VERSION 5.8 ;
BUSBITCHARS "[]" ;
DIVIDERCHAR "/" ;
UNITS
    DATABASE MICRONS 1000 ;
END UNITS

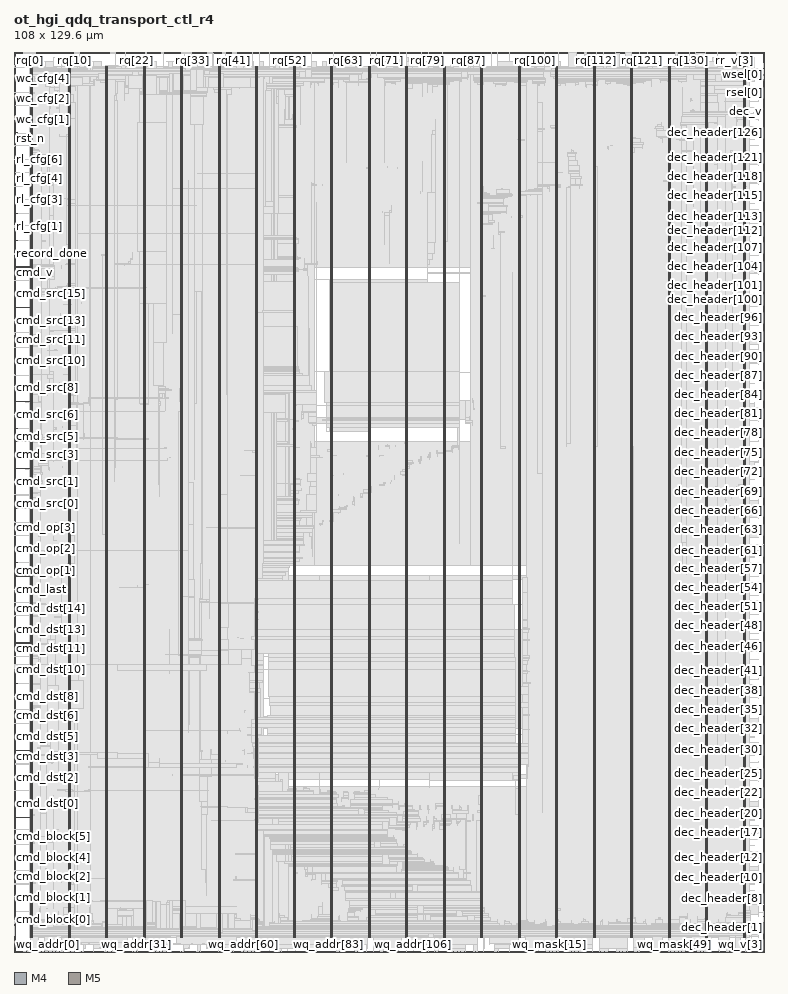
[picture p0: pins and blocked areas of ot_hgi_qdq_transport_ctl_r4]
MACRO ot_hgi_qdq_transport_ctl_r4
  FOREIGN ot_hgi_qdq_transport_ctl_r4 0 0 ;
  CLASS BLOCK ;
  SIZE 108 BY 129.6 ;
  PIN beat_done
    DIRECTION OUTPUT ;
    USE SIGNAL ;
    PORT
      LAYER M4 ;
        RECT  0 1.968 0.084 1.992 ;
    END
    PORT
      LAYER M4 ;
        RECT  0.06 1.968 0.137 2.28 ;
    END
  END beat_done
  PIN clk
    DIRECTION INPUT ;
    USE SIGNAL ;
    PORT
      LAYER M4 ;
        RECT  0 3.888 0.084 3.912 ;
    END
    PORT
      LAYER M4 ;
        RECT  0.06 3.888 0.179 3.912 ;
    END
  END clk
  PIN cmd_block[0]
    DIRECTION INPUT ;
    USE SIGNAL ;
    PORT
      LAYER M4 ;
        RECT  0 5.808 0.084 5.832 ;
    END
    PORT
      LAYER M4 ;
        RECT  0.06 5.808 0.173 5.832 ;
    END
  END cmd_block[0]
  PIN cmd_block[1]
    DIRECTION INPUT ;
    USE SIGNAL ;
    PORT
      LAYER M4 ;
        RECT  0 7.776 0.084 7.8 ;
    END
    PORT
      LAYER M4 ;
        RECT  0.06 7.776 0.137 7.8 ;
    END
  END cmd_block[1]
  PIN cmd_block[2]
    DIRECTION INPUT ;
    USE SIGNAL ;
    PORT
      LAYER M4 ;
        RECT  0 9.696 0.084 9.72 ;
    END
    PORT
      LAYER M4 ;
        RECT  0.06 9.696 0.137 9.72 ;
    END
  END cmd_block[2]
  PIN cmd_block[3]
    DIRECTION INPUT ;
    USE SIGNAL ;
    PORT
      LAYER M4 ;
        RECT  0 11.616 0.084 11.64 ;
    END
    PORT
      LAYER M4 ;
        RECT  0.06 11.616 0.137 11.64 ;
    END
  END cmd_block[3]
  PIN cmd_block[4]
    DIRECTION INPUT ;
    USE SIGNAL ;
    PORT
      LAYER M4 ;
        RECT  0 13.536 0.084 13.56 ;
    END
    PORT
      LAYER M4 ;
        RECT  0.06 13.536 0.137 13.56 ;
    END
  END cmd_block[4]
  PIN cmd_block[5]
    DIRECTION INPUT ;
    USE SIGNAL ;
    PORT
      LAYER M4 ;
        RECT  0 15.504 0.084 15.528 ;
    END
    PORT
      LAYER M4 ;
        RECT  0.06 15.504 0.137 15.528 ;
    END
  END cmd_block[5]
  PIN cmd_block[6]
    DIRECTION INPUT ;
    USE SIGNAL ;
    PORT
      LAYER M4 ;
        RECT  0 17.424 0.084 17.448 ;
    END
    PORT
      LAYER M4 ;
        RECT  0.06 17.424 0.137 17.448 ;
    END
  END cmd_block[6]
  PIN cmd_block[7]
    DIRECTION INPUT ;
    USE SIGNAL ;
    PORT
      LAYER M4 ;
        RECT  0 19.344 0.084 19.368 ;
    END
    PORT
      LAYER M4 ;
        RECT  0.06 19.344 2.408 19.368 ;
    END
  END cmd_block[7]
  PIN cmd_dst[0]
    DIRECTION INPUT ;
    USE SIGNAL ;
    PORT
      LAYER M4 ;
        RECT  0 21.312 0.084 21.336 ;
    END
    PORT
      LAYER M4 ;
        RECT  0.06 21.312 0.137 21.336 ;
    END
  END cmd_dst[0]
  PIN cmd_dst[10]
    DIRECTION INPUT ;
    USE SIGNAL ;
    PORT
      LAYER M4 ;
        RECT  0 40.608 0.084 40.632 ;
    END
    PORT
      LAYER M4 ;
        RECT  0.06 40.608 0.133 40.632 ;
    END
  END cmd_dst[10]
  PIN cmd_dst[11]
    DIRECTION INPUT ;
    USE SIGNAL ;
    PORT
      LAYER M4 ;
        RECT  0 42.576 0.084 42.6 ;
    END
    PORT
      LAYER M4 ;
        RECT  0.06 42.576 0.137 42.6 ;
    END
  END cmd_dst[11]
  PIN cmd_dst[12]
    DIRECTION INPUT ;
    USE SIGNAL ;
    PORT
      LAYER M4 ;
        RECT  0 44.496 0.084 44.52 ;
    END
    PORT
      LAYER M4 ;
        RECT  0.06 44.496 2.408 44.52 ;
    END
  END cmd_dst[12]
  PIN cmd_dst[13]
    DIRECTION INPUT ;
    USE SIGNAL ;
    PORT
      LAYER M4 ;
        RECT  0 46.416 0.084 46.44 ;
    END
    PORT
      LAYER M4 ;
        RECT  0.06 46.416 0.137 46.44 ;
    END
  END cmd_dst[13]
  PIN cmd_dst[14]
    DIRECTION INPUT ;
    USE SIGNAL ;
    PORT
      LAYER M4 ;
        RECT  0 48.336 0.084 48.36 ;
    END
    PORT
      LAYER M4 ;
        RECT  0.06 48.336 0.137 48.36 ;
    END
  END cmd_dst[14]
  PIN cmd_dst[15]
    DIRECTION INPUT ;
    USE SIGNAL ;
    PORT
      LAYER M4 ;
        RECT  0 50.304 0.084 50.328 ;
    END
    PORT
      LAYER M4 ;
        RECT  0.06 50.304 0.137 50.328 ;
    END
  END cmd_dst[15]
  PIN cmd_dst[1]
    DIRECTION INPUT ;
    USE SIGNAL ;
    PORT
      LAYER M4 ;
        RECT  0 23.232 0.084 23.256 ;
    END
    PORT
      LAYER M4 ;
        RECT  0.06 23.232 0.137 23.256 ;
    END
  END cmd_dst[1]
  PIN cmd_dst[2]
    DIRECTION INPUT ;
    USE SIGNAL ;
    PORT
      LAYER M4 ;
        RECT  0 25.152 0.084 25.176 ;
    END
    PORT
      LAYER M4 ;
        RECT  0.06 25.152 0.137 25.176 ;
    END
  END cmd_dst[2]
  PIN cmd_dst[3]
    DIRECTION INPUT ;
    USE SIGNAL ;
    PORT
      LAYER M4 ;
        RECT  0 27.072 0.084 27.096 ;
    END
    PORT
      LAYER M4 ;
        RECT  0.06 27.072 0.137 27.096 ;
    END
  END cmd_dst[3]
  PIN cmd_dst[4]
    DIRECTION INPUT ;
    USE SIGNAL ;
    PORT
      LAYER M4 ;
        RECT  0 29.04 0.084 29.064 ;
    END
    PORT
      LAYER M4 ;
        RECT  0.06 29.04 2.408 29.064 ;
    END
  END cmd_dst[4]
  PIN cmd_dst[5]
    DIRECTION INPUT ;
    USE SIGNAL ;
    PORT
      LAYER M4 ;
        RECT  0 30.96 0.084 30.984 ;
    END
    PORT
      LAYER M4 ;
        RECT  0.06 30.96 0.137 30.984 ;
    END
  END cmd_dst[5]
  PIN cmd_dst[6]
    DIRECTION INPUT ;
    USE SIGNAL ;
    PORT
      LAYER M4 ;
        RECT  0 32.88 0.084 32.904 ;
    END
    PORT
      LAYER M4 ;
        RECT  0.06 32.88 0.137 32.904 ;
    END
  END cmd_dst[6]
  PIN cmd_dst[7]
    DIRECTION INPUT ;
    USE SIGNAL ;
    PORT
      LAYER M4 ;
        RECT  0 34.8 0.084 34.824 ;
    END
    PORT
      LAYER M4 ;
        RECT  0.06 34.8 0.137 34.824 ;
    END
  END cmd_dst[7]
  PIN cmd_dst[8]
    DIRECTION INPUT ;
    USE SIGNAL ;
    PORT
      LAYER M4 ;
        RECT  0 36.768 0.084 36.792 ;
    END
    PORT
      LAYER M4 ;
        RECT  0.06 36.768 0.137 36.792 ;
    END
  END cmd_dst[8]
  PIN cmd_dst[9]
    DIRECTION INPUT ;
    USE SIGNAL ;
    PORT
      LAYER M4 ;
        RECT  0 38.688 0.084 38.712 ;
    END
    PORT
      LAYER M4 ;
        RECT  0.06 38.688 0.569 38.712 ;
    END
  END cmd_dst[9]
  PIN cmd_last
    DIRECTION INPUT ;
    USE SIGNAL ;
    PORT
      LAYER M4 ;
        RECT  0 52.224 0.084 52.248 ;
    END
    PORT
      LAYER M4 ;
        RECT  0.06 52.224 0.137 52.248 ;
    END
  END cmd_last
  PIN cmd_op[0]
    DIRECTION INPUT ;
    USE SIGNAL ;
    PORT
      LAYER M4 ;
        RECT  0 54.144 0.084 54.168 ;
    END
    PORT
      LAYER M4 ;
        RECT  0.06 54.144 2.408 54.168 ;
    END
  END cmd_op[0]
  PIN cmd_op[1]
    DIRECTION INPUT ;
    USE SIGNAL ;
    PORT
      LAYER M4 ;
        RECT  0 56.112 0.084 56.136 ;
    END
    PORT
      LAYER M4 ;
        RECT  0.06 56.112 0.569 56.136 ;
    END
  END cmd_op[1]
  PIN cmd_op[2]
    DIRECTION INPUT ;
    USE SIGNAL ;
    PORT
      LAYER M4 ;
        RECT  0 58.032 0.084 58.056 ;
    END
    PORT
      LAYER M4 ;
        RECT  0.06 58.032 0.137 58.056 ;
    END
  END cmd_op[2]
  PIN cmd_op[3]
    DIRECTION INPUT ;
    USE SIGNAL ;
    PORT
      LAYER M4 ;
        RECT  0 59.952 0.084 59.976 ;
    END
    PORT
      LAYER M4 ;
        RECT  0.06 59.952 0.137 59.976 ;
    END
  END cmd_op[3]
  PIN cmd_op[4]
    DIRECTION INPUT ;
    USE SIGNAL ;
    PORT
      LAYER M4 ;
        RECT  0 61.872 0.084 61.896 ;
    END
    PORT
      LAYER M4 ;
        RECT  0.06 61.872 0.137 61.896 ;
    END
  END cmd_op[4]
  PIN cmd_op[5]
    DIRECTION INPUT ;
    USE SIGNAL ;
    PORT
      LAYER M4 ;
        RECT  0 63.84 0.084 63.864 ;
    END
    PORT
      LAYER M4 ;
        RECT  0.06 63.84 2.408 63.864 ;
    END
  END cmd_op[5]
  PIN cmd_src[0]
    DIRECTION INPUT ;
    USE SIGNAL ;
    PORT
      LAYER M4 ;
        RECT  0 65.76 0.084 65.784 ;
    END
    PORT
      LAYER M4 ;
        RECT  0.06 65.76 0.173 65.784 ;
    END
  END cmd_src[0]
  PIN cmd_src[10]
    DIRECTION INPUT ;
    USE SIGNAL ;
    PORT
      LAYER M4 ;
        RECT  0 85.104 0.084 85.128 ;
    END
    PORT
      LAYER M4 ;
        RECT  0.06 85.104 0.137 85.128 ;
    END
  END cmd_src[10]
  PIN cmd_src[11]
    DIRECTION INPUT ;
    USE SIGNAL ;
    PORT
      LAYER M4 ;
        RECT  0 87.024 0.084 87.048 ;
    END
    PORT
      LAYER M4 ;
        RECT  0.06 87.024 0.137 87.048 ;
    END
  END cmd_src[11]
  PIN cmd_src[12]
    DIRECTION INPUT ;
    USE SIGNAL ;
    PORT
      LAYER M4 ;
        RECT  0 88.944 0.084 88.968 ;
    END
    PORT
      LAYER M4 ;
        RECT  0.06 88.944 0.137 88.968 ;
    END
  END cmd_src[12]
  PIN cmd_src[13]
    DIRECTION INPUT ;
    USE SIGNAL ;
    PORT
      LAYER M4 ;
        RECT  0 90.912 0.084 90.936 ;
    END
    PORT
      LAYER M4 ;
        RECT  0.06 90.912 0.137 90.936 ;
    END
  END cmd_src[13]
  PIN cmd_src[14]
    DIRECTION INPUT ;
    USE SIGNAL ;
    PORT
      LAYER M4 ;
        RECT  0 92.832 0.084 92.856 ;
    END
    PORT
      LAYER M4 ;
        RECT  0.06 92.832 2.408 92.856 ;
    END
  END cmd_src[14]
  PIN cmd_src[15]
    DIRECTION INPUT ;
    USE SIGNAL ;
    PORT
      LAYER M4 ;
        RECT  0 94.752 0.084 94.776 ;
    END
    PORT
      LAYER M4 ;
        RECT  0.06 94.752 0.137 94.776 ;
    END
  END cmd_src[15]
  PIN cmd_src[1]
    DIRECTION INPUT ;
    USE SIGNAL ;
    PORT
      LAYER M4 ;
        RECT  0 67.68 0.084 67.704 ;
    END
    PORT
      LAYER M4 ;
        RECT  0.06 67.68 0.137 67.704 ;
    END
  END cmd_src[1]
  PIN cmd_src[2]
    DIRECTION INPUT ;
    USE SIGNAL ;
    PORT
      LAYER M4 ;
        RECT  0 69.6 0.084 69.624 ;
    END
    PORT
      LAYER M4 ;
        RECT  0.06 69.6 2.365 69.624 ;
    END
  END cmd_src[2]
  PIN cmd_src[3]
    DIRECTION INPUT ;
    USE SIGNAL ;
    PORT
      LAYER M4 ;
        RECT  0 71.568 0.084 71.592 ;
    END
    PORT
      LAYER M4 ;
        RECT  0.06 71.568 0.137 71.592 ;
    END
  END cmd_src[3]
  PIN cmd_src[4]
    DIRECTION INPUT ;
    USE SIGNAL ;
    PORT
      LAYER M4 ;
        RECT  0 73.488 0.084 73.512 ;
    END
    PORT
      LAYER M4 ;
        RECT  0.06 73.488 2.408 73.512 ;
    END
  END cmd_src[4]
  PIN cmd_src[5]
    DIRECTION INPUT ;
    USE SIGNAL ;
    PORT
      LAYER M4 ;
        RECT  0 75.408 0.084 75.432 ;
    END
    PORT
      LAYER M4 ;
        RECT  0.06 75.408 0.569 75.432 ;
    END
  END cmd_src[5]
  PIN cmd_src[6]
    DIRECTION INPUT ;
    USE SIGNAL ;
    PORT
      LAYER M4 ;
        RECT  0 77.376 0.084 77.4 ;
    END
    PORT
      LAYER M4 ;
        RECT  0.06 77.376 0.137 77.4 ;
    END
  END cmd_src[6]
  PIN cmd_src[7]
    DIRECTION INPUT ;
    USE SIGNAL ;
    PORT
      LAYER M4 ;
        RECT  0 79.296 0.084 79.32 ;
    END
    PORT
      LAYER M4 ;
        RECT  0.06 79.296 2.408 79.32 ;
    END
  END cmd_src[7]
  PIN cmd_src[8]
    DIRECTION INPUT ;
    USE SIGNAL ;
    PORT
      LAYER M4 ;
        RECT  0 81.216 0.084 81.24 ;
    END
    PORT
      LAYER M4 ;
        RECT  0.06 81.216 0.137 81.24 ;
    END
  END cmd_src[8]
  PIN cmd_src[9]
    DIRECTION INPUT ;
    USE SIGNAL ;
    PORT
      LAYER M4 ;
        RECT  0 83.136 0.084 83.16 ;
    END
    PORT
      LAYER M4 ;
        RECT  0.06 83.136 0.137 83.16 ;
    END
  END cmd_src[9]
  PIN cmd_v
    DIRECTION INPUT ;
    USE SIGNAL ;
    PORT
      LAYER M4 ;
        RECT  0 96.672 0.084 96.696 ;
    END
    PORT
      LAYER M4 ;
        RECT  0.06 96.672 0.137 96.696 ;
    END
  END cmd_v
  PIN dec_header[0]
    DIRECTION OUTPUT ;
    USE SIGNAL ;
    PORT
      LAYER M4 ;
        RECT  107.916 1.44 108 1.464 ;
    END
  END dec_header[0]
  PIN dec_header[100]
    DIRECTION OUTPUT ;
    USE SIGNAL ;
    PORT
      LAYER M4 ;
        RECT  107.916 93.936 108 93.96 ;
    END
  END dec_header[100]
  PIN dec_header[101]
    DIRECTION OUTPUT ;
    USE SIGNAL ;
    PORT
      LAYER M4 ;
        RECT  107.916 94.848 108 94.872 ;
    END
  END dec_header[101]
  PIN dec_header[102]
    DIRECTION OUTPUT ;
    USE SIGNAL ;
    PORT
      LAYER M4 ;
        RECT  107.916 95.76 108 95.784 ;
    END
  END dec_header[102]
  PIN dec_header[103]
    DIRECTION OUTPUT ;
    USE SIGNAL ;
    PORT
      LAYER M4 ;
        RECT  107.916 96.672 108 96.696 ;
    END
  END dec_header[103]
  PIN dec_header[104]
    DIRECTION OUTPUT ;
    USE SIGNAL ;
    PORT
      LAYER M4 ;
        RECT  107.916 97.632 108 97.656 ;
    END
  END dec_header[104]
  PIN dec_header[105]
    DIRECTION OUTPUT ;
    USE SIGNAL ;
    PORT
      LAYER M4 ;
        RECT  107.916 98.544 108 98.568 ;
    END
  END dec_header[105]
  PIN dec_header[106]
    DIRECTION OUTPUT ;
    USE SIGNAL ;
    PORT
      LAYER M4 ;
        RECT  107.916 99.456 108 99.48 ;
    END
  END dec_header[106]
  PIN dec_header[107]
    DIRECTION OUTPUT ;
    USE SIGNAL ;
    PORT
      LAYER M4 ;
        RECT  107.916 100.368 108 100.392 ;
    END
  END dec_header[107]
  PIN dec_header[108]
    DIRECTION OUTPUT ;
    USE SIGNAL ;
    PORT
      LAYER M4 ;
        RECT  107.916 101.328 108 101.352 ;
    END
  END dec_header[108]
  PIN dec_header[109]
    DIRECTION OUTPUT ;
    USE SIGNAL ;
    PORT
      LAYER M4 ;
        RECT  107.916 102.24 108 102.264 ;
    END
  END dec_header[109]
  PIN dec_header[10]
    DIRECTION OUTPUT ;
    USE SIGNAL ;
    PORT
      LAYER M4 ;
        RECT  107.916 10.704 108 10.728 ;
    END
  END dec_header[10]
  PIN dec_header[110]
    DIRECTION OUTPUT ;
    USE SIGNAL ;
    PORT
      LAYER M4 ;
        RECT  107.916 103.152 108 103.176 ;
    END
  END dec_header[110]
  PIN dec_header[111]
    DIRECTION OUTPUT ;
    USE SIGNAL ;
    PORT
      LAYER M4 ;
        RECT  107.916 104.064 108 104.088 ;
    END
  END dec_header[111]
  PIN dec_header[112]
    DIRECTION OUTPUT ;
    USE SIGNAL ;
    PORT
      LAYER M4 ;
        RECT  107.916 105.024 108 105.048 ;
    END
  END dec_header[112]
  PIN dec_header[113]
    DIRECTION OUTPUT ;
    USE SIGNAL ;
    PORT
      LAYER M4 ;
        RECT  107.916 105.936 108 105.96 ;
    END
  END dec_header[113]
  PIN dec_header[114]
    DIRECTION OUTPUT ;
    USE SIGNAL ;
    PORT
      LAYER M4 ;
        RECT  107.916 106.848 108 106.872 ;
    END
  END dec_header[114]
  PIN dec_header[115]
    DIRECTION OUTPUT ;
    USE SIGNAL ;
    PORT
      LAYER M4 ;
        RECT  107.916 107.808 108 107.832 ;
    END
  END dec_header[115]
  PIN dec_header[116]
    DIRECTION OUTPUT ;
    USE SIGNAL ;
    PORT
      LAYER M4 ;
        RECT  107.916 108.72 108 108.744 ;
    END
  END dec_header[116]
  PIN dec_header[117]
    DIRECTION OUTPUT ;
    USE SIGNAL ;
    PORT
      LAYER M4 ;
        RECT  107.916 109.632 108 109.656 ;
    END
  END dec_header[117]
  PIN dec_header[118]
    DIRECTION OUTPUT ;
    USE SIGNAL ;
    PORT
      LAYER M4 ;
        RECT  107.916 110.544 108 110.568 ;
    END
  END dec_header[118]
  PIN dec_header[119]
    DIRECTION OUTPUT ;
    USE SIGNAL ;
    PORT
      LAYER M4 ;
        RECT  107.916 111.504 108 111.528 ;
    END
  END dec_header[119]
  PIN dec_header[11]
    DIRECTION OUTPUT ;
    USE SIGNAL ;
    PORT
      LAYER M4 ;
        RECT  107.916 11.616 108 11.64 ;
    END
  END dec_header[11]
  PIN dec_header[120]
    DIRECTION OUTPUT ;
    USE SIGNAL ;
    PORT
      LAYER M4 ;
        RECT  107.916 112.416 108 112.44 ;
    END
  END dec_header[120]
  PIN dec_header[121]
    DIRECTION OUTPUT ;
    USE SIGNAL ;
    PORT
      LAYER M4 ;
        RECT  107.916 113.328 108 113.352 ;
    END
  END dec_header[121]
  PIN dec_header[122]
    DIRECTION OUTPUT ;
    USE SIGNAL ;
    PORT
      LAYER M4 ;
        RECT  107.916 114.24 108 114.264 ;
    END
  END dec_header[122]
  PIN dec_header[123]
    DIRECTION OUTPUT ;
    USE SIGNAL ;
    PORT
      LAYER M4 ;
        RECT  107.916 115.2 108 115.224 ;
    END
  END dec_header[123]
  PIN dec_header[124]
    DIRECTION OUTPUT ;
    USE SIGNAL ;
    PORT
      LAYER M4 ;
        RECT  107.916 116.112 108 116.136 ;
    END
  END dec_header[124]
  PIN dec_header[125]
    DIRECTION OUTPUT ;
    USE SIGNAL ;
    PORT
      LAYER M4 ;
        RECT  107.916 117.024 108 117.048 ;
    END
  END dec_header[125]
  PIN dec_header[126]
    DIRECTION OUTPUT ;
    USE SIGNAL ;
    PORT
      LAYER M4 ;
        RECT  107.916 117.936 108 117.96 ;
    END
  END dec_header[126]
  PIN dec_header[127]
    DIRECTION OUTPUT ;
    USE SIGNAL ;
    PORT
      LAYER M4 ;
        RECT  107.916 118.896 108 118.92 ;
    END
  END dec_header[127]
  PIN dec_header[12]
    DIRECTION OUTPUT ;
    USE SIGNAL ;
    PORT
      LAYER M4 ;
        RECT  107.916 12.528 108 12.552 ;
    END
  END dec_header[12]
  PIN dec_header[13]
    DIRECTION OUTPUT ;
    USE SIGNAL ;
    PORT
      LAYER M4 ;
        RECT  107.916 13.488 108 13.512 ;
    END
  END dec_header[13]
  PIN dec_header[14]
    DIRECTION OUTPUT ;
    USE SIGNAL ;
    PORT
      LAYER M4 ;
        RECT  107.916 14.4 108 14.424 ;
    END
  END dec_header[14]
  PIN dec_header[15]
    DIRECTION OUTPUT ;
    USE SIGNAL ;
    PORT
      LAYER M4 ;
        RECT  107.916 15.312 108 15.336 ;
    END
  END dec_header[15]
  PIN dec_header[16]
    DIRECTION OUTPUT ;
    USE SIGNAL ;
    PORT
      LAYER M4 ;
        RECT  107.916 16.224 108 16.248 ;
    END
  END dec_header[16]
  PIN dec_header[17]
    DIRECTION OUTPUT ;
    USE SIGNAL ;
    PORT
      LAYER M4 ;
        RECT  107.916 17.184 108 17.208 ;
    END
  END dec_header[17]
  PIN dec_header[18]
    DIRECTION OUTPUT ;
    USE SIGNAL ;
    PORT
      LAYER M4 ;
        RECT  107.916 18.096 108 18.12 ;
    END
  END dec_header[18]
  PIN dec_header[19]
    DIRECTION OUTPUT ;
    USE SIGNAL ;
    PORT
      LAYER M4 ;
        RECT  107.916 19.008 108 19.032 ;
    END
  END dec_header[19]
  PIN dec_header[1]
    DIRECTION OUTPUT ;
    USE SIGNAL ;
    PORT
      LAYER M4 ;
        RECT  107.916 2.352 108 2.376 ;
    END
  END dec_header[1]
  PIN dec_header[20]
    DIRECTION OUTPUT ;
    USE SIGNAL ;
    PORT
      LAYER M4 ;
        RECT  107.916 19.92 108 19.944 ;
    END
  END dec_header[20]
  PIN dec_header[21]
    DIRECTION OUTPUT ;
    USE SIGNAL ;
    PORT
      LAYER M4 ;
        RECT  107.916 20.88 108 20.904 ;
    END
  END dec_header[21]
  PIN dec_header[22]
    DIRECTION OUTPUT ;
    USE SIGNAL ;
    PORT
      LAYER M4 ;
        RECT  107.916 21.792 108 21.816 ;
    END
  END dec_header[22]
  PIN dec_header[23]
    DIRECTION OUTPUT ;
    USE SIGNAL ;
    PORT
      LAYER M4 ;
        RECT  107.916 22.704 108 22.728 ;
    END
  END dec_header[23]
  PIN dec_header[24]
    DIRECTION OUTPUT ;
    USE SIGNAL ;
    PORT
      LAYER M4 ;
        RECT  107.916 23.664 108 23.688 ;
    END
  END dec_header[24]
  PIN dec_header[25]
    DIRECTION OUTPUT ;
    USE SIGNAL ;
    PORT
      LAYER M4 ;
        RECT  107.916 24.576 108 24.6 ;
    END
  END dec_header[25]
  PIN dec_header[26]
    DIRECTION OUTPUT ;
    USE SIGNAL ;
    PORT
      LAYER M4 ;
        RECT  107.916 25.488 108 25.512 ;
    END
  END dec_header[26]
  PIN dec_header[27]
    DIRECTION OUTPUT ;
    USE SIGNAL ;
    PORT
      LAYER M4 ;
        RECT  107.916 26.4 108 26.424 ;
    END
  END dec_header[27]
  PIN dec_header[28]
    DIRECTION OUTPUT ;
    USE SIGNAL ;
    PORT
      LAYER M4 ;
        RECT  107.916 27.36 108 27.384 ;
    END
  END dec_header[28]
  PIN dec_header[29]
    DIRECTION OUTPUT ;
    USE SIGNAL ;
    PORT
      LAYER M4 ;
        RECT  107.916 28.272 108 28.296 ;
    END
  END dec_header[29]
  PIN dec_header[2]
    DIRECTION OUTPUT ;
    USE SIGNAL ;
    PORT
      LAYER M4 ;
        RECT  107.916 3.312 108 3.336 ;
    END
  END dec_header[2]
  PIN dec_header[30]
    DIRECTION OUTPUT ;
    USE SIGNAL ;
    PORT
      LAYER M4 ;
        RECT  107.916 29.184 108 29.208 ;
    END
  END dec_header[30]
  PIN dec_header[31]
    DIRECTION OUTPUT ;
    USE SIGNAL ;
    PORT
      LAYER M4 ;
        RECT  107.916 30.096 108 30.12 ;
    END
  END dec_header[31]
  PIN dec_header[32]
    DIRECTION OUTPUT ;
    USE SIGNAL ;
    PORT
      LAYER M4 ;
        RECT  107.916 31.056 108 31.08 ;
    END
  END dec_header[32]
  PIN dec_header[33]
    DIRECTION OUTPUT ;
    USE SIGNAL ;
    PORT
      LAYER M4 ;
        RECT  107.916 31.968 108 31.992 ;
    END
  END dec_header[33]
  PIN dec_header[34]
    DIRECTION OUTPUT ;
    USE SIGNAL ;
    PORT
      LAYER M4 ;
        RECT  107.916 32.88 108 32.904 ;
    END
  END dec_header[34]
  PIN dec_header[35]
    DIRECTION OUTPUT ;
    USE SIGNAL ;
    PORT
      LAYER M4 ;
        RECT  107.916 33.792 108 33.816 ;
    END
  END dec_header[35]
  PIN dec_header[36]
    DIRECTION OUTPUT ;
    USE SIGNAL ;
    PORT
      LAYER M4 ;
        RECT  107.916 34.752 108 34.776 ;
    END
  END dec_header[36]
  PIN dec_header[37]
    DIRECTION OUTPUT ;
    USE SIGNAL ;
    PORT
      LAYER M4 ;
        RECT  107.916 35.664 108 35.688 ;
    END
  END dec_header[37]
  PIN dec_header[38]
    DIRECTION OUTPUT ;
    USE SIGNAL ;
    PORT
      LAYER M4 ;
        RECT  107.916 36.576 108 36.6 ;
    END
  END dec_header[38]
  PIN dec_header[39]
    DIRECTION OUTPUT ;
    USE SIGNAL ;
    PORT
      LAYER M4 ;
        RECT  107.916 37.488 108 37.512 ;
    END
  END dec_header[39]
  PIN dec_header[3]
    DIRECTION OUTPUT ;
    USE SIGNAL ;
    PORT
      LAYER M4 ;
        RECT  107.916 4.224 108 4.248 ;
    END
  END dec_header[3]
  PIN dec_header[40]
    DIRECTION OUTPUT ;
    USE SIGNAL ;
    PORT
      LAYER M4 ;
        RECT  107.916 38.448 108 38.472 ;
    END
  END dec_header[40]
  PIN dec_header[41]
    DIRECTION OUTPUT ;
    USE SIGNAL ;
    PORT
      LAYER M4 ;
        RECT  107.916 39.36 108 39.384 ;
    END
  END dec_header[41]
  PIN dec_header[42]
    DIRECTION OUTPUT ;
    USE SIGNAL ;
    PORT
      LAYER M4 ;
        RECT  107.916 40.272 108 40.296 ;
    END
  END dec_header[42]
  PIN dec_header[43]
    DIRECTION OUTPUT ;
    USE SIGNAL ;
    PORT
      LAYER M4 ;
        RECT  107.916 41.232 108 41.256 ;
    END
  END dec_header[43]
  PIN dec_header[44]
    DIRECTION OUTPUT ;
    USE SIGNAL ;
    PORT
      LAYER M4 ;
        RECT  107.916 42.144 108 42.168 ;
    END
  END dec_header[44]
  PIN dec_header[45]
    DIRECTION OUTPUT ;
    USE SIGNAL ;
    PORT
      LAYER M4 ;
        RECT  107.916 43.056 108 43.08 ;
    END
  END dec_header[45]
  PIN dec_header[46]
    DIRECTION OUTPUT ;
    USE SIGNAL ;
    PORT
      LAYER M4 ;
        RECT  107.916 43.968 108 43.992 ;
    END
  END dec_header[46]
  PIN dec_header[47]
    DIRECTION OUTPUT ;
    USE SIGNAL ;
    PORT
      LAYER M4 ;
        RECT  107.916 44.928 108 44.952 ;
    END
  END dec_header[47]
  PIN dec_header[48]
    DIRECTION OUTPUT ;
    USE SIGNAL ;
    PORT
      LAYER M4 ;
        RECT  107.916 45.84 108 45.864 ;
    END
  END dec_header[48]
  PIN dec_header[49]
    DIRECTION OUTPUT ;
    USE SIGNAL ;
    PORT
      LAYER M4 ;
        RECT  107.916 46.752 108 46.776 ;
    END
  END dec_header[49]
  PIN dec_header[4]
    DIRECTION OUTPUT ;
    USE SIGNAL ;
    PORT
      LAYER M4 ;
        RECT  107.916 5.136 108 5.16 ;
    END
  END dec_header[4]
  PIN dec_header[50]
    DIRECTION OUTPUT ;
    USE SIGNAL ;
    PORT
      LAYER M4 ;
        RECT  107.916 47.664 108 47.688 ;
    END
  END dec_header[50]
  PIN dec_header[51]
    DIRECTION OUTPUT ;
    USE SIGNAL ;
    PORT
      LAYER M4 ;
        RECT  107.916 48.624 108 48.648 ;
    END
  END dec_header[51]
  PIN dec_header[52]
    DIRECTION OUTPUT ;
    USE SIGNAL ;
    PORT
      LAYER M4 ;
        RECT  107.916 49.536 108 49.56 ;
    END
  END dec_header[52]
  PIN dec_header[53]
    DIRECTION OUTPUT ;
    USE SIGNAL ;
    PORT
      LAYER M4 ;
        RECT  107.916 50.448 108 50.472 ;
    END
  END dec_header[53]
  PIN dec_header[54]
    DIRECTION OUTPUT ;
    USE SIGNAL ;
    PORT
      LAYER M4 ;
        RECT  107.916 51.36 108 51.384 ;
    END
  END dec_header[54]
  PIN dec_header[55]
    DIRECTION OUTPUT ;
    USE SIGNAL ;
    PORT
      LAYER M4 ;
        RECT  107.916 52.32 108 52.344 ;
    END
  END dec_header[55]
  PIN dec_header[56]
    DIRECTION OUTPUT ;
    USE SIGNAL ;
    PORT
      LAYER M4 ;
        RECT  107.916 53.232 108 53.256 ;
    END
  END dec_header[56]
  PIN dec_header[57]
    DIRECTION OUTPUT ;
    USE SIGNAL ;
    PORT
      LAYER M4 ;
        RECT  107.916 54.144 108 54.168 ;
    END
  END dec_header[57]
  PIN dec_header[58]
    DIRECTION OUTPUT ;
    USE SIGNAL ;
    PORT
      LAYER M4 ;
        RECT  107.916 55.056 108 55.08 ;
    END
  END dec_header[58]
  PIN dec_header[59]
    DIRECTION OUTPUT ;
    USE SIGNAL ;
    PORT
      LAYER M4 ;
        RECT  107.916 56.016 108 56.04 ;
    END
  END dec_header[59]
  PIN dec_header[5]
    DIRECTION OUTPUT ;
    USE SIGNAL ;
    PORT
      LAYER M4 ;
        RECT  107.916 6.096 108 6.12 ;
    END
  END dec_header[5]
  PIN dec_header[60]
    DIRECTION OUTPUT ;
    USE SIGNAL ;
    PORT
      LAYER M4 ;
        RECT  107.916 56.928 108 56.952 ;
    END
  END dec_header[60]
  PIN dec_header[61]
    DIRECTION OUTPUT ;
    USE SIGNAL ;
    PORT
      LAYER M4 ;
        RECT  107.916 57.84 108 57.864 ;
    END
  END dec_header[61]
  PIN dec_header[62]
    DIRECTION OUTPUT ;
    USE SIGNAL ;
    PORT
      LAYER M4 ;
        RECT  107.916 58.8 108 58.824 ;
    END
  END dec_header[62]
  PIN dec_header[63]
    DIRECTION OUTPUT ;
    USE SIGNAL ;
    PORT
      LAYER M4 ;
        RECT  107.916 59.712 108 59.736 ;
    END
  END dec_header[63]
  PIN dec_header[64]
    DIRECTION OUTPUT ;
    USE SIGNAL ;
    PORT
      LAYER M4 ;
        RECT  107.916 60.624 108 60.648 ;
    END
  END dec_header[64]
  PIN dec_header[65]
    DIRECTION OUTPUT ;
    USE SIGNAL ;
    PORT
      LAYER M4 ;
        RECT  107.916 61.536 108 61.56 ;
    END
  END dec_header[65]
  PIN dec_header[66]
    DIRECTION OUTPUT ;
    USE SIGNAL ;
    PORT
      LAYER M4 ;
        RECT  107.916 62.496 108 62.52 ;
    END
  END dec_header[66]
  PIN dec_header[67]
    DIRECTION OUTPUT ;
    USE SIGNAL ;
    PORT
      LAYER M4 ;
        RECT  107.916 63.408 108 63.432 ;
    END
  END dec_header[67]
  PIN dec_header[68]
    DIRECTION OUTPUT ;
    USE SIGNAL ;
    PORT
      LAYER M4 ;
        RECT  107.916 64.32 108 64.344 ;
    END
  END dec_header[68]
  PIN dec_header[69]
    DIRECTION OUTPUT ;
    USE SIGNAL ;
    PORT
      LAYER M4 ;
        RECT  107.916 65.232 108 65.256 ;
    END
  END dec_header[69]
  PIN dec_header[6]
    DIRECTION OUTPUT ;
    USE SIGNAL ;
    PORT
      LAYER M4 ;
        RECT  107.916 7.008 108 7.032 ;
    END
  END dec_header[6]
  PIN dec_header[70]
    DIRECTION OUTPUT ;
    USE SIGNAL ;
    PORT
      LAYER M4 ;
        RECT  107.916 66.192 108 66.216 ;
    END
  END dec_header[70]
  PIN dec_header[71]
    DIRECTION OUTPUT ;
    USE SIGNAL ;
    PORT
      LAYER M4 ;
        RECT  107.916 67.104 108 67.128 ;
    END
  END dec_header[71]
  PIN dec_header[72]
    DIRECTION OUTPUT ;
    USE SIGNAL ;
    PORT
      LAYER M4 ;
        RECT  107.916 68.016 108 68.04 ;
    END
  END dec_header[72]
  PIN dec_header[73]
    DIRECTION OUTPUT ;
    USE SIGNAL ;
    PORT
      LAYER M4 ;
        RECT  107.916 68.928 108 68.952 ;
    END
  END dec_header[73]
  PIN dec_header[74]
    DIRECTION OUTPUT ;
    USE SIGNAL ;
    PORT
      LAYER M4 ;
        RECT  107.916 69.888 108 69.912 ;
    END
  END dec_header[74]
  PIN dec_header[75]
    DIRECTION OUTPUT ;
    USE SIGNAL ;
    PORT
      LAYER M4 ;
        RECT  107.916 70.8 108 70.824 ;
    END
  END dec_header[75]
  PIN dec_header[76]
    DIRECTION OUTPUT ;
    USE SIGNAL ;
    PORT
      LAYER M4 ;
        RECT  107.916 71.712 108 71.736 ;
    END
  END dec_header[76]
  PIN dec_header[77]
    DIRECTION OUTPUT ;
    USE SIGNAL ;
    PORT
      LAYER M4 ;
        RECT  107.916 72.624 108 72.648 ;
    END
  END dec_header[77]
  PIN dec_header[78]
    DIRECTION OUTPUT ;
    USE SIGNAL ;
    PORT
      LAYER M4 ;
        RECT  107.916 73.584 108 73.608 ;
    END
  END dec_header[78]
  PIN dec_header[79]
    DIRECTION OUTPUT ;
    USE SIGNAL ;
    PORT
      LAYER M4 ;
        RECT  107.916 74.496 108 74.52 ;
    END
  END dec_header[79]
  PIN dec_header[7]
    DIRECTION OUTPUT ;
    USE SIGNAL ;
    PORT
      LAYER M4 ;
        RECT  107.916 7.92 108 7.944 ;
    END
  END dec_header[7]
  PIN dec_header[80]
    DIRECTION OUTPUT ;
    USE SIGNAL ;
    PORT
      LAYER M4 ;
        RECT  107.916 75.408 108 75.432 ;
    END
  END dec_header[80]
  PIN dec_header[81]
    DIRECTION OUTPUT ;
    USE SIGNAL ;
    PORT
      LAYER M4 ;
        RECT  107.916 76.368 108 76.392 ;
    END
  END dec_header[81]
  PIN dec_header[82]
    DIRECTION OUTPUT ;
    USE SIGNAL ;
    PORT
      LAYER M4 ;
        RECT  107.916 77.28 108 77.304 ;
    END
  END dec_header[82]
  PIN dec_header[83]
    DIRECTION OUTPUT ;
    USE SIGNAL ;
    PORT
      LAYER M4 ;
        RECT  107.916 78.192 108 78.216 ;
    END
  END dec_header[83]
  PIN dec_header[84]
    DIRECTION OUTPUT ;
    USE SIGNAL ;
    PORT
      LAYER M4 ;
        RECT  107.916 79.104 108 79.128 ;
    END
  END dec_header[84]
  PIN dec_header[85]
    DIRECTION OUTPUT ;
    USE SIGNAL ;
    PORT
      LAYER M4 ;
        RECT  107.916 80.064 108 80.088 ;
    END
  END dec_header[85]
  PIN dec_header[86]
    DIRECTION OUTPUT ;
    USE SIGNAL ;
    PORT
      LAYER M4 ;
        RECT  107.916 80.976 108 81 ;
    END
  END dec_header[86]
  PIN dec_header[87]
    DIRECTION OUTPUT ;
    USE SIGNAL ;
    PORT
      LAYER M4 ;
        RECT  107.916 81.888 108 81.912 ;
    END
  END dec_header[87]
  PIN dec_header[88]
    DIRECTION OUTPUT ;
    USE SIGNAL ;
    PORT
      LAYER M4 ;
        RECT  107.916 82.8 108 82.824 ;
    END
  END dec_header[88]
  PIN dec_header[89]
    DIRECTION OUTPUT ;
    USE SIGNAL ;
    PORT
      LAYER M4 ;
        RECT  107.916 83.76 108 83.784 ;
    END
  END dec_header[89]
  PIN dec_header[8]
    DIRECTION OUTPUT ;
    USE SIGNAL ;
    PORT
      LAYER M4 ;
        RECT  107.916 8.832 108 8.856 ;
    END
  END dec_header[8]
  PIN dec_header[90]
    DIRECTION OUTPUT ;
    USE SIGNAL ;
    PORT
      LAYER M4 ;
        RECT  107.916 84.672 108 84.696 ;
    END
  END dec_header[90]
  PIN dec_header[91]
    DIRECTION OUTPUT ;
    USE SIGNAL ;
    PORT
      LAYER M4 ;
        RECT  107.916 85.584 108 85.608 ;
    END
  END dec_header[91]
  PIN dec_header[92]
    DIRECTION OUTPUT ;
    USE SIGNAL ;
    PORT
      LAYER M4 ;
        RECT  107.916 86.496 108 86.52 ;
    END
  END dec_header[92]
  PIN dec_header[93]
    DIRECTION OUTPUT ;
    USE SIGNAL ;
    PORT
      LAYER M4 ;
        RECT  107.916 87.456 108 87.48 ;
    END
  END dec_header[93]
  PIN dec_header[94]
    DIRECTION OUTPUT ;
    USE SIGNAL ;
    PORT
      LAYER M4 ;
        RECT  107.916 88.368 108 88.392 ;
    END
  END dec_header[94]
  PIN dec_header[95]
    DIRECTION OUTPUT ;
    USE SIGNAL ;
    PORT
      LAYER M4 ;
        RECT  107.916 89.28 108 89.304 ;
    END
  END dec_header[95]
  PIN dec_header[96]
    DIRECTION OUTPUT ;
    USE SIGNAL ;
    PORT
      LAYER M4 ;
        RECT  107.916 90.24 108 90.264 ;
    END
  END dec_header[96]
  PIN dec_header[97]
    DIRECTION OUTPUT ;
    USE SIGNAL ;
    PORT
      LAYER M4 ;
        RECT  107.916 91.152 108 91.176 ;
    END
  END dec_header[97]
  PIN dec_header[98]
    DIRECTION OUTPUT ;
    USE SIGNAL ;
    PORT
      LAYER M4 ;
        RECT  107.916 92.064 108 92.088 ;
    END
  END dec_header[98]
  PIN dec_header[99]
    DIRECTION OUTPUT ;
    USE SIGNAL ;
    PORT
      LAYER M4 ;
        RECT  107.916 92.976 108 93 ;
    END
  END dec_header[99]
  PIN dec_header[9]
    DIRECTION OUTPUT ;
    USE SIGNAL ;
    PORT
      LAYER M4 ;
        RECT  107.916 9.792 108 9.816 ;
    END
  END dec_header[9]
  PIN dec_v
    DIRECTION OUTPUT ;
    USE SIGNAL ;
    PORT
      LAYER M4 ;
        RECT  107.916 119.808 108 119.832 ;
    END
  END dec_v
  PIN decode_fault
    DIRECTION INPUT ;
    USE SIGNAL ;
    PORT
      LAYER M4 ;
        RECT  107.916 120.72 108 120.744 ;
    END
  END decode_fault
  PIN fault
    DIRECTION OUTPUT ;
    USE SIGNAL ;
    PORT
      LAYER M4 ;
        RECT  0 98.64 0.084 98.664 ;
    END
    PORT
      LAYER M4 ;
        RECT  0.06 98.64 2.408 98.664 ;
    END
  END fault
  PIN qfault
    DIRECTION INPUT ;
    USE SIGNAL ;
    PORT
      LAYER M4 ;
        RECT  107.916 121.632 108 121.656 ;
    END
  END qfault
  PIN record_done
    DIRECTION OUTPUT ;
    USE SIGNAL ;
    PORT
      LAYER M4 ;
        RECT  0 100.56 0.084 100.584 ;
    END
    PORT
      LAYER M4 ;
        RECT  0.06 100.56 0.137 100.584 ;
    END
  END record_done
  PIN rl_cfg[0]
    DIRECTION INPUT ;
    USE SIGNAL ;
    PORT
      LAYER M4 ;
        RECT  0 102.48 0.084 102.504 ;
    END
    PORT
      LAYER M4 ;
        RECT  0.06 102.48 0.569 102.504 ;
    END
  END rl_cfg[0]
  PIN rl_cfg[1]
    DIRECTION INPUT ;
    USE SIGNAL ;
    PORT
      LAYER M4 ;
        RECT  0 104.4 0.084 104.424 ;
    END
    PORT
      LAYER M4 ;
        RECT  0.06 104.4 0.137 104.424 ;
    END
  END rl_cfg[1]
  PIN rl_cfg[2]
    DIRECTION INPUT ;
    USE SIGNAL ;
    PORT
      LAYER M4 ;
        RECT  0 106.368 0.084 106.392 ;
    END
    PORT
      LAYER M4 ;
        RECT  0.06 106.368 0.569 106.392 ;
    END
  END rl_cfg[2]
  PIN rl_cfg[3]
    DIRECTION INPUT ;
    USE SIGNAL ;
    PORT
      LAYER M4 ;
        RECT  0 108.288 0.084 108.312 ;
    END
    PORT
      LAYER M4 ;
        RECT  0.06 108.288 0.137 108.312 ;
    END
  END rl_cfg[3]
  PIN rl_cfg[4]
    DIRECTION INPUT ;
    USE SIGNAL ;
    PORT
      LAYER M4 ;
        RECT  0 110.208 0.084 110.232 ;
    END
    PORT
      LAYER M4 ;
        RECT  0.06 110.208 0.137 110.232 ;
    END
  END rl_cfg[4]
  PIN rl_cfg[5]
    DIRECTION INPUT ;
    USE SIGNAL ;
    PORT
      LAYER M4 ;
        RECT  0 112.176 0.084 112.2 ;
    END
    PORT
      LAYER M4 ;
        RECT  0.06 112.176 0.137 112.2 ;
    END
  END rl_cfg[5]
  PIN rl_cfg[6]
    DIRECTION INPUT ;
    USE SIGNAL ;
    PORT
      LAYER M4 ;
        RECT  0 114.096 0.084 114.12 ;
    END
    PORT
      LAYER M4 ;
        RECT  0.06 114.096 0.137 114.12 ;
    END
  END rl_cfg[6]
  PIN rq[0]
    DIRECTION OUTPUT ;
    USE SIGNAL ;
    PORT
      LAYER M5 ;
        RECT  1.344 129.516 1.368 129.6 ;
    END
  END rq[0]
  PIN rq[100]
    DIRECTION OUTPUT ;
    USE SIGNAL ;
    PORT
      LAYER M5 ;
        RECT  74.976 129.516 75 129.6 ;
    END
  END rq[100]
  PIN rq[101]
    DIRECTION OUTPUT ;
    USE SIGNAL ;
    PORT
      LAYER M5 ;
        RECT  75.696 129.516 75.72 129.6 ;
    END
  END rq[101]
  PIN rq[102]
    DIRECTION OUTPUT ;
    USE SIGNAL ;
    PORT
      LAYER M5 ;
        RECT  76.416 129.516 76.44 129.6 ;
    END
  END rq[102]
  PIN rq[103]
    DIRECTION OUTPUT ;
    USE SIGNAL ;
    PORT
      LAYER M5 ;
        RECT  77.184 129.516 77.208 129.6 ;
    END
  END rq[103]
  PIN rq[104]
    DIRECTION OUTPUT ;
    USE SIGNAL ;
    PORT
      LAYER M5 ;
        RECT  77.904 129.516 77.928 129.6 ;
    END
  END rq[104]
  PIN rq[105]
    DIRECTION OUTPUT ;
    USE SIGNAL ;
    PORT
      LAYER M5 ;
        RECT  78.672 129.516 78.696 129.6 ;
    END
  END rq[105]
  PIN rq[106]
    DIRECTION OUTPUT ;
    USE SIGNAL ;
    PORT
      LAYER M5 ;
        RECT  79.392 129.516 79.416 129.6 ;
    END
  END rq[106]
  PIN rq[107]
    DIRECTION OUTPUT ;
    USE SIGNAL ;
    PORT
      LAYER M5 ;
        RECT  80.112 129.516 80.136 129.6 ;
    END
  END rq[107]
  PIN rq[108]
    DIRECTION OUTPUT ;
    USE SIGNAL ;
    PORT
      LAYER M5 ;
        RECT  80.88 129.516 80.904 129.6 ;
    END
  END rq[108]
  PIN rq[109]
    DIRECTION OUTPUT ;
    USE SIGNAL ;
    PORT
      LAYER M5 ;
        RECT  81.6 129.516 81.624 129.6 ;
    END
  END rq[109]
  PIN rq[10]
    DIRECTION OUTPUT ;
    USE SIGNAL ;
    PORT
      LAYER M5 ;
        RECT  8.736 129.516 8.76 129.6 ;
    END
  END rq[10]
  PIN rq[110]
    DIRECTION OUTPUT ;
    USE SIGNAL ;
    PORT
      LAYER M5 ;
        RECT  82.32 129.516 82.344 129.6 ;
    END
  END rq[110]
  PIN rq[111]
    DIRECTION OUTPUT ;
    USE SIGNAL ;
    PORT
      LAYER M5 ;
        RECT  83.088 129.516 83.112 129.6 ;
    END
  END rq[111]
  PIN rq[112]
    DIRECTION OUTPUT ;
    USE SIGNAL ;
    PORT
      LAYER M5 ;
        RECT  83.808 129.516 83.832 129.6 ;
    END
  END rq[112]
  PIN rq[113]
    DIRECTION OUTPUT ;
    USE SIGNAL ;
    PORT
      LAYER M5 ;
        RECT  84.528 129.516 84.552 129.6 ;
    END
  END rq[113]
  PIN rq[114]
    DIRECTION OUTPUT ;
    USE SIGNAL ;
    PORT
      LAYER M5 ;
        RECT  85.296 129.516 85.32 129.6 ;
    END
  END rq[114]
  PIN rq[115]
    DIRECTION OUTPUT ;
    USE SIGNAL ;
    PORT
      LAYER M5 ;
        RECT  86.016 129.516 86.04 129.6 ;
    END
  END rq[115]
  PIN rq[116]
    DIRECTION OUTPUT ;
    USE SIGNAL ;
    PORT
      LAYER M5 ;
        RECT  86.736 129.516 86.76 129.6 ;
    END
  END rq[116]
  PIN rq[117]
    DIRECTION OUTPUT ;
    USE SIGNAL ;
    PORT
      LAYER M5 ;
        RECT  87.504 129.516 87.528 129.6 ;
    END
  END rq[117]
  PIN rq[118]
    DIRECTION OUTPUT ;
    USE SIGNAL ;
    PORT
      LAYER M5 ;
        RECT  88.224 129.516 88.248 129.6 ;
    END
  END rq[118]
  PIN rq[119]
    DIRECTION OUTPUT ;
    USE SIGNAL ;
    PORT
      LAYER M5 ;
        RECT  88.944 129.516 88.968 129.6 ;
    END
  END rq[119]
  PIN rq[11]
    DIRECTION OUTPUT ;
    USE SIGNAL ;
    PORT
      LAYER M5 ;
        RECT  9.456 129.516 9.48 129.6 ;
    END
  END rq[11]
  PIN rq[120]
    DIRECTION OUTPUT ;
    USE SIGNAL ;
    PORT
      LAYER M5 ;
        RECT  89.712 129.516 89.736 129.6 ;
    END
  END rq[120]
  PIN rq[121]
    DIRECTION OUTPUT ;
    USE SIGNAL ;
    PORT
      LAYER M5 ;
        RECT  90.432 129.516 90.456 129.6 ;
    END
  END rq[121]
  PIN rq[122]
    DIRECTION OUTPUT ;
    USE SIGNAL ;
    PORT
      LAYER M5 ;
        RECT  91.152 129.516 91.176 129.6 ;
    END
  END rq[122]
  PIN rq[123]
    DIRECTION OUTPUT ;
    USE SIGNAL ;
    PORT
      LAYER M5 ;
        RECT  91.92 129.516 91.944 129.6 ;
    END
  END rq[123]
  PIN rq[124]
    DIRECTION OUTPUT ;
    USE SIGNAL ;
    PORT
      LAYER M5 ;
        RECT  92.64 129.516 92.664 129.6 ;
    END
  END rq[124]
  PIN rq[125]
    DIRECTION OUTPUT ;
    USE SIGNAL ;
    PORT
      LAYER M5 ;
        RECT  93.36 129.516 93.384 129.6 ;
    END
  END rq[125]
  PIN rq[126]
    DIRECTION OUTPUT ;
    USE SIGNAL ;
    PORT
      LAYER M5 ;
        RECT  94.128 129.516 94.152 129.6 ;
    END
  END rq[126]
  PIN rq[127]
    DIRECTION OUTPUT ;
    USE SIGNAL ;
    PORT
      LAYER M5 ;
        RECT  94.848 129.516 94.872 129.6 ;
    END
  END rq[127]
  PIN rq[128]
    DIRECTION OUTPUT ;
    USE SIGNAL ;
    PORT
      LAYER M5 ;
        RECT  95.568 129.516 95.592 129.6 ;
    END
  END rq[128]
  PIN rq[129]
    DIRECTION OUTPUT ;
    USE SIGNAL ;
    PORT
      LAYER M5 ;
        RECT  96.336 129.516 96.36 129.6 ;
    END
  END rq[129]
  PIN rq[12]
    DIRECTION OUTPUT ;
    USE SIGNAL ;
    PORT
      LAYER M5 ;
        RECT  10.176 129.516 10.2 129.6 ;
    END
  END rq[12]
  PIN rq[130]
    DIRECTION OUTPUT ;
    USE SIGNAL ;
    PORT
      LAYER M5 ;
        RECT  97.056 129.516 97.08 129.6 ;
    END
  END rq[130]
  PIN rq[131]
    DIRECTION OUTPUT ;
    USE SIGNAL ;
    PORT
      LAYER M5 ;
        RECT  97.776 129.516 97.8 129.6 ;
    END
  END rq[131]
  PIN rq[132]
    DIRECTION OUTPUT ;
    USE SIGNAL ;
    PORT
      LAYER M5 ;
        RECT  98.544 129.516 98.568 129.6 ;
    END
  END rq[132]
  PIN rq[133]
    DIRECTION OUTPUT ;
    USE SIGNAL ;
    PORT
      LAYER M5 ;
        RECT  99.264 129.516 99.288 129.6 ;
    END
  END rq[133]
  PIN rq[134]
    DIRECTION OUTPUT ;
    USE SIGNAL ;
    PORT
      LAYER M5 ;
        RECT  99.984 129.516 100.008 129.6 ;
    END
  END rq[134]
  PIN rq[135]
    DIRECTION OUTPUT ;
    USE SIGNAL ;
    PORT
      LAYER M5 ;
        RECT  100.752 129.516 100.776 129.6 ;
    END
  END rq[135]
  PIN rq[13]
    DIRECTION OUTPUT ;
    USE SIGNAL ;
    PORT
      LAYER M5 ;
        RECT  10.944 129.516 10.968 129.6 ;
    END
  END rq[13]
  PIN rq[14]
    DIRECTION OUTPUT ;
    USE SIGNAL ;
    PORT
      LAYER M5 ;
        RECT  11.664 129.516 11.688 129.6 ;
    END
  END rq[14]
  PIN rq[15]
    DIRECTION OUTPUT ;
    USE SIGNAL ;
    PORT
      LAYER M5 ;
        RECT  12.384 129.516 12.408 129.6 ;
    END
  END rq[15]
  PIN rq[16]
    DIRECTION OUTPUT ;
    USE SIGNAL ;
    PORT
      LAYER M5 ;
        RECT  13.152 129.516 13.176 129.6 ;
    END
  END rq[16]
  PIN rq[17]
    DIRECTION OUTPUT ;
    USE SIGNAL ;
    PORT
      LAYER M5 ;
        RECT  13.872 129.516 13.896 129.6 ;
    END
  END rq[17]
  PIN rq[18]
    DIRECTION OUTPUT ;
    USE SIGNAL ;
    PORT
      LAYER M5 ;
        RECT  14.592 129.516 14.616 129.6 ;
    END
  END rq[18]
  PIN rq[19]
    DIRECTION OUTPUT ;
    USE SIGNAL ;
    PORT
      LAYER M5 ;
        RECT  15.36 129.516 15.384 129.6 ;
    END
  END rq[19]
  PIN rq[1]
    DIRECTION OUTPUT ;
    USE SIGNAL ;
    PORT
      LAYER M5 ;
        RECT  2.112 129.516 2.136 129.6 ;
    END
  END rq[1]
  PIN rq[20]
    DIRECTION OUTPUT ;
    USE SIGNAL ;
    PORT
      LAYER M5 ;
        RECT  16.08 129.516 16.104 129.6 ;
    END
  END rq[20]
  PIN rq[21]
    DIRECTION OUTPUT ;
    USE SIGNAL ;
    PORT
      LAYER M5 ;
        RECT  16.8 129.516 16.824 129.6 ;
    END
  END rq[21]
  PIN rq[22]
    DIRECTION OUTPUT ;
    USE SIGNAL ;
    PORT
      LAYER M5 ;
        RECT  17.568 129.516 17.592 129.6 ;
    END
  END rq[22]
  PIN rq[23]
    DIRECTION OUTPUT ;
    USE SIGNAL ;
    PORT
      LAYER M5 ;
        RECT  18.288 129.516 18.312 129.6 ;
    END
  END rq[23]
  PIN rq[24]
    DIRECTION OUTPUT ;
    USE SIGNAL ;
    PORT
      LAYER M5 ;
        RECT  19.008 129.516 19.032 129.6 ;
    END
  END rq[24]
  PIN rq[25]
    DIRECTION OUTPUT ;
    USE SIGNAL ;
    PORT
      LAYER M5 ;
        RECT  19.776 129.516 19.8 129.6 ;
    END
  END rq[25]
  PIN rq[26]
    DIRECTION OUTPUT ;
    USE SIGNAL ;
    PORT
      LAYER M5 ;
        RECT  20.496 129.516 20.52 129.6 ;
    END
  END rq[26]
  PIN rq[27]
    DIRECTION OUTPUT ;
    USE SIGNAL ;
    PORT
      LAYER M5 ;
        RECT  21.216 129.516 21.24 129.6 ;
    END
  END rq[27]
  PIN rq[28]
    DIRECTION OUTPUT ;
    USE SIGNAL ;
    PORT
      LAYER M5 ;
        RECT  21.984 129.516 22.008 129.6 ;
    END
  END rq[28]
  PIN rq[29]
    DIRECTION OUTPUT ;
    USE SIGNAL ;
    PORT
      LAYER M5 ;
        RECT  22.704 129.516 22.728 129.6 ;
    END
  END rq[29]
  PIN rq[2]
    DIRECTION OUTPUT ;
    USE SIGNAL ;
    PORT
      LAYER M5 ;
        RECT  2.832 129.516 2.856 129.6 ;
    END
  END rq[2]
  PIN rq[30]
    DIRECTION OUTPUT ;
    USE SIGNAL ;
    PORT
      LAYER M5 ;
        RECT  23.424 129.516 23.448 129.6 ;
    END
  END rq[30]
  PIN rq[31]
    DIRECTION OUTPUT ;
    USE SIGNAL ;
    PORT
      LAYER M5 ;
        RECT  24.192 129.516 24.216 129.6 ;
    END
  END rq[31]
  PIN rq[32]
    DIRECTION OUTPUT ;
    USE SIGNAL ;
    PORT
      LAYER M5 ;
        RECT  24.912 129.516 24.936 129.6 ;
    END
  END rq[32]
  PIN rq[33]
    DIRECTION OUTPUT ;
    USE SIGNAL ;
    PORT
      LAYER M5 ;
        RECT  25.632 129.516 25.656 129.6 ;
    END
  END rq[33]
  PIN rq[34]
    DIRECTION OUTPUT ;
    USE SIGNAL ;
    PORT
      LAYER M5 ;
        RECT  26.4 129.516 26.424 129.6 ;
    END
  END rq[34]
  PIN rq[35]
    DIRECTION OUTPUT ;
    USE SIGNAL ;
    PORT
      LAYER M5 ;
        RECT  27.12 129.516 27.144 129.6 ;
    END
  END rq[35]
  PIN rq[36]
    DIRECTION OUTPUT ;
    USE SIGNAL ;
    PORT
      LAYER M5 ;
        RECT  27.84 129.516 27.864 129.6 ;
    END
  END rq[36]
  PIN rq[37]
    DIRECTION OUTPUT ;
    USE SIGNAL ;
    PORT
      LAYER M5 ;
        RECT  28.608 129.516 28.632 129.6 ;
    END
  END rq[37]
  PIN rq[38]
    DIRECTION OUTPUT ;
    USE SIGNAL ;
    PORT
      LAYER M5 ;
        RECT  29.328 129.516 29.352 129.6 ;
    END
  END rq[38]
  PIN rq[39]
    DIRECTION OUTPUT ;
    USE SIGNAL ;
    PORT
      LAYER M5 ;
        RECT  30.048 129.516 30.072 129.6 ;
    END
  END rq[39]
  PIN rq[3]
    DIRECTION OUTPUT ;
    USE SIGNAL ;
    PORT
      LAYER M5 ;
        RECT  3.552 129.516 3.576 129.6 ;
    END
  END rq[3]
  PIN rq[40]
    DIRECTION OUTPUT ;
    USE SIGNAL ;
    PORT
      LAYER M5 ;
        RECT  30.816 129.516 30.84 129.6 ;
    END
  END rq[40]
  PIN rq[41]
    DIRECTION OUTPUT ;
    USE SIGNAL ;
    PORT
      LAYER M5 ;
        RECT  31.536 129.516 31.56 129.6 ;
    END
  END rq[41]
  PIN rq[42]
    DIRECTION OUTPUT ;
    USE SIGNAL ;
    PORT
      LAYER M5 ;
        RECT  32.256 129.516 32.28 129.6 ;
    END
  END rq[42]
  PIN rq[43]
    DIRECTION OUTPUT ;
    USE SIGNAL ;
    PORT
      LAYER M5 ;
        RECT  33.024 129.516 33.048 129.6 ;
    END
  END rq[43]
  PIN rq[44]
    DIRECTION OUTPUT ;
    USE SIGNAL ;
    PORT
      LAYER M5 ;
        RECT  33.744 129.516 33.768 129.6 ;
    END
  END rq[44]
  PIN rq[45]
    DIRECTION OUTPUT ;
    USE SIGNAL ;
    PORT
      LAYER M5 ;
        RECT  34.464 129.516 34.488 129.6 ;
    END
  END rq[45]
  PIN rq[46]
    DIRECTION OUTPUT ;
    USE SIGNAL ;
    PORT
      LAYER M5 ;
        RECT  35.232 129.516 35.256 129.6 ;
    END
  END rq[46]
  PIN rq[47]
    DIRECTION OUTPUT ;
    USE SIGNAL ;
    PORT
      LAYER M5 ;
        RECT  35.952 129.516 35.976 129.6 ;
    END
  END rq[47]
  PIN rq[48]
    DIRECTION OUTPUT ;
    USE SIGNAL ;
    PORT
      LAYER M5 ;
        RECT  36.672 129.516 36.696 129.6 ;
    END
  END rq[48]
  PIN rq[49]
    DIRECTION OUTPUT ;
    USE SIGNAL ;
    PORT
      LAYER M5 ;
        RECT  37.44 129.516 37.464 129.6 ;
    END
  END rq[49]
  PIN rq[4]
    DIRECTION OUTPUT ;
    USE SIGNAL ;
    PORT
      LAYER M5 ;
        RECT  4.32 129.516 4.344 129.6 ;
    END
  END rq[4]
  PIN rq[50]
    DIRECTION OUTPUT ;
    USE SIGNAL ;
    PORT
      LAYER M5 ;
        RECT  38.16 129.516 38.184 129.6 ;
    END
  END rq[50]
  PIN rq[51]
    DIRECTION OUTPUT ;
    USE SIGNAL ;
    PORT
      LAYER M5 ;
        RECT  38.88 129.516 38.904 129.6 ;
    END
  END rq[51]
  PIN rq[52]
    DIRECTION OUTPUT ;
    USE SIGNAL ;
    PORT
      LAYER M5 ;
        RECT  39.648 129.516 39.672 129.6 ;
    END
  END rq[52]
  PIN rq[53]
    DIRECTION OUTPUT ;
    USE SIGNAL ;
    PORT
      LAYER M5 ;
        RECT  40.368 129.516 40.392 129.6 ;
    END
  END rq[53]
  PIN rq[54]
    DIRECTION OUTPUT ;
    USE SIGNAL ;
    PORT
      LAYER M5 ;
        RECT  41.088 129.516 41.112 129.6 ;
    END
  END rq[54]
  PIN rq[55]
    DIRECTION OUTPUT ;
    USE SIGNAL ;
    PORT
      LAYER M5 ;
        RECT  41.856 129.516 41.88 129.6 ;
    END
  END rq[55]
  PIN rq[56]
    DIRECTION OUTPUT ;
    USE SIGNAL ;
    PORT
      LAYER M5 ;
        RECT  42.576 129.516 42.6 129.6 ;
    END
  END rq[56]
  PIN rq[57]
    DIRECTION OUTPUT ;
    USE SIGNAL ;
    PORT
      LAYER M5 ;
        RECT  43.296 129.516 43.32 129.6 ;
    END
  END rq[57]
  PIN rq[58]
    DIRECTION OUTPUT ;
    USE SIGNAL ;
    PORT
      LAYER M5 ;
        RECT  44.064 129.516 44.088 129.6 ;
    END
  END rq[58]
  PIN rq[59]
    DIRECTION OUTPUT ;
    USE SIGNAL ;
    PORT
      LAYER M5 ;
        RECT  44.784 129.516 44.808 129.6 ;
    END
  END rq[59]
  PIN rq[5]
    DIRECTION OUTPUT ;
    USE SIGNAL ;
    PORT
      LAYER M5 ;
        RECT  5.04 129.516 5.064 129.6 ;
    END
  END rq[5]
  PIN rq[60]
    DIRECTION OUTPUT ;
    USE SIGNAL ;
    PORT
      LAYER M5 ;
        RECT  45.504 129.516 45.528 129.6 ;
    END
  END rq[60]
  PIN rq[61]
    DIRECTION OUTPUT ;
    USE SIGNAL ;
    PORT
      LAYER M5 ;
        RECT  46.272 129.516 46.296 129.6 ;
    END
  END rq[61]
  PIN rq[62]
    DIRECTION OUTPUT ;
    USE SIGNAL ;
    PORT
      LAYER M5 ;
        RECT  46.992 129.516 47.016 129.6 ;
    END
  END rq[62]
  PIN rq[63]
    DIRECTION OUTPUT ;
    USE SIGNAL ;
    PORT
      LAYER M5 ;
        RECT  47.712 129.516 47.736 129.6 ;
    END
  END rq[63]
  PIN rq[64]
    DIRECTION OUTPUT ;
    USE SIGNAL ;
    PORT
      LAYER M5 ;
        RECT  48.48 129.516 48.504 129.6 ;
    END
  END rq[64]
  PIN rq[65]
    DIRECTION OUTPUT ;
    USE SIGNAL ;
    PORT
      LAYER M5 ;
        RECT  49.2 129.516 49.224 129.6 ;
    END
  END rq[65]
  PIN rq[66]
    DIRECTION OUTPUT ;
    USE SIGNAL ;
    PORT
      LAYER M5 ;
        RECT  49.92 129.516 49.944 129.6 ;
    END
  END rq[66]
  PIN rq[67]
    DIRECTION OUTPUT ;
    USE SIGNAL ;
    PORT
      LAYER M5 ;
        RECT  50.688 129.516 50.712 129.6 ;
    END
  END rq[67]
  PIN rq[68]
    DIRECTION OUTPUT ;
    USE SIGNAL ;
    PORT
      LAYER M5 ;
        RECT  51.408 129.516 51.432 129.6 ;
    END
  END rq[68]
  PIN rq[69]
    DIRECTION OUTPUT ;
    USE SIGNAL ;
    PORT
      LAYER M5 ;
        RECT  52.128 129.516 52.152 129.6 ;
    END
  END rq[69]
  PIN rq[6]
    DIRECTION OUTPUT ;
    USE SIGNAL ;
    PORT
      LAYER M5 ;
        RECT  5.76 129.516 5.784 129.6 ;
    END
  END rq[6]
  PIN rq[70]
    DIRECTION OUTPUT ;
    USE SIGNAL ;
    PORT
      LAYER M5 ;
        RECT  52.896 129.516 52.92 129.6 ;
    END
  END rq[70]
  PIN rq[71]
    DIRECTION OUTPUT ;
    USE SIGNAL ;
    PORT
      LAYER M5 ;
        RECT  53.616 129.516 53.64 129.6 ;
    END
  END rq[71]
  PIN rq[72]
    DIRECTION OUTPUT ;
    USE SIGNAL ;
    PORT
      LAYER M5 ;
        RECT  54.336 129.516 54.36 129.6 ;
    END
  END rq[72]
  PIN rq[73]
    DIRECTION OUTPUT ;
    USE SIGNAL ;
    PORT
      LAYER M5 ;
        RECT  55.104 129.516 55.128 129.6 ;
    END
  END rq[73]
  PIN rq[74]
    DIRECTION OUTPUT ;
    USE SIGNAL ;
    PORT
      LAYER M5 ;
        RECT  55.824 129.516 55.848 129.6 ;
    END
  END rq[74]
  PIN rq[75]
    DIRECTION OUTPUT ;
    USE SIGNAL ;
    PORT
      LAYER M5 ;
        RECT  56.544 129.516 56.568 129.6 ;
    END
  END rq[75]
  PIN rq[76]
    DIRECTION OUTPUT ;
    USE SIGNAL ;
    PORT
      LAYER M5 ;
        RECT  57.312 129.516 57.336 129.6 ;
    END
  END rq[76]
  PIN rq[77]
    DIRECTION OUTPUT ;
    USE SIGNAL ;
    PORT
      LAYER M5 ;
        RECT  58.032 129.516 58.056 129.6 ;
    END
  END rq[77]
  PIN rq[78]
    DIRECTION OUTPUT ;
    USE SIGNAL ;
    PORT
      LAYER M5 ;
        RECT  58.752 129.516 58.776 129.6 ;
    END
  END rq[78]
  PIN rq[79]
    DIRECTION OUTPUT ;
    USE SIGNAL ;
    PORT
      LAYER M5 ;
        RECT  59.52 129.516 59.544 129.6 ;
    END
  END rq[79]
  PIN rq[7]
    DIRECTION OUTPUT ;
    USE SIGNAL ;
    PORT
      LAYER M5 ;
        RECT  6.528 129.516 6.552 129.6 ;
    END
  END rq[7]
  PIN rq[80]
    DIRECTION OUTPUT ;
    USE SIGNAL ;
    PORT
      LAYER M5 ;
        RECT  60.24 129.516 60.264 129.6 ;
    END
  END rq[80]
  PIN rq[81]
    DIRECTION OUTPUT ;
    USE SIGNAL ;
    PORT
      LAYER M5 ;
        RECT  60.96 129.516 60.984 129.6 ;
    END
  END rq[81]
  PIN rq[82]
    DIRECTION OUTPUT ;
    USE SIGNAL ;
    PORT
      LAYER M5 ;
        RECT  61.728 129.516 61.752 129.6 ;
    END
  END rq[82]
  PIN rq[83]
    DIRECTION OUTPUT ;
    USE SIGNAL ;
    PORT
      LAYER M5 ;
        RECT  62.448 129.516 62.472 129.6 ;
    END
  END rq[83]
  PIN rq[84]
    DIRECTION OUTPUT ;
    USE SIGNAL ;
    PORT
      LAYER M5 ;
        RECT  63.168 129.516 63.192 129.6 ;
    END
  END rq[84]
  PIN rq[85]
    DIRECTION OUTPUT ;
    USE SIGNAL ;
    PORT
      LAYER M5 ;
        RECT  63.936 129.516 63.96 129.6 ;
    END
  END rq[85]
  PIN rq[86]
    DIRECTION OUTPUT ;
    USE SIGNAL ;
    PORT
      LAYER M5 ;
        RECT  64.656 129.516 64.68 129.6 ;
    END
  END rq[86]
  PIN rq[87]
    DIRECTION OUTPUT ;
    USE SIGNAL ;
    PORT
      LAYER M5 ;
        RECT  65.376 129.516 65.4 129.6 ;
    END
  END rq[87]
  PIN rq[88]
    DIRECTION OUTPUT ;
    USE SIGNAL ;
    PORT
      LAYER M5 ;
        RECT  66.144 129.516 66.168 129.6 ;
    END
  END rq[88]
  PIN rq[89]
    DIRECTION OUTPUT ;
    USE SIGNAL ;
    PORT
      LAYER M5 ;
        RECT  66.864 129.516 66.888 129.6 ;
    END
  END rq[89]
  PIN rq[8]
    DIRECTION OUTPUT ;
    USE SIGNAL ;
    PORT
      LAYER M5 ;
        RECT  7.248 129.516 7.272 129.6 ;
    END
  END rq[8]
  PIN rq[90]
    DIRECTION OUTPUT ;
    USE SIGNAL ;
    PORT
      LAYER M5 ;
        RECT  67.584 129.516 67.608 129.6 ;
    END
  END rq[90]
  PIN rq[91]
    DIRECTION OUTPUT ;
    USE SIGNAL ;
    PORT
      LAYER M5 ;
        RECT  68.352 129.516 68.376 129.6 ;
    END
  END rq[91]
  PIN rq[92]
    DIRECTION OUTPUT ;
    USE SIGNAL ;
    PORT
      LAYER M5 ;
        RECT  69.072 129.516 69.096 129.6 ;
    END
  END rq[92]
  PIN rq[93]
    DIRECTION OUTPUT ;
    USE SIGNAL ;
    PORT
      LAYER M5 ;
        RECT  69.792 129.516 69.816 129.6 ;
    END
  END rq[93]
  PIN rq[94]
    DIRECTION OUTPUT ;
    USE SIGNAL ;
    PORT
      LAYER M5 ;
        RECT  70.56 129.516 70.584 129.6 ;
    END
  END rq[94]
  PIN rq[95]
    DIRECTION OUTPUT ;
    USE SIGNAL ;
    PORT
      LAYER M5 ;
        RECT  71.28 129.516 71.304 129.6 ;
    END
  END rq[95]
  PIN rq[96]
    DIRECTION OUTPUT ;
    USE SIGNAL ;
    PORT
      LAYER M5 ;
        RECT  72 129.516 72.024 129.6 ;
    END
  END rq[96]
  PIN rq[97]
    DIRECTION OUTPUT ;
    USE SIGNAL ;
    PORT
      LAYER M5 ;
        RECT  72.768 129.516 72.792 129.6 ;
    END
  END rq[97]
  PIN rq[98]
    DIRECTION OUTPUT ;
    USE SIGNAL ;
    PORT
      LAYER M5 ;
        RECT  73.488 129.516 73.512 129.6 ;
    END
  END rq[98]
  PIN rq[99]
    DIRECTION OUTPUT ;
    USE SIGNAL ;
    PORT
      LAYER M5 ;
        RECT  74.208 129.516 74.232 129.6 ;
    END
  END rq[99]
  PIN rq[9]
    DIRECTION OUTPUT ;
    USE SIGNAL ;
    PORT
      LAYER M5 ;
        RECT  7.968 129.516 7.992 129.6 ;
    END
  END rq[9]
  PIN rr_v[0]
    DIRECTION INPUT ;
    USE SIGNAL ;
    PORT
      LAYER M5 ;
        RECT  101.472 129.516 101.496 129.6 ;
    END
  END rr_v[0]
  PIN rr_v[1]
    DIRECTION INPUT ;
    USE SIGNAL ;
    PORT
      LAYER M5 ;
        RECT  102.192 129.516 102.216 129.6 ;
    END
  END rr_v[1]
  PIN rr_v[2]
    DIRECTION INPUT ;
    USE SIGNAL ;
    PORT
      LAYER M5 ;
        RECT  102.96 129.516 102.984 129.6 ;
    END
  END rr_v[2]
  PIN rr_v[3]
    DIRECTION INPUT ;
    USE SIGNAL ;
    PORT
      LAYER M5 ;
        RECT  103.68 129.516 103.704 129.6 ;
    END
  END rr_v[3]
  PIN rr_v[4]
    DIRECTION INPUT ;
    USE SIGNAL ;
    PORT
      LAYER M5 ;
        RECT  104.4 129.516 104.424 129.6 ;
    END
  END rr_v[4]
  PIN rr_v[5]
    DIRECTION INPUT ;
    USE SIGNAL ;
    PORT
      LAYER M5 ;
        RECT  105.168 129.516 105.192 129.6 ;
    END
  END rr_v[5]
  PIN rr_v[6]
    DIRECTION INPUT ;
    USE SIGNAL ;
    PORT
      LAYER M5 ;
        RECT  105.888 129.516 105.912 129.6 ;
    END
  END rr_v[6]
  PIN rr_v[7]
    DIRECTION INPUT ;
    USE SIGNAL ;
    PORT
      LAYER M5 ;
        RECT  106.608 129.516 106.632 129.6 ;
    END
  END rr_v[7]
  PIN rsel[0]
    DIRECTION OUTPUT ;
    USE SIGNAL ;
    PORT
      LAYER M4 ;
        RECT  107.916 122.592 108 122.616 ;
    END
  END rsel[0]
  PIN rsel[1]
    DIRECTION OUTPUT ;
    USE SIGNAL ;
    PORT
      LAYER M4 ;
        RECT  107.916 123.504 108 123.528 ;
    END
  END rsel[1]
  PIN rsel[2]
    DIRECTION OUTPUT ;
    USE SIGNAL ;
    PORT
      LAYER M4 ;
        RECT  107.916 124.416 108 124.44 ;
    END
  END rsel[2]
  PIN rst_n
    DIRECTION INPUT ;
    USE SIGNAL ;
    PORT
      LAYER M4 ;
        RECT  0 116.016 0.084 116.04 ;
    END
    PORT
      LAYER M4 ;
        RECT  0.06 116.016 0.137 116.04 ;
    END
  END rst_n
  PIN vo
    DIRECTION INPUT ;
    USE SIGNAL ;
    PORT
      LAYER M4 ;
        RECT  107.916 125.376 108 125.4 ;
    END
  END vo
  PIN wc_cfg[0]
    DIRECTION INPUT ;
    USE SIGNAL ;
    PORT
      LAYER M4 ;
        RECT  0 117.936 0.084 117.96 ;
    END
    PORT
      LAYER M4 ;
        RECT  0.06 117.936 0.569 117.96 ;
    END
  END wc_cfg[0]
  PIN wc_cfg[1]
    DIRECTION INPUT ;
    USE SIGNAL ;
    PORT
      LAYER M4 ;
        RECT  0 119.904 0.084 119.928 ;
    END
    PORT
      LAYER M4 ;
        RECT  0.06 119.904 0.137 119.928 ;
    END
  END wc_cfg[1]
  PIN wc_cfg[2]
    DIRECTION INPUT ;
    USE SIGNAL ;
    PORT
      LAYER M4 ;
        RECT  0 121.824 0.084 121.848 ;
    END
    PORT
      LAYER M4 ;
        RECT  0.06 121.824 0.137 121.848 ;
    END
  END wc_cfg[2]
  PIN wc_cfg[3]
    DIRECTION INPUT ;
    USE SIGNAL ;
    PORT
      LAYER M4 ;
        RECT  0 123.744 0.084 123.768 ;
    END
    PORT
      LAYER M4 ;
        RECT  0.06 123.744 0.137 123.768 ;
    END
  END wc_cfg[3]
  PIN wc_cfg[4]
    DIRECTION INPUT ;
    USE SIGNAL ;
    PORT
      LAYER M4 ;
        RECT  0 125.712 0.084 125.736 ;
    END
    PORT
      LAYER M4 ;
        RECT  0.06 125.712 0.137 125.736 ;
    END
  END wc_cfg[4]
  PIN wc_cfg[5]
    DIRECTION INPUT ;
    USE SIGNAL ;
    PORT
      LAYER M4 ;
        RECT  0 127.632 0.084 127.656 ;
    END
    PORT
      LAYER M4 ;
        RECT  0.06 127.632 0.137 127.656 ;
    END
  END wc_cfg[5]
  PIN wq_addr[0]
    DIRECTION OUTPUT ;
    USE SIGNAL ;
    PORT
      LAYER M5 ;
        RECT  1.248 0 1.272 0.084 ;
    END
  END wq_addr[0]
  PIN wq_addr[100]
    DIRECTION OUTPUT ;
    USE SIGNAL ;
    PORT
      LAYER M5 ;
        RECT  54.24 0 54.264 0.084 ;
    END
  END wq_addr[100]
  PIN wq_addr[101]
    DIRECTION OUTPUT ;
    USE SIGNAL ;
    PORT
      LAYER M5 ;
        RECT  54.768 0 54.792 0.084 ;
    END
  END wq_addr[101]
  PIN wq_addr[102]
    DIRECTION OUTPUT ;
    USE SIGNAL ;
    PORT
      LAYER M5 ;
        RECT  55.296 0 55.32 0.084 ;
    END
  END wq_addr[102]
  PIN wq_addr[103]
    DIRECTION OUTPUT ;
    USE SIGNAL ;
    PORT
      LAYER M5 ;
        RECT  55.824 0 55.848 0.084 ;
    END
  END wq_addr[103]
  PIN wq_addr[104]
    DIRECTION OUTPUT ;
    USE SIGNAL ;
    PORT
      LAYER M5 ;
        RECT  56.352 0 56.376 0.084 ;
    END
  END wq_addr[104]
  PIN wq_addr[105]
    DIRECTION OUTPUT ;
    USE SIGNAL ;
    PORT
      LAYER M5 ;
        RECT  56.88 0 56.904 0.084 ;
    END
  END wq_addr[105]
  PIN wq_addr[106]
    DIRECTION OUTPUT ;
    USE SIGNAL ;
    PORT
      LAYER M5 ;
        RECT  57.456 0 57.48 0.084 ;
    END
  END wq_addr[106]
  PIN wq_addr[107]
    DIRECTION OUTPUT ;
    USE SIGNAL ;
    PORT
      LAYER M5 ;
        RECT  57.984 0 58.008 0.084 ;
    END
  END wq_addr[107]
  PIN wq_addr[108]
    DIRECTION OUTPUT ;
    USE SIGNAL ;
    PORT
      LAYER M5 ;
        RECT  58.512 0 58.536 0.084 ;
    END
  END wq_addr[108]
  PIN wq_addr[109]
    DIRECTION OUTPUT ;
    USE SIGNAL ;
    PORT
      LAYER M5 ;
        RECT  59.04 0 59.064 0.084 ;
    END
  END wq_addr[109]
  PIN wq_addr[10]
    DIRECTION OUTPUT ;
    USE SIGNAL ;
    PORT
      LAYER M5 ;
        RECT  6.576 0 6.6 0.084 ;
    END
  END wq_addr[10]
  PIN wq_addr[110]
    DIRECTION OUTPUT ;
    USE SIGNAL ;
    PORT
      LAYER M5 ;
        RECT  59.568 0 59.592 0.084 ;
    END
  END wq_addr[110]
  PIN wq_addr[111]
    DIRECTION OUTPUT ;
    USE SIGNAL ;
    PORT
      LAYER M5 ;
        RECT  60.096 0 60.12 0.084 ;
    END
  END wq_addr[111]
  PIN wq_addr[112]
    DIRECTION OUTPUT ;
    USE SIGNAL ;
    PORT
      LAYER M5 ;
        RECT  60.624 0 60.648 0.084 ;
    END
  END wq_addr[112]
  PIN wq_addr[113]
    DIRECTION OUTPUT ;
    USE SIGNAL ;
    PORT
      LAYER M5 ;
        RECT  61.152 0 61.176 0.084 ;
    END
  END wq_addr[113]
  PIN wq_addr[114]
    DIRECTION OUTPUT ;
    USE SIGNAL ;
    PORT
      LAYER M5 ;
        RECT  61.68 0 61.704 0.084 ;
    END
  END wq_addr[114]
  PIN wq_addr[115]
    DIRECTION OUTPUT ;
    USE SIGNAL ;
    PORT
      LAYER M5 ;
        RECT  62.208 0 62.232 0.084 ;
    END
  END wq_addr[115]
  PIN wq_addr[116]
    DIRECTION OUTPUT ;
    USE SIGNAL ;
    PORT
      LAYER M5 ;
        RECT  62.736 0 62.76 0.084 ;
    END
  END wq_addr[116]
  PIN wq_addr[117]
    DIRECTION OUTPUT ;
    USE SIGNAL ;
    PORT
      LAYER M5 ;
        RECT  63.264 0 63.288 0.084 ;
    END
  END wq_addr[117]
  PIN wq_addr[118]
    DIRECTION OUTPUT ;
    USE SIGNAL ;
    PORT
      LAYER M5 ;
        RECT  63.792 0 63.816 0.084 ;
    END
  END wq_addr[118]
  PIN wq_addr[119]
    DIRECTION OUTPUT ;
    USE SIGNAL ;
    PORT
      LAYER M5 ;
        RECT  64.32 0 64.344 0.084 ;
    END
  END wq_addr[119]
  PIN wq_addr[11]
    DIRECTION OUTPUT ;
    USE SIGNAL ;
    PORT
      LAYER M5 ;
        RECT  7.104 0 7.128 0.084 ;
    END
  END wq_addr[11]
  PIN wq_addr[120]
    DIRECTION OUTPUT ;
    USE SIGNAL ;
    PORT
      LAYER M5 ;
        RECT  64.848 0 64.872 0.084 ;
    END
  END wq_addr[120]
  PIN wq_addr[121]
    DIRECTION OUTPUT ;
    USE SIGNAL ;
    PORT
      LAYER M5 ;
        RECT  65.376 0 65.4 0.084 ;
    END
  END wq_addr[121]
  PIN wq_addr[122]
    DIRECTION OUTPUT ;
    USE SIGNAL ;
    PORT
      LAYER M5 ;
        RECT  65.904 0 65.928 0.084 ;
    END
  END wq_addr[122]
  PIN wq_addr[123]
    DIRECTION OUTPUT ;
    USE SIGNAL ;
    PORT
      LAYER M5 ;
        RECT  66.432 0 66.456 0.084 ;
    END
  END wq_addr[123]
  PIN wq_addr[124]
    DIRECTION OUTPUT ;
    USE SIGNAL ;
    PORT
      LAYER M5 ;
        RECT  66.96 0 66.984 0.084 ;
    END
  END wq_addr[124]
  PIN wq_addr[125]
    DIRECTION OUTPUT ;
    USE SIGNAL ;
    PORT
      LAYER M5 ;
        RECT  67.488 0 67.512 0.084 ;
    END
  END wq_addr[125]
  PIN wq_addr[126]
    DIRECTION OUTPUT ;
    USE SIGNAL ;
    PORT
      LAYER M5 ;
        RECT  68.016 0 68.04 0.084 ;
    END
  END wq_addr[126]
  PIN wq_addr[127]
    DIRECTION OUTPUT ;
    USE SIGNAL ;
    PORT
      LAYER M5 ;
        RECT  68.544 0 68.568 0.084 ;
    END
  END wq_addr[127]
  PIN wq_addr[12]
    DIRECTION OUTPUT ;
    USE SIGNAL ;
    PORT
      LAYER M5 ;
        RECT  7.632 0 7.656 0.084 ;
    END
  END wq_addr[12]
  PIN wq_addr[13]
    DIRECTION OUTPUT ;
    USE SIGNAL ;
    PORT
      LAYER M5 ;
        RECT  8.16 0 8.184 0.084 ;
    END
  END wq_addr[13]
  PIN wq_addr[14]
    DIRECTION OUTPUT ;
    USE SIGNAL ;
    PORT
      LAYER M5 ;
        RECT  8.688 0 8.712 0.084 ;
    END
  END wq_addr[14]
  PIN wq_addr[15]
    DIRECTION OUTPUT ;
    USE SIGNAL ;
    PORT
      LAYER M5 ;
        RECT  9.216 0 9.24 0.084 ;
    END
  END wq_addr[15]
  PIN wq_addr[16]
    DIRECTION OUTPUT ;
    USE SIGNAL ;
    PORT
      LAYER M5 ;
        RECT  9.744 0 9.768 0.084 ;
    END
  END wq_addr[16]
  PIN wq_addr[17]
    DIRECTION OUTPUT ;
    USE SIGNAL ;
    PORT
      LAYER M5 ;
        RECT  10.272 0 10.296 0.084 ;
    END
  END wq_addr[17]
  PIN wq_addr[18]
    DIRECTION OUTPUT ;
    USE SIGNAL ;
    PORT
      LAYER M5 ;
        RECT  10.8 0 10.824 0.084 ;
    END
  END wq_addr[18]
  PIN wq_addr[19]
    DIRECTION OUTPUT ;
    USE SIGNAL ;
    PORT
      LAYER M5 ;
        RECT  11.328 0 11.352 0.084 ;
    END
  END wq_addr[19]
  PIN wq_addr[1]
    DIRECTION OUTPUT ;
    USE SIGNAL ;
    PORT
      LAYER M5 ;
        RECT  1.776 0 1.8 0.084 ;
    END
  END wq_addr[1]
  PIN wq_addr[20]
    DIRECTION OUTPUT ;
    USE SIGNAL ;
    PORT
      LAYER M5 ;
        RECT  11.856 0 11.88 0.084 ;
    END
  END wq_addr[20]
  PIN wq_addr[21]
    DIRECTION OUTPUT ;
    USE SIGNAL ;
    PORT
      LAYER M5 ;
        RECT  12.384 0 12.408 0.084 ;
    END
  END wq_addr[21]
  PIN wq_addr[22]
    DIRECTION OUTPUT ;
    USE SIGNAL ;
    PORT
      LAYER M5 ;
        RECT  12.912 0 12.936 0.084 ;
    END
  END wq_addr[22]
  PIN wq_addr[23]
    DIRECTION OUTPUT ;
    USE SIGNAL ;
    PORT
      LAYER M5 ;
        RECT  13.44 0 13.464 0.084 ;
    END
  END wq_addr[23]
  PIN wq_addr[24]
    DIRECTION OUTPUT ;
    USE SIGNAL ;
    PORT
      LAYER M5 ;
        RECT  13.968 0 13.992 0.084 ;
    END
  END wq_addr[24]
  PIN wq_addr[25]
    DIRECTION OUTPUT ;
    USE SIGNAL ;
    PORT
      LAYER M5 ;
        RECT  14.496 0 14.52 0.084 ;
    END
  END wq_addr[25]
  PIN wq_addr[26]
    DIRECTION OUTPUT ;
    USE SIGNAL ;
    PORT
      LAYER M5 ;
        RECT  15.024 0 15.048 0.084 ;
    END
  END wq_addr[26]
  PIN wq_addr[27]
    DIRECTION OUTPUT ;
    USE SIGNAL ;
    PORT
      LAYER M5 ;
        RECT  15.552 0 15.576 0.084 ;
    END
  END wq_addr[27]
  PIN wq_addr[28]
    DIRECTION OUTPUT ;
    USE SIGNAL ;
    PORT
      LAYER M5 ;
        RECT  16.08 0 16.104 0.084 ;
    END
  END wq_addr[28]
  PIN wq_addr[29]
    DIRECTION OUTPUT ;
    USE SIGNAL ;
    PORT
      LAYER M5 ;
        RECT  16.608 0 16.632 0.084 ;
    END
  END wq_addr[29]
  PIN wq_addr[2]
    DIRECTION OUTPUT ;
    USE SIGNAL ;
    PORT
      LAYER M5 ;
        RECT  2.304 0 2.328 0.084 ;
    END
  END wq_addr[2]
  PIN wq_addr[30]
    DIRECTION OUTPUT ;
    USE SIGNAL ;
    PORT
      LAYER M5 ;
        RECT  17.136 0 17.16 0.084 ;
    END
  END wq_addr[30]
  PIN wq_addr[31]
    DIRECTION OUTPUT ;
    USE SIGNAL ;
    PORT
      LAYER M5 ;
        RECT  17.664 0 17.688 0.084 ;
    END
  END wq_addr[31]
  PIN wq_addr[32]
    DIRECTION OUTPUT ;
    USE SIGNAL ;
    PORT
      LAYER M5 ;
        RECT  18.192 0 18.216 0.084 ;
    END
  END wq_addr[32]
  PIN wq_addr[33]
    DIRECTION OUTPUT ;
    USE SIGNAL ;
    PORT
      LAYER M5 ;
        RECT  18.72 0 18.744 0.084 ;
    END
  END wq_addr[33]
  PIN wq_addr[34]
    DIRECTION OUTPUT ;
    USE SIGNAL ;
    PORT
      LAYER M5 ;
        RECT  19.296 0 19.32 0.084 ;
    END
  END wq_addr[34]
  PIN wq_addr[35]
    DIRECTION OUTPUT ;
    USE SIGNAL ;
    PORT
      LAYER M5 ;
        RECT  19.824 0 19.848 0.084 ;
    END
  END wq_addr[35]
  PIN wq_addr[36]
    DIRECTION OUTPUT ;
    USE SIGNAL ;
    PORT
      LAYER M5 ;
        RECT  20.352 0 20.376 0.084 ;
    END
  END wq_addr[36]
  PIN wq_addr[37]
    DIRECTION OUTPUT ;
    USE SIGNAL ;
    PORT
      LAYER M5 ;
        RECT  20.88 0 20.904 0.084 ;
    END
  END wq_addr[37]
  PIN wq_addr[38]
    DIRECTION OUTPUT ;
    USE SIGNAL ;
    PORT
      LAYER M5 ;
        RECT  21.408 0 21.432 0.084 ;
    END
  END wq_addr[38]
  PIN wq_addr[39]
    DIRECTION OUTPUT ;
    USE SIGNAL ;
    PORT
      LAYER M5 ;
        RECT  21.936 0 21.96 0.084 ;
    END
  END wq_addr[39]
  PIN wq_addr[3]
    DIRECTION OUTPUT ;
    USE SIGNAL ;
    PORT
      LAYER M5 ;
        RECT  2.832 0 2.856 0.084 ;
    END
  END wq_addr[3]
  PIN wq_addr[40]
    DIRECTION OUTPUT ;
    USE SIGNAL ;
    PORT
      LAYER M5 ;
        RECT  22.464 0 22.488 0.084 ;
    END
  END wq_addr[40]
  PIN wq_addr[41]
    DIRECTION OUTPUT ;
    USE SIGNAL ;
    PORT
      LAYER M5 ;
        RECT  22.992 0 23.016 0.084 ;
    END
  END wq_addr[41]
  PIN wq_addr[42]
    DIRECTION OUTPUT ;
    USE SIGNAL ;
    PORT
      LAYER M5 ;
        RECT  23.52 0 23.544 0.084 ;
    END
  END wq_addr[42]
  PIN wq_addr[43]
    DIRECTION OUTPUT ;
    USE SIGNAL ;
    PORT
      LAYER M5 ;
        RECT  24.048 0 24.072 0.084 ;
    END
  END wq_addr[43]
  PIN wq_addr[44]
    DIRECTION OUTPUT ;
    USE SIGNAL ;
    PORT
      LAYER M5 ;
        RECT  24.576 0 24.6 0.084 ;
    END
  END wq_addr[44]
  PIN wq_addr[45]
    DIRECTION OUTPUT ;
    USE SIGNAL ;
    PORT
      LAYER M5 ;
        RECT  25.104 0 25.128 0.084 ;
    END
  END wq_addr[45]
  PIN wq_addr[46]
    DIRECTION OUTPUT ;
    USE SIGNAL ;
    PORT
      LAYER M5 ;
        RECT  25.632 0 25.656 0.084 ;
    END
  END wq_addr[46]
  PIN wq_addr[47]
    DIRECTION OUTPUT ;
    USE SIGNAL ;
    PORT
      LAYER M5 ;
        RECT  26.16 0 26.184 0.084 ;
    END
  END wq_addr[47]
  PIN wq_addr[48]
    DIRECTION OUTPUT ;
    USE SIGNAL ;
    PORT
      LAYER M5 ;
        RECT  26.688 0 26.712 0.084 ;
    END
  END wq_addr[48]
  PIN wq_addr[49]
    DIRECTION OUTPUT ;
    USE SIGNAL ;
    PORT
      LAYER M5 ;
        RECT  27.216 0 27.24 0.084 ;
    END
  END wq_addr[49]
  PIN wq_addr[4]
    DIRECTION OUTPUT ;
    USE SIGNAL ;
    PORT
      LAYER M5 ;
        RECT  3.36 0 3.384 0.084 ;
    END
  END wq_addr[4]
  PIN wq_addr[50]
    DIRECTION OUTPUT ;
    USE SIGNAL ;
    PORT
      LAYER M5 ;
        RECT  27.744 0 27.768 0.084 ;
    END
  END wq_addr[50]
  PIN wq_addr[51]
    DIRECTION OUTPUT ;
    USE SIGNAL ;
    PORT
      LAYER M5 ;
        RECT  28.272 0 28.296 0.084 ;
    END
  END wq_addr[51]
  PIN wq_addr[52]
    DIRECTION OUTPUT ;
    USE SIGNAL ;
    PORT
      LAYER M5 ;
        RECT  28.8 0 28.824 0.084 ;
    END
  END wq_addr[52]
  PIN wq_addr[53]
    DIRECTION OUTPUT ;
    USE SIGNAL ;
    PORT
      LAYER M5 ;
        RECT  29.328 0 29.352 0.084 ;
    END
  END wq_addr[53]
  PIN wq_addr[54]
    DIRECTION OUTPUT ;
    USE SIGNAL ;
    PORT
      LAYER M5 ;
        RECT  29.856 0 29.88 0.084 ;
    END
  END wq_addr[54]
  PIN wq_addr[55]
    DIRECTION OUTPUT ;
    USE SIGNAL ;
    PORT
      LAYER M5 ;
        RECT  30.384 0 30.408 0.084 ;
    END
  END wq_addr[55]
  PIN wq_addr[56]
    DIRECTION OUTPUT ;
    USE SIGNAL ;
    PORT
      LAYER M5 ;
        RECT  30.912 0 30.936 0.084 ;
    END
  END wq_addr[56]
  PIN wq_addr[57]
    DIRECTION OUTPUT ;
    USE SIGNAL ;
    PORT
      LAYER M5 ;
        RECT  31.44 0 31.464 0.084 ;
    END
  END wq_addr[57]
  PIN wq_addr[58]
    DIRECTION OUTPUT ;
    USE SIGNAL ;
    PORT
      LAYER M5 ;
        RECT  32.016 0 32.04 0.084 ;
    END
  END wq_addr[58]
  PIN wq_addr[59]
    DIRECTION OUTPUT ;
    USE SIGNAL ;
    PORT
      LAYER M5 ;
        RECT  32.544 0 32.568 0.084 ;
    END
  END wq_addr[59]
  PIN wq_addr[5]
    DIRECTION OUTPUT ;
    USE SIGNAL ;
    PORT
      LAYER M5 ;
        RECT  3.888 0 3.912 0.084 ;
    END
  END wq_addr[5]
  PIN wq_addr[60]
    DIRECTION OUTPUT ;
    USE SIGNAL ;
    PORT
      LAYER M5 ;
        RECT  33.072 0 33.096 0.084 ;
    END
  END wq_addr[60]
  PIN wq_addr[61]
    DIRECTION OUTPUT ;
    USE SIGNAL ;
    PORT
      LAYER M5 ;
        RECT  33.6 0 33.624 0.084 ;
    END
  END wq_addr[61]
  PIN wq_addr[62]
    DIRECTION OUTPUT ;
    USE SIGNAL ;
    PORT
      LAYER M5 ;
        RECT  34.128 0 34.152 0.084 ;
    END
  END wq_addr[62]
  PIN wq_addr[63]
    DIRECTION OUTPUT ;
    USE SIGNAL ;
    PORT
      LAYER M5 ;
        RECT  34.656 0 34.68 0.084 ;
    END
  END wq_addr[63]
  PIN wq_addr[64]
    DIRECTION OUTPUT ;
    USE SIGNAL ;
    PORT
      LAYER M5 ;
        RECT  35.184 0 35.208 0.084 ;
    END
  END wq_addr[64]
  PIN wq_addr[65]
    DIRECTION OUTPUT ;
    USE SIGNAL ;
    PORT
      LAYER M5 ;
        RECT  35.712 0 35.736 0.084 ;
    END
  END wq_addr[65]
  PIN wq_addr[66]
    DIRECTION OUTPUT ;
    USE SIGNAL ;
    PORT
      LAYER M5 ;
        RECT  36.24 0 36.264 0.084 ;
    END
  END wq_addr[66]
  PIN wq_addr[67]
    DIRECTION OUTPUT ;
    USE SIGNAL ;
    PORT
      LAYER M5 ;
        RECT  36.768 0 36.792 0.084 ;
    END
  END wq_addr[67]
  PIN wq_addr[68]
    DIRECTION OUTPUT ;
    USE SIGNAL ;
    PORT
      LAYER M5 ;
        RECT  37.296 0 37.32 0.084 ;
    END
  END wq_addr[68]
  PIN wq_addr[69]
    DIRECTION OUTPUT ;
    USE SIGNAL ;
    PORT
      LAYER M5 ;
        RECT  37.824 0 37.848 0.084 ;
    END
  END wq_addr[69]
  PIN wq_addr[6]
    DIRECTION OUTPUT ;
    USE SIGNAL ;
    PORT
      LAYER M5 ;
        RECT  4.416 0 4.44 0.084 ;
    END
  END wq_addr[6]
  PIN wq_addr[70]
    DIRECTION OUTPUT ;
    USE SIGNAL ;
    PORT
      LAYER M5 ;
        RECT  38.352 0 38.376 0.084 ;
    END
  END wq_addr[70]
  PIN wq_addr[71]
    DIRECTION OUTPUT ;
    USE SIGNAL ;
    PORT
      LAYER M5 ;
        RECT  38.88 0 38.904 0.084 ;
    END
  END wq_addr[71]
  PIN wq_addr[72]
    DIRECTION OUTPUT ;
    USE SIGNAL ;
    PORT
      LAYER M5 ;
        RECT  39.408 0 39.432 0.084 ;
    END
  END wq_addr[72]
  PIN wq_addr[73]
    DIRECTION OUTPUT ;
    USE SIGNAL ;
    PORT
      LAYER M5 ;
        RECT  39.936 0 39.96 0.084 ;
    END
  END wq_addr[73]
  PIN wq_addr[74]
    DIRECTION OUTPUT ;
    USE SIGNAL ;
    PORT
      LAYER M5 ;
        RECT  40.464 0 40.488 0.084 ;
    END
  END wq_addr[74]
  PIN wq_addr[75]
    DIRECTION OUTPUT ;
    USE SIGNAL ;
    PORT
      LAYER M5 ;
        RECT  40.992 0 41.016 0.084 ;
    END
  END wq_addr[75]
  PIN wq_addr[76]
    DIRECTION OUTPUT ;
    USE SIGNAL ;
    PORT
      LAYER M5 ;
        RECT  41.52 0 41.544 0.084 ;
    END
  END wq_addr[76]
  PIN wq_addr[77]
    DIRECTION OUTPUT ;
    USE SIGNAL ;
    PORT
      LAYER M5 ;
        RECT  42.048 0 42.072 0.084 ;
    END
  END wq_addr[77]
  PIN wq_addr[78]
    DIRECTION OUTPUT ;
    USE SIGNAL ;
    PORT
      LAYER M5 ;
        RECT  42.576 0 42.6 0.084 ;
    END
  END wq_addr[78]
  PIN wq_addr[79]
    DIRECTION OUTPUT ;
    USE SIGNAL ;
    PORT
      LAYER M5 ;
        RECT  43.104 0 43.128 0.084 ;
    END
  END wq_addr[79]
  PIN wq_addr[7]
    DIRECTION OUTPUT ;
    USE SIGNAL ;
    PORT
      LAYER M5 ;
        RECT  4.944 0 4.968 0.084 ;
    END
  END wq_addr[7]
  PIN wq_addr[80]
    DIRECTION OUTPUT ;
    USE SIGNAL ;
    PORT
      LAYER M5 ;
        RECT  43.632 0 43.656 0.084 ;
    END
  END wq_addr[80]
  PIN wq_addr[81]
    DIRECTION OUTPUT ;
    USE SIGNAL ;
    PORT
      LAYER M5 ;
        RECT  44.16 0 44.184 0.084 ;
    END
  END wq_addr[81]
  PIN wq_addr[82]
    DIRECTION OUTPUT ;
    USE SIGNAL ;
    PORT
      LAYER M5 ;
        RECT  44.736 0 44.76 0.084 ;
    END
  END wq_addr[82]
  PIN wq_addr[83]
    DIRECTION OUTPUT ;
    USE SIGNAL ;
    PORT
      LAYER M5 ;
        RECT  45.264 0 45.288 0.084 ;
    END
  END wq_addr[83]
  PIN wq_addr[84]
    DIRECTION OUTPUT ;
    USE SIGNAL ;
    PORT
      LAYER M5 ;
        RECT  45.792 0 45.816 0.084 ;
    END
  END wq_addr[84]
  PIN wq_addr[85]
    DIRECTION OUTPUT ;
    USE SIGNAL ;
    PORT
      LAYER M5 ;
        RECT  46.32 0 46.344 0.084 ;
    END
  END wq_addr[85]
  PIN wq_addr[86]
    DIRECTION OUTPUT ;
    USE SIGNAL ;
    PORT
      LAYER M5 ;
        RECT  46.848 0 46.872 0.084 ;
    END
  END wq_addr[86]
  PIN wq_addr[87]
    DIRECTION OUTPUT ;
    USE SIGNAL ;
    PORT
      LAYER M5 ;
        RECT  47.376 0 47.4 0.084 ;
    END
  END wq_addr[87]
  PIN wq_addr[88]
    DIRECTION OUTPUT ;
    USE SIGNAL ;
    PORT
      LAYER M5 ;
        RECT  47.904 0 47.928 0.084 ;
    END
  END wq_addr[88]
  PIN wq_addr[89]
    DIRECTION OUTPUT ;
    USE SIGNAL ;
    PORT
      LAYER M5 ;
        RECT  48.432 0 48.456 0.084 ;
    END
  END wq_addr[89]
  PIN wq_addr[8]
    DIRECTION OUTPUT ;
    USE SIGNAL ;
    PORT
      LAYER M5 ;
        RECT  5.472 0 5.496 0.084 ;
    END
  END wq_addr[8]
  PIN wq_addr[90]
    DIRECTION OUTPUT ;
    USE SIGNAL ;
    PORT
      LAYER M5 ;
        RECT  48.96 0 48.984 0.084 ;
    END
  END wq_addr[90]
  PIN wq_addr[91]
    DIRECTION OUTPUT ;
    USE SIGNAL ;
    PORT
      LAYER M5 ;
        RECT  49.488 0 49.512 0.084 ;
    END
  END wq_addr[91]
  PIN wq_addr[92]
    DIRECTION OUTPUT ;
    USE SIGNAL ;
    PORT
      LAYER M5 ;
        RECT  50.016 0 50.04 0.084 ;
    END
  END wq_addr[92]
  PIN wq_addr[93]
    DIRECTION OUTPUT ;
    USE SIGNAL ;
    PORT
      LAYER M5 ;
        RECT  50.544 0 50.568 0.084 ;
    END
  END wq_addr[93]
  PIN wq_addr[94]
    DIRECTION OUTPUT ;
    USE SIGNAL ;
    PORT
      LAYER M5 ;
        RECT  51.072 0 51.096 0.084 ;
    END
  END wq_addr[94]
  PIN wq_addr[95]
    DIRECTION OUTPUT ;
    USE SIGNAL ;
    PORT
      LAYER M5 ;
        RECT  51.6 0 51.624 0.084 ;
    END
  END wq_addr[95]
  PIN wq_addr[96]
    DIRECTION OUTPUT ;
    USE SIGNAL ;
    PORT
      LAYER M5 ;
        RECT  52.128 0 52.152 0.084 ;
    END
  END wq_addr[96]
  PIN wq_addr[97]
    DIRECTION OUTPUT ;
    USE SIGNAL ;
    PORT
      LAYER M5 ;
        RECT  52.656 0 52.68 0.084 ;
    END
  END wq_addr[97]
  PIN wq_addr[98]
    DIRECTION OUTPUT ;
    USE SIGNAL ;
    PORT
      LAYER M5 ;
        RECT  53.184 0 53.208 0.084 ;
    END
  END wq_addr[98]
  PIN wq_addr[99]
    DIRECTION OUTPUT ;
    USE SIGNAL ;
    PORT
      LAYER M5 ;
        RECT  53.712 0 53.736 0.084 ;
    END
  END wq_addr[99]
  PIN wq_addr[9]
    DIRECTION OUTPUT ;
    USE SIGNAL ;
    PORT
      LAYER M5 ;
        RECT  6 0 6.024 0.084 ;
    END
  END wq_addr[9]
  PIN wq_mask[0]
    DIRECTION OUTPUT ;
    USE SIGNAL ;
    PORT
      LAYER M5 ;
        RECT  69.072 0 69.096 0.084 ;
    END
  END wq_mask[0]
  PIN wq_mask[10]
    DIRECTION OUTPUT ;
    USE SIGNAL ;
    PORT
      LAYER M5 ;
        RECT  74.4 0 74.424 0.084 ;
    END
  END wq_mask[10]
  PIN wq_mask[11]
    DIRECTION OUTPUT ;
    USE SIGNAL ;
    PORT
      LAYER M5 ;
        RECT  74.928 0 74.952 0.084 ;
    END
  END wq_mask[11]
  PIN wq_mask[12]
    DIRECTION OUTPUT ;
    USE SIGNAL ;
    PORT
      LAYER M5 ;
        RECT  75.456 0 75.48 0.084 ;
    END
  END wq_mask[12]
  PIN wq_mask[13]
    DIRECTION OUTPUT ;
    USE SIGNAL ;
    PORT
      LAYER M5 ;
        RECT  75.984 0 76.008 0.084 ;
    END
  END wq_mask[13]
  PIN wq_mask[14]
    DIRECTION OUTPUT ;
    USE SIGNAL ;
    PORT
      LAYER M5 ;
        RECT  76.512 0 76.536 0.084 ;
    END
  END wq_mask[14]
  PIN wq_mask[15]
    DIRECTION OUTPUT ;
    USE SIGNAL ;
    PORT
      LAYER M5 ;
        RECT  77.04 0 77.064 0.084 ;
    END
  END wq_mask[15]
  PIN wq_mask[16]
    DIRECTION OUTPUT ;
    USE SIGNAL ;
    PORT
      LAYER M5 ;
        RECT  77.568 0 77.592 0.084 ;
    END
  END wq_mask[16]
  PIN wq_mask[17]
    DIRECTION OUTPUT ;
    USE SIGNAL ;
    PORT
      LAYER M5 ;
        RECT  78.096 0 78.12 0.084 ;
    END
  END wq_mask[17]
  PIN wq_mask[18]
    DIRECTION OUTPUT ;
    USE SIGNAL ;
    PORT
      LAYER M5 ;
        RECT  78.624 0 78.648 0.084 ;
    END
  END wq_mask[18]
  PIN wq_mask[19]
    DIRECTION OUTPUT ;
    USE SIGNAL ;
    PORT
      LAYER M5 ;
        RECT  79.152 0 79.176 0.084 ;
    END
  END wq_mask[19]
  PIN wq_mask[1]
    DIRECTION OUTPUT ;
    USE SIGNAL ;
    PORT
      LAYER M5 ;
        RECT  69.6 0 69.624 0.084 ;
    END
  END wq_mask[1]
  PIN wq_mask[20]
    DIRECTION OUTPUT ;
    USE SIGNAL ;
    PORT
      LAYER M5 ;
        RECT  79.68 0 79.704 0.084 ;
    END
  END wq_mask[20]
  PIN wq_mask[21]
    DIRECTION OUTPUT ;
    USE SIGNAL ;
    PORT
      LAYER M5 ;
        RECT  80.208 0 80.232 0.084 ;
    END
  END wq_mask[21]
  PIN wq_mask[22]
    DIRECTION OUTPUT ;
    USE SIGNAL ;
    PORT
      LAYER M5 ;
        RECT  80.736 0 80.76 0.084 ;
    END
  END wq_mask[22]
  PIN wq_mask[23]
    DIRECTION OUTPUT ;
    USE SIGNAL ;
    PORT
      LAYER M5 ;
        RECT  81.264 0 81.288 0.084 ;
    END
  END wq_mask[23]
  PIN wq_mask[24]
    DIRECTION OUTPUT ;
    USE SIGNAL ;
    PORT
      LAYER M5 ;
        RECT  81.792 0 81.816 0.084 ;
    END
  END wq_mask[24]
  PIN wq_mask[25]
    DIRECTION OUTPUT ;
    USE SIGNAL ;
    PORT
      LAYER M5 ;
        RECT  82.32 0 82.344 0.084 ;
    END
  END wq_mask[25]
  PIN wq_mask[26]
    DIRECTION OUTPUT ;
    USE SIGNAL ;
    PORT
      LAYER M5 ;
        RECT  82.896 0 82.92 0.084 ;
    END
  END wq_mask[26]
  PIN wq_mask[27]
    DIRECTION OUTPUT ;
    USE SIGNAL ;
    PORT
      LAYER M5 ;
        RECT  83.424 0 83.448 0.084 ;
    END
  END wq_mask[27]
  PIN wq_mask[28]
    DIRECTION OUTPUT ;
    USE SIGNAL ;
    PORT
      LAYER M5 ;
        RECT  83.952 0 83.976 0.084 ;
    END
  END wq_mask[28]
  PIN wq_mask[29]
    DIRECTION OUTPUT ;
    USE SIGNAL ;
    PORT
      LAYER M5 ;
        RECT  84.48 0 84.504 0.084 ;
    END
  END wq_mask[29]
  PIN wq_mask[2]
    DIRECTION OUTPUT ;
    USE SIGNAL ;
    PORT
      LAYER M5 ;
        RECT  70.176 0 70.2 0.084 ;
    END
  END wq_mask[2]
  PIN wq_mask[30]
    DIRECTION OUTPUT ;
    USE SIGNAL ;
    PORT
      LAYER M5 ;
        RECT  85.008 0 85.032 0.084 ;
    END
  END wq_mask[30]
  PIN wq_mask[31]
    DIRECTION OUTPUT ;
    USE SIGNAL ;
    PORT
      LAYER M5 ;
        RECT  85.536 0 85.56 0.084 ;
    END
  END wq_mask[31]
  PIN wq_mask[32]
    DIRECTION OUTPUT ;
    USE SIGNAL ;
    PORT
      LAYER M5 ;
        RECT  86.064 0 86.088 0.084 ;
    END
  END wq_mask[32]
  PIN wq_mask[33]
    DIRECTION OUTPUT ;
    USE SIGNAL ;
    PORT
      LAYER M5 ;
        RECT  86.592 0 86.616 0.084 ;
    END
  END wq_mask[33]
  PIN wq_mask[34]
    DIRECTION OUTPUT ;
    USE SIGNAL ;
    PORT
      LAYER M5 ;
        RECT  87.12 0 87.144 0.084 ;
    END
  END wq_mask[34]
  PIN wq_mask[35]
    DIRECTION OUTPUT ;
    USE SIGNAL ;
    PORT
      LAYER M5 ;
        RECT  87.648 0 87.672 0.084 ;
    END
  END wq_mask[35]
  PIN wq_mask[36]
    DIRECTION OUTPUT ;
    USE SIGNAL ;
    PORT
      LAYER M5 ;
        RECT  88.176 0 88.2 0.084 ;
    END
  END wq_mask[36]
  PIN wq_mask[37]
    DIRECTION OUTPUT ;
    USE SIGNAL ;
    PORT
      LAYER M5 ;
        RECT  88.704 0 88.728 0.084 ;
    END
  END wq_mask[37]
  PIN wq_mask[38]
    DIRECTION OUTPUT ;
    USE SIGNAL ;
    PORT
      LAYER M5 ;
        RECT  89.232 0 89.256 0.084 ;
    END
  END wq_mask[38]
  PIN wq_mask[39]
    DIRECTION OUTPUT ;
    USE SIGNAL ;
    PORT
      LAYER M5 ;
        RECT  89.76 0 89.784 0.084 ;
    END
  END wq_mask[39]
  PIN wq_mask[3]
    DIRECTION OUTPUT ;
    USE SIGNAL ;
    PORT
      LAYER M5 ;
        RECT  70.704 0 70.728 0.084 ;
    END
  END wq_mask[3]
  PIN wq_mask[40]
    DIRECTION OUTPUT ;
    USE SIGNAL ;
    PORT
      LAYER M5 ;
        RECT  90.288 0 90.312 0.084 ;
    END
  END wq_mask[40]
  PIN wq_mask[41]
    DIRECTION OUTPUT ;
    USE SIGNAL ;
    PORT
      LAYER M5 ;
        RECT  90.816 0 90.84 0.084 ;
    END
  END wq_mask[41]
  PIN wq_mask[42]
    DIRECTION OUTPUT ;
    USE SIGNAL ;
    PORT
      LAYER M5 ;
        RECT  91.344 0 91.368 0.084 ;
    END
  END wq_mask[42]
  PIN wq_mask[43]
    DIRECTION OUTPUT ;
    USE SIGNAL ;
    PORT
      LAYER M5 ;
        RECT  91.872 0 91.896 0.084 ;
    END
  END wq_mask[43]
  PIN wq_mask[44]
    DIRECTION OUTPUT ;
    USE SIGNAL ;
    PORT
      LAYER M5 ;
        RECT  92.4 0 92.424 0.084 ;
    END
  END wq_mask[44]
  PIN wq_mask[45]
    DIRECTION OUTPUT ;
    USE SIGNAL ;
    PORT
      LAYER M5 ;
        RECT  92.928 0 92.952 0.084 ;
    END
  END wq_mask[45]
  PIN wq_mask[46]
    DIRECTION OUTPUT ;
    USE SIGNAL ;
    PORT
      LAYER M5 ;
        RECT  93.456 0 93.48 0.084 ;
    END
  END wq_mask[46]
  PIN wq_mask[47]
    DIRECTION OUTPUT ;
    USE SIGNAL ;
    PORT
      LAYER M5 ;
        RECT  93.984 0 94.008 0.084 ;
    END
  END wq_mask[47]
  PIN wq_mask[48]
    DIRECTION OUTPUT ;
    USE SIGNAL ;
    PORT
      LAYER M5 ;
        RECT  94.512 0 94.536 0.084 ;
    END
  END wq_mask[48]
  PIN wq_mask[49]
    DIRECTION OUTPUT ;
    USE SIGNAL ;
    PORT
      LAYER M5 ;
        RECT  95.04 0 95.064 0.084 ;
    END
  END wq_mask[49]
  PIN wq_mask[4]
    DIRECTION OUTPUT ;
    USE SIGNAL ;
    PORT
      LAYER M5 ;
        RECT  71.232 0 71.256 0.084 ;
    END
  END wq_mask[4]
  PIN wq_mask[50]
    DIRECTION OUTPUT ;
    USE SIGNAL ;
    PORT
      LAYER M5 ;
        RECT  95.616 0 95.64 0.084 ;
    END
  END wq_mask[50]
  PIN wq_mask[51]
    DIRECTION OUTPUT ;
    USE SIGNAL ;
    PORT
      LAYER M5 ;
        RECT  96.144 0 96.168 0.084 ;
    END
  END wq_mask[51]
  PIN wq_mask[52]
    DIRECTION OUTPUT ;
    USE SIGNAL ;
    PORT
      LAYER M5 ;
        RECT  96.672 0 96.696 0.084 ;
    END
  END wq_mask[52]
  PIN wq_mask[53]
    DIRECTION OUTPUT ;
    USE SIGNAL ;
    PORT
      LAYER M5 ;
        RECT  97.2 0 97.224 0.084 ;
    END
  END wq_mask[53]
  PIN wq_mask[54]
    DIRECTION OUTPUT ;
    USE SIGNAL ;
    PORT
      LAYER M5 ;
        RECT  97.728 0 97.752 0.084 ;
    END
  END wq_mask[54]
  PIN wq_mask[55]
    DIRECTION OUTPUT ;
    USE SIGNAL ;
    PORT
      LAYER M5 ;
        RECT  98.256 0 98.28 0.084 ;
    END
  END wq_mask[55]
  PIN wq_mask[56]
    DIRECTION OUTPUT ;
    USE SIGNAL ;
    PORT
      LAYER M5 ;
        RECT  98.784 0 98.808 0.084 ;
    END
  END wq_mask[56]
  PIN wq_mask[57]
    DIRECTION OUTPUT ;
    USE SIGNAL ;
    PORT
      LAYER M5 ;
        RECT  99.312 0 99.336 0.084 ;
    END
  END wq_mask[57]
  PIN wq_mask[58]
    DIRECTION OUTPUT ;
    USE SIGNAL ;
    PORT
      LAYER M5 ;
        RECT  99.84 0 99.864 0.084 ;
    END
  END wq_mask[58]
  PIN wq_mask[59]
    DIRECTION OUTPUT ;
    USE SIGNAL ;
    PORT
      LAYER M5 ;
        RECT  100.368 0 100.392 0.084 ;
    END
  END wq_mask[59]
  PIN wq_mask[5]
    DIRECTION OUTPUT ;
    USE SIGNAL ;
    PORT
      LAYER M5 ;
        RECT  71.76 0 71.784 0.084 ;
    END
  END wq_mask[5]
  PIN wq_mask[60]
    DIRECTION OUTPUT ;
    USE SIGNAL ;
    PORT
      LAYER M5 ;
        RECT  100.896 0 100.92 0.084 ;
    END
  END wq_mask[60]
  PIN wq_mask[61]
    DIRECTION OUTPUT ;
    USE SIGNAL ;
    PORT
      LAYER M5 ;
        RECT  101.424 0 101.448 0.084 ;
    END
  END wq_mask[61]
  PIN wq_mask[62]
    DIRECTION OUTPUT ;
    USE SIGNAL ;
    PORT
      LAYER M5 ;
        RECT  101.952 0 101.976 0.084 ;
    END
  END wq_mask[62]
  PIN wq_mask[63]
    DIRECTION OUTPUT ;
    USE SIGNAL ;
    PORT
      LAYER M5 ;
        RECT  102.48 0 102.504 0.084 ;
    END
  END wq_mask[63]
  PIN wq_mask[6]
    DIRECTION OUTPUT ;
    USE SIGNAL ;
    PORT
      LAYER M5 ;
        RECT  72.288 0 72.312 0.084 ;
    END
  END wq_mask[6]
  PIN wq_mask[7]
    DIRECTION OUTPUT ;
    USE SIGNAL ;
    PORT
      LAYER M5 ;
        RECT  72.816 0 72.84 0.084 ;
    END
  END wq_mask[7]
  PIN wq_mask[8]
    DIRECTION OUTPUT ;
    USE SIGNAL ;
    PORT
      LAYER M5 ;
        RECT  73.344 0 73.368 0.084 ;
    END
  END wq_mask[8]
  PIN wq_mask[9]
    DIRECTION OUTPUT ;
    USE SIGNAL ;
    PORT
      LAYER M5 ;
        RECT  73.872 0 73.896 0.084 ;
    END
  END wq_mask[9]
  PIN wq_v[0]
    DIRECTION OUTPUT ;
    USE SIGNAL ;
    PORT
      LAYER M5 ;
        RECT  103.008 0 103.032 0.084 ;
    END
  END wq_v[0]
  PIN wq_v[1]
    DIRECTION OUTPUT ;
    USE SIGNAL ;
    PORT
      LAYER M5 ;
        RECT  103.536 0 103.56 0.084 ;
    END
  END wq_v[1]
  PIN wq_v[2]
    DIRECTION OUTPUT ;
    USE SIGNAL ;
    PORT
      LAYER M5 ;
        RECT  104.064 0 104.088 0.084 ;
    END
  END wq_v[2]
  PIN wq_v[3]
    DIRECTION OUTPUT ;
    USE SIGNAL ;
    PORT
      LAYER M5 ;
        RECT  104.592 0 104.616 0.084 ;
    END
  END wq_v[3]
  PIN wq_v[4]
    DIRECTION OUTPUT ;
    USE SIGNAL ;
    PORT
      LAYER M5 ;
        RECT  105.12 0 105.144 0.084 ;
    END
  END wq_v[4]
  PIN wq_v[5]
    DIRECTION OUTPUT ;
    USE SIGNAL ;
    PORT
      LAYER M5 ;
        RECT  105.648 0 105.672 0.084 ;
    END
  END wq_v[5]
  PIN wq_v[6]
    DIRECTION OUTPUT ;
    USE SIGNAL ;
    PORT
      LAYER M5 ;
        RECT  106.176 0 106.2 0.084 ;
    END
  END wq_v[6]
  PIN wq_v[7]
    DIRECTION OUTPUT ;
    USE SIGNAL ;
    PORT
      LAYER M5 ;
        RECT  106.704 0 106.728 0.084 ;
    END
  END wq_v[7]
  PIN wsel[0]
    DIRECTION OUTPUT ;
    USE SIGNAL ;
    PORT
      LAYER M4 ;
        RECT  107.916 126.288 108 126.312 ;
    END
  END wsel[0]
  PIN wsel[1]
    DIRECTION OUTPUT ;
    USE SIGNAL ;
    PORT
      LAYER M4 ;
        RECT  107.916 127.2 108 127.224 ;
    END
  END wsel[1]
  PIN wsel[2]
    DIRECTION OUTPUT ;
    USE SIGNAL ;
    PORT
      LAYER M4 ;
        RECT  107.916 128.112 108 128.136 ;
    END
  END wsel[2]
  PIN VDD
    DIRECTION INOUT ;
    USE POWER ;
    PORT
      LAYER M5 ;
        RECT  105.192 2.151 105.312 127.449 ;
        RECT  99.792 2.151 99.912 127.449 ;
        RECT  94.392 2.151 94.512 127.449 ;
        RECT  88.992 2.151 89.112 127.449 ;
        RECT  83.592 2.151 83.712 127.449 ;
        RECT  78.192 2.151 78.312 127.449 ;
        RECT  72.792 2.151 72.912 127.449 ;
        RECT  67.392 2.151 67.512 127.449 ;
        RECT  61.992 2.151 62.112 127.449 ;
        RECT  56.592 2.151 56.712 127.449 ;
        RECT  51.192 2.151 51.312 127.449 ;
        RECT  45.792 2.151 45.912 127.449 ;
        RECT  40.392 2.151 40.512 127.449 ;
        RECT  34.992 2.151 35.112 127.449 ;
        RECT  29.592 2.151 29.712 127.449 ;
        RECT  24.192 2.151 24.312 127.449 ;
        RECT  18.792 2.151 18.912 127.449 ;
        RECT  13.392 2.151 13.512 127.449 ;
        RECT  7.992 2.151 8.112 127.449 ;
        RECT  2.592 2.151 2.712 127.449 ;
    END
  END VDD
  PIN VSS
    DIRECTION INOUT ;
    USE GROUND ;
    PORT
      LAYER M5 ;
        RECT  105 2.137 105.12 127.463 ;
        RECT  99.6 2.137 99.72 127.463 ;
        RECT  94.2 2.137 94.32 127.463 ;
        RECT  88.8 2.137 88.92 127.463 ;
        RECT  83.4 2.137 83.52 127.463 ;
        RECT  78 2.137 78.12 127.463 ;
        RECT  72.6 2.137 72.72 127.463 ;
        RECT  67.2 2.137 67.32 127.463 ;
        RECT  61.8 2.137 61.92 127.463 ;
        RECT  56.4 2.137 56.52 127.463 ;
        RECT  51 2.137 51.12 127.463 ;
        RECT  45.6 2.137 45.72 127.463 ;
        RECT  40.2 2.137 40.32 127.463 ;
        RECT  34.8 2.137 34.92 127.463 ;
        RECT  29.4 2.137 29.52 127.463 ;
        RECT  24 2.137 24.12 127.463 ;
        RECT  18.6 2.137 18.72 127.463 ;
        RECT  13.2 2.137 13.32 127.463 ;
        RECT  7.8 2.137 7.92 127.463 ;
        RECT  2.4 2.137 2.52 127.463 ;
    END
  END VSS
  # OT_OBS_CLOSED layer=M5 d_um=1.536 added=323
  OBS
    LAYER RVTN ;
     RECT  2.16 2.16 105.84 2.295 ;
     RECT  2.16 2.565 105.84 2.835 ;
     RECT  2.16 3.105 105.84 3.375 ;
     RECT  2.16 3.645 105.84 3.915 ;
     RECT  2.16 4.185 105.84 4.455 ;
     RECT  2.16 4.725 105.84 4.995 ;
     RECT  2.16 5.265 105.84 5.535 ;
     RECT  2.16 5.805 105.84 6.075 ;
     RECT  2.16 6.345 105.84 6.615 ;
     RECT  2.16 6.885 105.84 7.155 ;
     RECT  2.16 7.425 105.84 7.695 ;
     RECT  2.16 7.965 105.84 8.235 ;
     RECT  2.16 8.505 105.84 8.775 ;
     RECT  2.16 9.045 105.84 9.315 ;
     RECT  2.16 9.585 105.84 9.855 ;
     RECT  2.16 10.125 105.84 10.395 ;
     RECT  2.16 10.665 105.84 10.935 ;
     RECT  2.16 11.205 105.84 11.475 ;
     RECT  2.16 11.745 105.84 12.015 ;
     RECT  2.16 12.285 105.84 12.555 ;
     RECT  2.16 12.825 105.84 13.095 ;
     RECT  2.16 13.365 105.84 13.635 ;
     RECT  2.16 13.905 105.84 14.175 ;
     RECT  2.16 14.445 105.84 14.715 ;
     RECT  2.16 14.985 105.84 15.255 ;
     RECT  2.16 15.525 105.84 15.795 ;
     RECT  2.16 16.065 105.84 16.335 ;
     RECT  2.16 16.605 105.84 16.875 ;
     RECT  2.16 17.145 105.84 17.415 ;
     RECT  2.16 17.685 105.84 17.955 ;
     RECT  2.16 18.225 105.84 18.495 ;
     RECT  2.16 18.765 105.84 19.035 ;
     RECT  2.16 19.305 105.84 19.575 ;
     RECT  2.16 19.845 105.84 20.115 ;
     RECT  2.16 20.385 105.84 20.655 ;
     RECT  2.16 20.925 105.84 21.195 ;
     RECT  2.16 21.465 105.84 21.735 ;
     RECT  2.16 22.005 105.84 22.275 ;
     RECT  2.16 22.545 105.84 22.815 ;
     RECT  2.16 23.085 105.84 23.355 ;
     RECT  2.16 23.625 105.84 23.76 ;
     RECT  2.16 23.76 35.964 23.895 ;
     RECT  73.764 23.76 105.84 23.895 ;
     RECT  2.16 24.165 35.964 24.435 ;
     RECT  73.764 24.165 105.84 24.435 ;
     RECT  2.16 24.705 35.964 24.975 ;
     RECT  73.764 24.705 105.84 24.975 ;
     RECT  2.16 25.245 35.964 25.515 ;
     RECT  73.764 25.245 105.84 25.515 ;
     RECT  2.16 25.785 35.964 26.055 ;
     RECT  73.764 25.785 105.84 26.055 ;
     RECT  2.16 26.325 35.964 26.595 ;
     RECT  73.764 26.325 105.84 26.595 ;
     RECT  2.16 26.865 35.964 27.135 ;
     RECT  73.764 26.865 105.84 27.135 ;
     RECT  2.16 27.405 35.964 27.675 ;
     RECT  73.764 27.405 105.84 27.675 ;
     RECT  2.16 27.945 35.964 28.215 ;
     RECT  73.764 27.945 105.84 28.215 ;
     RECT  2.16 28.485 35.964 28.755 ;
     RECT  73.764 28.485 105.84 28.755 ;
     RECT  2.16 29.025 35.964 29.295 ;
     RECT  73.764 29.025 105.84 29.295 ;
     RECT  2.16 29.565 35.964 29.835 ;
     RECT  73.764 29.565 105.84 29.835 ;
     RECT  2.16 30.105 35.964 30.375 ;
     RECT  73.764 30.105 105.84 30.375 ;
     RECT  2.16 30.645 35.964 30.915 ;
     RECT  73.764 30.645 105.84 30.915 ;
     RECT  2.16 31.185 35.964 31.455 ;
     RECT  73.764 31.185 105.84 31.455 ;
     RECT  2.16 31.725 35.964 31.995 ;
     RECT  73.764 31.725 105.84 31.995 ;
     RECT  2.16 32.265 35.964 32.535 ;
     RECT  73.764 32.265 105.84 32.535 ;
     RECT  2.16 32.805 35.964 33.075 ;
     RECT  73.764 32.805 105.84 33.075 ;
     RECT  2.16 33.345 35.964 33.615 ;
     RECT  73.764 33.345 105.84 33.615 ;
     RECT  2.16 33.885 35.964 34.155 ;
     RECT  73.764 33.885 105.84 34.155 ;
     RECT  2.16 34.425 35.964 34.695 ;
     RECT  73.764 34.425 105.84 34.695 ;
     RECT  2.16 34.965 35.964 35.235 ;
     RECT  73.764 34.965 105.84 35.235 ;
     RECT  2.16 35.505 35.964 35.775 ;
     RECT  73.764 35.505 105.84 35.775 ;
     RECT  2.16 36.045 35.964 36.315 ;
     RECT  73.764 36.045 105.84 36.315 ;
     RECT  2.16 36.585 35.964 36.855 ;
     RECT  73.764 36.585 105.84 36.855 ;
     RECT  2.16 37.125 35.964 37.395 ;
     RECT  73.764 37.125 105.84 37.395 ;
     RECT  2.16 37.665 35.964 37.935 ;
     RECT  73.764 37.665 105.84 37.935 ;
     RECT  2.16 38.205 35.964 38.475 ;
     RECT  73.764 38.205 105.84 38.475 ;
     RECT  2.16 38.745 35.964 39.015 ;
     RECT  73.764 38.745 105.84 39.015 ;
     RECT  2.16 39.285 35.964 39.555 ;
     RECT  73.764 39.285 105.84 39.555 ;
     RECT  2.16 39.825 35.964 40.095 ;
     RECT  73.764 39.825 105.84 40.095 ;
     RECT  2.16 40.365 35.964 40.635 ;
     RECT  73.764 40.365 105.84 40.635 ;
     RECT  2.16 40.905 35.964 41.175 ;
     RECT  73.764 40.905 105.84 41.175 ;
     RECT  2.16 41.445 35.964 41.715 ;
     RECT  73.764 41.445 105.84 41.715 ;
     RECT  2.16 41.985 35.964 42.255 ;
     RECT  73.764 41.985 105.84 42.255 ;
     RECT  2.16 42.525 35.964 42.795 ;
     RECT  73.764 42.525 105.84 42.795 ;
     RECT  2.16 43.065 35.964 43.335 ;
     RECT  73.764 43.065 105.84 43.335 ;
     RECT  2.16 43.605 35.964 43.875 ;
     RECT  73.764 43.605 105.84 43.875 ;
     RECT  2.16 44.145 35.964 44.415 ;
     RECT  73.764 44.145 105.84 44.415 ;
     RECT  2.16 44.685 35.964 44.955 ;
     RECT  73.764 44.685 105.84 44.955 ;
     RECT  2.16 45.225 35.964 45.495 ;
     RECT  73.764 45.225 105.84 45.495 ;
     RECT  2.16 45.765 35.964 46.035 ;
     RECT  73.764 45.765 105.84 46.035 ;
     RECT  2.16 46.305 35.964 46.575 ;
     RECT  73.764 46.305 105.84 46.575 ;
     RECT  2.16 46.845 35.964 47.115 ;
     RECT  73.764 46.845 105.84 47.115 ;
     RECT  2.16 47.385 35.964 47.655 ;
     RECT  73.764 47.385 105.84 47.655 ;
     RECT  2.16 47.925 35.964 48.195 ;
     RECT  73.764 47.925 105.84 48.195 ;
     RECT  2.16 48.465 35.964 48.735 ;
     RECT  73.764 48.465 105.84 48.735 ;
     RECT  2.16 49.005 35.964 49.275 ;
     RECT  73.764 49.005 105.84 49.275 ;
     RECT  2.16 49.545 35.964 49.815 ;
     RECT  73.764 49.545 105.84 49.815 ;
     RECT  2.16 50.085 35.964 50.355 ;
     RECT  73.764 50.085 105.84 50.355 ;
     RECT  2.16 50.625 35.964 50.895 ;
     RECT  73.764 50.625 105.84 50.895 ;
     RECT  2.16 51.165 35.964 51.435 ;
     RECT  73.764 51.165 105.84 51.435 ;
     RECT  2.16 51.705 35.964 51.975 ;
     RECT  73.764 51.705 105.84 51.975 ;
     RECT  2.16 52.245 35.964 52.515 ;
     RECT  73.764 52.245 105.84 52.515 ;
     RECT  2.16 52.785 35.964 53.055 ;
     RECT  73.764 52.785 105.84 53.055 ;
     RECT  2.16 53.325 35.964 53.595 ;
     RECT  73.764 53.325 105.84 53.595 ;
     RECT  2.16 53.865 35.964 54.135 ;
     RECT  73.764 53.865 105.84 54.135 ;
     RECT  2.16 54.405 35.964 54.675 ;
     RECT  73.764 54.405 105.84 54.675 ;
     RECT  2.16 54.945 35.964 55.215 ;
     RECT  73.764 54.945 105.84 55.215 ;
     RECT  2.16 55.485 35.964 55.62 ;
     RECT  73.764 55.485 105.84 55.62 ;
     RECT  2.16 55.62 105.84 55.755 ;
     RECT  2.16 56.025 105.84 56.295 ;
     RECT  2.16 56.565 105.84 56.835 ;
     RECT  2.16 57.105 105.84 57.375 ;
     RECT  2.16 57.645 105.84 57.915 ;
     RECT  2.16 58.185 105.84 58.455 ;
     RECT  2.16 58.725 105.84 58.995 ;
     RECT  2.16 59.265 105.84 59.535 ;
     RECT  2.16 59.805 105.84 60.075 ;
     RECT  2.16 60.345 105.84 60.615 ;
     RECT  2.16 60.885 105.84 61.155 ;
     RECT  2.16 61.425 105.84 61.695 ;
     RECT  2.16 61.965 105.84 62.235 ;
     RECT  2.16 62.505 105.84 62.775 ;
     RECT  2.16 63.045 105.84 63.315 ;
     RECT  2.16 63.585 105.84 63.855 ;
     RECT  2.16 64.125 105.84 64.395 ;
     RECT  2.16 64.665 105.84 64.935 ;
     RECT  2.16 65.205 105.84 65.475 ;
     RECT  2.16 65.745 105.84 66.015 ;
     RECT  2.16 66.285 105.84 66.555 ;
     RECT  2.16 66.825 105.84 67.095 ;
     RECT  2.16 67.365 105.84 67.635 ;
     RECT  2.16 67.905 105.84 68.175 ;
     RECT  2.16 68.445 105.84 68.715 ;
     RECT  2.16 68.985 105.84 69.255 ;
     RECT  2.16 69.525 105.84 69.795 ;
     RECT  2.16 70.065 105.84 70.335 ;
     RECT  2.16 70.605 105.84 70.875 ;
     RECT  2.16 71.145 105.84 71.415 ;
     RECT  2.16 71.685 105.84 71.955 ;
     RECT  2.16 72.225 105.84 72.495 ;
     RECT  2.16 72.765 105.84 73.035 ;
     RECT  2.16 73.305 105.84 73.44 ;
     RECT  2.16 73.44 43.308 73.575 ;
     RECT  65.772 73.44 105.84 73.575 ;
     RECT  2.16 73.845 43.308 74.115 ;
     RECT  65.772 73.845 105.84 74.115 ;
     RECT  2.16 74.385 43.308 74.655 ;
     RECT  65.772 74.385 105.84 74.655 ;
     RECT  2.16 74.925 43.308 75.195 ;
     RECT  65.772 74.925 105.84 75.195 ;
     RECT  2.16 75.465 43.308 75.735 ;
     RECT  65.772 75.465 105.84 75.735 ;
     RECT  2.16 76.005 43.308 76.275 ;
     RECT  65.772 76.005 105.84 76.275 ;
     RECT  2.16 76.545 43.308 76.815 ;
     RECT  65.772 76.545 105.84 76.815 ;
     RECT  2.16 77.085 43.308 77.355 ;
     RECT  65.772 77.085 105.84 77.355 ;
     RECT  2.16 77.625 43.308 77.895 ;
     RECT  65.772 77.625 105.84 77.895 ;
     RECT  2.16 78.165 43.308 78.435 ;
     RECT  65.772 78.165 105.84 78.435 ;
     RECT  2.16 78.705 43.308 78.975 ;
     RECT  65.772 78.705 105.84 78.975 ;
     RECT  2.16 79.245 43.308 79.515 ;
     RECT  65.772 79.245 105.84 79.515 ;
     RECT  2.16 79.785 43.308 80.055 ;
     RECT  65.772 79.785 105.84 80.055 ;
     RECT  2.16 80.325 43.308 80.595 ;
     RECT  65.772 80.325 105.84 80.595 ;
     RECT  2.16 80.865 43.308 81.135 ;
     RECT  65.772 80.865 105.84 81.135 ;
     RECT  2.16 81.405 43.308 81.675 ;
     RECT  65.772 81.405 105.84 81.675 ;
     RECT  2.16 81.945 43.308 82.215 ;
     RECT  65.772 81.945 105.84 82.215 ;
     RECT  2.16 82.485 43.308 82.755 ;
     RECT  65.772 82.485 105.84 82.755 ;
     RECT  2.16 83.025 43.308 83.295 ;
     RECT  65.772 83.025 105.84 83.295 ;
     RECT  2.16 83.565 43.308 83.835 ;
     RECT  65.772 83.565 105.84 83.835 ;
     RECT  2.16 84.105 43.308 84.375 ;
     RECT  65.772 84.105 105.84 84.375 ;
     RECT  2.16 84.645 43.308 84.915 ;
     RECT  65.772 84.645 105.84 84.915 ;
     RECT  2.16 85.185 43.308 85.455 ;
     RECT  65.772 85.185 105.84 85.455 ;
     RECT  2.16 85.725 43.308 85.995 ;
     RECT  65.772 85.725 105.84 85.995 ;
     RECT  2.16 86.265 43.308 86.535 ;
     RECT  65.772 86.265 105.84 86.535 ;
     RECT  2.16 86.805 43.308 87.075 ;
     RECT  65.772 86.805 105.84 87.075 ;
     RECT  2.16 87.345 43.308 87.615 ;
     RECT  65.772 87.345 105.84 87.615 ;
     RECT  2.16 87.885 43.308 88.155 ;
     RECT  65.772 87.885 105.84 88.155 ;
     RECT  2.16 88.425 43.308 88.695 ;
     RECT  65.772 88.425 105.84 88.695 ;
     RECT  2.16 88.965 43.308 89.235 ;
     RECT  65.772 88.965 105.84 89.235 ;
     RECT  2.16 89.505 43.308 89.775 ;
     RECT  65.772 89.505 105.84 89.775 ;
     RECT  2.16 90.045 43.308 90.315 ;
     RECT  65.772 90.045 105.84 90.315 ;
     RECT  2.16 90.585 43.308 90.855 ;
     RECT  65.772 90.585 105.84 90.855 ;
     RECT  2.16 91.125 43.308 91.395 ;
     RECT  65.772 91.125 105.84 91.395 ;
     RECT  2.16 91.665 43.308 91.935 ;
     RECT  65.772 91.665 105.84 91.935 ;
     RECT  2.16 92.205 43.308 92.475 ;
     RECT  65.772 92.205 105.84 92.475 ;
     RECT  2.16 92.745 43.308 93.015 ;
     RECT  65.772 92.745 105.84 93.015 ;
     RECT  2.16 93.285 43.308 93.555 ;
     RECT  65.772 93.285 105.84 93.555 ;
     RECT  2.16 93.825 43.308 94.095 ;
     RECT  65.772 93.825 105.84 94.095 ;
     RECT  2.16 94.365 43.308 94.635 ;
     RECT  65.772 94.365 105.84 94.635 ;
     RECT  2.16 94.905 43.308 95.175 ;
     RECT  65.772 94.905 105.84 95.175 ;
     RECT  2.16 95.445 43.308 95.715 ;
     RECT  65.772 95.445 105.84 95.715 ;
     RECT  2.16 95.985 43.308 96.255 ;
     RECT  65.772 95.985 105.84 96.255 ;
     RECT  2.16 96.525 43.308 96.795 ;
     RECT  65.772 96.525 105.84 96.795 ;
     RECT  2.16 97.065 43.308 97.335 ;
     RECT  65.772 97.065 105.84 97.335 ;
     RECT  2.16 97.605 43.308 97.875 ;
     RECT  65.772 97.605 105.84 97.875 ;
     RECT  2.16 98.145 43.308 98.415 ;
     RECT  65.772 98.145 105.84 98.415 ;
     RECT  2.16 98.685 105.84 98.955 ;
     RECT  2.16 99.225 105.84 99.495 ;
     RECT  2.16 99.765 105.84 100.035 ;
     RECT  2.16 100.305 105.84 100.575 ;
     RECT  2.16 100.845 105.84 101.115 ;
     RECT  2.16 101.385 105.84 101.655 ;
     RECT  2.16 101.925 105.84 102.195 ;
     RECT  2.16 102.465 105.84 102.735 ;
     RECT  2.16 103.005 105.84 103.275 ;
     RECT  2.16 103.545 105.84 103.815 ;
     RECT  2.16 104.085 105.84 104.355 ;
     RECT  2.16 104.625 105.84 104.895 ;
     RECT  2.16 105.165 105.84 105.435 ;
     RECT  2.16 105.705 105.84 105.975 ;
     RECT  2.16 106.245 105.84 106.515 ;
     RECT  2.16 106.785 105.84 107.055 ;
     RECT  2.16 107.325 105.84 107.595 ;
     RECT  2.16 107.865 105.84 108.135 ;
     RECT  2.16 108.405 105.84 108.675 ;
     RECT  2.16 108.945 105.84 109.215 ;
     RECT  2.16 109.485 105.84 109.755 ;
     RECT  2.16 110.025 105.84 110.295 ;
     RECT  2.16 110.565 105.84 110.835 ;
     RECT  2.16 111.105 105.84 111.375 ;
     RECT  2.16 111.645 105.84 111.915 ;
     RECT  2.16 112.185 105.84 112.455 ;
     RECT  2.16 112.725 105.84 112.995 ;
     RECT  2.16 113.265 105.84 113.535 ;
     RECT  2.16 113.805 105.84 114.075 ;
     RECT  2.16 114.345 105.84 114.615 ;
     RECT  2.16 114.885 105.84 115.155 ;
     RECT  2.16 115.425 105.84 115.695 ;
     RECT  2.16 115.965 105.84 116.235 ;
     RECT  2.16 116.505 105.84 116.775 ;
     RECT  2.16 117.045 105.84 117.315 ;
     RECT  2.16 117.585 105.84 117.855 ;
     RECT  2.16 118.125 105.84 118.395 ;
     RECT  2.16 118.665 105.84 118.935 ;
     RECT  2.16 119.205 105.84 119.475 ;
     RECT  2.16 119.745 105.84 120.015 ;
     RECT  2.16 120.285 105.84 120.555 ;
     RECT  2.16 120.825 105.84 121.095 ;
     RECT  2.16 121.365 105.84 121.635 ;
     RECT  2.16 121.905 105.84 122.175 ;
     RECT  2.16 122.445 105.84 122.715 ;
     RECT  2.16 122.985 105.84 123.255 ;
     RECT  2.16 123.525 105.84 123.795 ;
     RECT  2.16 124.065 105.84 124.335 ;
     RECT  2.16 124.605 105.84 124.875 ;
     RECT  2.16 125.145 105.84 125.415 ;
     RECT  2.16 125.685 105.84 125.955 ;
     RECT  2.16 126.225 105.84 126.495 ;
     RECT  2.16 126.765 105.84 127.035 ;
     RECT  2.16 127.305 105.84 127.44 ;
    LAYER RVTP ;
     RECT  2.16 2.295 105.84 2.565 ;
     RECT  2.16 2.835 105.84 3.105 ;
     RECT  2.16 3.375 105.84 3.645 ;
     RECT  2.16 3.915 105.84 4.185 ;
     RECT  2.16 4.455 105.84 4.725 ;
     RECT  2.16 4.995 105.84 5.265 ;
     RECT  2.16 5.535 105.84 5.805 ;
     RECT  2.16 6.075 105.84 6.345 ;
     RECT  2.16 6.615 105.84 6.885 ;
     RECT  2.16 7.155 105.84 7.425 ;
     RECT  2.16 7.695 105.84 7.965 ;
     RECT  2.16 8.235 105.84 8.505 ;
     RECT  2.16 8.775 105.84 9.045 ;
     RECT  2.16 9.315 105.84 9.585 ;
     RECT  2.16 9.855 105.84 10.125 ;
     RECT  2.16 10.395 105.84 10.665 ;
     RECT  2.16 10.935 105.84 11.205 ;
     RECT  2.16 11.475 105.84 11.745 ;
     RECT  2.16 12.015 105.84 12.285 ;
     RECT  2.16 12.555 105.84 12.825 ;
     RECT  2.16 13.095 105.84 13.365 ;
     RECT  2.16 13.635 105.84 13.905 ;
     RECT  2.16 14.175 105.84 14.445 ;
     RECT  2.16 14.715 105.84 14.985 ;
     RECT  2.16 15.255 105.84 15.525 ;
     RECT  2.16 15.795 105.84 16.065 ;
     RECT  2.16 16.335 105.84 16.605 ;
     RECT  2.16 16.875 105.84 17.145 ;
     RECT  2.16 17.415 105.84 17.685 ;
     RECT  2.16 17.955 105.84 18.225 ;
     RECT  2.16 18.495 105.84 18.765 ;
     RECT  2.16 19.035 105.84 19.305 ;
     RECT  2.16 19.575 105.84 19.845 ;
     RECT  2.16 20.115 105.84 20.385 ;
     RECT  2.16 20.655 105.84 20.925 ;
     RECT  2.16 21.195 105.84 21.465 ;
     RECT  2.16 21.735 105.84 22.005 ;
     RECT  2.16 22.275 105.84 22.545 ;
     RECT  2.16 22.815 105.84 23.085 ;
     RECT  2.16 23.355 105.84 23.625 ;
     RECT  2.16 23.895 35.964 24.165 ;
     RECT  73.764 23.895 105.84 24.165 ;
     RECT  2.16 24.435 35.964 24.705 ;
     RECT  73.764 24.435 105.84 24.705 ;
     RECT  2.16 24.975 35.964 25.245 ;
     RECT  73.764 24.975 105.84 25.245 ;
     RECT  2.16 25.515 35.964 25.785 ;
     RECT  73.764 25.515 105.84 25.785 ;
     RECT  2.16 26.055 35.964 26.325 ;
     RECT  73.764 26.055 105.84 26.325 ;
     RECT  2.16 26.595 35.964 26.865 ;
     RECT  73.764 26.595 105.84 26.865 ;
     RECT  2.16 27.135 35.964 27.405 ;
     RECT  73.764 27.135 105.84 27.405 ;
     RECT  2.16 27.675 35.964 27.945 ;
     RECT  73.764 27.675 105.84 27.945 ;
     RECT  2.16 28.215 35.964 28.485 ;
     RECT  73.764 28.215 105.84 28.485 ;
     RECT  2.16 28.755 35.964 29.025 ;
     RECT  73.764 28.755 105.84 29.025 ;
     RECT  2.16 29.295 35.964 29.565 ;
     RECT  73.764 29.295 105.84 29.565 ;
     RECT  2.16 29.835 35.964 30.105 ;
     RECT  73.764 29.835 105.84 30.105 ;
     RECT  2.16 30.375 35.964 30.645 ;
     RECT  73.764 30.375 105.84 30.645 ;
     RECT  2.16 30.915 35.964 31.185 ;
     RECT  73.764 30.915 105.84 31.185 ;
     RECT  2.16 31.455 35.964 31.725 ;
     RECT  73.764 31.455 105.84 31.725 ;
     RECT  2.16 31.995 35.964 32.265 ;
     RECT  73.764 31.995 105.84 32.265 ;
     RECT  2.16 32.535 35.964 32.805 ;
     RECT  73.764 32.535 105.84 32.805 ;
     RECT  2.16 33.075 35.964 33.345 ;
     RECT  73.764 33.075 105.84 33.345 ;
     RECT  2.16 33.615 35.964 33.885 ;
     RECT  73.764 33.615 105.84 33.885 ;
     RECT  2.16 34.155 35.964 34.425 ;
     RECT  73.764 34.155 105.84 34.425 ;
     RECT  2.16 34.695 35.964 34.965 ;
     RECT  73.764 34.695 105.84 34.965 ;
     RECT  2.16 35.235 35.964 35.505 ;
     RECT  73.764 35.235 105.84 35.505 ;
     RECT  2.16 35.775 35.964 36.045 ;
     RECT  73.764 35.775 105.84 36.045 ;
     RECT  2.16 36.315 35.964 36.585 ;
     RECT  73.764 36.315 105.84 36.585 ;
     RECT  2.16 36.855 35.964 37.125 ;
     RECT  73.764 36.855 105.84 37.125 ;
     RECT  2.16 37.395 35.964 37.665 ;
     RECT  73.764 37.395 105.84 37.665 ;
     RECT  2.16 37.935 35.964 38.205 ;
     RECT  73.764 37.935 105.84 38.205 ;
     RECT  2.16 38.475 35.964 38.745 ;
     RECT  73.764 38.475 105.84 38.745 ;
     RECT  2.16 39.015 35.964 39.285 ;
     RECT  73.764 39.015 105.84 39.285 ;
     RECT  2.16 39.555 35.964 39.825 ;
     RECT  73.764 39.555 105.84 39.825 ;
     RECT  2.16 40.095 35.964 40.365 ;
     RECT  73.764 40.095 105.84 40.365 ;
     RECT  2.16 40.635 35.964 40.905 ;
     RECT  73.764 40.635 105.84 40.905 ;
     RECT  2.16 41.175 35.964 41.445 ;
     RECT  73.764 41.175 105.84 41.445 ;
     RECT  2.16 41.715 35.964 41.985 ;
     RECT  73.764 41.715 105.84 41.985 ;
     RECT  2.16 42.255 35.964 42.525 ;
     RECT  73.764 42.255 105.84 42.525 ;
     RECT  2.16 42.795 35.964 43.065 ;
     RECT  73.764 42.795 105.84 43.065 ;
     RECT  2.16 43.335 35.964 43.605 ;
     RECT  73.764 43.335 105.84 43.605 ;
     RECT  2.16 43.875 35.964 44.145 ;
     RECT  73.764 43.875 105.84 44.145 ;
     RECT  2.16 44.415 35.964 44.685 ;
     RECT  73.764 44.415 105.84 44.685 ;
     RECT  2.16 44.955 35.964 45.225 ;
     RECT  73.764 44.955 105.84 45.225 ;
     RECT  2.16 45.495 35.964 45.765 ;
     RECT  73.764 45.495 105.84 45.765 ;
     RECT  2.16 46.035 35.964 46.305 ;
     RECT  73.764 46.035 105.84 46.305 ;
     RECT  2.16 46.575 35.964 46.845 ;
     RECT  73.764 46.575 105.84 46.845 ;
     RECT  2.16 47.115 35.964 47.385 ;
     RECT  73.764 47.115 105.84 47.385 ;
     RECT  2.16 47.655 35.964 47.925 ;
     RECT  73.764 47.655 105.84 47.925 ;
     RECT  2.16 48.195 35.964 48.465 ;
     RECT  73.764 48.195 105.84 48.465 ;
     RECT  2.16 48.735 35.964 49.005 ;
     RECT  73.764 48.735 105.84 49.005 ;
     RECT  2.16 49.275 35.964 49.545 ;
     RECT  73.764 49.275 105.84 49.545 ;
     RECT  2.16 49.815 35.964 50.085 ;
     RECT  73.764 49.815 105.84 50.085 ;
     RECT  2.16 50.355 35.964 50.625 ;
     RECT  73.764 50.355 105.84 50.625 ;
     RECT  2.16 50.895 35.964 51.165 ;
     RECT  73.764 50.895 105.84 51.165 ;
     RECT  2.16 51.435 35.964 51.705 ;
     RECT  73.764 51.435 105.84 51.705 ;
     RECT  2.16 51.975 35.964 52.245 ;
     RECT  73.764 51.975 105.84 52.245 ;
     RECT  2.16 52.515 35.964 52.785 ;
     RECT  73.764 52.515 105.84 52.785 ;
     RECT  2.16 53.055 35.964 53.325 ;
     RECT  73.764 53.055 105.84 53.325 ;
     RECT  2.16 53.595 35.964 53.865 ;
     RECT  73.764 53.595 105.84 53.865 ;
     RECT  2.16 54.135 35.964 54.405 ;
     RECT  73.764 54.135 105.84 54.405 ;
     RECT  2.16 54.675 35.964 54.945 ;
     RECT  73.764 54.675 105.84 54.945 ;
     RECT  2.16 55.215 35.964 55.485 ;
     RECT  73.764 55.215 105.84 55.485 ;
     RECT  2.16 55.755 105.84 56.025 ;
     RECT  2.16 56.295 105.84 56.565 ;
     RECT  2.16 56.835 105.84 57.105 ;
     RECT  2.16 57.375 105.84 57.645 ;
     RECT  2.16 57.915 105.84 58.185 ;
     RECT  2.16 58.455 105.84 58.725 ;
     RECT  2.16 58.995 105.84 59.265 ;
     RECT  2.16 59.535 105.84 59.805 ;
     RECT  2.16 60.075 105.84 60.345 ;
     RECT  2.16 60.615 105.84 60.885 ;
     RECT  2.16 61.155 105.84 61.425 ;
     RECT  2.16 61.695 105.84 61.965 ;
     RECT  2.16 62.235 105.84 62.505 ;
     RECT  2.16 62.775 105.84 63.045 ;
     RECT  2.16 63.315 105.84 63.585 ;
     RECT  2.16 63.855 105.84 64.125 ;
     RECT  2.16 64.395 105.84 64.665 ;
     RECT  2.16 64.935 105.84 65.205 ;
     RECT  2.16 65.475 105.84 65.745 ;
     RECT  2.16 66.015 105.84 66.285 ;
     RECT  2.16 66.555 105.84 66.825 ;
     RECT  2.16 67.095 105.84 67.365 ;
     RECT  2.16 67.635 105.84 67.905 ;
     RECT  2.16 68.175 105.84 68.445 ;
     RECT  2.16 68.715 105.84 68.985 ;
     RECT  2.16 69.255 105.84 69.525 ;
     RECT  2.16 69.795 105.84 70.065 ;
     RECT  2.16 70.335 105.84 70.605 ;
     RECT  2.16 70.875 105.84 71.145 ;
     RECT  2.16 71.415 105.84 71.685 ;
     RECT  2.16 71.955 105.84 72.225 ;
     RECT  2.16 72.495 105.84 72.765 ;
     RECT  2.16 73.035 105.84 73.305 ;
     RECT  2.16 73.575 43.308 73.845 ;
     RECT  65.772 73.575 105.84 73.845 ;
     RECT  2.16 74.115 43.308 74.385 ;
     RECT  65.772 74.115 105.84 74.385 ;
     RECT  2.16 74.655 43.308 74.925 ;
     RECT  65.772 74.655 105.84 74.925 ;
     RECT  2.16 75.195 43.308 75.465 ;
     RECT  65.772 75.195 105.84 75.465 ;
     RECT  2.16 75.735 43.308 76.005 ;
     RECT  65.772 75.735 105.84 76.005 ;
     RECT  2.16 76.275 43.308 76.545 ;
     RECT  65.772 76.275 105.84 76.545 ;
     RECT  2.16 76.815 43.308 77.085 ;
     RECT  65.772 76.815 105.84 77.085 ;
     RECT  2.16 77.355 43.308 77.625 ;
     RECT  65.772 77.355 105.84 77.625 ;
     RECT  2.16 77.895 43.308 78.165 ;
     RECT  65.772 77.895 105.84 78.165 ;
     RECT  2.16 78.435 43.308 78.705 ;
     RECT  65.772 78.435 105.84 78.705 ;
     RECT  2.16 78.975 43.308 79.245 ;
     RECT  65.772 78.975 105.84 79.245 ;
     RECT  2.16 79.515 43.308 79.785 ;
     RECT  65.772 79.515 105.84 79.785 ;
     RECT  2.16 80.055 43.308 80.325 ;
     RECT  65.772 80.055 105.84 80.325 ;
     RECT  2.16 80.595 43.308 80.865 ;
     RECT  65.772 80.595 105.84 80.865 ;
     RECT  2.16 81.135 43.308 81.405 ;
     RECT  65.772 81.135 105.84 81.405 ;
     RECT  2.16 81.675 43.308 81.945 ;
     RECT  65.772 81.675 105.84 81.945 ;
     RECT  2.16 82.215 43.308 82.485 ;
     RECT  65.772 82.215 105.84 82.485 ;
     RECT  2.16 82.755 43.308 83.025 ;
     RECT  65.772 82.755 105.84 83.025 ;
     RECT  2.16 83.295 43.308 83.565 ;
     RECT  65.772 83.295 105.84 83.565 ;
     RECT  2.16 83.835 43.308 84.105 ;
     RECT  65.772 83.835 105.84 84.105 ;
     RECT  2.16 84.375 43.308 84.645 ;
     RECT  65.772 84.375 105.84 84.645 ;
     RECT  2.16 84.915 43.308 85.185 ;
     RECT  65.772 84.915 105.84 85.185 ;
     RECT  2.16 85.455 43.308 85.725 ;
     RECT  65.772 85.455 105.84 85.725 ;
     RECT  2.16 85.995 43.308 86.265 ;
     RECT  65.772 85.995 105.84 86.265 ;
     RECT  2.16 86.535 43.308 86.805 ;
     RECT  65.772 86.535 105.84 86.805 ;
     RECT  2.16 87.075 43.308 87.345 ;
     RECT  65.772 87.075 105.84 87.345 ;
     RECT  2.16 87.615 43.308 87.885 ;
     RECT  65.772 87.615 105.84 87.885 ;
     RECT  2.16 88.155 43.308 88.425 ;
     RECT  65.772 88.155 105.84 88.425 ;
     RECT  2.16 88.695 43.308 88.965 ;
     RECT  65.772 88.695 105.84 88.965 ;
     RECT  2.16 89.235 43.308 89.505 ;
     RECT  65.772 89.235 105.84 89.505 ;
     RECT  2.16 89.775 43.308 90.045 ;
     RECT  65.772 89.775 105.84 90.045 ;
     RECT  2.16 90.315 43.308 90.585 ;
     RECT  65.772 90.315 105.84 90.585 ;
     RECT  2.16 90.855 43.308 91.125 ;
     RECT  65.772 90.855 105.84 91.125 ;
     RECT  2.16 91.395 43.308 91.665 ;
     RECT  65.772 91.395 105.84 91.665 ;
     RECT  2.16 91.935 43.308 92.205 ;
     RECT  65.772 91.935 105.84 92.205 ;
     RECT  2.16 92.475 43.308 92.745 ;
     RECT  65.772 92.475 105.84 92.745 ;
     RECT  2.16 93.015 43.308 93.285 ;
     RECT  65.772 93.015 105.84 93.285 ;
     RECT  2.16 93.555 43.308 93.825 ;
     RECT  65.772 93.555 105.84 93.825 ;
     RECT  2.16 94.095 43.308 94.365 ;
     RECT  65.772 94.095 105.84 94.365 ;
     RECT  2.16 94.635 43.308 94.905 ;
     RECT  65.772 94.635 105.84 94.905 ;
     RECT  2.16 95.175 43.308 95.445 ;
     RECT  65.772 95.175 105.84 95.445 ;
     RECT  2.16 95.715 43.308 95.985 ;
     RECT  65.772 95.715 105.84 95.985 ;
     RECT  2.16 96.255 43.308 96.525 ;
     RECT  65.772 96.255 105.84 96.525 ;
     RECT  2.16 96.795 43.308 97.065 ;
     RECT  65.772 96.795 105.84 97.065 ;
     RECT  2.16 97.335 43.308 97.605 ;
     RECT  65.772 97.335 105.84 97.605 ;
     RECT  2.16 97.875 43.308 98.145 ;
     RECT  65.772 97.875 105.84 98.145 ;
     RECT  2.16 98.415 43.308 98.55 ;
     RECT  65.772 98.415 105.84 98.55 ;
     RECT  2.16 98.55 105.84 98.685 ;
     RECT  2.16 98.955 105.84 99.225 ;
     RECT  2.16 99.495 105.84 99.765 ;
     RECT  2.16 100.035 105.84 100.305 ;
     RECT  2.16 100.575 105.84 100.845 ;
     RECT  2.16 101.115 105.84 101.385 ;
     RECT  2.16 101.655 105.84 101.925 ;
     RECT  2.16 102.195 105.84 102.465 ;
     RECT  2.16 102.735 105.84 103.005 ;
     RECT  2.16 103.275 105.84 103.545 ;
     RECT  2.16 103.815 105.84 104.085 ;
     RECT  2.16 104.355 105.84 104.625 ;
     RECT  2.16 104.895 105.84 105.165 ;
     RECT  2.16 105.435 105.84 105.705 ;
     RECT  2.16 105.975 105.84 106.245 ;
     RECT  2.16 106.515 105.84 106.785 ;
     RECT  2.16 107.055 105.84 107.325 ;
     RECT  2.16 107.595 105.84 107.865 ;
     RECT  2.16 108.135 105.84 108.405 ;
     RECT  2.16 108.675 105.84 108.945 ;
     RECT  2.16 109.215 105.84 109.485 ;
     RECT  2.16 109.755 105.84 110.025 ;
     RECT  2.16 110.295 105.84 110.565 ;
     RECT  2.16 110.835 105.84 111.105 ;
     RECT  2.16 111.375 105.84 111.645 ;
     RECT  2.16 111.915 105.84 112.185 ;
     RECT  2.16 112.455 105.84 112.725 ;
     RECT  2.16 112.995 105.84 113.265 ;
     RECT  2.16 113.535 105.84 113.805 ;
     RECT  2.16 114.075 105.84 114.345 ;
     RECT  2.16 114.615 105.84 114.885 ;
     RECT  2.16 115.155 105.84 115.425 ;
     RECT  2.16 115.695 105.84 115.965 ;
     RECT  2.16 116.235 105.84 116.505 ;
     RECT  2.16 116.775 105.84 117.045 ;
     RECT  2.16 117.315 105.84 117.585 ;
     RECT  2.16 117.855 105.84 118.125 ;
     RECT  2.16 118.395 105.84 118.665 ;
     RECT  2.16 118.935 105.84 119.205 ;
     RECT  2.16 119.475 105.84 119.745 ;
     RECT  2.16 120.015 105.84 120.285 ;
     RECT  2.16 120.555 105.84 120.825 ;
     RECT  2.16 121.095 105.84 121.365 ;
     RECT  2.16 121.635 105.84 121.905 ;
     RECT  2.16 122.175 105.84 122.445 ;
     RECT  2.16 122.715 105.84 122.985 ;
     RECT  2.16 123.255 105.84 123.525 ;
     RECT  2.16 123.795 105.84 124.065 ;
     RECT  2.16 124.335 105.84 124.605 ;
     RECT  2.16 124.875 105.84 125.145 ;
     RECT  2.16 125.415 105.84 125.685 ;
     RECT  2.16 125.955 105.84 126.225 ;
     RECT  2.16 126.495 105.84 126.765 ;
     RECT  2.16 127.035 105.84 127.305 ;
    LAYER M1 ;
     RECT  2.16 2.151 105.84 23.769 ;
     RECT  38.016 25.92 71.712 53.46 ;
     RECT  2.16 23.769 35.964 55.611 ;
     RECT  73.764 23.769 105.84 55.611 ;
     RECT  2.16 55.611 105.84 73.449 ;
     RECT  45.36 75.6 63.72 96.39 ;
     RECT  2.16 73.449 43.308 98.541 ;
     RECT  65.772 73.449 105.84 98.541 ;
     RECT  2.16 98.541 105.84 127.449 ;
    LAYER M2 ;
     RECT  0.031 4.536 2.16 4.554 ;
     RECT  0.139 5.85 2.16 5.868 ;
     RECT  0.103 7.902 2.16 7.92 ;
     RECT  0.103 9.792 2.16 9.81 ;
     RECT  0.103 11.682 2.16 11.7 ;
     RECT  0.103 13.572 2.16 13.59 ;
     RECT  0.103 15.498 2.16 15.516 ;
     RECT  0.103 17.622 2.16 17.64 ;
     RECT  0.103 21.402 2.16 21.42 ;
     RECT  0.103 23.292 2.16 23.31 ;
     RECT  0.103 25.182 2.16 25.2 ;
     RECT  0.103 27.072 2.16 27.09 ;
     RECT  0.103 30.96 2.16 30.978 ;
     RECT  0.103 32.85 2.16 32.868 ;
     RECT  0.103 34.902 2.16 34.92 ;
     RECT  0.103 36.792 2.16 36.81 ;
     RECT  0.535 38.682 2.16 38.7 ;
     RECT  0.535 40.608 2.16 40.626 ;
     RECT  0.103 42.57 2.16 42.588 ;
     RECT  1.723 44.352 2.16 44.37 ;
     RECT  0.103 46.512 2.16 46.53 ;
     RECT  0.103 48.402 2.16 48.42 ;
     RECT  0.103 50.292 2.16 50.31 ;
     RECT  0.103 52.182 2.16 52.2 ;
     RECT  0.535 56.07 2.16 56.088 ;
     RECT  0.103 57.96 2.16 57.978 ;
     RECT  0.103 60.012 2.16 60.03 ;
     RECT  0.103 61.902 2.16 61.92 ;
     RECT  1.723 63.828 2.16 63.846 ;
     RECT  0.139 65.79 2.16 65.808 ;
     RECT  0.103 67.68 2.16 67.698 ;
     RECT  1.723 69.462 2.16 69.48 ;
     RECT  0.103 71.622 2.16 71.64 ;
     RECT  0.535 75.402 2.16 75.42 ;
     RECT  0.103 77.4 2.16 77.418 ;
     RECT  1.723 79.182 2.16 79.2 ;
     RECT  0.103 81.342 2.16 81.36 ;
     RECT  0.103 83.07 2.16 83.088 ;
     RECT  0.103 85.122 2.16 85.14 ;
     RECT  0.103 87.012 2.16 87.03 ;
     RECT  0.103 89.172 2.16 89.19 ;
     RECT  0.103 91.062 2.16 91.08 ;
     RECT  0.103 94.842 2.16 94.86 ;
     RECT  0.103 96.732 2.16 96.75 ;
     RECT  0.103 100.476 2.16 100.494 ;
     RECT  0.535 102.474 2.16 102.492 ;
     RECT  0.103 104.562 2.16 104.58 ;
     RECT  0.535 106.29 2.16 106.308 ;
     RECT  0.103 108.342 2.16 108.36 ;
     RECT  0.103 110.232 2.16 110.25 ;
     RECT  0.103 112.194 2.16 112.212 ;
     RECT  0.103 114.12 2.16 114.138 ;
     RECT  0.103 116.172 2.16 116.19 ;
     RECT  0.535 117.9 2.16 117.918 ;
     RECT  0.103 119.952 2.16 119.97 ;
     RECT  0.103 121.842 2.16 121.86 ;
     RECT  0.103 123.732 2.16 123.75 ;
     RECT  0.103 125.73 2.16 125.748 ;
     RECT  0.103 127.35 2.16 127.368 ;
     RECT  2.16 2.151 9.211 127.449 ;
     RECT  9.211 2.106 11.075 127.449 ;
     RECT  11.075 2.151 35.964 127.449 ;
     RECT  35.964 45.198 35.987 45.216 ;
     RECT  35.964 2.151 36.023 23.814 ;
     RECT  35.964 50.094 36.131 50.112 ;
     RECT  35.964 44.424 36.203 44.442 ;
     RECT  35.964 33.318 36.491 33.984 ;
     RECT  35.964 27.072 36.527 28.584 ;
     RECT  35.964 40.716 36.527 40.734 ;
     RECT  35.964 46.278 36.527 46.404 ;
     RECT  35.964 32.238 36.563 32.256 ;
     RECT  35.964 53.604 36.751 54.864 ;
     RECT  35.964 55.611 36.751 127.449 ;
     RECT  35.964 30.654 36.779 30.672 ;
     RECT  36.527 28.026 36.815 28.584 ;
     RECT  36.527 27.072 36.823 27.162 ;
     RECT  36.815 28.026 36.887 28.314 ;
     RECT  35.964 36.486 36.923 36.504 ;
     RECT  36.887 28.296 36.959 28.314 ;
     RECT  36.823 26.766 37.031 27.162 ;
     RECT  36.023 2.151 37.255 23.769 ;
     RECT  35.964 24.786 37.255 25.614 ;
     RECT  36.751 53.604 37.399 127.449 ;
     RECT  37.399 53.496 37.579 127.449 ;
     RECT  37.255 2.151 38.016 25.614 ;
     RECT  36.491 33.318 38.016 33.336 ;
     RECT  35.964 42.534 38.016 42.552 ;
     RECT  36.527 46.386 38.016 46.404 ;
     RECT  37.579 53.028 38.016 127.449 ;
     RECT  38.016 2.151 39.515 127.449 ;
     RECT  39.515 24.876 39.587 127.449 ;
     RECT  39.587 55.341 39.623 127.449 ;
     RECT  39.623 55.611 43.308 127.449 ;
     RECT  43.308 75.78 43.331 77.112 ;
     RECT  43.331 76.086 43.367 77.112 ;
     RECT  39.587 24.876 43.951 54.162 ;
     RECT  44.995 74.934 45.36 74.952 ;
     RECT  43.367 76.086 45.36 76.914 ;
     RECT  43.308 78.642 45.36 78.66 ;
     RECT  43.308 83.61 45.36 83.628 ;
     RECT  43.308 96.804 45.36 96.822 ;
     RECT  45.36 74.934 51.359 96.822 ;
     RECT  51.359 75.6 59.495 96.822 ;
     RECT  43.951 24.786 59.827 54.162 ;
     RECT  59.495 75.6 63.72 96.39 ;
     RECT  63.72 76.626 64.975 79.47 ;
     RECT  43.308 55.611 65.772 73.449 ;
     RECT  64.975 76.086 65.772 79.47 ;
     RECT  63.72 83.502 65.772 83.52 ;
     RECT  59.575 97.776 65.772 97.794 ;
     RECT  43.308 98.541 65.772 127.449 ;
     RECT  59.827 24.75 71.712 54.162 ;
     RECT  71.712 24.75 72.599 25.614 ;
     RECT  71.712 28.224 72.635 28.782 ;
     RECT  71.712 32.202 73.255 46.494 ;
     RECT  71.712 31.266 73.543 31.284 ;
     RECT  73.255 32.202 73.543 46.674 ;
     RECT  71.712 50.058 73.687 50.076 ;
     RECT  73.219 47.736 73.759 47.754 ;
     RECT  39.515 2.151 73.764 23.769 ;
     RECT  72.599 25.056 73.764 25.614 ;
     RECT  72.635 28.296 73.764 28.782 ;
     RECT  73.543 31.266 73.764 46.674 ;
     RECT  73.759 47.736 73.764 47.844 ;
     RECT  73.687 49.986 73.764 50.076 ;
     RECT  73.723 51.606 73.764 51.624 ;
     RECT  71.712 53.64 73.764 54.162 ;
     RECT  65.772 55.611 73.764 127.449 ;
     RECT  73.764 2.151 105.84 127.449 ;
     RECT  105.84 125.352 105.935 127.224 ;
     RECT  105.84 103.086 106.043 103.104 ;
     RECT  105.84 110.736 106.043 111.474 ;
     RECT  105.84 3.276 106.187 3.834 ;
     RECT  105.84 23.706 106.547 23.724 ;
     RECT  105.84 120.798 106.547 120.816 ;
     RECT  105.84 77.256 106.583 77.274 ;
     RECT  105.84 121.572 106.583 121.59 ;
     RECT  105.935 125.352 106.583 125.946 ;
     RECT  106.187 3.276 106.619 3.294 ;
     RECT  105.84 8.82 106.619 8.838 ;
     RECT  105.84 9.792 106.619 9.81 ;
     RECT  105.84 15.3 106.619 15.318 ;
     RECT  105.84 19.008 106.619 19.026 ;
     RECT  105.84 28.26 106.619 28.278 ;
     RECT  105.84 30.96 106.619 30.978 ;
     RECT  105.84 34.74 106.619 34.758 ;
     RECT  105.84 37.44 106.619 37.458 ;
     RECT  105.84 38.448 106.619 38.466 ;
     RECT  105.84 40.14 106.619 40.158 ;
     RECT  105.84 41.22 106.619 41.238 ;
     RECT  105.84 47.664 106.619 47.682 ;
     RECT  105.84 49.482 106.619 49.5 ;
     RECT  105.84 55.026 106.619 55.044 ;
     RECT  105.84 56.88 106.619 56.898 ;
     RECT  105.84 61.236 106.619 61.254 ;
     RECT  105.84 66.186 106.619 66.924 ;
     RECT  105.84 67.986 106.619 68.004 ;
     RECT  105.84 68.922 106.619 68.94 ;
     RECT  105.84 69.84 106.619 70.56 ;
     RECT  105.84 72.54 106.619 72.558 ;
     RECT  105.84 75.402 106.619 75.42 ;
     RECT  105.84 78.336 106.619 79.038 ;
     RECT  105.84 80.064 106.619 80.082 ;
     RECT  105.84 81.882 106.619 81.9 ;
     RECT  105.84 82.8 106.619 82.818 ;
     RECT  105.84 89.28 106.619 89.298 ;
     RECT  105.84 97.776 106.619 98.478 ;
     RECT  105.84 101.322 106.619 101.34 ;
     RECT  105.84 102.24 106.619 102.258 ;
     RECT  105.84 104.058 106.619 104.076 ;
     RECT  105.84 107.802 106.619 107.82 ;
     RECT  105.84 108.72 106.619 108.738 ;
     RECT  105.84 116.982 106.619 117 ;
     RECT  105.84 118.836 106.619 118.854 ;
     RECT  105.84 123.498 106.619 124.254 ;
     RECT  105.935 126.774 106.619 127.224 ;
     RECT  105.84 2.196 107.159 2.52 ;
     RECT  105.84 5.436 107.159 6.84 ;
     RECT  105.84 7.938 107.159 7.956 ;
     RECT  105.84 10.71 107.159 10.728 ;
     RECT  105.84 11.682 107.159 12.384 ;
     RECT  105.84 13.536 107.159 13.554 ;
     RECT  105.84 14.418 107.159 14.436 ;
     RECT  105.84 16.236 107.159 16.254 ;
     RECT  105.84 18.162 107.159 18.18 ;
     RECT  105.84 19.926 107.159 19.944 ;
     RECT  105.84 20.898 107.159 21.654 ;
     RECT  105.84 22.716 107.159 22.734 ;
     RECT  105.84 24.642 107.159 24.66 ;
     RECT  105.84 25.722 107.159 25.74 ;
     RECT  105.84 26.496 107.159 26.514 ;
     RECT  105.84 30.114 107.159 30.132 ;
     RECT  105.84 32.886 107.159 33.606 ;
     RECT  105.84 35.676 107.159 35.694 ;
     RECT  105.84 36.594 107.159 36.612 ;
     RECT  105.84 42.156 107.159 42.174 ;
     RECT  105.84 43.236 107.159 43.866 ;
     RECT  105.84 45 107.159 45.018 ;
     RECT  105.84 45.846 107.159 45.864 ;
     RECT  105.84 46.782 107.159 46.8 ;
     RECT  105.84 48.636 107.159 48.654 ;
     RECT  105.84 50.562 107.159 50.58 ;
     RECT  105.84 51.372 107.159 51.39 ;
     RECT  105.84 52.326 107.159 52.344 ;
     RECT  105.84 53.262 107.159 53.28 ;
     RECT  105.84 56.034 107.159 56.052 ;
     RECT  105.84 57.852 107.159 57.87 ;
     RECT  105.84 59.742 107.159 60.408 ;
     RECT  105.84 62.514 107.159 63.27 ;
     RECT  105.84 64.332 107.159 64.962 ;
     RECT  105.84 71.73 107.159 71.748 ;
     RECT  105.84 74.556 107.159 74.574 ;
     RECT  105.84 76.482 107.159 76.5 ;
     RECT  106.619 78.336 107.159 78.354 ;
     RECT  105.84 83.772 107.159 83.79 ;
     RECT  105.84 84.816 107.159 84.834 ;
     RECT  105.84 85.662 107.159 85.68 ;
     RECT  105.84 86.742 107.159 86.76 ;
     RECT  105.84 87.516 107.159 88.218 ;
     RECT  105.84 90.252 107.159 90.27 ;
     RECT  105.84 91.17 107.159 91.188 ;
     RECT  105.84 92.142 107.159 92.16 ;
     RECT  105.84 92.988 107.159 93.006 ;
     RECT  105.84 93.996 107.159 94.626 ;
     RECT  105.84 96.696 107.159 96.714 ;
     RECT  106.619 97.776 107.159 97.794 ;
     RECT  105.84 99.468 107.159 99.486 ;
     RECT  105.84 105.948 107.159 105.966 ;
     RECT  105.84 106.956 107.159 106.974 ;
     RECT  105.84 109.656 107.159 109.674 ;
     RECT  106.043 110.736 107.159 110.754 ;
     RECT  105.84 112.428 107.159 112.446 ;
     RECT  105.84 113.346 107.159 113.994 ;
     RECT  105.84 116.136 107.159 116.154 ;
     RECT  105.84 118.026 107.159 118.044 ;
     RECT  105.84 119.916 107.159 119.934 ;
     RECT  106.619 127.206 107.159 127.224 ;
     RECT  107.159 12.366 107.195 12.384 ;
     RECT  105.84 17.082 107.195 17.1 ;
     RECT  107.159 21.636 107.195 21.654 ;
     RECT  105.84 27.342 107.195 27.36 ;
     RECT  105.84 29.034 107.195 29.052 ;
     RECT  105.84 31.896 107.195 31.914 ;
     RECT  107.159 33.588 107.195 33.606 ;
     RECT  105.84 39.222 107.195 39.24 ;
     RECT  107.159 43.848 107.195 43.866 ;
     RECT  105.84 54.108 107.195 54.126 ;
     RECT  107.159 60.39 107.195 60.408 ;
     RECT  107.159 63.252 107.195 63.27 ;
     RECT  107.159 64.944 107.195 64.962 ;
     RECT  106.619 70.542 107.195 70.56 ;
     RECT  105.84 73.512 107.195 73.53 ;
     RECT  105.84 80.91 107.195 80.928 ;
     RECT  107.159 88.2 107.195 88.218 ;
     RECT  107.159 94.608 107.195 94.626 ;
     RECT  105.84 95.724 107.195 95.742 ;
     RECT  105.84 100.242 107.195 100.26 ;
     RECT  105.84 104.868 107.195 104.886 ;
     RECT  107.159 113.976 107.195 113.994 ;
     RECT  105.84 115.128 107.195 115.146 ;
     RECT  105.84 122.526 107.195 122.544 ;
     RECT  106.619 124.236 107.195 124.254 ;
     RECT  106.583 125.766 107.195 125.946 ;
     RECT  107.159 5.742 107.915 5.76 ;
     RECT  107.159 6.822 107.915 6.84 ;
     RECT  105.84 58.698 107.915 58.716 ;
     RECT  107.195 125.766 107.987 125.784 ;
    LAYER M3 ;
     RECT  2.376 0.091 2.394 0.139 ;
     RECT  3.564 0.091 3.582 0.139 ;
     RECT  4.428 0.091 4.446 0.139 ;
     RECT  5.256 0.091 6.066 0.139 ;
     RECT  8.748 0.091 8.766 0.139 ;
     RECT  101.52 0.091 101.538 0.139 ;
     RECT  105.372 0.091 105.39 0.187 ;
     RECT  11.412 0.091 11.43 0.523 ;
     RECT  19.836 0.091 20.538 0.523 ;
     RECT  29.376 0.091 29.394 0.523 ;
     RECT  36.792 0.091 36.81 0.523 ;
     RECT  37.872 0.091 38.538 0.523 ;
     RECT  39.42 0.091 39.438 0.523 ;
     RECT  50.796 0.091 50.814 0.523 ;
     RECT  71.28 0.091 71.298 0.523 ;
     RECT  98.28 0.091 99.99 0.523 ;
     RECT  101.448 0.139 101.538 0.523 ;
     RECT  102.6 0.091 103.05 0.523 ;
     RECT  103.824 0.091 104.166 0.523 ;
     RECT  9.936 0.091 9.954 0.571 ;
     RECT  11.412 0.523 11.826 0.571 ;
     RECT  13.104 0.091 13.122 0.571 ;
     RECT  14.22 0.091 15.606 0.571 ;
     RECT  17.712 0.091 17.73 0.571 ;
     RECT  24.408 0.091 24.606 0.571 ;
     RECT  28.8 0.523 29.394 0.571 ;
     RECT  31.068 0.091 31.554 0.571 ;
     RECT  33.084 0.091 34.974 0.571 ;
     RECT  36.216 0.523 36.81 0.571 ;
     RECT  37.872 0.523 39.438 0.571 ;
     RECT  40.536 0.091 40.554 0.571 ;
     RECT  42.3 0.091 43.506 0.571 ;
     RECT  45.252 0.523 45.27 0.571 ;
     RECT  49.032 0.091 49.662 0.571 ;
     RECT  51.696 0.091 51.714 0.571 ;
     RECT  52.668 0.091 53.226 0.571 ;
     RECT  54.252 0.091 54.27 0.571 ;
     RECT  55.368 0.091 55.386 0.571 ;
     RECT  57.564 0.091 57.582 0.571 ;
     RECT  58.608 0.091 58.626 0.571 ;
     RECT  59.688 0.091 59.706 0.571 ;
     RECT  60.516 0.091 61.074 0.571 ;
     RECT  62.82 0.091 65.034 0.571 ;
     RECT  67.644 0.091 67.662 0.571 ;
     RECT  69.192 0.091 69.786 0.571 ;
     RECT  70.704 0.523 71.298 0.571 ;
     RECT  73.692 0.523 73.71 0.571 ;
     RECT  74.484 0.091 74.502 0.571 ;
     RECT  75.564 0.091 75.582 0.571 ;
     RECT  76.572 0.091 78.426 0.571 ;
     RECT  79.272 0.091 82.098 0.571 ;
     RECT  83.232 0.091 83.25 0.571 ;
     RECT  84.312 0.091 85.626 0.571 ;
     RECT  86.724 0.091 88.326 0.571 ;
     RECT  91.98 0.091 92.466 0.571 ;
     RECT  93.42 0.523 93.438 0.571 ;
     RECT  97.524 0.091 97.542 0.571 ;
     RECT  98.28 0.523 100.386 0.571 ;
     RECT  89.136 0.091 90.09 0.619 ;
     RECT  90.828 0.523 90.846 0.619 ;
     RECT  72.288 0.523 72.306 1.099 ;
     RECT  79.272 0.571 83.25 1.099 ;
     RECT  8.748 0.139 9.198 1.147 ;
     RECT  9.936 0.571 10.35 1.147 ;
     RECT  11.412 0.571 13.122 1.147 ;
     RECT  17.712 0.571 18.198 1.147 ;
     RECT  19.296 0.523 20.538 1.147 ;
     RECT  21.42 0.091 22.554 1.147 ;
     RECT  24.408 0.571 25.29 1.147 ;
     RECT  26.388 0.091 26.874 1.147 ;
     RECT  27.756 0.571 32.058 1.147 ;
     RECT  33.048 0.571 40.554 1.147 ;
     RECT  42.3 0.571 45.27 1.147 ;
     RECT  48.96 0.571 49.662 1.147 ;
     RECT  50.796 0.523 50.922 1.147 ;
     RECT  56.556 0.091 56.574 1.147 ;
     RECT  57.564 0.571 59.706 1.147 ;
     RECT  60.516 0.571 65.034 1.147 ;
     RECT  66.168 0.091 66.762 1.147 ;
     RECT  69.192 0.571 71.298 1.147 ;
     RECT  72.288 1.099 72.594 1.147 ;
     RECT  68.436 1.147 68.454 1.243 ;
     RECT  69.192 1.147 72.594 1.243 ;
     RECT  8.748 1.147 13.122 1.339 ;
     RECT  14.22 0.571 16.29 1.339 ;
     RECT  6.84 0.091 7.29 2.143 ;
     RECT  8.136 1.339 16.29 2.143 ;
     RECT  17.1 1.147 18.198 2.143 ;
     RECT  18.972 1.147 22.554 2.143 ;
     RECT  33.048 1.147 45.27 2.143 ;
     RECT  46.368 0.091 47.43 2.143 ;
     RECT  48.456 1.147 50.922 2.143 ;
     RECT  51.696 0.571 55.746 2.143 ;
     RECT  56.556 1.147 59.706 2.143 ;
     RECT  60.516 1.147 66.762 2.143 ;
     RECT  67.644 0.571 67.698 2.143 ;
     RECT  68.436 1.243 72.594 2.143 ;
     RECT  79.272 1.099 83.358 2.143 ;
     RECT  84.312 0.571 88.326 2.143 ;
     RECT  89.136 0.619 90.846 2.143 ;
     RECT  103.824 0.523 104.562 2.143 ;
     RECT  105.372 0.187 105.426 2.143 ;
     RECT  2.376 0.139 3.582 2.191 ;
     RECT  4.428 0.139 6.066 2.191 ;
     RECT  6.84 2.143 16.29 2.191 ;
     RECT  17.1 2.143 22.554 2.191 ;
     RECT  23.4 1.147 32.058 2.191 ;
     RECT  33.048 2.143 47.43 2.191 ;
     RECT  48.456 2.143 59.706 2.191 ;
     RECT  60.516 2.143 67.698 2.191 ;
     RECT  73.692 0.571 78.426 2.191 ;
     RECT  79.272 2.143 83.505 2.191 ;
     RECT  84.312 2.143 90.846 2.191 ;
     RECT  91.872 0.571 93.438 2.191 ;
     RECT  94.176 0.091 96.75 2.191 ;
     RECT  97.524 0.571 100.386 2.191 ;
     RECT  0.108 1.963 0.126 2.251 ;
     RECT  23.4 2.191 32.094 2.263 ;
     RECT  33.048 2.191 59.706 2.263 ;
     RECT  60.444 2.191 67.698 2.263 ;
     RECT  68.436 2.143 72.705 2.263 ;
     RECT  73.692 2.191 83.505 2.263 ;
     RECT  84.312 2.191 93.438 2.263 ;
     RECT  94.176 2.191 100.386 2.263 ;
     RECT  101.448 0.523 103.05 2.263 ;
     RECT  0.036 2.251 0.126 2.285 ;
     RECT  2.304 2.191 6.066 2.371 ;
     RECT  6.804 2.191 22.554 2.371 ;
     RECT  23.4 2.263 59.706 2.371 ;
     RECT  60.444 2.263 72.705 2.371 ;
     RECT  73.512 2.263 103.05 2.371 ;
     RECT  103.824 2.143 105.426 2.371 ;
     RECT  107.136 1.435 107.154 2.525 ;
     RECT  2.304 2.371 59.706 2.641 ;
     RECT  60.444 2.371 105.426 2.641 ;
     RECT  2.304 2.641 105.426 2.911 ;
     RECT  106.164 0.523 106.182 2.911 ;
     RECT  2.304 2.911 106.182 3.271 ;
     RECT  2.304 3.271 106.614 3.335 ;
     RECT  2.34 3.335 106.614 3.341 ;
     RECT  2.34 3.341 106.182 3.569 ;
     RECT  5.652 3.569 106.182 3.605 ;
     RECT  36.612 3.605 106.182 3.677 ;
     RECT  36.756 3.677 106.182 3.713 ;
     RECT  36.756 3.713 76.662 3.725 ;
     RECT  36.792 3.725 76.662 3.839 ;
     RECT  77.508 3.713 106.182 3.839 ;
     RECT  77.508 3.839 84.762 3.875 ;
     RECT  77.976 3.875 83.697 3.911 ;
     RECT  91.8 3.839 106.002 3.911 ;
     RECT  72.324 3.839 76.662 3.947 ;
     RECT  2.34 3.569 4.878 3.965 ;
     RECT  5.652 3.605 35.802 3.983 ;
     RECT  77.976 3.911 80.55 3.983 ;
     RECT  6.192 3.983 35.802 4.109 ;
     RECT  36.792 3.839 69.93 4.109 ;
     RECT  70.704 3.839 71.586 4.109 ;
     RECT  72.324 3.947 74.934 4.109 ;
     RECT  75.816 3.947 76.662 4.109 ;
     RECT  78.015 3.983 80.55 4.109 ;
     RECT  81.288 3.911 83.697 4.109 ;
     RECT  85.608 3.839 91.026 4.109 ;
     RECT  91.8 3.911 96.21 4.109 ;
     RECT  97.344 3.911 106.002 4.109 ;
     RECT  36.828 4.109 69.606 4.145 ;
     RECT  70.704 4.109 71.442 4.145 ;
     RECT  97.344 4.109 97.398 4.145 ;
     RECT  12.6 4.109 35.802 4.157 ;
     RECT  94.176 4.109 95.778 4.157 ;
     RECT  76.248 4.109 76.662 4.181 ;
     RECT  101.16 4.109 106.002 4.181 ;
     RECT  36.828 4.145 37.458 4.217 ;
     RECT  12.78 4.157 35.802 4.253 ;
     RECT  85.608 4.109 89.622 4.253 ;
     RECT  72.615 4.109 74.934 4.289 ;
     RECT  101.484 4.181 106.002 4.289 ;
     RECT  2.376 3.965 4.878 4.379 ;
     RECT  12.78 4.253 29.697 4.379 ;
     RECT  37.44 4.217 37.458 4.379 ;
     RECT  38.376 4.145 69.606 4.379 ;
     RECT  70.704 4.145 71.406 4.379 ;
     RECT  72.615 4.289 74.07 4.379 ;
     RECT  78.015 4.109 78.75 4.379 ;
     RECT  86.688 4.253 87.282 4.379 ;
     RECT  90.648 4.109 90.99 4.379 ;
     RECT  13.14 4.379 28.638 4.415 ;
     RECT  30.744 4.253 35.802 4.415 ;
     RECT  13.14 4.415 28.53 4.445 ;
     RECT  81.756 4.109 82.674 4.445 ;
     RECT  84.42 3.875 84.762 4.445 ;
     RECT  6.192 4.109 11.394 4.451 ;
     RECT  13.176 4.445 28.53 4.451 ;
     RECT  30.78 4.415 35.586 4.451 ;
     RECT  38.376 4.379 68.598 4.451 ;
     RECT  70.704 4.379 70.794 4.451 ;
     RECT  76.572 4.181 76.662 4.451 ;
     RECT  78.015 4.379 78.678 4.451 ;
     RECT  82.044 4.445 82.674 4.451 ;
     RECT  85.608 4.253 85.626 4.451 ;
     RECT  98.352 4.109 99.897 4.451 ;
     RECT  30.78 4.451 35.406 4.487 ;
     RECT  41.544 4.451 47.07 4.487 ;
     RECT  41.544 4.487 46.998 4.493 ;
     RECT  6.264 4.451 11.394 4.523 ;
     RECT  38.376 4.451 40.497 4.523 ;
     RECT  42.696 4.493 46.998 4.523 ;
     RECT  48.024 4.451 68.598 4.523 ;
     RECT  70.704 4.451 70.722 4.523 ;
     RECT  72.615 4.379 73.89 4.523 ;
     RECT  13.215 4.451 28.53 4.541 ;
     RECT  29.376 4.379 29.697 4.541 ;
     RECT  48.024 4.523 58.158 4.541 ;
     RECT  58.896 4.523 68.598 4.541 ;
     RECT  74.916 4.289 74.934 4.541 ;
     RECT  80.208 4.109 80.226 4.541 ;
     RECT  84.528 4.445 84.762 4.541 ;
     RECT  0.036 2.285 0.054 4.559 ;
     RECT  6.264 4.523 9.126 4.559 ;
     RECT  10.908 4.523 11.394 4.559 ;
     RECT  27.612 4.541 28.53 4.559 ;
     RECT  42.696 4.523 46.854 4.559 ;
     RECT  30.78 4.487 32.67 4.589 ;
     RECT  69.588 4.379 69.606 4.637 ;
     RECT  2.415 4.379 4.878 4.649 ;
     RECT  9.9 4.523 10.134 4.649 ;
     RECT  73.728 4.523 73.89 4.649 ;
     RECT  78.015 4.451 78.462 4.649 ;
     RECT  82.044 4.451 82.314 4.649 ;
     RECT  86.688 4.379 86.85 4.649 ;
     RECT  90.864 4.379 90.99 4.649 ;
     RECT  98.46 4.451 99.897 4.649 ;
     RECT  2.415 4.649 4.338 4.685 ;
     RECT  27.612 4.559 27.774 4.685 ;
     RECT  42.696 4.559 45.897 4.685 ;
     RECT  86.688 4.649 86.706 4.685 ;
     RECT  90.864 4.649 90.882 4.685 ;
     RECT  92.34 4.109 93.33 4.685 ;
     RECT  97.38 4.145 97.398 4.685 ;
     RECT  99.288 4.649 99.897 4.685 ;
     RECT  101.484 4.289 101.502 4.685 ;
     RECT  94.215 4.157 95.778 4.691 ;
     RECT  30.78 4.589 30.87 4.721 ;
     RECT  33.984 4.487 35.406 4.721 ;
     RECT  92.34 4.685 93.15 4.721 ;
     RECT  2.415 4.685 3.798 4.733 ;
     RECT  73.728 4.649 73.746 4.733 ;
     RECT  76.572 4.451 76.59 4.733 ;
     RECT  78.015 4.649 78.354 4.733 ;
     RECT  82.044 4.649 82.17 4.733 ;
     RECT  84.744 4.541 84.762 4.733 ;
     RECT  82.044 4.733 82.062 4.793 ;
     RECT  99.36 4.685 99.897 4.793 ;
     RECT  30.852 4.721 30.87 4.829 ;
     RECT  31.716 4.589 32.67 4.829 ;
     RECT  33.984 4.721 35.154 4.829 ;
     RECT  42.768 4.685 45.897 4.829 ;
     RECT  88.272 4.253 89.478 4.829 ;
     RECT  92.844 4.721 93.15 4.829 ;
     RECT  2.415 4.733 2.97 4.919 ;
     RECT  9.9 4.649 10.062 4.919 ;
     RECT  48.024 4.541 49.662 4.919 ;
     RECT  88.815 4.829 89.478 4.919 ;
     RECT  92.844 4.829 93.114 4.919 ;
     RECT  102.42 4.289 106.002 4.919 ;
     RECT  92.916 4.919 93.114 4.925 ;
     RECT  31.716 4.829 32.094 4.955 ;
     RECT  50.724 4.541 58.158 4.955 ;
     RECT  38.376 4.523 39.366 4.963 ;
     RECT  13.215 4.541 26.766 4.973 ;
     RECT  66.276 4.541 68.598 4.973 ;
     RECT  27.684 4.685 27.774 4.991 ;
     RECT  33.984 4.829 35.097 4.991 ;
     RECT  42.768 4.829 42.894 4.991 ;
     RECT  95.76 4.691 95.778 4.999 ;
     RECT  96.696 4.891 96.966 4.999 ;
     RECT  38.196 4.963 39.366 5.027 ;
     RECT  88.815 4.919 89.406 5.027 ;
     RECT  93.06 4.925 93.078 5.027 ;
     RECT  26.748 4.973 26.766 5.063 ;
     RECT  98.46 4.649 98.478 5.063 ;
     RECT  9.9 4.919 9.918 5.069 ;
     RECT  13.215 4.973 25.974 5.069 ;
     RECT  43.704 4.829 45.897 5.069 ;
     RECT  13.215 5.069 25.686 5.099 ;
     RECT  46.764 4.559 46.854 5.099 ;
     RECT  48.024 4.919 49.554 5.099 ;
     RECT  60.012 4.541 65.322 5.099 ;
     RECT  95.76 4.999 96.966 5.099 ;
     RECT  13.215 5.099 24.642 5.189 ;
     RECT  25.524 5.099 25.686 5.189 ;
     RECT  102.6 4.919 106.002 5.225 ;
     RECT  38.196 5.027 38.898 5.261 ;
     RECT  46.836 5.099 46.854 5.261 ;
     RECT  64.512 5.099 65.322 5.269 ;
     RECT  66.276 4.973 68.346 5.269 ;
     RECT  34.056 4.991 35.097 5.297 ;
     RECT  51.015 4.955 58.158 5.297 ;
     RECT  60.012 5.099 63.702 5.305 ;
     RECT  32.004 4.955 32.094 5.333 ;
     RECT  42.804 4.991 42.822 5.333 ;
     RECT  7.164 4.559 9.126 5.369 ;
     RECT  34.056 5.297 34.074 5.369 ;
     RECT  43.812 5.069 45.897 5.369 ;
     RECT  52.056 5.297 58.158 5.419 ;
     RECT  58.896 4.541 59.238 5.419 ;
     RECT  102.6 5.225 103.194 5.459 ;
     RECT  52.056 5.419 59.238 5.461 ;
     RECT  59.976 5.305 63.702 5.461 ;
     RECT  52.056 5.461 63.702 5.495 ;
     RECT  96.948 5.099 96.966 5.495 ;
     RECT  32.004 5.333 32.022 5.501 ;
     RECT  11.268 4.559 11.286 5.539 ;
     RECT  38.196 5.261 38.214 5.567 ;
     RECT  64.512 5.269 68.346 5.567 ;
     RECT  102.6 5.459 102.726 5.567 ;
     RECT  104.256 5.225 106.002 5.567 ;
     RECT  10.836 5.539 11.286 5.603 ;
     RECT  102.672 5.567 102.726 5.639 ;
     RECT  48.024 5.099 49.014 5.729 ;
     RECT  102.672 5.639 102.69 5.729 ;
     RECT  104.328 5.567 106.002 5.729 ;
     RECT  107.892 4.219 107.91 5.765 ;
     RECT  48.096 5.729 49.014 5.801 ;
     RECT  6.408 4.559 6.426 5.837 ;
     RECT  64.512 5.567 67.734 5.845 ;
     RECT  0.144 5.803 0.162 5.873 ;
     RECT  3.78 4.733 3.798 5.881 ;
     RECT  48.168 5.801 49.014 5.881 ;
     RECT  13.215 5.189 24.606 5.933 ;
     RECT  48.168 5.881 49.122 5.947 ;
     RECT  49.932 5.809 49.95 5.947 ;
     RECT  78.015 4.733 78.297 5.947 ;
     RECT  58.932 5.495 63.702 5.971 ;
     RECT  64.476 5.845 67.734 5.971 ;
     RECT  13.215 5.933 24.297 5.999 ;
     RECT  105.015 5.729 106.002 5.999 ;
     RECT  77.148 5.971 77.166 6.029 ;
     RECT  15.192 5.999 24.297 6.035 ;
     RECT  15.192 6.035 16.218 6.107 ;
     RECT  17.028 6.035 24.297 6.107 ;
     RECT  48.168 5.947 49.95 6.115 ;
     RECT  51.015 5.297 51.297 6.115 ;
     RECT  52.056 5.495 58.158 6.115 ;
     RECT  13.215 5.999 14.454 6.143 ;
     RECT  17.1 6.107 24.297 6.143 ;
     RECT  13.215 6.143 14.238 6.179 ;
     RECT  17.1 6.143 17.622 6.179 ;
     RECT  3.636 5.881 3.798 6.269 ;
     RECT  13.215 6.179 14.13 6.269 ;
     RECT  15.192 6.107 15.678 6.269 ;
     RECT  17.46 6.179 17.622 6.269 ;
     RECT  18.615 6.143 24.297 6.269 ;
     RECT  78.015 5.947 78.714 6.269 ;
     RECT  4.752 6.235 4.77 6.275 ;
     RECT  48.168 6.115 50.238 6.275 ;
     RECT  58.932 5.971 67.734 6.277 ;
     RECT  15.192 6.269 15.642 6.305 ;
     RECT  107.136 5.131 107.154 6.305 ;
     RECT  17.46 6.269 17.478 6.317 ;
     RECT  58.896 6.277 67.734 6.341 ;
     RECT  7.164 5.369 8.73 6.377 ;
     RECT  15.372 6.305 15.39 6.377 ;
     RECT  51.015 6.115 58.158 6.379 ;
     RECT  48.312 6.275 50.238 6.385 ;
     RECT  50.976 6.379 58.158 6.385 ;
     RECT  10.836 5.603 10.854 6.449 ;
     RECT  43.812 5.369 44.442 6.575 ;
     RECT  48.312 6.385 58.158 6.691 ;
     RECT  58.896 6.341 67.497 6.691 ;
     RECT  21.744 6.269 24.297 6.845 ;
     RECT  107.892 6.817 107.91 7.037 ;
     RECT  21.888 6.845 24.297 7.079 ;
     RECT  44.424 6.575 44.442 7.079 ;
     RECT  18.615 6.269 20.718 7.189 ;
     RECT  18.615 7.189 20.898 7.223 ;
     RECT  20.592 7.223 20.898 7.229 ;
     RECT  18.615 7.223 19.638 7.232 ;
     RECT  20.592 7.229 20.61 7.259 ;
     RECT  13.215 6.269 13.497 7.321 ;
     RECT  11.268 7.243 11.286 7.349 ;
     RECT  19.62 7.232 19.638 7.349 ;
     RECT  22.104 7.079 24.297 7.349 ;
     RECT  12.564 7.321 13.497 7.373 ;
     RECT  22.464 7.349 22.482 7.373 ;
     RECT  48.312 6.691 67.497 7.435 ;
     RECT  47.664 7.435 67.497 7.655 ;
     RECT  0.108 7.771 0.126 7.925 ;
     RECT  107.136 7.915 107.154 7.961 ;
     RECT  2.415 4.919 2.697 8.041 ;
     RECT  2.415 8.041 2.79 8.159 ;
     RECT  4.824 8.275 4.842 8.333 ;
     RECT  68.4 8.401 68.418 8.477 ;
     RECT  47.664 7.655 54.162 8.581 ;
     RECT  54.9 7.655 67.497 8.581 ;
     RECT  47.664 8.581 67.497 8.699 ;
     RECT  47.664 8.699 65.826 8.735 ;
     RECT  45.615 5.369 45.897 8.815 ;
     RECT  45.615 8.815 46.602 8.851 ;
     RECT  47.664 8.735 57.33 8.851 ;
     RECT  106.596 8.815 106.614 8.861 ;
     RECT  45.615 8.851 46.746 9.239 ;
     RECT  45.615 9.239 46.386 9.355 ;
     RECT  47.52 8.851 57.33 9.451 ;
     RECT  47.196 9.451 57.33 9.509 ;
     RECT  58.068 8.735 65.826 9.545 ;
     RECT  47.268 9.509 57.33 9.661 ;
     RECT  58.068 9.545 65.754 9.661 ;
     RECT  0.108 9.691 0.126 9.815 ;
     RECT  106.596 9.781 106.614 9.821 ;
     RECT  2.415 8.159 2.697 9.931 ;
     RECT  44.208 9.739 44.226 9.931 ;
     RECT  45.288 9.355 46.386 9.931 ;
     RECT  27.684 8.131 27.702 10.021 ;
     RECT  2.415 9.931 3.042 10.049 ;
     RECT  44.208 9.931 46.386 10.165 ;
     RECT  6.84 10.021 6.858 10.193 ;
     RECT  47.268 9.661 65.754 10.319 ;
     RECT  44.208 10.165 46.53 10.355 ;
     RECT  31.608 10.363 31.626 10.4 ;
     RECT  42.768 10.315 42.786 10.445 ;
     RECT  43.02 10.459 43.218 10.471 ;
     RECT  45.615 10.355 46.53 10.471 ;
     RECT  47.268 10.319 65.178 10.471 ;
     RECT  45.615 10.471 65.178 10.625 ;
     RECT  6.624 10.561 6.642 10.637 ;
     RECT  107.136 10.696 107.154 10.733 ;
     RECT  31.968 10.471 31.986 10.829 ;
     RECT  42.012 10.843 42.03 10.939 ;
     RECT  42.012 10.939 42.21 11.227 ;
     RECT  43.02 10.471 43.362 11.227 ;
     RECT  42.012 11.227 43.362 11.245 ;
     RECT  44.208 10.355 44.874 11.245 ;
     RECT  45.615 10.625 63.99 11.245 ;
     RECT  40.215 4.523 40.497 11.275 ;
     RECT  64.728 10.625 65.178 11.281 ;
     RECT  64.728 11.281 65.502 11.365 ;
     RECT  40.215 11.275 40.878 11.399 ;
     RECT  42.012 11.245 63.99 11.399 ;
     RECT  42.012 11.399 55.026 11.405 ;
     RECT  64.728 11.365 65.718 11.405 ;
     RECT  55.8 11.399 63.99 11.435 ;
     RECT  0.108 11.611 0.126 11.705 ;
     RECT  55.8 11.435 63.306 11.705 ;
     RECT  107.136 11.611 107.154 11.705 ;
     RECT  42.012 11.405 42.282 11.821 ;
     RECT  55.8 11.705 62.514 11.885 ;
     RECT  64.728 11.405 65.178 11.899 ;
     RECT  27.612 10.021 27.702 11.911 ;
     RECT  4.716 11.821 4.734 11.939 ;
     RECT  64.08 11.899 65.178 11.939 ;
     RECT  41.976 11.821 42.282 11.947 ;
     RECT  4.572 11.941 4.59 11.981 ;
     RECT  55.908 11.885 62.514 11.981 ;
     RECT  55.98 11.981 62.514 12.209 ;
     RECT  63.288 11.705 63.306 12.209 ;
     RECT  64.08 11.939 64.206 12.209 ;
     RECT  64.08 12.209 64.098 12.245 ;
     RECT  40.215 11.399 40.497 12.289 ;
     RECT  40.215 12.289 40.698 12.325 ;
     RECT  41.76 11.947 42.282 12.325 ;
     RECT  43.02 11.405 55.026 12.325 ;
     RECT  55.98 12.209 62.37 12.365 ;
     RECT  55.98 12.365 62.097 12.389 ;
     RECT  55.98 12.389 60.75 12.479 ;
     RECT  61.524 12.389 62.097 12.479 ;
     RECT  39.564 12.325 55.026 12.523 ;
     RECT  55.98 12.479 60.57 12.557 ;
     RECT  107.172 12.361 107.19 12.557 ;
     RECT  39.564 12.523 55.17 12.659 ;
     RECT  39.564 12.659 53.01 12.715 ;
     RECT  55.98 12.557 60.498 12.749 ;
     RECT  55.98 12.749 60.462 12.901 ;
     RECT  55.908 12.901 60.462 12.929 ;
     RECT  54.036 12.659 55.17 12.991 ;
     RECT  55.908 12.929 59.166 12.991 ;
     RECT  37.944 13.003 37.962 13.027 ;
     RECT  38.88 12.715 53.01 13.055 ;
     RECT  37.728 13.027 37.962 13.063 ;
     RECT  38.88 13.055 39.15 13.063 ;
     RECT  59.94 12.929 60.462 13.091 ;
     RECT  54.036 12.991 59.166 13.289 ;
     RECT  59.94 13.091 59.958 13.289 ;
     RECT  54.036 13.289 59.022 13.441 ;
     RECT  53.892 13.441 59.022 13.469 ;
     RECT  3.78 6.269 3.798 13.531 ;
     RECT  53.892 13.469 58.806 13.559 ;
     RECT  107.136 13.483 107.154 13.559 ;
     RECT  53.892 13.559 58.698 13.567 ;
     RECT  0.108 13.531 0.126 13.595 ;
     RECT  53.856 13.567 58.698 13.595 ;
     RECT  39.96 13.055 53.01 13.711 ;
     RECT  3.528 13.531 3.798 13.981 ;
     RECT  37.728 13.063 39.15 13.981 ;
     RECT  39.96 13.711 53.082 13.981 ;
     RECT  53.856 13.595 58.158 13.981 ;
     RECT  37.728 13.981 58.158 14.059 ;
     RECT  3.528 13.981 3.834 14.099 ;
     RECT  37.404 14.059 58.158 14.099 ;
     RECT  3.528 14.099 3.798 14.135 ;
     RECT  37.404 14.099 57.294 14.135 ;
     RECT  58.14 14.099 58.158 14.243 ;
     RECT  37.404 14.135 57.258 14.369 ;
     RECT  37.404 14.369 57.186 14.405 ;
     RECT  107.136 14.395 107.154 14.441 ;
     RECT  37.404 14.405 57.15 14.639 ;
     RECT  37.404 14.639 57.078 14.675 ;
     RECT  37.404 14.675 56.697 14.717 ;
     RECT  37.404 14.717 39.042 14.827 ;
     RECT  39.78 14.717 56.697 15.101 ;
     RECT  52.704 15.101 56.697 15.215 ;
     RECT  106.596 15.295 106.614 15.341 ;
     RECT  56.124 15.215 56.697 15.449 ;
     RECT  36.864 14.827 39.042 15.451 ;
     RECT  39.78 15.101 51.966 15.451 ;
     RECT  0.108 15.493 0.126 15.533 ;
     RECT  2.415 10.049 2.697 15.601 ;
     RECT  52.704 15.215 55.17 15.629 ;
     RECT  2.415 15.601 3.006 15.719 ;
     RECT  5.688 6.241 5.706 15.829 ;
     RECT  5.436 15.829 5.706 15.869 ;
     RECT  36.864 15.451 51.966 15.961 ;
     RECT  52.704 15.629 55.062 15.961 ;
     RECT  3.78 14.135 3.798 15.979 ;
     RECT  36.864 15.961 55.062 16.025 ;
     RECT  36.864 16.025 55.026 16.169 ;
     RECT  107.136 16.219 107.154 16.259 ;
     RECT  36.864 16.169 54.774 16.339 ;
     RECT  36.756 16.339 54.774 16.411 ;
     RECT  36.72 16.411 54.774 16.445 ;
     RECT  54.576 16.445 54.774 16.529 ;
     RECT  2.415 15.719 2.697 16.555 ;
     RECT  3.456 15.979 3.798 16.555 ;
     RECT  2.415 16.555 3.798 16.601 ;
     RECT  36.72 16.445 53.838 16.645 ;
     RECT  36.18 16.645 53.838 16.799 ;
     RECT  54.576 16.529 54.702 16.799 ;
     RECT  54.576 16.799 54.594 16.835 ;
     RECT  36.18 16.799 53.766 16.877 ;
     RECT  36.18 16.877 53.73 16.951 ;
     RECT  107.172 17.077 107.19 17.213 ;
     RECT  34.815 5.297 35.097 17.491 ;
     RECT  35.856 16.951 53.73 17.491 ;
     RECT  56.415 15.449 56.697 17.491 ;
     RECT  5.688 15.869 5.706 17.611 ;
     RECT  61.815 12.479 62.097 17.617 ;
     RECT  0.108 17.419 0.126 17.645 ;
     RECT  34.815 17.491 53.73 17.645 ;
     RECT  5.688 17.611 6.354 17.651 ;
     RECT  55.116 17.581 55.134 17.653 ;
     RECT  55.872 17.491 56.697 17.653 ;
     RECT  55.116 17.653 56.697 17.659 ;
     RECT  60.264 17.563 60.282 17.761 ;
     RECT  54.864 17.659 56.697 17.851 ;
     RECT  53.856 17.851 56.697 17.959 ;
     RECT  57.96 17.659 57.978 18.031 ;
     RECT  60.264 17.761 60.498 18.031 ;
     RECT  53.856 17.959 57.006 18.149 ;
     RECT  107.136 18.091 107.154 18.185 ;
     RECT  61.272 17.617 62.097 18.193 ;
     RECT  55.116 18.149 57.006 18.301 ;
     RECT  57.96 18.031 58.158 18.301 ;
     RECT  58.932 18.031 59.166 18.301 ;
     RECT  63.9 18.157 63.918 18.301 ;
     RECT  61.272 18.193 62.73 18.379 ;
     RECT  34.815 17.645 53.082 18.419 ;
     RECT  60.192 18.031 60.498 18.419 ;
     RECT  61.272 18.379 62.802 18.571 ;
     RECT  63.864 18.301 63.918 18.571 ;
     RECT  58.932 18.301 59.346 18.661 ;
     RECT  60.444 18.419 60.498 18.661 ;
     RECT  55.116 18.301 57.078 18.697 ;
     RECT  57.924 18.301 58.158 18.697 ;
     RECT  63.72 18.571 63.99 18.697 ;
     RECT  55.116 18.697 58.158 18.725 ;
     RECT  58.932 18.661 59.67 18.725 ;
     RECT  55.908 18.725 58.158 18.769 ;
     RECT  38.016 18.419 53.082 18.805 ;
     RECT  53.856 18.149 54.018 18.805 ;
     RECT  60.444 18.661 60.534 18.811 ;
     RECT  61.272 18.571 62.946 18.811 ;
     RECT  64.98 11.939 65.178 18.811 ;
     RECT  63.72 18.697 64.098 18.841 ;
     RECT  59.328 18.725 59.67 18.959 ;
     RECT  66.564 8.699 67.497 18.959 ;
     RECT  60.444 18.811 62.946 18.995 ;
     RECT  64.98 18.811 65.718 18.995 ;
     RECT  106.596 18.997 106.614 19.037 ;
     RECT  61.596 18.995 62.946 19.111 ;
     RECT  63.72 18.841 64.242 19.111 ;
     RECT  64.98 18.995 65.214 19.111 ;
     RECT  34.815 18.419 37.242 19.201 ;
     RECT  38.016 18.805 54.018 19.201 ;
     RECT  55.116 18.725 55.17 19.201 ;
     RECT  55.908 18.769 58.59 19.229 ;
     RECT  60.444 18.995 60.822 19.229 ;
     RECT  61.596 19.111 65.214 19.229 ;
     RECT  2.415 16.601 2.697 19.339 ;
     RECT  34.815 19.201 54.018 19.381 ;
     RECT  55.008 19.201 55.17 19.381 ;
     RECT  55.908 19.229 58.374 19.499 ;
     RECT  60.444 19.229 60.534 19.499 ;
     RECT  2.304 19.339 2.697 19.535 ;
     RECT  59.328 18.959 59.454 19.535 ;
     RECT  60.444 19.499 60.462 19.535 ;
     RECT  2.415 19.535 2.697 19.651 ;
     RECT  34.815 19.381 55.17 19.651 ;
     RECT  55.908 19.499 58.302 19.651 ;
     RECT  27.036 11.911 27.702 19.741 ;
     RECT  72.615 4.523 72.897 19.741 ;
     RECT  2.415 19.651 2.898 19.769 ;
     RECT  34.815 19.651 58.302 19.769 ;
     RECT  34.815 19.769 55.026 19.805 ;
     RECT  61.596 19.229 62.802 19.805 ;
     RECT  66.024 19.003 66.222 19.805 ;
     RECT  3.78 16.601 3.798 19.885 ;
     RECT  4.608 13.981 4.626 19.885 ;
     RECT  3.78 19.885 4.626 19.949 ;
     RECT  107.136 19.912 107.154 19.949 ;
     RECT  63.648 19.229 65.214 19.963 ;
     RECT  63.108 19.963 65.214 20.011 ;
     RECT  50.508 19.805 55.026 20.039 ;
     RECT  54.936 20.039 55.026 20.075 ;
     RECT  67.215 18.959 67.497 20.083 ;
     RECT  56.088 19.769 58.302 20.183 ;
     RECT  33.3 20.107 33.318 20.191 ;
     RECT  33.3 20.191 33.606 20.219 ;
     RECT  50.508 20.039 53.874 20.309 ;
     RECT  56.304 20.183 58.302 20.309 ;
     RECT  53.856 20.309 53.874 20.381 ;
     RECT  63.108 20.011 65.502 20.381 ;
     RECT  66.708 20.083 67.497 20.381 ;
     RECT  34.815 19.805 49.626 20.389 ;
     RECT  34.524 20.389 49.626 20.429 ;
     RECT  59.688 19.963 59.706 20.461 ;
     RECT  50.508 20.309 53.082 20.551 ;
     RECT  56.304 20.309 57.618 20.579 ;
     RECT  58.356 20.461 58.698 20.579 ;
     RECT  59.544 20.461 59.886 20.579 ;
     RECT  63.108 20.381 64.458 20.579 ;
     RECT  65.232 20.381 65.502 20.579 ;
     RECT  60.66 20.461 60.678 20.695 ;
     RECT  34.704 20.429 49.626 20.731 ;
     RECT  50.364 20.551 53.082 20.731 ;
     RECT  60.624 20.695 60.678 20.731 ;
     RECT  61.815 19.805 62.097 20.731 ;
     RECT  63.108 20.579 63.198 20.731 ;
     RECT  27.036 19.741 27.81 20.779 ;
     RECT  27.036 20.779 28.494 20.849 ;
     RECT  34.704 20.731 53.082 20.849 ;
     RECT  61.812 20.731 62.154 20.849 ;
     RECT  64.08 20.579 64.458 20.849 ;
     RECT  33.588 20.219 33.606 20.861 ;
     RECT  34.704 20.849 47.61 20.885 ;
     RECT  60.624 20.731 60.822 20.885 ;
     RECT  62.928 20.731 63.198 20.885 ;
     RECT  64.08 20.849 64.242 20.885 ;
     RECT  65.232 20.579 65.466 20.885 ;
     RECT  107.136 20.875 107.154 20.921 ;
     RECT  27.036 20.849 27.81 20.923 ;
     RECT  30.744 20.827 30.762 20.957 ;
     RECT  61.812 20.849 62.097 20.965 ;
     RECT  55.296 20.551 55.458 21.001 ;
     RECT  56.304 20.579 57.402 21.001 ;
     RECT  60.696 20.885 60.822 21.001 ;
     RECT  61.704 20.965 62.097 21.001 ;
     RECT  48.42 20.849 53.082 21.091 ;
     RECT  48.42 21.091 53.622 21.115 ;
     RECT  54.432 20.821 54.486 21.115 ;
     RECT  47.34 20.885 47.574 21.119 ;
     RECT  55.296 21.001 57.402 21.119 ;
     RECT  58.356 20.579 58.482 21.119 ;
     RECT  59.544 20.579 59.67 21.119 ;
     RECT  60.696 21.001 62.097 21.119 ;
     RECT  63.036 20.885 63.198 21.119 ;
     RECT  64.08 20.885 64.206 21.119 ;
     RECT  47.34 21.119 47.466 21.155 ;
     RECT  55.296 21.119 55.458 21.155 ;
     RECT  56.232 21.119 57.294 21.155 ;
     RECT  58.356 21.119 58.374 21.155 ;
     RECT  59.544 21.119 59.562 21.155 ;
     RECT  63.036 21.119 63.054 21.155 ;
     RECT  64.08 21.119 64.098 21.155 ;
     RECT  65.268 20.885 65.466 21.155 ;
     RECT  48.42 21.115 54.486 21.271 ;
     RECT  55.296 21.155 55.422 21.271 ;
     RECT  67.215 20.381 67.497 21.271 ;
     RECT  34.704 20.885 46.602 21.389 ;
     RECT  48.42 21.271 55.422 21.389 ;
     RECT  60.732 21.119 62.097 21.389 ;
     RECT  0.108 21.307 0.126 21.425 ;
     RECT  48.42 21.389 54.486 21.425 ;
     RECT  55.26 21.389 55.422 21.425 ;
     RECT  56.232 21.155 56.697 21.425 ;
     RECT  60.732 21.389 60.75 21.425 ;
     RECT  3.78 19.949 3.798 21.541 ;
     RECT  26.928 20.923 27.81 21.631 ;
     RECT  55.332 21.425 55.422 21.659 ;
     RECT  55.332 21.659 55.35 21.695 ;
     RECT  3.636 21.541 3.798 21.811 ;
     RECT  107.172 21.631 107.19 21.821 ;
     RECT  3.636 21.811 3.87 21.929 ;
     RECT  48.42 21.425 54.45 21.929 ;
     RECT  3.636 21.929 3.798 21.965 ;
     RECT  48.42 21.929 54.306 21.965 ;
     RECT  34.704 21.389 46.422 22.027 ;
     RECT  47.196 21.643 47.214 22.045 ;
     RECT  48.168 22.009 48.186 22.045 ;
     RECT  34.632 22.027 46.422 22.073 ;
     RECT  47.196 22.045 48.186 22.199 ;
     RECT  48.996 21.965 53.73 22.199 ;
     RECT  34.776 22.073 46.422 22.219 ;
     RECT  53.604 22.199 53.622 22.235 ;
     RECT  47.484 22.199 48.186 22.469 ;
     RECT  5.688 17.651 5.706 22.541 ;
     RECT  66.816 21.271 67.497 22.541 ;
     RECT  34.776 22.219 46.71 22.649 ;
     RECT  43.92 22.649 46.71 22.739 ;
     RECT  48.996 22.199 52.002 22.739 ;
     RECT  107.136 22.699 107.154 22.739 ;
     RECT  43.92 22.739 46.422 22.775 ;
     RECT  48.996 22.739 51.297 22.855 ;
     RECT  43.92 22.775 46.386 23.009 ;
     RECT  47.484 22.469 48.15 23.009 ;
     RECT  48.924 22.855 51.297 23.009 ;
     RECT  34.776 22.649 43.146 23.045 ;
     RECT  45.072 23.009 46.278 23.045 ;
     RECT  47.484 23.009 48.006 23.045 ;
     RECT  48.996 23.009 49.77 23.045 ;
     RECT  49.752 23.045 49.77 23.081 ;
     RECT  48.996 23.045 49.014 23.117 ;
     RECT  7.815 6.377 8.73 23.131 ;
     RECT  7.488 23.131 8.73 23.189 ;
     RECT  39.348 23.045 43.146 23.189 ;
     RECT  50.508 23.009 51.297 23.189 ;
     RECT  10.8 23.131 10.818 23.251 ;
     RECT  39.348 23.189 40.734 23.279 ;
     RECT  41.616 23.189 43.146 23.279 ;
     RECT  26.748 21.631 27.81 23.287 ;
     RECT  10.224 23.251 10.818 23.309 ;
     RECT  0.108 23.227 0.126 23.315 ;
     RECT  41.616 23.279 42.966 23.315 ;
     RECT  45.072 23.045 45.897 23.315 ;
     RECT  43.956 23.009 44.118 23.351 ;
     RECT  6.408 23.287 6.426 23.357 ;
     RECT  10.8 23.309 10.818 23.357 ;
     RECT  39.348 23.279 40.662 23.357 ;
     RECT  45.615 23.315 45.897 23.507 ;
     RECT  51.015 23.189 51.297 23.507 ;
     RECT  56.415 21.425 56.697 23.507 ;
     RECT  61.815 21.389 62.097 23.507 ;
     RECT  67.215 22.541 67.497 23.507 ;
     RECT  72.18 19.741 72.897 23.507 ;
     RECT  39.492 23.357 40.662 23.549 ;
     RECT  41.616 23.315 42.606 23.549 ;
     RECT  52.452 23.431 52.47 23.549 ;
     RECT  39.492 23.549 40.554 23.585 ;
     RECT  41.616 23.549 42.102 23.693 ;
     RECT  106.524 23.659 106.542 23.729 ;
     RECT  42.084 23.693 42.102 23.741 ;
     RECT  39.492 23.585 40.305 23.777 ;
     RECT  45.615 23.507 45.705 23.777 ;
     RECT  51.015 23.507 51.105 23.777 ;
     RECT  56.415 23.507 56.505 23.777 ;
     RECT  61.815 23.507 61.905 23.777 ;
     RECT  67.215 23.507 67.305 23.777 ;
     RECT  72.18 23.507 72.705 23.777 ;
     RECT  39.492 23.777 39.51 24.431 ;
     RECT  34.776 23.045 38.61 24.503 ;
     RECT  107.136 24.571 107.154 24.665 ;
     RECT  72.18 23.777 72.198 24.745 ;
     RECT  59.832 23.701 59.85 24.773 ;
     RECT  72.18 24.745 72.594 24.781 ;
     RECT  38.376 24.503 38.61 24.809 ;
     RECT  43.956 23.351 43.974 24.809 ;
     RECT  38.376 24.809 38.394 24.854 ;
     RECT  52.56 23.665 52.578 24.854 ;
     RECT  34.776 24.503 37.602 25.015 ;
     RECT  0.108 25.147 0.126 25.205 ;
     RECT  2.415 19.769 2.697 25.321 ;
     RECT  3.78 21.965 3.798 25.321 ;
     RECT  26.64 23.287 27.81 25.321 ;
     RECT  71.856 24.781 72.594 25.411 ;
     RECT  2.415 25.321 3.798 25.439 ;
     RECT  6.264 25.387 6.282 25.439 ;
     RECT  25.056 25.411 25.074 25.517 ;
     RECT  73.908 25.051 73.926 25.519 ;
     RECT  22.824 25.447 22.842 25.547 ;
     RECT  24.015 7.349 24.297 25.555 ;
     RECT  73.872 25.519 73.926 25.591 ;
     RECT  24.015 25.555 24.822 25.613 ;
     RECT  34.668 25.015 37.602 25.92 ;
     RECT  71.748 25.411 72.594 25.92 ;
     RECT  107.136 25.483 107.154 26.519 ;
     RECT  34.668 25.92 72.594 26.587 ;
     RECT  34.488 26.587 72.594 26.663 ;
     RECT  73.872 25.591 73.962 26.683 ;
     RECT  32.04 26.635 32.058 26.789 ;
     RECT  33.588 26.527 33.606 26.789 ;
     RECT  73.872 26.683 74.034 26.875 ;
     RECT  34.596 26.663 72.594 27.067 ;
     RECT  73.872 26.875 74.07 27.067 ;
     RECT  32.868 27.031 32.886 27.101 ;
     RECT  0.108 27.067 0.126 27.104 ;
     RECT  3.78 25.439 3.798 27.211 ;
     RECT  4.608 19.949 4.626 27.211 ;
     RECT  3.78 27.211 4.626 27.301 ;
     RECT  3.78 27.301 5.634 27.341 ;
     RECT  107.172 27.337 107.19 27.389 ;
     RECT  30.42 27.481 30.438 27.599 ;
     RECT  26.64 25.321 28.422 27.715 ;
     RECT  29.415 4.541 29.697 27.715 ;
     RECT  26.64 27.715 29.697 27.743 ;
     RECT  27.792 27.743 29.697 27.779 ;
     RECT  20.952 27.067 20.97 27.869 ;
     RECT  18.615 7.232 18.897 27.877 ;
     RECT  13.215 7.373 13.497 27.883 ;
     RECT  18.615 27.877 19.422 27.917 ;
     RECT  34.596 27.067 74.07 27.931 ;
     RECT  13.215 27.883 13.626 28.139 ;
     RECT  106.596 28.255 106.614 28.301 ;
     RECT  3.78 27.341 3.798 28.315 ;
     RECT  4.608 27.341 5.274 28.315 ;
     RECT  6.372 25.591 6.39 28.315 ;
     RECT  3.78 28.315 5.274 28.409 ;
     RECT  28.26 27.779 29.697 28.409 ;
     RECT  6.372 28.315 6.822 28.445 ;
     RECT  4.608 28.409 5.274 28.481 ;
     RECT  12.06 28.291 12.078 28.493 ;
     RECT  34.452 27.931 74.07 28.603 ;
     RECT  6.372 28.445 6.39 28.651 ;
     RECT  13.215 28.139 13.497 28.651 ;
     RECT  34.236 28.603 74.07 28.679 ;
     RECT  14.832 28.507 14.85 28.685 ;
     RECT  6.012 28.651 6.39 28.688 ;
     RECT  13.104 28.651 13.497 28.688 ;
     RECT  26.64 27.743 26.982 28.831 ;
     RECT  6.336 28.688 6.39 28.877 ;
     RECT  26.64 28.831 27.09 28.949 ;
     RECT  33.12 28.453 33.138 29.029 ;
     RECT  2.415 25.439 2.697 29.035 ;
     RECT  33.012 29.029 33.138 29.069 ;
     RECT  107.172 29.029 107.19 29.213 ;
     RECT  28.26 28.409 28.422 29.219 ;
     RECT  33.12 29.069 33.138 29.219 ;
     RECT  2.304 29.035 2.697 29.255 ;
     RECT  3.78 28.409 3.798 29.371 ;
     RECT  3.42 29.371 3.798 29.489 ;
     RECT  3.78 29.489 3.798 29.605 ;
     RECT  34.488 28.679 74.07 29.605 ;
     RECT  3.78 29.605 3.942 29.611 ;
     RECT  5.256 28.481 5.274 29.611 ;
     RECT  3.78 29.611 5.274 29.759 ;
     RECT  34.416 29.605 74.07 29.981 ;
     RECT  33.588 29.995 33.606 30.035 ;
     RECT  107.136 30.091 107.154 30.137 ;
     RECT  34.416 29.981 72.162 30.181 ;
     RECT  4.86 29.759 5.274 30.991 ;
     RECT  6.372 28.877 6.39 30.991 ;
     RECT  0.108 30.955 0.126 30.992 ;
     RECT  106.596 30.955 106.614 31.085 ;
     RECT  34.164 30.181 72.162 31.109 ;
     RECT  34.164 31.109 35.694 31.225 ;
     RECT  33.948 31.225 35.694 31.277 ;
     RECT  36.432 31.109 72.162 31.517 ;
     RECT  30.78 31.531 30.798 31.685 ;
     RECT  24.015 25.613 24.297 31.867 ;
     RECT  29.415 28.409 29.697 31.867 ;
     RECT  32.652 31.801 32.67 31.867 ;
     RECT  23.904 31.867 24.297 31.919 ;
     RECT  29.304 31.867 29.697 31.919 ;
     RECT  32.364 31.867 32.67 31.919 ;
     RECT  107.172 31.891 107.19 31.997 ;
     RECT  73.224 29.981 74.07 32.035 ;
     RECT  73.224 32.035 74.178 32.093 ;
     RECT  32.472 31.919 32.49 32.189 ;
     RECT  34.2 31.277 35.694 32.305 ;
     RECT  36.468 31.517 72.162 32.305 ;
     RECT  34.2 32.305 72.162 32.341 ;
     RECT  33.66 32.341 72.162 32.381 ;
     RECT  25.128 31.657 25.146 32.773 ;
     RECT  0.108 32.845 0.126 32.909 ;
     RECT  34.2 32.381 72.162 32.909 ;
     RECT  107.136 32.872 107.154 32.909 ;
     RECT  7.815 23.189 8.73 33.421 ;
     RECT  34.236 32.909 72.162 33.485 ;
     RECT  34.596 33.485 72.162 33.809 ;
     RECT  107.172 33.583 107.19 33.821 ;
     RECT  36.468 33.809 72.162 34.013 ;
     RECT  73.224 32.093 74.07 34.051 ;
     RECT  73.224 34.051 74.214 34.151 ;
     RECT  33.192 34.501 33.21 34.781 ;
     RECT  106.596 34.735 106.614 34.781 ;
     RECT  0.108 34.795 0.126 34.925 ;
     RECT  2.415 29.255 2.697 35.041 ;
     RECT  7.815 33.421 9.27 35.131 ;
     RECT  73.224 34.151 74.07 35.167 ;
     RECT  2.415 35.041 2.898 35.269 ;
     RECT  3.78 29.759 3.798 35.269 ;
     RECT  2.415 35.269 3.798 35.465 ;
     RECT  36.9 34.013 72.162 35.515 ;
     RECT  107.136 35.659 107.154 35.699 ;
     RECT  36.792 35.515 72.162 35.899 ;
     RECT  72.972 35.167 74.07 35.933 ;
     RECT  107.136 36.571 107.154 36.617 ;
     RECT  2.415 35.465 2.697 36.661 ;
     RECT  3.78 35.465 3.798 36.661 ;
     RECT  2.415 36.661 3.798 36.779 ;
     RECT  0.108 36.763 0.126 36.815 ;
     RECT  36.756 35.899 72.162 36.859 ;
     RECT  73.224 35.933 74.07 37.021 ;
     RECT  34.596 33.809 35.514 37.435 ;
     RECT  106.596 37.435 106.614 37.517 ;
     RECT  25.128 32.773 25.218 37.903 ;
     RECT  33.948 37.435 35.514 37.931 ;
     RECT  72.972 37.021 74.07 38.237 ;
     RECT  4.86 30.991 6.39 38.399 ;
     RECT  106.596 38.437 106.614 38.477 ;
     RECT  2.415 36.779 2.697 38.551 ;
     RECT  3.78 36.779 3.798 38.551 ;
     RECT  2.415 38.551 3.798 38.669 ;
     RECT  73.224 38.237 74.07 38.713 ;
     RECT  0.54 38.677 0.558 38.717 ;
     RECT  73.224 38.713 74.394 38.813 ;
     RECT  33.948 37.931 35.298 38.821 ;
     RECT  7.815 35.131 9.954 39.047 ;
     RECT  33.948 38.821 35.73 39.091 ;
     RECT  107.172 39.217 107.19 39.389 ;
     RECT  7.815 39.047 9.27 40.055 ;
     RECT  73.224 38.813 73.746 40.123 ;
     RECT  33.948 39.091 35.874 40.219 ;
     RECT  33.804 40.219 35.874 40.289 ;
     RECT  106.596 40.135 106.614 40.301 ;
     RECT  73.224 40.123 73.962 40.333 ;
     RECT  73.224 40.333 74.178 40.433 ;
     RECT  14.868 40.555 14.886 40.595 ;
     RECT  73.224 40.433 73.962 40.595 ;
     RECT  0.54 40.597 0.558 40.637 ;
     RECT  34.596 40.289 35.874 40.699 ;
     RECT  36.684 36.859 72.162 40.699 ;
     RECT  34.596 40.699 72.162 40.739 ;
     RECT  15.228 40.711 15.246 40.781 ;
     RECT  106.596 41.215 106.614 41.261 ;
     RECT  34.596 40.739 35.874 41.323 ;
     RECT  34.308 41.323 35.874 41.369 ;
     RECT  32.76 41.341 32.778 41.405 ;
     RECT  73.224 40.595 73.818 41.467 ;
     RECT  36.684 40.739 72.162 41.851 ;
     RECT  34.524 41.369 35.874 41.945 ;
     RECT  73.224 41.467 73.962 42.043 ;
     RECT  107.136 42.139 107.154 42.179 ;
     RECT  3.78 38.669 3.798 42.187 ;
     RECT  29.415 31.919 29.697 42.235 ;
     RECT  73.224 42.043 74.034 42.331 ;
     RECT  25.128 37.903 25.29 42.421 ;
     RECT  26.64 28.949 26.838 42.421 ;
     RECT  36.612 41.851 72.162 42.449 ;
     RECT  73.224 42.331 74.214 42.449 ;
     RECT  2.415 38.669 2.697 42.601 ;
     RECT  3.456 42.187 3.798 42.601 ;
     RECT  25.128 42.421 26.838 42.601 ;
     RECT  0.108 42.565 0.126 42.605 ;
     RECT  24.015 31.919 24.297 42.715 ;
     RECT  2.415 42.601 3.798 42.755 ;
     RECT  73.224 42.449 74.178 42.755 ;
     RECT  25.128 42.601 26.874 42.763 ;
     RECT  34.596 41.945 35.874 43.003 ;
     RECT  36.612 42.449 72.126 43.003 ;
     RECT  107.136 43.051 107.154 43.259 ;
     RECT  25.128 42.763 26.946 43.387 ;
     RECT  29.415 42.235 30.33 43.579 ;
     RECT  107.172 43.843 107.19 43.997 ;
     RECT  3.78 42.755 3.798 44.341 ;
     RECT  4.86 38.399 5.958 44.341 ;
     RECT  2.415 42.755 2.697 44.347 ;
     RECT  3.78 44.341 5.958 44.381 ;
     RECT  1.728 44.347 2.697 44.525 ;
     RECT  73.224 42.755 73.89 44.887 ;
     RECT  25.128 43.387 27.054 44.923 ;
     RECT  29.415 43.579 30.87 44.987 ;
     RECT  73.224 44.887 74.178 44.987 ;
     RECT  34.596 43.003 72.126 45.019 ;
     RECT  25.128 44.923 27.09 45.023 ;
     RECT  107.136 44.923 107.154 45.023 ;
     RECT  4.86 44.381 5.958 45.059 ;
     RECT  25.128 45.023 27.054 45.149 ;
     RECT  33.012 45.115 33.03 45.155 ;
     RECT  32.256 45.301 32.274 45.341 ;
     RECT  34.236 45.019 72.126 45.419 ;
     RECT  5.256 45.059 5.958 45.689 ;
     RECT  107.136 45.832 107.154 45.869 ;
     RECT  73.224 44.987 73.89 46.075 ;
     RECT  5.94 45.689 5.958 46.229 ;
     RECT  22.32 40.171 22.338 46.373 ;
     RECT  73.224 46.075 74.07 46.381 ;
     RECT  34.596 45.419 72.126 46.499 ;
     RECT  0.108 46.411 0.126 46.535 ;
     RECT  73.224 46.381 74.178 46.535 ;
     RECT  5.832 46.651 5.85 46.733 ;
     RECT  29.415 44.987 30.798 46.741 ;
     RECT  73.224 46.535 73.998 46.769 ;
     RECT  107.136 46.747 107.154 46.805 ;
     RECT  106.596 47.653 106.614 47.693 ;
     RECT  73.224 46.769 73.89 47.731 ;
     RECT  73.224 47.731 73.998 47.759 ;
     RECT  73.26 47.759 73.998 47.849 ;
     RECT  6.768 46.651 6.786 48.229 ;
     RECT  6.084 48.229 6.786 48.269 ;
     RECT  2.415 44.525 2.697 48.271 ;
     RECT  3.78 44.381 3.798 48.271 ;
     RECT  2.415 48.271 3.798 48.389 ;
     RECT  0.108 48.331 0.126 48.425 ;
     RECT  107.136 48.619 107.154 48.659 ;
     RECT  106.596 49.477 106.614 49.565 ;
     RECT  3.78 48.389 3.798 49.981 ;
     RECT  3.78 49.981 4.518 50.011 ;
     RECT  3.78 50.011 4.59 50.051 ;
     RECT  34.596 46.499 72.09 50.081 ;
     RECT  3.78 50.051 4.518 50.153 ;
     RECT  2.415 48.389 2.697 50.161 ;
     RECT  3.78 50.153 3.798 50.161 ;
     RECT  29.415 46.741 30.87 50.189 ;
     RECT  2.415 50.161 3.798 50.279 ;
     RECT  0.108 50.287 0.126 50.333 ;
     RECT  26.712 45.149 27.054 50.347 ;
     RECT  26.712 50.347 27.414 50.431 ;
     RECT  28.188 48.091 28.206 50.431 ;
     RECT  107.136 50.443 107.154 50.585 ;
     RECT  26.712 50.431 28.206 50.717 ;
     RECT  26.712 50.717 27.09 50.855 ;
     RECT  34.596 50.081 71.838 50.855 ;
     RECT  25.128 45.149 25.938 51.061 ;
     RECT  25.092 51.061 25.938 51.169 ;
     RECT  25.02 51.169 25.938 51.245 ;
     RECT  107.136 51.355 107.154 51.395 ;
     RECT  73.26 47.849 73.89 51.781 ;
     RECT  4.788 52.171 4.806 52.211 ;
     RECT  0.108 52.177 0.126 52.253 ;
     RECT  107.136 52.312 107.154 52.349 ;
     RECT  17.748 52.459 17.766 52.709 ;
     RECT  18.615 27.917 18.897 52.861 ;
     RECT  18.615 52.861 19.314 52.925 ;
     RECT  107.136 53.227 107.154 53.285 ;
     RECT  34.815 50.855 71.838 53.46 ;
     RECT  25.092 51.245 25.938 53.663 ;
     RECT  28.188 50.717 28.206 53.699 ;
     RECT  34.815 53.46 38.61 53.825 ;
     RECT  73.26 51.781 73.926 53.897 ;
     RECT  6.768 48.269 6.786 53.933 ;
     RECT  73.26 53.897 73.818 53.933 ;
     RECT  5.292 53.995 5.31 54.059 ;
     RECT  2.415 50.279 2.697 54.067 ;
     RECT  7.815 40.055 9.09 54.167 ;
     RECT  73.8 53.933 73.818 54.167 ;
     RECT  2.415 54.067 2.97 54.173 ;
     RECT  107.172 54.103 107.19 54.173 ;
     RECT  35.82 53.825 38.61 54.256 ;
     RECT  35.82 54.256 39.042 54.715 ;
     RECT  35.82 54.715 39.114 54.796 ;
     RECT  96.84 54.379 96.858 54.955 ;
     RECT  106.596 55.021 106.614 55.085 ;
     RECT  35.82 54.796 39.582 55.336 ;
     RECT  35.82 55.336 39.618 55.603 ;
     RECT  35.82 55.603 40.305 55.873 ;
     RECT  45.615 55.603 45.705 55.873 ;
     RECT  51.015 55.603 51.105 55.873 ;
     RECT  56.415 55.603 56.505 55.873 ;
     RECT  61.815 55.603 61.905 55.873 ;
     RECT  67.215 55.603 67.305 55.873 ;
     RECT  72.615 55.603 72.705 55.873 ;
     RECT  7.815 54.167 8.73 55.921 ;
     RECT  26.784 50.855 27.09 55.949 ;
     RECT  35.82 55.873 40.497 55.949 ;
     RECT  7.668 55.921 8.73 55.997 ;
     RECT  107.136 56.011 107.154 56.057 ;
     RECT  0.54 56.065 0.558 56.141 ;
     RECT  35.856 55.949 40.497 56.191 ;
     RECT  35.856 56.191 41.094 56.731 ;
     RECT  35.856 56.731 41.526 56.795 ;
     RECT  106.596 56.875 106.614 56.957 ;
     RECT  35.856 56.795 40.497 57.541 ;
     RECT  3.78 50.279 3.798 57.595 ;
     RECT  35.856 57.541 41.058 57.721 ;
     RECT  6.228 57.811 6.246 57.869 ;
     RECT  3.78 57.595 4.374 57.875 ;
     RECT  107.136 57.835 107.154 57.875 ;
     RECT  0.108 57.955 0.126 58.061 ;
     RECT  42.948 56.911 42.966 58.081 ;
     RECT  35.856 57.721 41.094 58.531 ;
     RECT  35.856 58.531 41.778 58.649 ;
     RECT  107.892 58.693 107.91 58.829 ;
     RECT  96.3 54.955 96.858 58.939 ;
     RECT  42.768 58.081 42.966 58.955 ;
     RECT  35.856 58.649 41.634 59.297 ;
     RECT  37.836 59.297 41.634 59.431 ;
     RECT  37.836 59.431 41.67 59.611 ;
     RECT  5.724 59.275 5.742 59.701 ;
     RECT  5.652 59.701 5.742 59.729 ;
     RECT  107.136 59.707 107.154 59.765 ;
     RECT  3.78 57.875 3.798 59.809 ;
     RECT  5.652 59.729 5.67 59.837 ;
     RECT  37.836 59.611 41.706 59.881 ;
     RECT  42.804 58.955 42.966 59.881 ;
     RECT  3.528 59.809 3.798 59.999 ;
     RECT  7.815 55.997 8.73 59.999 ;
     RECT  0.108 59.947 0.126 60.035 ;
     RECT  13.215 28.688 13.497 60.079 ;
     RECT  37.836 59.881 41.742 60.421 ;
     RECT  42.48 59.881 42.966 60.421 ;
     RECT  103.968 60.421 103.986 60.539 ;
     RECT  107.172 60.385 107.19 60.653 ;
     RECT  105.015 5.999 105.297 60.691 ;
     RECT  104.94 60.691 105.714 60.809 ;
     RECT  102.42 22.513 102.438 60.955 ;
     RECT  37.836 60.421 42.966 60.961 ;
     RECT  103.824 60.655 103.842 60.989 ;
     RECT  34.815 53.825 35.097 61.045 ;
     RECT  34.704 61.045 35.097 61.085 ;
     RECT  102.42 60.955 102.762 61.231 ;
     RECT  37.836 60.961 43.146 61.259 ;
     RECT  37.836 61.259 43.074 61.349 ;
     RECT  102.42 61.231 102.906 61.349 ;
     RECT  44.1 61.465 44.118 61.501 ;
     RECT  102.42 61.349 102.762 61.565 ;
     RECT  106.596 61.231 106.614 61.565 ;
     RECT  43.992 61.501 44.298 61.579 ;
     RECT  25.092 53.663 25.866 61.619 ;
     RECT  104.148 61.501 104.166 61.619 ;
     RECT  105.015 60.809 105.534 61.619 ;
     RECT  43.992 61.579 44.37 61.655 ;
     RECT  3.78 59.999 3.798 61.771 ;
     RECT  44.352 61.655 44.37 61.771 ;
     RECT  6.048 61.765 6.066 61.805 ;
     RECT  3.42 61.771 3.798 61.889 ;
     RECT  0.108 61.867 0.126 61.925 ;
     RECT  44.352 61.771 44.478 61.925 ;
     RECT  45.615 55.873 45.897 61.969 ;
     RECT  44.46 61.925 44.478 62.041 ;
     RECT  45.615 61.969 45.954 62.041 ;
     RECT  37.836 61.349 41.166 62.107 ;
     RECT  44.46 62.041 44.622 62.159 ;
     RECT  44.46 62.159 44.478 62.195 ;
     RECT  45.396 62.041 45.954 62.195 ;
     RECT  99.615 4.793 99.897 62.311 ;
     RECT  37.836 62.107 41.31 62.395 ;
     RECT  99.615 62.311 100.062 62.429 ;
     RECT  45.504 62.195 45.954 62.465 ;
     RECT  107.136 62.491 107.154 62.537 ;
     RECT  105.015 61.619 105.297 62.545 ;
     RECT  37.836 62.395 41.382 62.581 ;
     RECT  42.12 61.349 42.966 62.581 ;
     RECT  99.615 62.429 99.918 62.621 ;
     RECT  105.015 62.545 105.534 62.671 ;
     RECT  103.752 62.401 103.77 62.699 ;
     RECT  104.976 62.671 105.534 62.699 ;
     RECT  37.836 62.581 42.966 62.851 ;
     RECT  104.976 62.699 105.297 63.085 ;
     RECT  104.832 63.085 105.297 63.239 ;
     RECT  37.836 62.851 43.038 63.247 ;
     RECT  45.615 62.465 45.954 63.247 ;
     RECT  46.764 63.121 46.782 63.247 ;
     RECT  37.836 63.247 43.614 63.275 ;
     RECT  45.615 63.247 46.854 63.319 ;
     RECT  99.615 62.621 99.897 63.391 ;
     RECT  107.172 63.247 107.19 63.437 ;
     RECT  41.22 63.275 43.614 63.509 ;
     RECT  99.108 63.391 99.897 63.517 ;
     RECT  41.22 63.509 41.238 63.545 ;
     RECT  98.964 63.517 99.897 63.581 ;
     RECT  45.615 63.319 46.962 63.653 ;
     RECT  46.692 63.653 46.962 63.661 ;
     RECT  7.815 59.999 8.097 63.781 ;
     RECT  7.2 63.781 8.097 63.821 ;
     RECT  2.415 54.173 2.697 63.823 ;
     RECT  1.728 63.823 2.697 63.869 ;
     RECT  46.692 63.661 47.898 63.869 ;
     RECT  46.836 63.869 47.898 64.049 ;
     RECT  103.284 63.931 103.302 64.049 ;
     RECT  46.836 64.049 46.854 64.085 ;
     RECT  47.592 64.049 47.898 64.085 ;
     RECT  47.808 64.085 47.898 64.201 ;
     RECT  102.42 61.565 102.438 64.201 ;
     RECT  105.015 63.239 105.297 64.201 ;
     RECT  102.42 64.201 103.158 64.253 ;
     RECT  47.808 64.201 48.006 64.319 ;
     RECT  47.808 64.319 47.826 64.355 ;
     RECT  104.508 64.201 105.297 64.355 ;
     RECT  107.136 64.315 107.154 64.355 ;
     RECT  37.836 63.275 40.497 64.471 ;
     RECT  48.96 64.291 48.978 64.471 ;
     RECT  105.012 64.355 105.297 64.625 ;
     RECT  48.78 64.471 48.978 64.895 ;
     RECT  37.836 64.471 40.914 65.011 ;
     RECT  102.42 64.253 102.438 65.011 ;
     RECT  37.836 65.011 41.058 65.129 ;
     RECT  102.42 65.011 102.546 65.129 ;
     RECT  102.42 65.129 102.438 65.131 ;
     RECT  102.348 65.131 102.438 65.171 ;
     RECT  107.172 64.939 107.19 65.261 ;
     RECT  48.852 64.895 48.978 65.281 ;
     RECT  105.015 64.625 105.297 65.281 ;
     RECT  37.836 65.129 40.842 65.357 ;
     RECT  48.852 65.281 49.086 65.399 ;
     RECT  103.32 65.281 103.338 65.399 ;
     RECT  105.015 65.281 105.354 65.399 ;
     RECT  2.415 63.869 2.697 65.407 ;
     RECT  3.78 61.889 3.798 65.407 ;
     RECT  50.184 65.407 50.202 65.479 ;
     RECT  2.415 65.407 3.798 65.515 ;
     RECT  37.836 65.357 40.497 65.549 ;
     RECT  49.932 65.479 50.202 65.551 ;
     RECT  48.852 65.399 48.87 65.552 ;
     RECT  0.144 65.755 0.162 65.813 ;
     RECT  99.615 63.581 99.897 65.821 ;
     RECT  29.415 50.189 30.798 65.849 ;
     RECT  46.764 65.749 46.782 65.849 ;
     RECT  42.12 63.509 43.614 65.939 ;
     RECT  99.615 65.821 100.278 65.939 ;
     RECT  49.824 65.551 50.202 65.975 ;
     RECT  99.615 65.939 100.098 65.981 ;
     RECT  39.816 65.549 40.497 66.091 ;
     RECT  51.015 55.873 51.297 66.091 ;
     RECT  105.015 65.399 105.297 66.091 ;
     RECT  2.34 65.515 3.798 66.125 ;
     RECT  50.292 66.091 51.297 66.181 ;
     RECT  104.364 66.091 105.297 66.245 ;
     RECT  39.816 66.091 41.022 66.475 ;
     RECT  39.816 66.475 41.418 66.515 ;
     RECT  50.292 66.181 51.462 66.605 ;
     RECT  51.015 66.605 51.462 66.631 ;
     RECT  41.4 66.515 41.418 66.701 ;
     RECT  101.232 28.759 101.25 66.901 ;
     RECT  42.516 65.939 43.614 67.019 ;
     RECT  51.015 66.631 51.498 67.019 ;
     RECT  101.052 66.901 101.25 67.019 ;
     RECT  104.076 66.901 104.094 67.019 ;
     RECT  106.596 66.181 106.614 67.133 ;
     RECT  104.976 66.245 105.297 67.171 ;
     RECT  2.415 66.125 3.798 67.243 ;
     RECT  52.668 67.171 52.686 67.243 ;
     RECT  20.88 65.641 20.898 67.261 ;
     RECT  51.015 67.019 51.39 67.277 ;
     RECT  52.668 67.243 53.298 67.325 ;
     RECT  104.364 67.171 105.297 67.325 ;
     RECT  39.816 66.515 40.497 67.369 ;
     RECT  41.292 67.243 41.31 67.369 ;
     RECT  37.836 65.549 39.042 67.405 ;
     RECT  39.816 67.369 41.31 67.405 ;
     RECT  2.376 67.243 3.798 67.441 ;
     RECT  53.136 67.325 53.298 67.441 ;
     RECT  37.836 67.405 41.31 67.469 ;
     RECT  25.128 61.619 25.866 67.559 ;
     RECT  53.136 67.441 53.442 67.559 ;
     RECT  53.136 67.559 53.154 67.595 ;
     RECT  54.216 67.441 54.234 67.595 ;
     RECT  0.108 67.675 0.126 67.712 ;
     RECT  42.624 67.019 43.614 67.801 ;
     RECT  2.376 67.441 4.05 67.829 ;
     RECT  54.396 67.711 54.414 67.865 ;
     RECT  40.215 67.469 41.31 67.981 ;
     RECT  106.596 67.981 106.614 68.045 ;
     RECT  40.215 67.981 41.454 68.099 ;
     RECT  40.215 68.099 41.058 68.135 ;
     RECT  54.72 67.981 54.738 68.521 ;
     RECT  45.615 63.653 45.897 68.611 ;
     RECT  56.415 55.873 56.697 68.611 ;
     RECT  54.72 68.521 54.81 68.639 ;
     RECT  45.615 68.611 45.954 68.669 ;
     RECT  2.376 67.829 3.906 68.791 ;
     RECT  55.908 68.611 56.697 68.791 ;
     RECT  54.612 68.755 54.63 68.813 ;
     RECT  47.484 68.791 47.502 68.861 ;
     RECT  42.228 67.801 43.614 68.909 ;
     RECT  76.068 20.083 76.086 68.953 ;
     RECT  106.596 68.917 106.614 68.957 ;
     RECT  2.376 68.791 4.086 69.053 ;
     RECT  55.584 68.791 56.697 69.215 ;
     RECT  5.112 69.331 5.13 69.421 ;
     RECT  2.376 69.053 4.014 69.457 ;
     RECT  55.908 69.215 56.697 69.485 ;
     RECT  56.415 69.485 56.697 69.601 ;
     RECT  1.728 69.457 4.014 69.629 ;
     RECT  14.436 67.801 14.454 69.727 ;
     RECT  4.968 69.421 5.13 69.755 ;
     RECT  6.912 69.727 6.93 69.863 ;
     RECT  56.415 69.601 56.898 69.871 ;
     RECT  106.596 69.835 106.614 69.917 ;
     RECT  2.415 69.629 4.014 70.069 ;
     RECT  4.968 69.755 4.986 70.069 ;
     RECT  56.415 69.871 56.97 70.141 ;
     RECT  2.415 70.069 4.986 70.301 ;
     RECT  56.415 70.141 57.294 70.375 ;
     RECT  56.415 70.375 57.402 70.411 ;
     RECT  58.428 70.339 58.446 70.411 ;
     RECT  58.356 70.411 58.482 70.501 ;
     RECT  56.415 70.411 57.546 70.529 ;
     RECT  3.528 70.301 4.986 70.565 ;
     RECT  27.036 55.949 27.09 70.573 ;
     RECT  64.152 58.891 64.17 70.609 ;
     RECT  5.544 70.573 5.562 70.673 ;
     RECT  58.356 70.501 58.554 70.699 ;
     RECT  56.415 70.529 57.402 70.733 ;
     RECT  58.176 70.699 58.554 70.795 ;
     RECT  3.6 70.565 4.626 70.829 ;
     RECT  107.172 70.537 107.19 70.829 ;
     RECT  3.6 70.829 4.014 70.973 ;
     RECT  58.176 70.795 58.626 70.979 ;
     RECT  22.104 70.795 22.122 71.069 ;
     RECT  58.464 70.979 58.626 71.105 ;
     RECT  42.624 68.909 43.614 71.221 ;
     RECT  58.536 71.105 58.626 71.221 ;
     RECT  59.832 70.951 59.85 71.221 ;
     RECT  22.464 71.221 22.482 71.261 ;
     RECT  42.624 71.221 44.478 71.261 ;
     RECT  45.615 68.669 45.897 71.311 ;
     RECT  51.015 67.277 51.297 71.323 ;
     RECT  58.536 71.221 58.698 71.339 ;
     RECT  45.504 71.311 45.897 71.357 ;
     RECT  48.024 71.311 48.042 71.357 ;
     RECT  58.536 71.339 58.554 71.375 ;
     RECT  59.544 71.221 59.922 71.375 ;
     RECT  50.724 71.323 51.297 71.453 ;
     RECT  45.615 71.357 45.897 71.467 ;
     RECT  52.632 71.419 52.65 71.491 ;
     RECT  59.652 71.375 59.922 71.491 ;
     RECT  60.984 71.419 61.002 71.491 ;
     RECT  45.615 71.467 46.494 71.519 ;
     RECT  52.632 71.491 53.154 71.519 ;
     RECT  42.624 71.261 43.938 71.549 ;
     RECT  53.136 71.519 53.154 71.549 ;
     RECT  0.108 71.563 0.126 71.645 ;
     RECT  59.652 71.491 59.994 71.645 ;
     RECT  60.948 71.491 61.002 71.725 ;
     RECT  107.136 71.707 107.154 71.753 ;
     RECT  3.78 70.973 4.014 71.761 ;
     RECT  60.768 71.725 61.002 71.761 ;
     RECT  61.815 55.873 62.097 71.761 ;
     RECT  3.78 71.761 4.338 71.837 ;
     RECT  59.832 71.645 59.994 71.879 ;
     RECT  60.768 71.761 62.19 71.879 ;
     RECT  61.776 71.879 62.19 72.031 ;
     RECT  63.108 71.995 63.126 72.031 ;
     RECT  45.615 71.519 45.897 72.139 ;
     RECT  60.84 71.879 60.966 72.149 ;
     RECT  61.776 72.031 63.126 72.149 ;
     RECT  60.84 72.149 60.93 72.173 ;
     RECT  60.84 72.173 60.858 72.185 ;
     RECT  64.08 70.609 64.17 72.301 ;
     RECT  45.108 72.139 45.897 72.365 ;
     RECT  64.008 72.301 64.17 72.391 ;
     RECT  9.036 71.581 9.054 72.427 ;
     RECT  61.776 72.149 62.097 72.455 ;
     RECT  63 72.149 63.126 72.463 ;
     RECT  9.036 72.427 9.162 72.464 ;
     RECT  99.615 65.981 99.897 72.571 ;
     RECT  101.232 67.019 101.25 72.571 ;
     RECT  40.215 68.135 40.497 72.619 ;
     RECT  106.596 72.535 106.614 72.653 ;
     RECT  40.215 72.619 41.13 72.689 ;
     RECT  42.624 71.549 43.614 72.689 ;
     RECT  63 72.463 63.234 72.697 ;
     RECT  63.972 72.391 64.17 72.697 ;
     RECT  63 72.697 64.17 72.725 ;
     RECT  70.092 72.499 70.722 72.725 ;
     RECT  88.815 5.027 89.154 72.725 ;
     RECT  70.092 72.725 70.11 72.733 ;
     RECT  69.984 72.733 70.11 72.761 ;
     RECT  54.108 72.571 54.126 72.769 ;
     RECT  83.415 4.109 83.697 72.769 ;
     RECT  53.892 72.769 54.126 72.805 ;
     RECT  42.624 72.689 42.858 72.833 ;
     RECT  37.836 67.469 39.042 72.841 ;
     RECT  40.215 72.689 40.497 72.841 ;
     RECT  53.82 72.805 54.126 72.841 ;
     RECT  42.696 72.833 42.858 72.869 ;
     RECT  52.452 72.379 52.47 72.959 ;
     RECT  53.424 72.841 54.126 72.959 ;
     RECT  54.864 72.841 54.882 72.959 ;
     RECT  63.072 72.725 64.17 72.959 ;
     RECT  63.072 72.959 63.09 72.995 ;
     RECT  53.82 72.959 53.838 73.031 ;
     RECT  37.836 72.841 40.497 73.037 ;
     RECT  51.015 71.453 51.297 73.111 ;
     RECT  45.615 72.365 45.897 73.187 ;
     RECT  56.415 70.733 56.697 73.187 ;
     RECT  61.815 72.455 62.097 73.187 ;
     RECT  56.415 73.187 56.505 73.201 ;
     RECT  42.732 72.869 42.858 73.229 ;
     RECT  37.836 73.037 39.402 73.235 ;
     RECT  79.488 72.841 79.506 73.273 ;
     RECT  56.268 73.201 56.505 73.301 ;
     RECT  2.415 70.301 2.697 73.435 ;
     RECT  3.78 71.837 4.014 73.435 ;
     RECT  45.615 73.187 45.705 73.457 ;
     RECT  51.015 73.111 51.354 73.457 ;
     RECT  56.415 73.301 56.505 73.457 ;
     RECT  61.815 73.187 61.905 73.457 ;
     RECT  2.415 73.435 2.718 73.471 ;
     RECT  2.415 73.471 2.79 73.483 ;
     RECT  37.836 73.235 39.33 73.517 ;
     RECT  42.732 73.229 42.75 73.517 ;
     RECT  107.172 73.507 107.19 73.613 ;
     RECT  3.744 73.435 4.014 73.771 ;
     RECT  2.304 73.483 2.79 73.805 ;
     RECT  14.436 69.727 14.634 73.867 ;
     RECT  2.415 73.805 2.79 74.011 ;
     RECT  3.744 73.771 4.518 74.011 ;
     RECT  14.436 73.867 14.85 74.045 ;
     RECT  2.415 74.011 4.518 74.048 ;
     RECT  3.744 74.048 4.518 74.093 ;
     RECT  3.744 74.093 4.086 74.309 ;
     RECT  3.78 74.309 4.086 74.525 ;
     RECT  10.008 73.741 10.026 74.551 ;
     RECT  107.136 74.491 107.154 74.579 ;
     RECT  10.008 74.551 10.206 74.669 ;
     RECT  5.616 70.681 5.634 75.259 ;
     RECT  40.215 73.037 40.497 75.259 ;
     RECT  40.104 75.259 40.497 75.389 ;
     RECT  0.54 75.397 0.558 75.437 ;
     RECT  106.596 75.397 106.614 75.437 ;
     RECT  5.616 75.259 6.102 75.581 ;
     RECT  41.904 75.541 41.922 75.581 ;
     RECT  45 74.929 45.018 75.6 ;
     RECT  51.336 73.457 51.354 75.6 ;
     RECT  63.864 72.959 64.17 75.6 ;
     RECT  7.02 75.541 7.038 75.695 ;
     RECT  7.815 63.821 8.097 75.775 ;
     RECT  9.036 72.464 9.054 75.775 ;
     RECT  43.596 72.689 43.614 75.775 ;
     RECT  42.948 75.775 43.614 76.045 ;
     RECT  45 75.6 64.17 76.081 ;
     RECT  42.516 76.045 43.614 76.315 ;
     RECT  64.98 76.081 64.998 76.315 ;
     RECT  65.952 75.775 65.97 76.315 ;
     RECT  37.836 73.517 39.042 76.363 ;
     RECT  40.215 75.389 40.497 76.441 ;
     RECT  40.215 76.441 40.95 76.493 ;
     RECT  64.98 76.315 65.97 76.493 ;
     RECT  107.136 76.363 107.154 76.505 ;
     RECT  44.928 76.081 64.17 76.585 ;
     RECT  64.98 76.493 65.574 76.589 ;
     RECT  37.836 76.363 39.402 76.621 ;
     RECT  40.215 76.493 40.497 76.621 ;
     RECT  44.424 76.585 64.17 76.637 ;
     RECT  37.836 76.621 40.497 76.739 ;
     RECT  37.836 76.739 39.402 76.775 ;
     RECT  44.928 76.637 64.17 76.781 ;
     RECT  41.436 76.699 41.454 76.891 ;
     RECT  44.964 76.781 64.17 76.973 ;
     RECT  65.016 76.589 65.574 76.973 ;
     RECT  42.408 76.315 43.614 77.161 ;
     RECT  65.556 76.973 65.574 77.165 ;
     RECT  106.56 77.251 106.578 77.309 ;
     RECT  41.436 76.891 41.634 77.395 ;
     RECT  0.108 77.371 0.126 77.423 ;
     RECT  2.415 74.048 2.697 77.431 ;
     RECT  3.78 74.525 4.014 77.431 ;
     RECT  2.415 77.431 4.014 77.549 ;
     RECT  35.856 59.297 37.062 77.665 ;
     RECT  37.836 76.775 39.042 77.665 ;
     RECT  41.4 77.395 41.634 77.701 ;
     RECT  42.372 77.161 43.614 77.701 ;
     RECT  6.48 77.701 6.498 77.741 ;
     RECT  7.815 75.775 9.054 77.791 ;
     RECT  10.008 74.669 10.026 77.791 ;
     RECT  20.772 67.261 20.898 77.791 ;
     RECT  41.4 77.701 43.614 77.819 ;
     RECT  7.815 77.791 10.026 77.837 ;
     RECT  20.772 77.791 21.618 77.837 ;
     RECT  23.652 42.715 24.297 77.855 ;
     RECT  66.204 78.061 66.222 78.187 ;
     RECT  66.204 78.187 66.366 78.233 ;
     RECT  107.136 78.187 107.154 78.359 ;
     RECT  66.204 78.233 66.222 78.571 ;
     RECT  45 76.973 64.17 78.637 ;
     RECT  20.772 77.837 20.898 78.673 ;
     RECT  66.132 78.571 66.222 78.701 ;
     RECT  40.215 76.739 40.497 78.763 ;
     RECT  7.815 77.837 9.054 78.781 ;
     RECT  10.008 77.837 10.026 78.781 ;
     RECT  10.908 78.709 10.926 78.781 ;
     RECT  40.215 78.763 40.662 78.859 ;
     RECT  41.508 77.819 43.614 78.859 ;
     RECT  10.872 78.781 10.926 78.871 ;
     RECT  18.615 52.925 18.897 78.871 ;
     RECT  18.615 78.871 19.314 78.907 ;
     RECT  18.18 78.907 19.314 78.943 ;
     RECT  7.815 78.781 10.026 78.971 ;
     RECT  26.028 68.071 26.046 79.015 ;
     RECT  10.008 78.971 10.026 79.051 ;
     RECT  10.8 78.871 10.926 79.051 ;
     RECT  20.772 78.673 21.042 79.051 ;
     RECT  10.008 79.051 10.926 79.079 ;
     RECT  106.596 79.015 106.614 79.133 ;
     RECT  44.964 78.637 64.17 79.147 ;
     RECT  66.132 78.701 66.15 79.147 ;
     RECT  7.815 78.971 9.27 79.169 ;
     RECT  2.415 77.549 2.697 79.177 ;
     RECT  3.996 77.549 4.014 79.177 ;
     RECT  3.42 79.177 4.014 79.229 ;
     RECT  20.772 79.051 21.078 79.241 ;
     RECT  20.772 79.241 21.042 79.313 ;
     RECT  24.015 77.855 24.297 79.321 ;
     RECT  1.728 79.177 2.697 79.325 ;
     RECT  65.988 79.147 66.15 79.475 ;
     RECT  14.436 74.045 14.634 79.591 ;
     RECT  65.988 79.475 66.006 79.709 ;
     RECT  10.656 79.079 10.926 79.853 ;
     RECT  10.836 79.853 10.926 79.979 ;
     RECT  106.596 80.053 106.614 80.093 ;
     RECT  2.415 79.325 2.697 80.131 ;
     RECT  3.996 79.229 4.014 80.131 ;
     RECT  7.815 79.169 8.586 80.131 ;
     RECT  2.415 80.131 4.014 80.189 ;
     RECT  30.78 65.849 30.798 80.221 ;
     RECT  35.856 77.665 39.042 80.221 ;
     RECT  2.415 80.189 3.222 80.237 ;
     RECT  7.815 80.131 8.838 80.249 ;
     RECT  20.808 79.313 20.97 80.395 ;
     RECT  21.816 77.971 21.834 80.395 ;
     RECT  35.856 80.221 39.078 80.491 ;
     RECT  35.856 80.491 39.474 80.527 ;
     RECT  40.215 78.859 43.614 80.527 ;
     RECT  35.856 80.527 43.614 80.789 ;
     RECT  20.808 80.395 21.834 80.905 ;
     RECT  20.808 80.905 22.554 80.957 ;
     RECT  107.172 80.905 107.19 81.005 ;
     RECT  20.808 80.957 22.302 81.059 ;
     RECT  20.808 81.059 22.194 81.095 ;
     RECT  20.808 81.095 21.87 81.103 ;
     RECT  23.796 79.321 24.297 81.203 ;
     RECT  5.616 75.581 5.634 81.337 ;
     RECT  0.108 81.211 0.126 81.365 ;
     RECT  20.772 81.103 21.87 81.401 ;
     RECT  20.772 81.401 21.834 81.473 ;
     RECT  3.996 80.189 4.014 81.481 ;
     RECT  20.772 81.473 21.546 81.571 ;
     RECT  3.6 81.481 4.014 81.599 ;
     RECT  35.856 80.789 42.858 81.599 ;
     RECT  106.596 81.877 106.614 81.917 ;
     RECT  6.516 81.547 6.534 82.061 ;
     RECT  5.04 81.337 5.634 82.651 ;
     RECT  106.596 82.789 106.614 82.829 ;
     RECT  35.856 81.599 42.57 82.949 ;
     RECT  2.415 80.237 2.697 83.101 ;
     RECT  3.996 81.599 4.014 83.101 ;
     RECT  7.815 80.249 8.097 83.101 ;
     RECT  2.415 83.101 4.014 83.131 ;
     RECT  4.86 82.651 5.634 83.131 ;
     RECT  0.108 83.065 0.126 83.165 ;
     RECT  7.272 83.101 8.097 83.179 ;
     RECT  2.415 83.131 5.634 83.219 ;
     RECT  7.128 83.179 8.097 83.219 ;
     RECT  34.815 61.085 35.097 83.263 ;
     RECT  35.856 82.949 41.526 83.291 ;
     RECT  44.712 79.147 64.17 83.525 ;
     RECT  5.04 83.219 5.634 83.597 ;
     RECT  34.776 83.263 35.097 83.597 ;
     RECT  44.712 83.525 64.098 83.633 ;
     RECT  35.856 83.291 41.166 83.645 ;
     RECT  35.856 83.645 41.13 83.795 ;
     RECT  107.136 83.755 107.154 83.795 ;
     RECT  35.856 83.795 41.058 83.903 ;
     RECT  35.856 83.903 41.022 84.029 ;
     RECT  35.856 84.029 40.986 84.137 ;
     RECT  35.856 84.137 40.95 84.299 ;
     RECT  107.136 84.667 107.154 84.839 ;
     RECT  0.108 85.099 0.126 85.145 ;
     RECT  2.415 83.219 2.697 85.261 ;
     RECT  2.415 85.261 3.258 85.379 ;
     RECT  6.516 85.339 6.534 85.415 ;
     RECT  8.82 80.249 8.838 85.459 ;
     RECT  107.136 85.579 107.154 85.685 ;
     RECT  8.82 85.459 9.27 85.955 ;
     RECT  5.796 86.635 6.174 86.729 ;
     RECT  0.108 87.007 0.126 87.053 ;
     RECT  2.415 85.379 2.697 87.151 ;
     RECT  2.415 87.151 3.222 87.211 ;
     RECT  3.996 83.219 4.014 87.211 ;
     RECT  2.415 87.211 4.014 87.269 ;
     RECT  5.04 83.597 5.058 87.421 ;
     RECT  3.708 87.269 4.014 87.437 ;
     RECT  107.136 86.491 107.154 87.539 ;
     RECT  20.052 81.571 21.546 87.781 ;
     RECT  5.04 87.421 5.706 87.845 ;
     RECT  107.172 88.195 107.19 88.397 ;
     RECT  3.996 87.437 4.014 88.939 ;
     RECT  3.564 88.939 4.014 89.159 ;
     RECT  0.108 88.939 0.126 89.195 ;
     RECT  106.596 89.269 106.614 89.309 ;
     RECT  5.04 87.845 5.058 89.371 ;
     RECT  5.04 89.371 5.634 89.429 ;
     RECT  5.04 89.429 5.274 89.465 ;
     RECT  7.815 83.219 8.097 89.743 ;
     RECT  8.82 85.955 8.838 89.743 ;
     RECT  42.372 82.949 42.57 89.771 ;
     RECT  35.856 84.299 40.77 90.041 ;
     RECT  107.136 90.235 107.154 90.275 ;
     RECT  5.04 89.465 5.058 91.021 ;
     RECT  0.108 90.907 0.126 91.085 ;
     RECT  99.615 72.571 101.25 91.147 ;
     RECT  103.392 83.497 103.41 91.178 ;
     RECT  99.615 91.147 101.61 91.193 ;
     RECT  107.136 91.147 107.154 91.193 ;
     RECT  5.04 91.021 5.67 91.319 ;
     RECT  103.284 91.178 103.41 91.319 ;
     RECT  103.392 91.319 103.41 91.471 ;
     RECT  5.04 91.319 5.526 91.517 ;
     RECT  103.392 91.471 103.842 91.517 ;
     RECT  22.824 89.131 22.842 91.831 ;
     RECT  24.015 81.203 24.297 91.831 ;
     RECT  6.624 91.471 6.642 91.895 ;
     RECT  34.815 83.597 35.097 92.101 ;
     RECT  35.856 90.041 40.497 92.101 ;
     RECT  34.815 92.101 40.497 92.141 ;
     RECT  107.136 92.059 107.154 92.165 ;
     RECT  35.82 92.141 40.497 92.333 ;
     RECT  2.415 87.269 2.697 92.827 ;
     RECT  2.304 92.827 2.697 92.975 ;
     RECT  107.136 92.971 107.154 93.011 ;
     RECT  18.108 78.943 19.314 93.451 ;
     RECT  20.052 87.781 21.978 93.451 ;
     RECT  9.756 93.361 9.774 93.515 ;
     RECT  107.136 93.931 107.154 94.019 ;
     RECT  67.215 55.873 67.497 94.441 ;
     RECT  67.215 94.441 67.914 94.493 ;
     RECT  67.215 94.493 67.59 94.541 ;
     RECT  3.996 89.159 4.014 94.651 ;
     RECT  5.04 91.517 5.058 94.651 ;
     RECT  0.108 94.747 0.126 94.865 ;
     RECT  107.172 94.603 107.19 94.877 ;
     RECT  2.415 92.975 2.697 94.981 ;
     RECT  3.996 94.651 5.058 94.981 ;
     RECT  26.028 79.015 26.298 95.071 ;
     RECT  27.036 70.573 27.162 95.071 ;
     RECT  2.415 94.981 5.058 95.099 ;
     RECT  3.996 95.099 5.058 95.597 ;
     RECT  6.012 95.179 6.03 95.639 ;
     RECT  7.815 89.743 8.838 95.755 ;
     RECT  107.172 95.719 107.19 95.789 ;
     RECT  7.524 95.755 8.838 95.909 ;
     RECT  7.776 95.909 8.838 96.221 ;
     RECT  45.36 83.633 64.098 96.39 ;
     RECT  35.856 92.333 40.497 96.485 ;
     RECT  107.136 96.667 107.154 96.719 ;
     RECT  0.108 96.667 0.126 96.755 ;
     RECT  4.824 95.597 5.058 96.835 ;
     RECT  5.796 96.799 5.814 96.835 ;
     RECT  4.824 96.835 5.814 96.893 ;
     RECT  5.04 96.893 5.814 97.259 ;
     RECT  42.372 89.771 42.39 97.259 ;
     RECT  35.856 96.485 37.062 97.537 ;
     RECT  37.836 96.485 40.497 97.537 ;
     RECT  59.472 96.39 59.49 97.771 ;
     RECT  71.82 53.46 71.838 97.799 ;
     RECT  107.136 97.627 107.154 97.799 ;
     RECT  35.856 97.537 40.497 98.059 ;
     RECT  35.856 98.059 40.914 98.149 ;
     RECT  42.192 97.411 42.21 98.185 ;
     RECT  35.856 98.149 40.95 98.221 ;
     RECT  41.724 98.185 42.21 98.221 ;
     RECT  35.856 98.221 42.21 98.339 ;
     RECT  2.415 95.099 2.697 98.383 ;
     RECT  3.996 95.597 4.014 98.383 ;
     RECT  35.856 98.339 40.914 98.411 ;
     RECT  5.04 97.259 5.778 98.455 ;
     RECT  41.724 98.339 42.21 98.483 ;
     RECT  2.415 98.383 4.014 98.491 ;
     RECT  5.04 98.455 5.814 98.491 ;
     RECT  106.596 98.455 106.614 98.573 ;
     RECT  35.856 98.411 40.842 98.609 ;
     RECT  35.856 98.609 40.59 98.645 ;
     RECT  2.415 98.491 5.886 98.753 ;
     RECT  6.876 98.383 6.894 98.761 ;
     RECT  45.807 98.533 45.897 98.803 ;
     RECT  51.207 98.533 51.297 98.803 ;
     RECT  56.607 98.533 56.697 98.803 ;
     RECT  62.007 98.533 62.097 98.803 ;
     RECT  2.415 98.753 5.814 98.879 ;
     RECT  6.768 98.761 6.894 98.879 ;
     RECT  2.415 98.879 5.706 98.951 ;
     RECT  43.596 80.789 43.614 98.959 ;
     RECT  7.815 96.221 8.838 98.995 ;
     RECT  14.436 79.591 14.886 99.019 ;
     RECT  14.436 99.019 15.174 99.031 ;
     RECT  15.948 98.887 15.966 99.031 ;
     RECT  41.868 98.483 42.21 99.031 ;
     RECT  43.596 98.959 43.722 99.031 ;
     RECT  59.472 97.771 59.598 99.031 ;
     RECT  7.38 98.995 8.838 99.053 ;
     RECT  59.472 99.031 59.886 99.059 ;
     RECT  7.524 99.053 8.838 99.149 ;
     RECT  14.436 99.031 15.966 99.149 ;
     RECT  41.868 99.031 43.722 99.149 ;
     RECT  15.948 99.149 15.966 99.157 ;
     RECT  14.436 99.149 15.174 99.185 ;
     RECT  15.948 99.157 16.722 99.185 ;
     RECT  41.868 99.149 43.686 99.185 ;
     RECT  41.868 99.185 42.822 99.197 ;
     RECT  43.56 99.185 43.686 99.419 ;
     RECT  16.452 99.185 16.722 99.455 ;
     RECT  43.56 99.419 43.614 99.455 ;
     RECT  107.136 99.451 107.154 99.491 ;
     RECT  35.856 98.645 40.497 99.733 ;
     RECT  59.58 99.059 59.886 99.733 ;
     RECT  35.856 99.733 40.806 99.761 ;
     RECT  16.704 99.455 16.722 99.769 ;
     RECT  37.944 99.761 40.806 99.769 ;
     RECT  16.704 99.769 17.118 99.797 ;
     RECT  41.868 99.197 41.886 99.797 ;
     RECT  37.944 99.769 40.914 99.841 ;
     RECT  37.944 99.841 41.238 99.959 ;
     RECT  10.836 79.979 10.854 100.039 ;
     RECT  37.944 99.959 40.914 100.067 ;
     RECT  37.944 100.067 40.806 100.103 ;
     RECT  2.415 98.951 2.697 100.111 ;
     RECT  3.996 98.951 4.014 100.111 ;
     RECT  7.815 99.149 8.838 100.111 ;
     RECT  6.84 99.967 6.858 100.139 ;
     RECT  7.815 100.111 9.306 100.229 ;
     RECT  12.672 60.079 13.497 100.273 ;
     RECT  2.415 100.111 4.014 100.301 ;
     RECT  10.8 100.039 10.854 100.301 ;
     RECT  107.172 100.237 107.19 100.397 ;
     RECT  12.6 100.273 13.497 100.409 ;
     RECT  0.108 100.471 0.126 100.589 ;
     RECT  59.58 99.733 60.21 100.651 ;
     RECT  17.1 99.797 17.118 100.769 ;
     RECT  7.815 100.229 9.198 100.781 ;
     RECT  2.415 100.301 3.006 100.841 ;
     RECT  7.815 100.781 8.838 100.841 ;
     RECT  18.108 93.451 21.978 100.849 ;
     RECT  69.228 101.275 69.246 101.281 ;
     RECT  68.724 101.281 69.246 101.315 ;
     RECT  68.724 101.315 68.994 101.357 ;
     RECT  106.596 101.317 106.614 101.357 ;
     RECT  7.815 100.841 8.097 101.857 ;
     RECT  34.815 92.141 35.097 101.857 ;
     RECT  34.776 101.857 35.097 102.029 ;
     RECT  37.944 100.103 40.734 102.091 ;
     RECT  59.58 100.651 60.606 102.235 ;
     RECT  106.596 102.229 106.614 102.269 ;
     RECT  61.815 98.803 62.097 102.361 ;
     RECT  3.996 100.301 4.014 102.379 ;
     RECT  3.996 102.379 4.266 102.425 ;
     RECT  0.54 102.469 0.558 102.509 ;
     RECT  35.856 99.761 37.134 102.541 ;
     RECT  37.944 102.091 40.914 102.541 ;
     RECT  35.856 102.541 40.914 102.695 ;
     RECT  35.856 102.695 40.878 102.701 ;
     RECT  35.856 102.701 40.698 102.929 ;
     RECT  35.856 102.929 40.497 103.109 ;
     RECT  94.215 4.691 94.497 103.171 ;
     RECT  106.02 103.081 106.038 103.181 ;
     RECT  68.976 101.357 68.994 103.199 ;
     RECT  94.215 103.171 94.662 103.271 ;
     RECT  98.82 103.243 98.838 103.279 ;
     RECT  99.615 91.193 101.25 103.279 ;
     RECT  69.984 72.761 70.002 103.351 ;
     RECT  69.732 103.351 70.002 103.549 ;
     RECT  98.82 103.279 101.25 103.711 ;
     RECT  69.732 103.549 70.686 103.739 ;
     RECT  106.596 104.053 106.614 104.093 ;
     RECT  98.784 103.711 101.25 104.245 ;
     RECT  98.424 104.245 101.25 104.285 ;
     RECT  0.108 104.395 0.126 104.585 ;
     RECT  3.996 102.425 4.014 104.701 ;
     RECT  67.215 94.541 67.497 104.701 ;
     RECT  3.456 104.701 4.014 104.765 ;
     RECT  67.215 104.701 68.418 104.791 ;
     RECT  67.215 104.791 68.85 104.963 ;
     RECT  107.172 104.863 107.19 105.053 ;
     RECT  69.732 103.739 69.75 105.089 ;
     RECT  68.364 104.963 68.85 105.097 ;
     RECT  68.364 105.097 69.21 105.395 ;
     RECT  72.615 55.873 72.897 105.781 ;
     RECT  71.64 105.781 71.658 105.965 ;
     RECT  107.136 105.931 107.154 105.971 ;
     RECT  72.615 105.781 73.206 106.013 ;
     RECT  53.28 101.857 53.298 106.015 ;
     RECT  54.072 99.121 54.09 106.015 ;
     RECT  67.215 104.963 67.497 106.249 ;
     RECT  68.364 105.395 68.85 106.249 ;
     RECT  35.856 103.109 37.062 106.285 ;
     RECT  37.98 103.109 40.497 106.285 ;
     RECT  35.856 106.285 40.497 106.313 ;
     RECT  0.54 106.285 0.558 106.397 ;
     RECT  67.215 106.249 68.85 106.411 ;
     RECT  53.28 106.015 54.09 106.439 ;
     RECT  54 106.439 54.09 106.547 ;
     RECT  54.072 106.547 54.09 106.555 ;
     RECT  67.215 106.411 70.11 106.555 ;
     RECT  70.956 106.411 70.974 106.555 ;
     RECT  67.215 106.555 70.974 106.583 ;
     RECT  53.1 106.549 53.118 106.589 ;
     RECT  54.072 106.555 54.414 106.709 ;
     RECT  107.136 106.843 107.154 106.979 ;
     RECT  53.136 107.179 53.154 107.249 ;
     RECT  35.856 106.313 37.314 107.357 ;
     RECT  68.292 106.583 70.974 107.401 ;
     RECT  54.396 106.709 54.414 107.429 ;
     RECT  7.524 101.857 8.097 107.515 ;
     RECT  8.82 100.841 8.838 107.515 ;
     RECT  68.292 107.401 71.082 107.519 ;
     RECT  68.292 107.519 70.974 107.555 ;
     RECT  67.215 106.583 67.497 107.755 ;
     RECT  68.292 107.555 70.542 107.755 ;
     RECT  67.215 107.755 70.542 107.833 ;
     RECT  106.596 107.797 106.614 107.837 ;
     RECT  103.392 91.517 103.41 107.941 ;
     RECT  43.596 99.455 43.614 107.969 ;
     RECT  66.708 107.833 70.542 107.969 ;
     RECT  36.144 107.357 37.314 108.059 ;
     RECT  7.524 107.515 8.838 108.329 ;
     RECT  0.108 108.283 0.126 108.365 ;
     RECT  7.524 108.329 8.097 108.445 ;
     RECT  67.215 107.969 70.542 108.481 ;
     RECT  7.272 108.445 8.097 108.509 ;
     RECT  67.215 108.481 70.686 108.679 ;
     RECT  38.124 106.313 40.497 108.715 ;
     RECT  106.596 108.709 106.614 108.749 ;
     RECT  67.215 108.679 71.046 108.841 ;
     RECT  67.215 108.841 71.622 108.859 ;
     RECT  38.124 108.715 40.554 108.869 ;
     RECT  67.104 108.859 71.622 108.905 ;
     RECT  72.615 106.013 72.897 108.907 ;
     RECT  69.408 108.905 71.622 108.985 ;
     RECT  74.376 108.985 74.394 109.021 ;
     RECT  72.615 108.907 73.602 109.111 ;
     RECT  74.376 109.021 74.538 109.111 ;
     RECT  67.215 108.905 68.526 109.139 ;
     RECT  69.408 108.985 71.838 109.139 ;
     RECT  72.615 109.111 74.61 109.147 ;
     RECT  75.42 68.953 76.086 109.147 ;
     RECT  67.215 109.139 68.418 109.175 ;
     RECT  69.408 109.139 71.622 109.211 ;
     RECT  59.58 102.235 60.75 109.319 ;
     RECT  67.215 109.175 68.058 109.319 ;
     RECT  58.572 109.291 58.59 109.445 ;
     RECT  72.615 109.147 76.086 109.445 ;
     RECT  73.62 109.445 76.086 109.679 ;
     RECT  107.136 109.627 107.154 109.679 ;
     RECT  69.408 109.211 71.406 109.751 ;
     RECT  74.124 109.679 76.086 109.787 ;
     RECT  69.408 109.751 70.686 109.823 ;
     RECT  70.236 109.823 70.686 109.859 ;
     RECT  74.124 109.787 74.142 109.859 ;
     RECT  22.824 91.831 24.297 109.921 ;
     RECT  25.128 67.559 25.146 109.921 ;
     RECT  70.236 109.859 70.326 109.949 ;
     RECT  74.988 109.787 76.086 109.949 ;
     RECT  77.148 109.453 77.166 109.957 ;
     RECT  70.236 109.949 70.254 109.985 ;
     RECT  76.968 109.957 77.166 109.993 ;
     RECT  22.824 109.921 25.146 109.997 ;
     RECT  42.804 99.197 42.822 110.011 ;
     RECT  78.015 6.269 78.297 110.101 ;
     RECT  103.32 107.941 103.41 110.101 ;
     RECT  79.488 73.273 80.082 110.129 ;
     RECT  105.015 67.325 105.297 110.191 ;
     RECT  67.215 109.319 67.662 110.219 ;
     RECT  103.32 110.101 103.95 110.219 ;
     RECT  103.32 110.219 103.806 110.237 ;
     RECT  0.108 110.203 0.126 110.255 ;
     RECT  79.776 110.129 80.082 110.255 ;
     RECT  75.42 109.949 76.086 110.263 ;
     RECT  76.86 109.993 77.166 110.263 ;
     RECT  78.015 110.101 78.642 110.263 ;
     RECT  105.015 110.191 105.498 110.291 ;
     RECT  3.996 104.765 4.014 110.335 ;
     RECT  5.04 98.951 5.706 110.335 ;
     RECT  75.42 110.263 77.166 110.335 ;
     RECT  78.015 110.263 78.678 110.335 ;
     RECT  81.432 109.993 81.45 110.335 ;
     RECT  42.768 110.011 42.822 110.371 ;
     RECT  80.064 110.255 80.082 110.371 ;
     RECT  81.432 110.335 81.882 110.371 ;
     RECT  75.42 110.335 78.678 110.399 ;
     RECT  42.768 110.371 43.614 110.489 ;
     RECT  44.46 110.335 44.478 110.489 ;
     RECT  80.064 110.371 81.882 110.489 ;
     RECT  105.015 110.291 105.354 110.489 ;
     RECT  42.804 110.489 43.614 110.525 ;
     RECT  75.42 110.399 78.642 110.525 ;
     RECT  75.42 110.525 77.166 110.561 ;
     RECT  78.015 110.525 78.642 110.561 ;
     RECT  3.996 110.335 5.706 110.573 ;
     RECT  75.42 110.561 76.626 110.573 ;
     RECT  80.064 110.489 81.522 110.573 ;
     RECT  42.804 110.525 43.326 110.669 ;
     RECT  42.804 110.669 42.822 110.759 ;
     RECT  107.136 110.539 107.154 110.759 ;
     RECT  4.86 110.573 5.706 110.795 ;
     RECT  94.215 103.271 94.497 111.001 ;
     RECT  93.816 111.001 94.497 111.019 ;
     RECT  25.128 109.997 25.146 111.029 ;
     RECT  93.492 111.019 94.497 111.065 ;
     RECT  93.816 111.065 94.497 111.149 ;
     RECT  80.064 110.573 80.082 111.379 ;
     RECT  80.856 110.573 81.522 111.379 ;
     RECT  105.015 110.489 105.297 111.379 ;
     RECT  80.064 111.379 81.522 111.451 ;
     RECT  105.015 111.379 105.534 111.451 ;
     RECT  102.42 65.171 102.438 111.499 ;
     RECT  103.32 110.237 103.41 111.499 ;
     RECT  105.015 111.451 106.038 111.533 ;
     RECT  98.892 104.285 101.25 111.569 ;
     RECT  105.015 111.533 105.534 111.569 ;
     RECT  80.064 111.451 81.666 111.605 ;
     RECT  102.42 111.499 103.41 111.677 ;
     RECT  3.996 110.573 4.014 111.739 ;
     RECT  4.86 110.795 5.058 111.739 ;
     RECT  101.232 111.569 101.25 111.991 ;
     RECT  102.42 111.677 102.438 111.991 ;
     RECT  103.32 111.677 103.41 111.991 ;
     RECT  80.064 111.605 81.45 112.075 ;
     RECT  98.892 111.569 100.062 112.109 ;
     RECT  101.232 111.991 102.438 112.109 ;
     RECT  103.32 111.991 103.95 112.109 ;
     RECT  3.996 111.739 5.058 112.145 ;
     RECT  78.015 110.561 78.297 112.216 ;
     RECT  0.108 112.171 0.126 112.217 ;
     RECT  78.015 112.216 78.93 112.253 ;
     RECT  105.015 111.569 105.297 112.261 ;
     RECT  79.776 112.075 81.45 112.379 ;
     RECT  104.544 112.261 105.297 112.379 ;
     RECT  107.136 112.411 107.154 112.451 ;
     RECT  79.776 112.379 81.414 112.523 ;
     RECT  51.015 98.803 51.297 112.891 ;
     RECT  55.26 112.843 55.278 112.919 ;
     RECT  50.724 112.891 51.297 113.021 ;
     RECT  4.86 112.145 5.058 113.035 ;
     RECT  53.712 112.987 53.73 113.099 ;
     RECT  83.415 72.769 84.078 113.099 ;
     RECT  79.884 112.523 81.414 113.189 ;
     RECT  105.015 112.379 105.297 113.305 ;
     RECT  101.232 112.109 101.25 113.341 ;
     RECT  107.136 113.323 107.154 113.369 ;
     RECT  4.788 113.035 5.058 113.419 ;
     RECT  100.908 113.341 101.25 113.459 ;
     RECT  104.976 113.305 105.297 113.459 ;
     RECT  78.015 112.253 78.297 113.659 ;
     RECT  75.42 110.573 76.086 113.701 ;
     RECT  77.472 113.659 78.297 113.701 ;
     RECT  3.996 112.145 4.014 113.729 ;
     RECT  75.42 113.701 78.297 113.729 ;
     RECT  75.42 113.729 76.77 113.741 ;
     RECT  58.824 109.561 58.842 113.765 ;
     RECT  2.415 100.841 2.697 113.881 ;
     RECT  4.788 113.419 5.31 113.881 ;
     RECT  4.788 113.881 5.454 113.999 ;
     RECT  79.884 113.189 81.198 113.999 ;
     RECT  4.788 113.999 5.058 114.115 ;
     RECT  0.108 114.091 0.126 114.143 ;
     RECT  103.32 112.109 103.41 114.235 ;
     RECT  107.172 113.971 107.19 114.269 ;
     RECT  103.176 114.235 103.41 114.305 ;
     RECT  105.015 113.459 105.297 114.421 ;
     RECT  2.415 113.881 3.582 114.571 ;
     RECT  79.884 113.999 80.874 114.619 ;
     RECT  2.34 114.571 3.582 114.691 ;
     RECT  4.608 114.115 5.058 114.691 ;
     RECT  2.34 114.691 5.058 114.809 ;
     RECT  2.34 114.809 4.23 114.845 ;
     RECT  79.668 114.619 80.874 114.925 ;
     RECT  105.015 114.421 105.426 114.925 ;
     RECT  79.668 114.925 80.982 115.079 ;
     RECT  103.392 114.305 103.41 115.147 ;
     RECT  2.34 114.845 3.906 115.151 ;
     RECT  79.668 115.079 80.874 115.151 ;
     RECT  88.815 72.725 89.097 115.159 ;
     RECT  2.376 115.151 3.906 115.187 ;
     RECT  80.244 115.151 80.874 115.187 ;
     RECT  107.172 115.123 107.19 115.229 ;
     RECT  96.156 58.939 96.858 115.339 ;
     RECT  97.776 107.293 97.794 115.339 ;
     RECT  80.244 115.187 80.55 115.349 ;
     RECT  103.212 115.147 103.41 115.349 ;
     RECT  105.015 114.925 105.534 115.349 ;
     RECT  2.376 115.187 3.618 115.385 ;
     RECT  96.156 115.339 97.794 115.385 ;
     RECT  103.212 115.349 103.23 115.385 ;
     RECT  97.776 115.385 97.794 115.501 ;
     RECT  2.376 115.385 3.51 115.529 ;
     RECT  97.776 115.501 97.83 115.565 ;
     RECT  2.376 115.529 3.006 115.619 ;
     RECT  80.244 115.349 80.262 115.619 ;
     RECT  2.376 115.619 2.898 115.691 ;
     RECT  85.536 115.591 85.554 115.771 ;
     RECT  2.376 115.691 2.754 115.889 ;
     RECT  88.815 115.159 89.406 115.897 ;
     RECT  90.468 115.771 90.486 115.897 ;
     RECT  85.392 115.771 85.554 115.925 ;
     RECT  2.376 115.889 2.697 116.159 ;
     RECT  107.136 116.107 107.154 116.159 ;
     RECT  85.824 116.131 86.166 116.189 ;
     RECT  0.108 116.011 0.126 116.195 ;
     RECT  85.824 116.189 85.842 116.195 ;
     RECT  88.815 115.897 90.486 116.311 ;
     RECT  88.815 116.311 90.63 116.573 ;
     RECT  72.615 109.445 72.897 116.923 ;
     RECT  96.156 115.385 96.858 116.923 ;
     RECT  72.615 116.923 73.566 116.941 ;
     RECT  95.76 116.923 96.858 116.968 ;
     RECT  72.504 116.941 73.566 116.969 ;
     RECT  72.504 116.969 72.897 117.005 ;
     RECT  95.436 116.968 96.858 117.005 ;
     RECT  106.596 116.977 106.614 117.053 ;
     RECT  88.815 116.573 90.234 117.113 ;
     RECT  93.312 116.545 93.33 117.211 ;
     RECT  93.132 117.211 93.33 117.259 ;
     RECT  88.815 117.113 89.514 117.347 ;
     RECT  92.736 117.259 93.33 117.355 ;
     RECT  94.215 111.149 94.497 117.355 ;
     RECT  92.736 117.355 94.497 117.391 ;
     RECT  60.084 109.319 60.75 117.689 ;
     RECT  6.588 117.403 6.606 117.779 ;
     RECT  7.524 108.509 8.097 117.779 ;
     RECT  98.892 112.109 99.897 117.859 ;
     RECT  98.856 117.859 99.897 117.895 ;
     RECT  0.54 117.895 0.558 117.965 ;
     RECT  98.748 117.895 99.897 118.021 ;
     RECT  107.136 117.931 107.154 118.049 ;
     RECT  75.42 113.741 76.086 118.201 ;
     RECT  60.3 117.689 60.75 118.229 ;
     RECT  92.484 117.391 94.497 118.355 ;
     RECT  75.42 118.201 76.158 118.471 ;
     RECT  92.484 118.355 93.474 118.555 ;
     RECT  94.215 118.355 94.497 118.561 ;
     RECT  98.748 118.021 100.062 118.561 ;
     RECT  75.42 118.471 76.41 118.589 ;
     RECT  92.232 118.555 93.474 118.595 ;
     RECT  78.015 113.729 78.297 118.597 ;
     RECT  97.776 115.565 97.794 118.597 ;
     RECT  98.712 118.561 100.062 118.597 ;
     RECT  38.124 108.869 40.497 118.669 ;
     RECT  77.364 118.597 78.297 118.705 ;
     RECT  77.292 118.705 78.297 118.741 ;
     RECT  94.215 118.561 94.662 118.831 ;
     RECT  92.376 118.595 93.474 118.859 ;
     RECT  92.592 118.859 93.474 118.895 ;
     RECT  7.815 117.779 8.097 118.903 ;
     RECT  106.596 118.831 106.614 118.925 ;
     RECT  92.592 118.895 93.222 118.931 ;
     RECT  77.184 118.741 78.297 118.967 ;
     RECT  94.215 118.831 94.698 118.967 ;
     RECT  38.124 118.669 40.626 119.003 ;
     RECT  94.215 118.967 94.662 119.003 ;
     RECT  77.292 118.967 78.297 119.039 ;
     RECT  96.156 117.005 96.858 119.083 ;
     RECT  26.028 95.071 27.162 119.101 ;
     RECT  96.012 119.083 96.858 119.101 ;
     RECT  97.776 118.597 100.062 119.101 ;
     RECT  94.215 119.003 94.59 119.117 ;
     RECT  38.124 119.003 40.497 119.129 ;
     RECT  92.592 118.931 93.186 119.165 ;
     RECT  26.028 119.101 27.342 119.173 ;
     RECT  101.232 113.459 101.25 119.281 ;
     RECT  17.784 100.849 21.978 119.399 ;
     RECT  95.94 119.101 100.062 119.399 ;
     RECT  96.156 119.399 100.062 119.479 ;
     RECT  100.872 119.281 101.25 119.479 ;
     RECT  93.168 119.165 93.186 119.507 ;
     RECT  103.968 118.939 103.986 119.641 ;
     RECT  103.968 119.641 104.166 119.821 ;
     RECT  105.015 115.349 105.297 119.821 ;
     RECT  60.732 118.229 60.75 119.849 ;
     RECT  38.88 119.129 40.497 119.939 ;
     RECT  107.136 119.803 107.154 119.939 ;
     RECT  0.108 119.899 0.126 119.975 ;
     RECT  7.74 118.903 8.097 119.983 ;
     RECT  8.82 108.329 8.838 119.983 ;
     RECT  39.996 119.939 40.497 120.011 ;
     RECT  5.04 114.809 5.058 120.055 ;
     RECT  103.968 119.821 105.297 120.181 ;
     RECT  4.572 120.055 5.058 120.269 ;
     RECT  96.156 119.479 101.25 120.269 ;
     RECT  96.192 120.269 101.25 120.361 ;
     RECT  102.42 112.109 102.438 120.361 ;
     RECT  40.032 120.011 40.497 120.551 ;
     RECT  96.192 120.361 102.438 120.595 ;
     RECT  103.68 120.181 105.297 120.595 ;
     RECT  106.524 120.715 106.542 120.821 ;
     RECT  96.192 120.595 105.297 120.857 ;
     RECT  97.452 120.857 105.297 121.019 ;
     RECT  97.452 121.019 97.974 121.181 ;
     RECT  97.704 121.181 97.974 121.199 ;
     RECT  38.88 119.939 39.078 121.289 ;
     RECT  97.704 121.199 97.866 121.289 ;
     RECT  97.704 121.289 97.722 121.325 ;
     RECT  6.516 120.523 6.534 121.405 ;
     RECT  38.124 119.129 38.142 121.435 ;
     RECT  5.04 120.269 5.058 121.531 ;
     RECT  6.12 121.405 6.534 121.559 ;
     RECT  106.56 121.567 106.578 121.661 ;
     RECT  2.415 116.159 2.697 121.711 ;
     RECT  2.415 121.711 3.114 121.829 ;
     RECT  0.108 121.819 0.126 121.865 ;
     RECT  5.04 121.531 5.166 121.997 ;
     RECT  38.052 121.435 38.142 122.215 ;
     RECT  7.74 119.983 8.838 122.279 ;
     RECT  75.42 118.589 76.086 122.279 ;
     RECT  98.892 121.019 101.502 122.369 ;
     RECT  102.42 121.019 105.297 122.485 ;
     RECT  102.348 122.485 105.297 122.525 ;
     RECT  97.38 122.539 97.398 122.587 ;
     RECT  107.172 122.521 107.19 122.621 ;
     RECT  14.436 99.185 14.886 122.639 ;
     RECT  97.38 122.587 97.722 122.639 ;
     RECT  97.38 122.639 97.542 122.909 ;
     RECT  97.38 122.909 97.398 122.945 ;
     RECT  25.416 119.173 27.342 123.151 ;
     RECT  25.416 123.151 27.594 123.163 ;
     RECT  37.836 122.215 38.142 123.179 ;
     RECT  39.06 121.289 39.078 123.259 ;
     RECT  40.215 120.551 40.497 123.259 ;
     RECT  14.436 122.639 14.742 123.323 ;
     RECT  25.416 123.163 27.774 123.331 ;
     RECT  98.892 122.369 101.25 123.331 ;
     RECT  6.516 121.559 6.534 123.421 ;
     RECT  18.108 119.399 21.978 123.421 ;
     RECT  22.824 109.997 24.297 123.421 ;
     RECT  30.636 80.221 30.798 123.421 ;
     RECT  7.74 122.279 8.55 123.449 ;
     RECT  39.06 123.259 40.497 123.493 ;
     RECT  106.596 123.493 106.614 123.533 ;
     RECT  6.228 123.421 6.534 123.565 ;
     RECT  7.74 123.449 8.097 123.565 ;
     RECT  14.616 123.323 14.742 123.593 ;
     RECT  2.415 121.829 2.697 123.601 ;
     RECT  5.04 121.997 5.058 123.601 ;
     RECT  14.652 123.593 14.742 123.601 ;
     RECT  15.948 122.611 15.966 123.601 ;
     RECT  6.228 123.565 8.097 123.677 ;
     RECT  98.892 123.331 101.286 123.677 ;
     RECT  18.108 123.421 24.297 123.691 ;
     RECT  25.344 123.331 27.774 123.691 ;
     RECT  100.836 123.677 101.286 123.691 ;
     RECT  102.42 122.525 105.297 123.691 ;
     RECT  2.415 123.601 2.97 123.719 ;
     RECT  29.415 65.849 29.697 123.727 ;
     RECT  5.04 123.601 5.13 123.755 ;
     RECT  18.108 123.691 27.774 123.763 ;
     RECT  0.108 123.727 0.126 123.773 ;
     RECT  18.108 123.763 27.882 123.863 ;
     RECT  36.144 108.059 37.062 124.061 ;
     RECT  6.228 123.677 6.534 124.105 ;
     RECT  28.836 123.727 29.697 124.141 ;
     RECT  100.836 123.691 105.297 124.141 ;
     RECT  28.764 124.141 29.697 124.231 ;
     RECT  30.636 123.421 31.302 124.231 ;
     RECT  37.836 123.179 38.106 124.231 ;
     RECT  38.988 123.493 40.497 124.231 ;
     RECT  36.396 124.061 37.062 124.375 ;
     RECT  37.836 124.231 40.497 124.375 ;
     RECT  56.415 98.803 56.697 124.411 ;
     RECT  107.172 124.231 107.19 124.445 ;
     RECT  5.04 123.755 5.058 124.501 ;
     RECT  5.868 124.105 6.534 124.501 ;
     RECT  34.815 102.029 35.097 124.501 ;
     RECT  96.192 120.857 96.21 124.529 ;
     RECT  15.948 123.601 16.506 124.537 ;
     RECT  5.04 124.501 6.534 124.541 ;
     RECT  18.108 123.863 27.81 124.609 ;
     RECT  36.396 124.375 40.497 124.609 ;
     RECT  41.22 119.101 41.238 124.609 ;
     RECT  7.74 123.677 8.097 124.645 ;
     RECT  8.82 124.033 8.838 124.645 ;
     RECT  18 124.609 27.81 124.645 ;
     RECT  28.764 124.231 31.302 124.645 ;
     RECT  82.44 124.501 82.458 124.645 ;
     RECT  5.04 124.541 5.058 124.681 ;
     RECT  15.948 124.537 16.83 124.681 ;
     RECT  60.3 123.727 60.318 124.681 ;
     RECT  98.892 123.677 99.897 124.681 ;
     RECT  10.836 100.301 10.854 124.709 ;
     RECT  100.836 124.141 105.354 124.771 ;
     RECT  53.388 113.701 53.406 124.795 ;
     RECT  88.815 117.347 89.097 124.795 ;
     RECT  98.856 124.681 99.897 124.795 ;
     RECT  100.836 124.771 105.462 124.795 ;
     RECT  83.415 113.099 83.697 124.807 ;
     RECT  70.344 124.795 70.362 124.837 ;
     RECT  36.396 124.609 41.238 124.843 ;
     RECT  70.344 124.837 70.722 124.843 ;
     RECT  72.615 117.005 72.897 124.843 ;
     RECT  73.836 119.551 73.854 124.843 ;
     RECT  75.42 122.279 75.438 124.843 ;
     RECT  78.015 119.039 78.297 124.843 ;
     RECT  83.415 124.807 83.97 124.843 ;
     RECT  69.3 124.681 69.318 124.879 ;
     RECT  70.344 124.843 70.83 124.879 ;
     RECT  88.272 124.795 89.097 124.879 ;
     RECT  67.215 110.219 67.497 124.891 ;
     RECT  80.784 124.795 80.802 124.891 ;
     RECT  32.508 124.375 32.526 124.915 ;
     RECT  59.544 123.835 59.562 124.915 ;
     RECT  60.3 124.681 61.002 124.915 ;
     RECT  69.3 124.879 70.83 124.915 ;
     RECT  75.42 124.843 75.618 124.915 ;
     RECT  75.384 124.915 75.618 124.942 ;
     RECT  15.948 124.681 17.01 124.951 ;
     RECT  42.66 124.537 42.678 124.951 ;
     RECT  45.615 98.803 45.897 124.951 ;
     RECT  59.544 124.915 61.002 124.951 ;
     RECT  61.815 102.361 62.478 124.951 ;
     RECT  69.3 124.915 70.866 124.951 ;
     RECT  82.332 124.645 82.458 124.951 ;
     RECT  83.268 124.843 83.97 124.951 ;
     RECT  5.868 124.541 6.534 125.035 ;
     RECT  7.74 124.645 8.838 125.035 ;
     RECT  4.572 124.681 5.058 125.041 ;
     RECT  43.812 124.807 43.83 125.041 ;
     RECT  75.384 124.942 75.654 125.041 ;
     RECT  76.428 124.843 76.446 125.041 ;
     RECT  85.5 124.879 85.518 125.041 ;
     RECT  87.696 124.879 89.097 125.041 ;
     RECT  36.396 124.843 41.67 125.069 ;
     RECT  54.972 124.951 54.99 125.077 ;
     RECT  69.3 124.951 70.938 125.077 ;
     RECT  75.384 125.041 76.446 125.077 ;
     RECT  78.015 124.843 78.678 125.077 ;
     RECT  79.416 124.843 79.434 125.077 ;
     RECT  87.696 125.041 89.514 125.077 ;
     RECT  5.868 125.035 8.838 125.105 ;
     RECT  37.152 125.069 41.67 125.105 ;
     RECT  56.415 124.411 57.402 125.113 ;
     RECT  58.752 123.223 58.77 125.113 ;
     RECT  59.544 124.951 62.658 125.113 ;
     RECT  69.156 125.077 70.938 125.113 ;
     RECT  75.096 125.077 76.446 125.113 ;
     RECT  86.688 125.041 86.706 125.113 ;
     RECT  87.48 125.077 89.514 125.113 ;
     RECT  43.668 125.041 43.83 125.149 ;
     RECT  47.916 113.737 47.934 125.149 ;
     RECT  49.572 124.795 49.59 125.149 ;
     RECT  78.015 125.077 79.434 125.149 ;
     RECT  5.868 125.105 6.966 125.177 ;
     RECT  53.388 124.795 53.442 125.179 ;
     RECT  54.36 125.077 54.99 125.179 ;
     RECT  66.672 124.891 67.554 125.179 ;
     RECT  74.664 125.113 76.446 125.179 ;
     RECT  78.015 125.149 80.01 125.179 ;
     RECT  80.784 124.891 81.306 125.179 ;
     RECT  42.66 124.951 42.858 125.185 ;
     RECT  43.668 125.149 44.046 125.185 ;
     RECT  45.615 124.951 45.99 125.185 ;
     RECT  46.728 124.537 46.746 125.185 ;
     RECT  56.415 125.113 58.77 125.185 ;
     RECT  59.544 125.113 62.73 125.185 ;
     RECT  4.356 125.041 5.058 125.221 ;
     RECT  7.74 125.105 8.838 125.221 ;
     RECT  13.215 100.409 13.497 125.221 ;
     RECT  15.948 124.951 17.046 125.221 ;
     RECT  18 124.645 31.302 125.221 ;
     RECT  42.66 125.185 44.046 125.221 ;
     RECT  47.916 125.149 48.186 125.221 ;
     RECT  49.572 125.149 50.058 125.221 ;
     RECT  51.015 113.021 51.297 125.221 ;
     RECT  72.615 124.843 73.854 125.221 ;
     RECT  86.688 125.113 89.514 125.221 ;
     RECT  90.576 125.113 90.594 125.221 ;
     RECT  36.396 125.069 36.414 125.249 ;
     RECT  5.868 125.177 5.886 125.311 ;
     RECT  34.776 124.501 35.097 125.311 ;
     RECT  64.08 96.39 64.098 125.311 ;
     RECT  66.24 125.179 67.554 125.311 ;
     RECT  78.015 125.179 81.306 125.311 ;
     RECT  86.688 125.221 90.594 125.311 ;
     RECT  4.212 125.221 5.058 125.323 ;
     RECT  5.832 125.311 5.886 125.323 ;
     RECT  10.872 124.843 11.538 125.339 ;
     RECT  98.856 124.795 105.462 125.339 ;
     RECT  69.048 125.113 70.938 125.347 ;
     RECT  72.108 125.221 73.854 125.347 ;
     RECT  85.212 125.041 85.842 125.347 ;
     RECT  86.688 125.311 90.882 125.347 ;
     RECT  96.084 125.149 96.102 125.347 ;
     RECT  74.664 125.179 76.554 125.357 ;
     RECT  2.415 123.719 2.697 125.371 ;
     RECT  37.26 125.105 41.67 125.371 ;
     RECT  42.66 125.221 44.694 125.371 ;
     RECT  4.212 125.323 5.886 125.375 ;
     RECT  47.664 125.221 51.297 125.375 ;
     RECT  14.652 123.601 14.922 125.383 ;
     RECT  15.948 125.221 31.302 125.383 ;
     RECT  34.416 125.311 35.097 125.383 ;
     RECT  47.664 125.375 48.798 125.383 ;
     RECT  53.388 125.179 54.99 125.383 ;
     RECT  56.415 125.185 62.73 125.383 ;
     RECT  66.24 125.311 68.202 125.383 ;
     RECT  69.048 125.347 73.854 125.383 ;
     RECT  106.56 125.347 106.578 125.405 ;
     RECT  47.484 125.383 48.798 125.411 ;
     RECT  66.24 125.383 73.854 125.419 ;
     RECT  78.015 125.311 81.486 125.419 ;
     RECT  82.332 124.951 83.97 125.419 ;
     RECT  85.212 125.347 90.882 125.419 ;
     RECT  94.215 119.117 94.497 125.419 ;
     RECT  95.724 125.347 96.102 125.419 ;
     RECT  96.876 125.311 96.894 125.419 ;
     RECT  12.456 125.221 13.497 125.455 ;
     RECT  64.08 125.311 64.386 125.455 ;
     RECT  78.015 125.419 83.97 125.455 ;
     RECT  85.212 125.419 90.99 125.455 ;
     RECT  93.132 125.185 93.15 125.455 ;
     RECT  94.14 125.419 94.497 125.455 ;
     RECT  66.24 125.419 73.89 125.467 ;
     RECT  56.415 125.383 63.27 125.491 ;
     RECT  64.08 125.455 64.494 125.491 ;
     RECT  85.212 125.455 91.026 125.491 ;
     RECT  91.764 124.681 91.782 125.491 ;
     RECT  45.615 125.185 46.746 125.581 ;
     RECT  47.484 125.411 48.33 125.581 ;
     RECT  66.204 125.467 73.89 125.581 ;
     RECT  74.664 125.357 76.518 125.581 ;
     RECT  98.856 125.339 100.998 125.611 ;
     RECT  14.652 125.383 31.302 125.617 ;
     RECT  93.132 125.455 94.497 125.617 ;
     RECT  95.724 125.419 96.894 125.617 ;
     RECT  45.615 125.581 48.33 125.653 ;
     RECT  53.388 125.383 55.638 125.653 ;
     RECT  65.232 125.581 65.25 125.653 ;
     RECT  49.572 125.375 51.297 125.681 ;
     RECT  56.415 125.491 64.494 125.689 ;
     RECT  78.015 125.455 84.114 125.689 ;
     RECT  85.212 125.491 91.782 125.689 ;
     RECT  93.132 125.617 96.894 125.702 ;
     RECT  66.204 125.581 76.518 125.717 ;
     RECT  2.415 125.371 2.97 125.725 ;
     RECT  10.872 125.339 11.07 125.725 ;
     RECT  37.26 125.371 44.694 125.725 ;
     RECT  45.612 125.653 48.33 125.725 ;
     RECT  53.352 125.653 55.638 125.725 ;
     RECT  0.108 125.707 0.126 125.753 ;
     RECT  2.415 125.725 3.186 125.761 ;
     RECT  4.212 125.375 4.374 125.761 ;
     RECT  7.74 125.221 9.126 125.761 ;
     RECT  14.508 125.617 31.302 125.761 ;
     RECT  32.112 124.915 32.526 125.761 ;
     RECT  33.444 125.725 33.462 125.761 ;
     RECT  34.236 125.383 35.097 125.761 ;
     RECT  78.015 125.689 91.782 125.761 ;
     RECT  92.952 125.702 96.894 125.761 ;
     RECT  50.796 125.681 51.297 125.789 ;
     RECT  56.376 125.689 64.494 125.803 ;
     RECT  65.232 125.653 65.358 125.803 ;
     RECT  2.415 125.761 4.374 125.851 ;
     RECT  11.808 125.455 13.497 125.851 ;
     RECT  14.292 125.761 32.526 125.851 ;
     RECT  53.172 125.725 55.638 125.851 ;
     RECT  56.376 125.803 65.358 125.851 ;
     RECT  11.808 125.851 32.526 125.879 ;
     RECT  53.172 125.851 65.358 125.879 ;
     RECT  66.204 125.717 76.338 125.879 ;
     RECT  53.172 125.879 64.458 125.885 ;
     RECT  33.444 125.761 35.097 125.887 ;
     RECT  51.015 125.789 51.297 125.899 ;
     RECT  53.172 125.885 64.386 125.923 ;
     RECT  37.26 125.725 48.33 125.951 ;
     RECT  65.232 125.879 65.358 125.959 ;
     RECT  5.58 125.375 5.886 125.995 ;
     RECT  6.66 125.177 6.966 125.995 ;
     RECT  52.272 125.947 52.29 125.995 ;
     RECT  53.028 125.923 64.386 125.995 ;
     RECT  5.58 125.995 6.966 126.031 ;
     RECT  7.74 125.761 9.81 126.031 ;
     RECT  10.8 125.725 11.07 126.031 ;
     RECT  17.964 125.879 32.526 126.031 ;
     RECT  33.444 125.887 35.37 126.031 ;
     RECT  36.108 125.851 36.126 126.031 ;
     RECT  37.26 125.951 41.13 126.031 ;
     RECT  77.724 125.761 96.894 126.031 ;
     RECT  5.58 126.031 11.07 126.121 ;
     RECT  11.808 125.879 17.046 126.121 ;
     RECT  17.964 126.031 36.126 126.121 ;
     RECT  36.9 126.031 41.13 126.121 ;
     RECT  42.768 125.951 48.33 126.301 ;
     RECT  49.572 125.681 49.986 126.301 ;
     RECT  65.232 125.959 65.466 126.301 ;
     RECT  66.204 125.879 76.194 126.301 ;
     RECT  77.256 126.031 96.894 126.301 ;
     RECT  97.776 125.611 100.998 126.301 ;
     RECT  101.916 125.339 105.462 126.301 ;
     RECT  107.172 125.923 107.19 126.317 ;
     RECT  17.964 126.121 41.13 126.329 ;
     RECT  2.34 125.851 4.374 126.391 ;
     RECT  2.34 126.391 4.842 126.427 ;
     RECT  5.58 126.121 17.046 126.427 ;
     RECT  77.256 126.301 105.462 126.427 ;
     RECT  51.015 125.899 51.534 126.499 ;
     RECT  52.272 125.995 64.386 126.499 ;
     RECT  42.768 126.301 49.986 126.571 ;
     RECT  77.256 126.427 105.93 126.769 ;
     RECT  2.34 126.427 17.046 126.805 ;
     RECT  65.232 126.301 76.194 126.805 ;
     RECT  77.256 126.769 106.614 126.805 ;
     RECT  2.34 126.805 17.226 126.841 ;
     RECT  17.964 126.329 27.378 126.841 ;
     RECT  28.152 126.329 41.13 126.841 ;
     RECT  41.904 125.951 41.958 126.841 ;
     RECT  42.768 126.571 50.202 126.841 ;
     RECT  51.015 126.499 64.386 126.841 ;
     RECT  65.16 126.805 76.194 126.841 ;
     RECT  77.04 126.805 106.614 126.841 ;
     RECT  2.34 126.841 27.378 126.959 ;
     RECT  42.768 126.841 106.614 126.959 ;
     RECT  25.416 126.959 27.378 127.037 ;
     RECT  2.34 126.959 10.53 127.111 ;
     RECT  25.56 127.037 27.378 127.111 ;
     RECT  28.152 126.841 41.958 127.111 ;
     RECT  42.768 126.959 76.446 127.111 ;
     RECT  77.328 126.959 106.614 127.187 ;
     RECT  105.912 127.187 106.614 127.192 ;
     RECT  2.304 127.111 10.53 127.229 ;
     RECT  11.268 126.959 24.678 127.229 ;
     RECT  25.56 127.111 76.446 127.229 ;
     RECT  77.328 127.187 105.174 127.229 ;
     RECT  105.912 127.192 107.154 127.229 ;
     RECT  15.444 127.229 19.062 127.265 ;
     RECT  32.04 127.229 36.738 127.265 ;
     RECT  37.62 127.229 38.502 127.265 ;
     RECT  51.015 127.229 55.494 127.265 ;
     RECT  86.616 127.229 95.598 127.265 ;
     RECT  96.372 127.229 101.322 127.265 ;
     RECT  2.34 127.229 6.102 127.301 ;
     RECT  11.268 127.229 14.67 127.301 ;
     RECT  17.028 127.265 19.062 127.301 ;
     RECT  21.456 127.229 24.57 127.301 ;
     RECT  25.56 127.229 27.558 127.301 ;
     RECT  34.38 127.265 36.738 127.301 ;
     RECT  64.296 127.229 65.394 127.301 ;
     RECT  77.544 127.229 83.826 127.301 ;
     RECT  98.064 127.265 101.322 127.301 ;
     RECT  51.015 127.265 53.586 127.373 ;
     RECT  86.616 127.265 91.242 127.373 ;
     RECT  2.34 127.301 5.706 127.409 ;
     RECT  9.432 127.229 10.53 127.409 ;
     RECT  11.448 127.301 14.67 127.409 ;
     RECT  21.456 127.301 22.842 127.409 ;
     RECT  28.548 127.229 30.762 127.409 ;
     RECT  39.348 127.229 41.886 127.409 ;
     RECT  42.84 127.229 46.35 127.409 ;
     RECT  47.268 127.229 50.166 127.409 ;
     RECT  54.576 127.265 55.494 127.409 ;
     RECT  60.444 127.229 63.306 127.409 ;
     RECT  67.032 127.229 74.214 127.409 ;
     RECT  74.988 127.229 75.222 127.409 ;
     RECT  77.544 127.301 81.018 127.409 ;
     RECT  86.616 127.373 87.246 127.409 ;
     RECT  102.096 127.229 105.105 127.421 ;
     RECT  6.84 127.229 8.586 127.457 ;
     RECT  11.448 127.409 13.698 127.457 ;
     RECT  29.415 127.409 30.762 127.457 ;
     RECT  34.38 127.301 35.982 127.457 ;
     RECT  44.46 127.409 46.35 127.457 ;
     RECT  51.015 127.373 52.146 127.457 ;
     RECT  56.415 127.229 57.33 127.457 ;
     RECT  60.444 127.409 61.905 127.457 ;
     RECT  67.032 127.409 67.842 127.457 ;
     RECT  69.552 127.409 72.774 127.457 ;
     RECT  77.544 127.409 78.75 127.457 ;
     RECT  94.14 127.265 94.305 127.457 ;
     RECT  104.04 127.421 105.105 127.457 ;
     RECT  0.108 127.345 0.126 127.661 ;
     RECT  102.096 127.421 102.762 127.661 ;
     RECT  13.68 127.457 13.698 127.709 ;
     RECT  14.58 127.409 14.67 127.709 ;
     RECT  15.444 127.265 16.11 127.709 ;
     RECT  51.372 127.457 52.146 127.709 ;
     RECT  107.964 125.761 107.982 128.011 ;
     RECT  107.892 128.011 107.982 128.045 ;
     RECT  107.892 128.045 107.91 128.141 ;
     RECT  2.34 127.409 3.762 128.237 ;
     RECT  4.572 127.409 5.706 128.237 ;
     RECT  6.84 127.457 7.254 128.237 ;
     RECT  8.568 127.457 8.586 128.237 ;
     RECT  9.432 127.409 10.206 128.237 ;
     RECT  11.448 127.457 12.582 128.237 ;
     RECT  17.028 127.301 19.026 128.237 ;
     RECT  19.944 127.229 20.466 128.237 ;
     RECT  22.248 127.409 22.842 128.237 ;
     RECT  23.94 127.301 24.57 128.237 ;
     RECT  25.56 127.301 26.406 128.237 ;
     RECT  27.144 127.301 27.162 128.237 ;
     RECT  29.736 127.457 30.762 128.237 ;
     RECT  32.04 127.265 32.994 128.237 ;
     RECT  34.38 127.457 34.47 128.237 ;
     RECT  35.28 127.457 35.982 128.237 ;
     RECT  37.62 127.265 38.214 128.237 ;
     RECT  39.348 127.409 41.094 128.237 ;
     RECT  41.868 127.409 41.886 128.237 ;
     RECT  42.84 127.409 43.542 128.237 ;
     RECT  44.46 127.457 45.054 128.237 ;
     RECT  45.972 127.457 46.35 128.237 ;
     RECT  47.268 127.409 49.23 128.237 ;
     RECT  50.148 127.409 50.166 128.237 ;
     RECT  52.956 127.373 53.586 128.237 ;
     RECT  54.576 127.409 54.594 128.237 ;
     RECT  56.556 127.457 57.33 128.237 ;
     RECT  58.716 127.229 59.706 128.237 ;
     RECT  60.444 127.457 61.758 128.237 ;
     RECT  62.82 127.409 63.306 128.237 ;
     RECT  64.332 127.301 65.394 128.237 ;
     RECT  66.168 127.229 66.186 128.237 ;
     RECT  67.032 127.457 67.05 128.237 ;
     RECT  67.824 127.457 67.842 128.237 ;
     RECT  69.552 127.457 72.018 128.237 ;
     RECT  72.756 127.457 72.774 128.237 ;
     RECT  73.548 127.409 74.214 128.237 ;
     RECT  74.988 127.409 75.006 128.237 ;
     RECT  76.392 127.229 76.446 128.237 ;
     RECT  77.544 127.457 77.562 128.237 ;
     RECT  78.444 127.457 78.75 128.237 ;
     RECT  84.924 127.229 85.302 128.237 ;
     RECT  90.072 127.373 91.242 128.237 ;
     RECT  91.98 127.265 91.998 128.237 ;
     RECT  92.736 127.265 93.402 128.237 ;
     RECT  94.14 127.457 94.158 128.237 ;
     RECT  96.444 127.265 96.462 128.237 ;
     RECT  98.064 127.301 101.25 128.237 ;
     RECT  30.42 128.237 30.762 128.285 ;
     RECT  5.688 128.237 5.706 128.813 ;
     RECT  53.568 128.237 53.586 128.813 ;
     RECT  32.976 128.237 32.994 128.861 ;
     RECT  56.556 128.237 56.79 128.861 ;
     RECT  100.584 128.237 101.25 128.861 ;
     RECT  105.912 127.229 106.614 128.861 ;
     RECT  82.08 127.301 83.826 129.245 ;
     RECT  28.548 127.409 28.674 129.437 ;
     RECT  86.652 127.409 87.246 129.437 ;
     RECT  98.064 128.237 99.522 129.437 ;
     RECT  2.34 128.237 3.078 129.485 ;
     RECT  9.468 128.237 9.486 129.485 ;
     RECT  14.652 127.709 14.67 129.485 ;
     RECT  16.092 127.709 16.11 129.485 ;
     RECT  19.008 128.237 19.026 129.485 ;
     RECT  21.456 127.409 21.474 129.485 ;
     RECT  24.552 128.237 24.57 129.485 ;
     RECT  25.56 128.237 25.578 129.485 ;
     RECT  28.548 129.437 28.566 129.485 ;
     RECT  30.42 128.285 30.438 129.485 ;
     RECT  32.04 128.237 32.058 129.485 ;
     RECT  34.38 128.237 34.398 129.485 ;
     RECT  35.28 128.237 35.298 129.485 ;
     RECT  36.72 127.301 36.738 129.485 ;
     RECT  42.84 128.237 42.858 129.485 ;
     RECT  45.972 128.237 45.99 129.485 ;
     RECT  51.372 127.709 51.39 129.485 ;
     RECT  52.128 127.709 52.146 129.485 ;
     RECT  55.476 127.409 55.494 129.485 ;
     RECT  56.556 128.861 56.574 129.485 ;
     RECT  58.716 128.237 58.734 129.485 ;
     RECT  59.688 128.237 59.706 129.485 ;
     RECT  61.74 128.237 61.758 129.485 ;
     RECT  68.724 127.409 68.742 129.485 ;
     RECT  69.552 128.237 69.57 129.485 ;
     RECT  71.316 128.237 71.334 129.485 ;
     RECT  76.392 128.237 76.41 129.485 ;
     RECT  78.444 128.237 78.462 129.485 ;
     RECT  79.812 127.409 81.018 129.485 ;
     RECT  82.08 129.245 82.494 129.485 ;
     RECT  83.808 129.245 83.826 129.485 ;
     RECT  84.924 128.237 84.942 129.485 ;
     RECT  86.652 129.437 86.67 129.485 ;
     RECT  88.092 127.373 88.974 129.485 ;
     RECT  90.072 128.237 90.09 129.485 ;
     RECT  91.224 128.237 91.242 129.485 ;
     RECT  95.184 127.265 95.598 129.485 ;
     RECT  97.272 127.265 97.29 129.485 ;
     RECT  98.064 129.437 98.082 129.485 ;
     RECT  99.504 129.437 99.522 129.485 ;
     RECT  101.232 128.861 101.25 129.485 ;
     RECT  104.04 127.457 104.598 129.485 ;
     RECT  105.912 128.861 105.93 129.485 ;
    LAYER M4 ;
     RECT  0.025 2.256 0.06 2.28 ;
     RECT  0.133 40.608 0.569 41.4 ;
     RECT  1.237 0.096 1.765 0.12 ;
     RECT  1.333 129.456 2.101 129.48 ;
     RECT  1.765 0.096 2.293 0.168 ;
     RECT  2.329 3.936 2.408 3.96 ;
     RECT  0.569 41.376 2.408 41.4 ;
     RECT  2.293 66.096 2.408 66.12 ;
     RECT  2.293 67.248 2.408 67.272 ;
     RECT  2.365 68.928 2.408 69.624 ;
     RECT  2.329 114.576 2.408 114.6 ;
     RECT  2.365 126 2.408 126.024 ;
     RECT  2.408 2.148 2.512 127.452 ;
     RECT  2.512 2.418 2.704 127.182 ;
     RECT  2.101 129.408 2.765 129.48 ;
     RECT  2.704 68.928 2.819 70.968 ;
     RECT  2.293 0.096 2.821 0.216 ;
     RECT  2.704 67.68 2.867 67.704 ;
     RECT  2.704 98.64 2.909 98.664 ;
     RECT  2.704 54.144 2.981 54.168 ;
     RECT  2.704 125.376 2.981 126.024 ;
     RECT  2.765 129.456 3.089 129.48 ;
     RECT  2.821 0.096 3.233 0.552 ;
     RECT  3.233 0.096 3.305 0.216 ;
     RECT  2.704 66.048 3.449 66.072 ;
     RECT  2.819 69.84 3.491 70.968 ;
     RECT  2.704 114.576 3.491 114.6 ;
     RECT  2.704 41.376 3.529 42.216 ;
     RECT  2.704 79.2 3.587 80.232 ;
     RECT  2.704 104.736 3.587 104.76 ;
     RECT  3.587 80.16 3.628 80.232 ;
     RECT  2.704 3.936 3.635 4.728 ;
     RECT  3.685 87.408 3.697 87.432 ;
     RECT  2.704 88.944 3.731 88.968 ;
     RECT  2.704 73.44 3.733 74.04 ;
     RECT  2.704 13.776 3.765 13.8 ;
     RECT  3.697 87.216 3.772 87.432 ;
     RECT  3.733 73.44 3.773 74.52 ;
     RECT  2.704 35.28 3.779 35.304 ;
     RECT  3.491 70.944 3.779 70.968 ;
     RECT  3.772 87.216 3.781 87.24 ;
     RECT  3.491 69.84 3.797 69.864 ;
     RECT  2.704 21.648 3.801 21.672 ;
     RECT  3.797 68.976 3.881 69.864 ;
     RECT  3.829 67.776 3.916 67.8 ;
     RECT  3.773 73.776 4.097 74.52 ;
     RECT  3.635 3.936 4.124 4.536 ;
     RECT  4.124 3.696 4.211 4.536 ;
     RECT  4.129 111.744 4.213 111.768 ;
     RECT  2.981 125.376 4.241 125.4 ;
     RECT  3.913 29.616 4.273 29.64 ;
     RECT  3.305 0.096 4.405 0.12 ;
     RECT  4.211 4.512 4.499 4.536 ;
     RECT  4.412 19.92 4.499 19.944 ;
     RECT  4.309 71.808 4.499 71.832 ;
     RECT  4.489 95.568 4.501 95.592 ;
     RECT  4.097 73.776 4.54 74.088 ;
     RECT  4.46 98.88 4.547 98.904 ;
     RECT  4.223 102.384 4.547 102.408 ;
     RECT  4.54 74.016 4.573 74.088 ;
     RECT  2.704 15.984 4.597 16.584 ;
     RECT  4.501 94.656 4.601 95.592 ;
     RECT  4.165 110.544 4.601 110.568 ;
     RECT  4.556 11.952 4.643 11.976 ;
     RECT  4.453 44.352 4.643 44.376 ;
     RECT  4.556 50.016 4.643 50.04 ;
     RECT  4.345 57.6 4.643 57.624 ;
     RECT  4.381 28.32 4.693 28.344 ;
     RECT  4.273 29.616 4.701 29.688 ;
     RECT  4.701 29.664 4.739 29.688 ;
     RECT  4.693 28.32 4.78 28.44 ;
     RECT  4.405 0.096 4.781 0.168 ;
     RECT  4.7 6.24 4.787 6.264 ;
     RECT  4.489 83.136 4.789 83.16 ;
     RECT  3.628 80.208 4.835 80.232 ;
     RECT  4.789 82.656 4.837 83.16 ;
     RECT  4.597 8.304 4.853 8.328 ;
     RECT  4.501 96.864 4.853 96.888 ;
     RECT  4.837 82.656 4.889 83.208 ;
     RECT  4.889 83.136 4.924 83.208 ;
     RECT  4.561 125.04 5.132 125.352 ;
     RECT  5.125 121.536 5.137 121.56 ;
     RECT  4.561 120.24 5.171 120.264 ;
     RECT  3.541 128.208 5.177 128.232 ;
     RECT  5.137 121.536 5.212 121.992 ;
     RECT  5.132 124.512 5.219 125.352 ;
     RECT  5.212 121.968 5.221 121.992 ;
     RECT  4.993 30.96 5.317 30.984 ;
     RECT  5.281 113.424 5.365 113.448 ;
     RECT  4.268 27.312 5.413 27.336 ;
     RECT  5.317 30.96 5.459 31.08 ;
     RECT  4.597 15.84 5.507 16.584 ;
     RECT  5.459 31.056 5.507 31.08 ;
     RECT  5.42 38.4 5.507 38.424 ;
     RECT  4.777 52.176 5.507 52.2 ;
     RECT  5.281 54 5.507 54.024 ;
     RECT  5.256 106.032 5.555 106.056 ;
     RECT  5.245 89.424 5.564 89.448 ;
     RECT  5.413 27.216 5.603 27.336 ;
     RECT  4.601 95.568 5.605 95.592 ;
     RECT  4.924 83.136 5.651 83.16 ;
     RECT  5.564 89.376 5.651 89.448 ;
     RECT  5.603 27.312 5.664 27.336 ;
     RECT  5.219 125.04 5.713 125.352 ;
     RECT  4.78 28.32 5.749 28.344 ;
     RECT  5.708 36.672 5.795 36.696 ;
     RECT  5.677 128.784 5.795 128.808 ;
     RECT  5.749 46.704 5.891 46.728 ;
     RECT  5.605 95.184 6.041 95.592 ;
     RECT  6.029 75.264 6.044 75.288 ;
     RECT  5.996 61.776 6.083 61.8 ;
     RECT  6.044 75.264 6.113 75.576 ;
     RECT  5.845 48.24 6.131 48.264 ;
     RECT  5.713 59.28 6.131 59.304 ;
     RECT  6.113 75.552 6.131 75.576 ;
     RECT  5.468 91.488 6.179 91.512 ;
     RECT  5.641 3.936 6.236 3.96 ;
     RECT  4.837 86.64 6.275 86.664 ;
     RECT  6.041 95.568 6.277 95.592 ;
     RECT  6.236 3.936 6.293 4.536 ;
     RECT  5.713 125.04 6.293 126.024 ;
     RECT  6.236 25.392 6.323 25.416 ;
     RECT  6.277 95.568 6.323 95.784 ;
     RECT  5.749 28.32 6.365 28.872 ;
     RECT  6.325 17.616 6.419 17.64 ;
     RECT  5.209 81.552 6.505 81.576 ;
     RECT  6.085 77.712 6.515 77.736 ;
     RECT  6.229 85.344 6.563 85.368 ;
     RECT  6.505 81.552 6.576 82.056 ;
     RECT  6.576 82.032 6.589 82.056 ;
     RECT  6.365 28.32 6.833 28.68 ;
     RECT  6.293 125.04 7.381 125.64 ;
     RECT  6.333 23.328 7.477 23.352 ;
     RECT  6.323 95.76 7.669 95.784 ;
     RECT  7.621 1.344 7.808 1.368 ;
     RECT  6.293 4.512 7.808 4.536 ;
     RECT  6.613 10.608 7.808 10.632 ;
     RECT  5.507 16.56 7.808 16.584 ;
     RECT  7.477 23.136 7.808 23.352 ;
     RECT  6.833 28.416 7.808 28.68 ;
     RECT  3.529 41.376 7.808 41.4 ;
     RECT  7.657 55.968 7.808 55.992 ;
     RECT  6.217 57.84 7.808 57.864 ;
     RECT  7.189 63.792 7.808 63.816 ;
     RECT  4.597 70.8 7.808 70.824 ;
     RECT  4.573 74.016 7.808 74.04 ;
     RECT  7.103 83.184 7.808 83.208 ;
     RECT  5.651 89.424 7.808 89.448 ;
     RECT  7.141 93.216 7.808 93.24 ;
     RECT  7.669 95.76 7.808 96.216 ;
     RECT  7.369 99.024 7.808 99.048 ;
     RECT  7.285 100.8 7.808 100.824 ;
     RECT  7.244 108.48 7.808 108.504 ;
     RECT  6.577 117.408 7.808 117.432 ;
     RECT  7.153 123.648 7.808 123.672 ;
     RECT  7.381 125.04 7.808 125.736 ;
     RECT  6.517 128.208 7.808 128.232 ;
     RECT  7.808 1.344 7.912 128.232 ;
     RECT  7.912 2.418 8.104 127.182 ;
     RECT  7.912 1.344 8.165 1.368 ;
     RECT  8.104 16.56 8.243 16.584 ;
     RECT  8.104 55.968 8.243 55.992 ;
     RECT  8.104 9.696 8.245 10.824 ;
     RECT  8.104 93.216 8.309 93.24 ;
     RECT  8.104 23.136 8.387 23.352 ;
     RECT  8.104 33.216 8.387 33.24 ;
     RECT  8.104 40.848 8.387 41.4 ;
     RECT  8.245 9.696 8.533 10.632 ;
     RECT  8.387 23.136 8.597 23.208 ;
     RECT  4.781 0.096 8.677 0.12 ;
     RECT  8.104 3.984 8.741 5.064 ;
     RECT  8.104 89.424 8.771 89.448 ;
     RECT  8.104 107.52 8.812 107.736 ;
     RECT  8.677 0.096 9.209 0.168 ;
     RECT  9.164 100.752 9.251 100.776 ;
     RECT  8.725 129.456 9.497 129.48 ;
     RECT  9.205 1.152 9.713 1.176 ;
     RECT  8.104 124.848 9.821 125.976 ;
     RECT  8.741 5.04 9.929 5.064 ;
     RECT  9.209 0.096 9.965 0.12 ;
     RECT  8.104 74.016 10.133 74.04 ;
     RECT  8.597 23.136 10.213 23.16 ;
     RECT  10.133 74.016 10.217 74.664 ;
     RECT  10.261 0.576 10.361 0.6 ;
     RECT  8.741 3.984 10.645 4.008 ;
     RECT  10.213 23.136 10.748 23.304 ;
     RECT  10.748 23.136 10.829 23.352 ;
     RECT  10.829 23.28 10.835 23.352 ;
     RECT  10.781 1.152 10.901 1.176 ;
     RECT  10.645 3.984 11.225 4.248 ;
     RECT  9.821 124.848 11.413 125.112 ;
     RECT  11.317 0.096 11.441 0.12 ;
     RECT  11.413 124.848 11.549 125.64 ;
     RECT  11.797 0.528 11.891 0.552 ;
     RECT  11.549 125.616 11.905 125.64 ;
     RECT  8.104 28.416 11.989 28.68 ;
     RECT  11.905 125.616 12.193 125.976 ;
     RECT  12.373 0.576 12.457 0.6 ;
     RECT  11.257 7.248 12.517 7.272 ;
     RECT  11.473 3.6 12.589 3.624 ;
     RECT  7.912 128.208 12.593 128.232 ;
     RECT  12.589 3.6 12.805 4.152 ;
     RECT  12.805 3.6 13.129 4.248 ;
     RECT  13.129 3.6 13.208 4.44 ;
     RECT  12.517 7.248 13.208 7.368 ;
     RECT  8.533 10.608 13.208 10.632 ;
     RECT  10.835 23.28 13.208 23.304 ;
     RECT  10.789 26.64 13.208 26.664 ;
     RECT  11.989 27.888 13.208 28.68 ;
     RECT  8.387 41.376 13.208 41.4 ;
     RECT  8.104 57.84 13.208 57.864 ;
     RECT  8.104 70.8 13.208 70.824 ;
     RECT  9.133 72.432 13.208 72.456 ;
     RECT  10.217 74.016 13.208 74.04 ;
     RECT  9.277 77.808 13.208 77.832 ;
     RECT  10.681 79.776 13.208 79.8 ;
     RECT  10.165 95.616 13.208 95.64 ;
     RECT  9.205 103.488 13.208 103.512 ;
     RECT  8.812 107.52 13.208 107.544 ;
     RECT  12.193 125.616 13.208 126.456 ;
     RECT  13.141 127.68 13.208 127.704 ;
     RECT  13.208 2.148 13.312 127.704 ;
     RECT  13.312 2.418 13.504 127.704 ;
     RECT  13.429 1.344 13.781 1.368 ;
     RECT  13.861 129.456 14.681 129.48 ;
     RECT  13.504 74.016 14.821 74.04 ;
     RECT  13.504 41.376 14.857 41.4 ;
     RECT  13.504 27.888 14.861 28.68 ;
     RECT  14.821 73.872 14.861 74.04 ;
     RECT  13.504 3.936 14.933 6.312 ;
     RECT  13.504 127.68 15.473 127.704 ;
     RECT  12.901 0.096 15.617 0.12 ;
     RECT  14.933 3.936 15.649 5.064 ;
     RECT  13.504 125.616 16.045 126.168 ;
     RECT  16.037 129.456 16.121 129.48 ;
     RECT  15.649 3.696 16.189 5.064 ;
     RECT  16.069 0.576 16.301 0.6 ;
     RECT  16.045 124.848 16.441 126.168 ;
     RECT  16.189 3.696 16.981 5.112 ;
     RECT  16.597 1.152 17.129 1.176 ;
     RECT  16.981 3.696 17.269 5.208 ;
     RECT  14.933 6.288 17.269 6.312 ;
     RECT  17.125 0.096 17.653 0.12 ;
     RECT  17.653 0.096 17.741 0.6 ;
     RECT  17.741 0.576 18.253 0.6 ;
     RECT  16.789 128.208 18.361 128.232 ;
     RECT  16.441 124.272 18.529 126.168 ;
     RECT  17.269 3.696 18.608 6.312 ;
     RECT  13.504 7.344 18.608 7.368 ;
     RECT  13.504 23.28 18.608 23.304 ;
     RECT  13.504 26.64 18.608 26.664 ;
     RECT  14.861 27.888 18.608 28.536 ;
     RECT  14.857 40.56 18.608 41.4 ;
     RECT  15.205 52.464 18.608 52.488 ;
     RECT  13.504 57.84 18.608 57.864 ;
     RECT  13.504 70.8 18.608 70.824 ;
     RECT  13.504 72.432 18.608 72.456 ;
     RECT  14.861 73.872 18.608 73.896 ;
     RECT  13.504 77.808 18.608 77.832 ;
     RECT  13.504 79.776 18.608 79.8 ;
     RECT  13.504 95.616 18.608 95.64 ;
     RECT  15.145 99.024 18.608 99.048 ;
     RECT  13.504 103.488 18.608 103.512 ;
     RECT  13.504 107.52 18.608 107.544 ;
     RECT  18.529 124.08 18.608 126.168 ;
     RECT  18.608 2.148 18.712 127.452 ;
     RECT  18.712 2.418 18.904 127.182 ;
     RECT  18.709 1.152 19.001 1.176 ;
     RECT  18.904 95.712 19.081 95.736 ;
     RECT  18.997 129.456 19.081 129.48 ;
     RECT  18.904 3.696 19.109 7.368 ;
     RECT  19.244 0.528 19.331 0.552 ;
     RECT  18.904 52.896 19.331 52.92 ;
     RECT  18.904 73.872 19.331 73.896 ;
     RECT  18.904 26.64 19.427 28.536 ;
     RECT  19.427 26.64 19.433 27.912 ;
     RECT  19.109 4.32 20.003 7.368 ;
     RECT  20.003 4.32 20.437 7.224 ;
     RECT  20.437 3.6 20.473 7.224 ;
     RECT  19.765 128.208 20.531 128.232 ;
     RECT  18.904 123.504 20.585 126.168 ;
     RECT  19.433 26.64 20.981 27.336 ;
     RECT  20.585 123.504 20.981 125.928 ;
     RECT  20.981 123.6 21.017 125.928 ;
     RECT  20.473 3.456 21.155 7.224 ;
     RECT  20.869 1.152 21.161 1.176 ;
     RECT  18.904 79.776 21.409 79.8 ;
     RECT  21.205 129.456 21.485 129.48 ;
     RECT  21.409 79.776 21.635 80.424 ;
     RECT  18.904 72.432 21.685 72.456 ;
     RECT  18.904 77.808 21.693 77.832 ;
     RECT  21.685 72.432 21.731 72.6 ;
     RECT  21.731 72.576 21.923 72.6 ;
     RECT  21.155 3.456 21.949 6.84 ;
     RECT  18.904 70.8 22.133 70.824 ;
     RECT  21.017 124.08 22.165 125.928 ;
     RECT  21.635 79.776 22.307 79.8 ;
     RECT  22.165 123.744 22.417 125.928 ;
     RECT  21.653 80.928 22.451 81.048 ;
     RECT  21.949 3.408 22.453 6.84 ;
     RECT  22.453 71.232 22.537 71.256 ;
     RECT  19.781 0.096 22.565 0.12 ;
     RECT  22.451 80.928 22.609 80.952 ;
     RECT  22.417 123.744 22.849 126.456 ;
     RECT  22.453 3.408 22.889 7.368 ;
     RECT  22.849 123.744 22.889 126.552 ;
     RECT  22.889 123.792 22.961 126.552 ;
     RECT  22.961 124.032 22.997 126.552 ;
     RECT  21.877 42.816 23.641 42.84 ;
     RECT  22.889 3.408 23.797 5.496 ;
     RECT  21.973 128.208 23.969 128.232 ;
     RECT  22.981 1.152 24.005 1.176 ;
     RECT  23.797 3.36 24.008 5.496 ;
     RECT  22.889 6.528 24.008 7.368 ;
     RECT  18.904 23.28 24.008 23.304 ;
     RECT  20.981 26.64 24.008 27.096 ;
     RECT  18.904 31.872 24.008 31.896 ;
     RECT  18.904 40.56 24.008 41.4 ;
     RECT  23.641 42.72 24.008 42.84 ;
     RECT  18.904 57.84 24.008 57.864 ;
     RECT  18.904 99.024 24.008 99.048 ;
     RECT  18.904 103.488 24.008 103.512 ;
     RECT  18.904 107.52 24.008 107.544 ;
     RECT  22.997 124.032 24.008 126.456 ;
     RECT  24.008 2.148 24.112 127.452 ;
     RECT  24.112 2.418 24.304 127.182 ;
     RECT  24.304 123.984 24.437 126.168 ;
     RECT  24.037 0.096 24.617 0.12 ;
     RECT  24.304 3.696 24.659 7.368 ;
     RECT  24.304 25.488 24.851 25.608 ;
     RECT  24.304 51.216 25.091 51.24 ;
     RECT  24.304 57.84 25.091 57.864 ;
     RECT  25.093 0.576 25.301 0.6 ;
     RECT  24.437 124.032 25.405 126.168 ;
     RECT  24.181 129.456 25.589 129.48 ;
     RECT  25.621 1.152 25.733 1.176 ;
     RECT  24.304 109.968 26.197 109.992 ;
     RECT  24.304 107.52 26.243 107.544 ;
     RECT  25.405 124.032 26.243 127.032 ;
     RECT  24.659 3.696 26.341 5.496 ;
     RECT  26.197 109.92 26.483 109.992 ;
     RECT  26.341 3.408 26.813 5.496 ;
     RECT  26.149 0.096 26.885 0.12 ;
     RECT  24.304 42.72 27.025 42.84 ;
     RECT  25.613 128.208 27.173 128.232 ;
     RECT  26.243 124.512 27.245 127.032 ;
     RECT  27.205 1.152 27.461 1.176 ;
     RECT  27.245 124.512 27.533 126.024 ;
     RECT  27.385 50.352 27.701 50.376 ;
     RECT  24.304 40.56 27.779 41.4 ;
     RECT  27.701 50.352 27.785 50.712 ;
     RECT  26.773 123.168 27.785 123.192 ;
     RECT  26.917 20.928 27.925 20.952 ;
     RECT  27.533 124.56 27.965 126.024 ;
     RECT  24.304 23.28 27.971 23.304 ;
     RECT  27.701 0.576 28.397 0.6 ;
     RECT  27.829 129.456 28.576 129.48 ;
     RECT  28.576 129.408 28.577 129.48 ;
     RECT  28.577 129.408 28.685 129.432 ;
     RECT  28.748 0.528 28.835 0.552 ;
     RECT  26.813 3.6 29.149 5.496 ;
     RECT  29.317 0.096 29.405 0.12 ;
     RECT  29.149 3.36 29.408 5.496 ;
     RECT  24.659 6.528 29.408 6.552 ;
     RECT  28.453 18.96 29.408 18.984 ;
     RECT  27.925 20.784 29.408 20.952 ;
     RECT  24.851 25.488 29.408 25.512 ;
     RECT  24.304 26.64 29.408 27.096 ;
     RECT  24.304 31.872 29.408 31.896 ;
     RECT  27.779 41.376 29.408 41.4 ;
     RECT  27.025 42.72 29.408 43.416 ;
     RECT  27.785 50.352 29.408 50.376 ;
     RECT  27.733 61.152 29.408 61.176 ;
     RECT  24.304 99.024 29.408 99.048 ;
     RECT  24.304 103.488 29.408 103.512 ;
     RECT  26.483 109.968 29.408 109.992 ;
     RECT  26.437 112.128 29.408 112.152 ;
     RECT  27.965 124.56 29.408 125.928 ;
     RECT  27.245 127.008 29.408 127.032 ;
     RECT  29.317 128.208 29.408 128.232 ;
     RECT  29.408 2.148 29.512 128.232 ;
     RECT  29.512 2.418 29.704 127.182 ;
     RECT  29.512 128.208 29.765 128.232 ;
     RECT  29.704 2.832 30.089 5.496 ;
     RECT  29.704 124.56 30.233 126.504 ;
     RECT  29.845 0.576 30.449 0.6 ;
     RECT  30.037 129.456 30.449 129.48 ;
     RECT  30.089 3.36 30.701 5.496 ;
     RECT  29.704 20.928 30.733 20.952 ;
     RECT  29.704 50.352 30.733 50.376 ;
     RECT  30.733 20.832 30.773 20.952 ;
     RECT  30.733 50.256 30.773 50.376 ;
     RECT  29.704 41.376 30.841 43.416 ;
     RECT  30.733 128.256 30.851 128.28 ;
     RECT  30.701 3.408 30.881 5.496 ;
     RECT  30.901 0.096 31.565 0.12 ;
     RECT  30.881 3.456 31.745 5.496 ;
     RECT  31.597 10.368 31.957 10.392 ;
     RECT  29.704 6.528 32.003 6.552 ;
     RECT  31.745 5.472 32.033 5.496 ;
     RECT  31.957 10.368 32.041 10.824 ;
     RECT  31.985 0.576 32.069 0.6 ;
     RECT  29.704 26.64 32.069 27.096 ;
     RECT  31.525 129.456 32.069 129.48 ;
     RECT  29.704 61.056 32.245 61.08 ;
     RECT  32.204 45.312 32.291 45.336 ;
     RECT  29.704 31.872 32.393 31.896 ;
     RECT  32.245 128.208 32.465 128.232 ;
     RECT  30.841 41.376 32.789 43.608 ;
     RECT  32.069 27.072 32.897 27.096 ;
     RECT  32.533 0.096 33.037 0.12 ;
     RECT  32.972 29.04 33.059 29.064 ;
     RECT  32.581 45.12 33.059 45.144 ;
     RECT  32.965 128.832 33.059 128.856 ;
     RECT  33.037 0.096 33.121 0.6 ;
     RECT  33.181 34.752 33.265 34.776 ;
     RECT  30.773 20.832 33.289 20.856 ;
     RECT  33.289 20.112 33.617 20.856 ;
     RECT  33.577 30 33.683 30.024 ;
     RECT  31.745 3.456 34.045 4.488 ;
     RECT  30.233 124.56 34.117 125.88 ;
     RECT  33.637 31.248 34.189 31.272 ;
     RECT  33.649 32.352 34.189 32.376 ;
     RECT  32.789 42.24 34.261 43.608 ;
     RECT  34.261 41.904 34.268 43.608 ;
     RECT  34.045 3.456 34.297 4.632 ;
     RECT  32.041 10.368 34.309 10.392 ;
     RECT  33.205 72.144 34.309 72.168 ;
     RECT  33.637 28.608 34.441 28.632 ;
     RECT  34.441 128.208 34.525 128.232 ;
     RECT  34.441 27.936 34.657 28.632 ;
     RECT  29.704 18.96 34.693 18.984 ;
     RECT  34.657 27.936 34.728 29.352 ;
     RECT  34.225 45.024 34.729 45.048 ;
     RECT  34.477 26.592 34.765 26.616 ;
     RECT  34.297 3.168 34.808 4.632 ;
     RECT  34.309 10.32 34.808 10.392 ;
     RECT  31.957 14.112 34.808 14.136 ;
     RECT  34.693 18.96 34.808 19.032 ;
     RECT  33.617 20.112 34.808 20.712 ;
     RECT  34.621 22.032 34.808 22.056 ;
     RECT  29.704 25.488 34.808 25.512 ;
     RECT  34.765 26.592 34.808 26.904 ;
     RECT  34.728 27.888 34.808 29.352 ;
     RECT  34.189 31.248 34.808 32.376 ;
     RECT  34.22 33.456 34.808 33.48 ;
     RECT  34.652 34.752 34.808 34.776 ;
     RECT  33.937 37.44 34.808 37.464 ;
     RECT  33.793 40.224 34.808 40.248 ;
     RECT  34.268 41.328 34.808 43.608 ;
     RECT  34.729 45.024 34.808 45.288 ;
     RECT  30.773 50.256 34.808 50.28 ;
     RECT  32.245 61.056 34.808 61.128 ;
     RECT  32.581 68.64 34.808 68.664 ;
     RECT  34.309 72 34.808 72.168 ;
     RECT  29.704 99.024 34.808 99.048 ;
     RECT  29.704 103.488 34.808 103.512 ;
     RECT  29.704 109.968 34.808 109.992 ;
     RECT  29.704 112.128 34.808 112.152 ;
     RECT  34.117 124.56 34.808 125.928 ;
     RECT  34.808 2.148 34.912 127.452 ;
     RECT  33.121 0.096 34.985 0.12 ;
     RECT  34.912 2.418 35.104 127.182 ;
     RECT  35.104 18.72 35.219 23.976 ;
     RECT  35.104 25.296 35.219 30.744 ;
     RECT  35.104 47.856 35.219 47.88 ;
     RECT  35.104 48.96 35.219 48.984 ;
     RECT  35.104 50.832 35.219 50.856 ;
     RECT  35.219 22.176 35.267 23.976 ;
     RECT  35.219 28.416 35.267 30.744 ;
     RECT  33.733 129.456 35.309 129.48 ;
     RECT  35.104 3.12 35.315 4.536 ;
     RECT  35.104 17.616 35.315 17.64 ;
     RECT  35.267 22.176 35.315 23.16 ;
     RECT  35.267 29.328 35.315 30.744 ;
     RECT  35.104 31.776 35.315 32.616 ;
     RECT  35.104 33.648 35.315 34.392 ;
     RECT  35.104 37.248 35.315 38.424 ;
     RECT  35.315 30.72 35.353 30.744 ;
     RECT  35.315 22.176 35.363 22.824 ;
     RECT  35.219 25.296 35.363 25.512 ;
     RECT  35.219 26.592 35.363 26.712 ;
     RECT  35.161 0.576 35.785 0.6 ;
     RECT  35.219 18.72 35.932 21.144 ;
     RECT  35.909 128.208 35.993 128.232 ;
     RECT  35.104 42.24 36.241 43.608 ;
     RECT  35.104 45.168 36.241 46.488 ;
     RECT  36.188 0.528 36.275 0.552 ;
     RECT  35.315 31.776 36.421 32.472 ;
     RECT  36.421 31.488 36.457 32.472 ;
     RECT  35.315 34.368 36.457 34.392 ;
     RECT  35.932 18.72 36.493 20.76 ;
     RECT  36.241 42.24 36.493 46.488 ;
     RECT  36.457 31.488 36.529 32.856 ;
     RECT  36.457 33.984 36.529 34.392 ;
     RECT  36.493 42.24 36.601 46.68 ;
     RECT  35.315 37.248 36.673 37.464 ;
     RECT  35.104 98.928 36.677 98.952 ;
     RECT  36.62 97.536 36.707 97.56 ;
     RECT  36.673 36.864 36.745 37.464 ;
     RECT  36.661 129.456 36.749 129.48 ;
     RECT  36.385 55.872 36.755 55.896 ;
     RECT  36.745 35.904 36.781 37.464 ;
     RECT  36.737 0.096 36.821 0.12 ;
     RECT  35.104 14.112 36.853 14.136 ;
     RECT  36.812 15.6 36.853 15.624 ;
     RECT  35.104 61.056 36.853 61.128 ;
     RECT  36.493 40.704 36.889 40.728 ;
     RECT  36.601 41.856 36.889 46.68 ;
     RECT  36.853 14.112 36.899 15.624 ;
     RECT  36.601 83.856 36.908 83.88 ;
     RECT  35.104 124.56 36.929 126.168 ;
     RECT  35.104 92.112 36.995 92.328 ;
     RECT  35.363 26.688 36.997 26.712 ;
     RECT  36.908 83.664 36.997 83.88 ;
     RECT  36.493 18.144 37.073 20.76 ;
     RECT  36.529 31.488 37.177 34.392 ;
     RECT  36.781 35.52 37.177 37.464 ;
     RECT  35.363 22.176 37.189 22.2 ;
     RECT  36.997 26.688 37.213 26.904 ;
     RECT  37.213 26.688 37.237 27.672 ;
     RECT  36.929 124.56 37.244 126.024 ;
     RECT  36.949 79.584 37.253 79.608 ;
     RECT  37.237 26.688 37.285 28.056 ;
     RECT  36.925 16.224 37.292 16.248 ;
     RECT  37.244 124.416 37.331 126.024 ;
     RECT  37.073 18.144 37.333 20.712 ;
     RECT  37.285 26.688 37.333 28.44 ;
     RECT  37.285 54.384 37.333 54.408 ;
     RECT  37.292 16.224 37.357 16.68 ;
     RECT  37.333 18 37.357 20.712 ;
     RECT  37.285 0.576 37.369 0.6 ;
     RECT  36.899 14.112 37.381 14.856 ;
     RECT  37.333 26.688 37.381 28.632 ;
     RECT  36.997 81.6 37.429 81.624 ;
     RECT  37.189 23.376 37.433 23.4 ;
     RECT  37.357 16.224 37.475 20.712 ;
     RECT  36.997 83.568 37.501 83.88 ;
     RECT  37.213 84.912 37.501 84.936 ;
     RECT  37.477 121.44 37.525 121.464 ;
     RECT  35.104 57.024 37.573 57.048 ;
     RECT  37.429 81.6 37.573 81.72 ;
     RECT  37.475 16.224 37.613 16.584 ;
     RECT  37.475 17.616 37.715 20.712 ;
     RECT  37.381 14.064 37.717 14.856 ;
     RECT  37.573 56.448 37.757 57.048 ;
     RECT  35.315 3.6 37.789 4.536 ;
     RECT  37.501 83.568 37.789 84.936 ;
     RECT  37.189 22.08 37.861 22.2 ;
     RECT  37.717 13.584 37.865 14.856 ;
     RECT  37.573 81.168 37.897 81.72 ;
     RECT  37.789 83.568 37.901 85.08 ;
     RECT  37.865 13.584 37.909 14.136 ;
     RECT  37.861 21.792 37.909 22.2 ;
     RECT  37.381 58.944 37.909 58.968 ;
     RECT  37.897 81.168 37.933 81.816 ;
     RECT  37.753 99.648 37.937 99.672 ;
     RECT  37.868 15.36 37.955 15.384 ;
     RECT  37.381 26.688 38.016 28.824 ;
     RECT  37.177 31.488 38.016 37.464 ;
     RECT  36.889 40.704 38.016 46.68 ;
     RECT  37.357 78.048 38.077 78.072 ;
     RECT  37.465 79.152 38.077 79.176 ;
     RECT  37.525 121.44 38.081 121.992 ;
     RECT  35.363 25.488 38.088 25.512 ;
     RECT  38.016 26.688 38.088 46.68 ;
     RECT  37.237 53.04 38.088 53.064 ;
     RECT  37.333 54.384 38.088 54.984 ;
     RECT  37.909 21.792 38.117 22.776 ;
     RECT  37.901 83.568 38.117 83.88 ;
     RECT  38.081 121.968 38.117 121.992 ;
     RECT  37.573 95.136 38.149 95.16 ;
     RECT  38.156 86.16 38.185 86.184 ;
     RECT  37.901 85.056 38.243 85.08 ;
     RECT  38.185 86.16 38.243 86.616 ;
     RECT  37.331 124.56 38.243 126.024 ;
     RECT  38.149 95.136 38.261 95.88 ;
     RECT  38.243 86.592 38.291 86.616 ;
     RECT  38.005 99.744 38.291 99.768 ;
     RECT  37.429 76.368 38.297 76.392 ;
     RECT  36.853 60.432 38.3 61.128 ;
     RECT  36.901 62.16 38.3 62.184 ;
     RECT  38.293 97.776 38.329 97.8 ;
     RECT  37.909 58.704 38.333 58.968 ;
     RECT  37.933 80.976 38.333 81.816 ;
     RECT  38.329 97.44 38.341 97.8 ;
     RECT  38.077 78.048 38.387 79.176 ;
     RECT  37.789 2.88 38.405 4.536 ;
     RECT  38.341 97.44 38.413 98.568 ;
     RECT  38.413 97.536 38.428 98.568 ;
     RECT  37.613 16.56 38.437 16.584 ;
     RECT  38.117 21.792 38.441 22.2 ;
     RECT  38.405 2.928 38.477 4.536 ;
     RECT  37.715 18 38.533 20.712 ;
     RECT  38.261 95.136 38.549 95.4 ;
     RECT  38.533 18 38.62 20.808 ;
     RECT  37.757 57.024 38.653 57.048 ;
     RECT  38.653 57.024 38.693 57.624 ;
     RECT  38.428 97.536 38.693 98.472 ;
     RECT  38.477 3.456 38.761 4.536 ;
     RECT  36.995 92.112 38.761 92.136 ;
     RECT  38.437 16.56 38.797 16.68 ;
     RECT  38.761 92.112 38.801 92.232 ;
     RECT  37.813 0.096 38.828 0.12 ;
     RECT  37.909 13.008 38.828 14.136 ;
     RECT  38.797 15.696 38.837 16.68 ;
     RECT  38.693 57.6 38.837 57.624 ;
     RECT  38.828 0.096 38.915 0.552 ;
     RECT  38.828 12.72 38.915 14.136 ;
     RECT  36.949 64.992 38.977 65.016 ;
     RECT  38.387 78.576 38.977 79.176 ;
     RECT  38.725 80.352 39.005 80.376 ;
     RECT  38.977 78.576 39.059 79.272 ;
     RECT  38.62 18 39.085 20.136 ;
     RECT  38.977 64.272 39.085 65.016 ;
     RECT  39.005 80.256 39.089 80.376 ;
     RECT  38.117 83.856 39.109 83.88 ;
     RECT  38.915 13.632 39.121 14.136 ;
     RECT  39.109 73.2 39.121 73.224 ;
     RECT  38.333 81.552 39.155 81.816 ;
     RECT  38.3 60.432 39.157 62.184 ;
     RECT  35.104 103.488 39.157 103.512 ;
     RECT  39.157 60.384 39.161 62.184 ;
     RECT  39.085 64.272 39.169 65.544 ;
     RECT  39.157 101.28 39.193 101.304 ;
     RECT  39.109 83.184 39.196 84.024 ;
     RECT  39.196 83.184 39.197 83.208 ;
     RECT  39.169 64.272 39.203 65.112 ;
     RECT  39.089 80.352 39.203 80.376 ;
     RECT  38.905 108.288 39.203 108.312 ;
     RECT  38.693 97.632 39.233 97.656 ;
     RECT  38.833 94.512 39.241 94.584 ;
     RECT  39.121 73.2 39.301 73.368 ;
     RECT  39.155 81.648 39.301 81.816 ;
     RECT  38.441 21.792 39.329 21.912 ;
     RECT  39.193 100.992 39.337 101.304 ;
     RECT  38.333 58.944 39.409 58.968 ;
     RECT  39.329 21.12 39.445 21.912 ;
     RECT  38.915 0.096 39.449 0.12 ;
     RECT  39.121 13.632 39.541 14.712 ;
     RECT  38.837 15.696 39.541 15.72 ;
     RECT  35.104 72 39.553 72.168 ;
     RECT  39.301 73.2 39.553 73.512 ;
     RECT  39.157 99.792 39.589 99.816 ;
     RECT  39.337 100.992 39.589 101.736 ;
     RECT  39.157 103.056 39.589 103.512 ;
     RECT  38.761 3.456 39.769 4.584 ;
     RECT  39.589 99.792 39.805 101.736 ;
     RECT  39.589 102.816 39.805 103.512 ;
     RECT  39.085 17.04 39.912 20.136 ;
     RECT  39.481 98.64 39.913 98.664 ;
     RECT  39.509 12.528 39.932 12.552 ;
     RECT  39.541 13.632 39.932 15.72 ;
     RECT  39.349 56.112 39.949 56.136 ;
     RECT  39.912 16.8 39.973 20.136 ;
     RECT  39.445 21.12 39.973 22.2 ;
     RECT  39.913 0.576 39.997 0.6 ;
     RECT  35.104 112.128 40.028 112.152 ;
     RECT  39.553 72 40.069 73.512 ;
     RECT  39.769 3.36 40.208 4.584 ;
     RECT  35.104 10.32 40.208 10.392 ;
     RECT  39.932 12.528 40.208 15.72 ;
     RECT  39.973 16.8 40.208 22.2 ;
     RECT  39.308 23.328 40.208 23.352 ;
     RECT  38.088 25.488 40.208 54.984 ;
     RECT  39.949 56.112 40.208 57.048 ;
     RECT  39.409 58.704 40.208 58.968 ;
     RECT  39.161 60.384 40.208 61.896 ;
     RECT  39.203 64.992 40.208 65.016 ;
     RECT  39.445 67.44 40.208 67.464 ;
     RECT  35.104 68.64 40.208 68.664 ;
     RECT  40.069 71.424 40.208 73.512 ;
     RECT  40.049 75.264 40.208 75.288 ;
     RECT  39.373 76.368 40.208 76.392 ;
     RECT  39.059 78.96 40.208 79.272 ;
     RECT  39.445 80.496 40.208 80.52 ;
     RECT  39.301 81.648 40.208 82.056 ;
     RECT  38.801 92.208 40.208 92.232 ;
     RECT  39.241 94.512 40.208 94.536 ;
     RECT  39.913 98.544 40.208 98.664 ;
     RECT  39.805 99.792 40.208 103.512 ;
     RECT  35.104 109.968 40.208 109.992 ;
     RECT  40.028 112.128 40.208 112.296 ;
     RECT  38.243 124.56 40.208 125.928 ;
     RECT  37.429 128.208 40.208 128.232 ;
     RECT  40.208 2.148 40.312 23.772 ;
     RECT  40.208 25.488 40.312 128.232 ;
     RECT  40.312 2.418 40.504 23.502 ;
     RECT  40.312 25.488 40.504 127.182 ;
     RECT  40.453 0.096 40.565 0.12 ;
     RECT  40.504 20.304 40.565 22.776 ;
     RECT  40.504 12.336 40.643 19.128 ;
     RECT  40.504 92.208 40.643 92.232 ;
     RECT  40.504 108.72 40.643 108.744 ;
     RECT  40.643 14.112 40.691 19.128 ;
     RECT  40.565 20.352 40.691 22.776 ;
     RECT  40.504 102.624 40.745 103.512 ;
     RECT  40.504 60.672 40.781 63.144 ;
     RECT  40.691 20.352 40.787 22.632 ;
     RECT  40.745 102.672 40.889 103.512 ;
     RECT  40.643 12.336 41.075 12.936 ;
     RECT  40.504 83.616 41.177 83.64 ;
     RECT  40.781 60.672 41.219 61.128 ;
     RECT  40.504 65.328 41.315 65.352 ;
     RECT  40.781 62.112 41.321 63.144 ;
     RECT  41.321 62.4 41.356 63.144 ;
     RECT  41.356 62.4 41.411 63 ;
     RECT  41.219 60.96 41.437 61.128 ;
     RECT  40.504 66.48 41.452 68.664 ;
     RECT  40.504 76.464 41.465 76.728 ;
     RECT  41.452 66.672 41.473 68.664 ;
     RECT  41.473 67.536 41.507 68.664 ;
     RECT  40.504 98.064 41.507 98.088 ;
     RECT  40.504 58.656 41.545 59.304 ;
     RECT  40.691 14.112 41.644 18.792 ;
     RECT  41.545 58.656 41.651 58.968 ;
     RECT  40.787 20.544 41.717 22.632 ;
     RECT  40.504 3.6 41.785 4.488 ;
     RECT  40.981 1.152 41.789 1.176 ;
     RECT  41.465 76.464 41.829 76.488 ;
     RECT  41.756 77.712 41.843 77.736 ;
     RECT  41.797 81.504 41.897 81.528 ;
     RECT  40.312 128.208 41.897 128.232 ;
     RECT  40.504 78.768 41.941 79.272 ;
     RECT  41.829 75.552 41.987 76.488 ;
     RECT  40.504 10.32 42.001 11.304 ;
     RECT  42.001 10.32 42.073 11.976 ;
     RECT  41.785 2.88 42.077 4.488 ;
     RECT  42.073 10.32 42.109 12.936 ;
     RECT  42.109 10.32 42.179 13.128 ;
     RECT  42.073 23.712 42.179 23.736 ;
     RECT  41.497 56.736 42.179 56.76 ;
     RECT  41.644 17.328 42.229 18.792 ;
     RECT  40.504 109.968 42.277 109.992 ;
     RECT  41.717 20.544 42.293 22.2 ;
     RECT  42.229 17.328 42.316 19.512 ;
     RECT  41.941 78.48 42.323 79.272 ;
     RECT  42.236 99.168 42.323 99.192 ;
     RECT  40.504 71.328 42.325 73.368 ;
     RECT  42.293 20.544 42.337 21.672 ;
     RECT  41.437 61.104 42.371 61.128 ;
     RECT  42.316 17.328 42.419 19.368 ;
     RECT  41.987 76.464 42.649 76.488 ;
     RECT  42.179 12.48 42.661 13.128 ;
     RECT  41.644 14.112 42.661 16.152 ;
     RECT  42.661 12.48 42.677 16.152 ;
     RECT  42.419 17.328 42.677 18.168 ;
     RECT  42.077 3.312 42.685 4.488 ;
     RECT  42.325 71.28 42.721 73.368 ;
     RECT  42.677 12.48 42.748 18.168 ;
     RECT  42.748 15.504 42.755 18.168 ;
     RECT  41.507 67.536 42.757 67.56 ;
     RECT  40.504 124.56 42.793 125.88 ;
     RECT  42.179 10.32 42.797 11.4 ;
     RECT  42.757 67.536 42.797 67.656 ;
     RECT  42.277 109.968 42.797 110.04 ;
     RECT  42.685 3.312 42.829 4.536 ;
     RECT  42.721 71.28 42.833 73.512 ;
     RECT  42.565 129.456 42.869 129.48 ;
     RECT  42.337 20.592 42.985 21.672 ;
     RECT  42.829 3.312 43.189 4.728 ;
     RECT  42.797 10.416 43.189 11.4 ;
     RECT  42.748 12.48 43.189 14.184 ;
     RECT  43.189 10.416 43.372 14.184 ;
     RECT  42.419 19.344 43.477 19.368 ;
     RECT  42.985 20.592 43.477 21.144 ;
     RECT  42.037 0.096 43.517 0.12 ;
     RECT  43.477 19.344 43.553 21.144 ;
     RECT  42.755 15.936 43.621 18.168 ;
     RECT  43.372 12.384 43.625 14.184 ;
     RECT  43.621 15.936 43.657 18.216 ;
     RECT  43.553 19.344 43.657 20.616 ;
     RECT  43.657 15.936 43.667 20.616 ;
     RECT  43.189 3.312 43.693 4.776 ;
     RECT  43.625 14.16 43.729 14.184 ;
     RECT  43.693 3.312 43.82 5.064 ;
     RECT  43.82 3.312 43.907 5.112 ;
     RECT  43.729 14.16 43.909 14.712 ;
     RECT  43.667 15.936 43.909 19.752 ;
     RECT  43.907 3.312 43.949 5.064 ;
     RECT  42.833 71.328 43.955 73.512 ;
     RECT  43.621 1.152 44.021 1.176 ;
     RECT  43.372 10.416 44.156 11.4 ;
     RECT  43.909 14.16 44.165 19.752 ;
     RECT  44.156 9.744 44.243 11.4 ;
     RECT  42.793 124.56 44.309 126.168 ;
     RECT  42.901 61.584 44.381 61.608 ;
     RECT  43.955 71.328 44.437 73.032 ;
     RECT  44.437 71.232 44.483 73.032 ;
     RECT  44.483 71.232 44.524 72.36 ;
     RECT  44.197 21.648 44.533 21.672 ;
     RECT  44.269 22.8 44.579 22.824 ;
     RECT  44.533 20.736 44.62 21.672 ;
     RECT  43.625 12.384 44.701 13.08 ;
     RECT  44.165 14.16 44.701 15.384 ;
     RECT  44.117 0.576 44.777 0.6 ;
     RECT  42.323 78.768 44.953 79.272 ;
     RECT  44.953 78.672 44.989 79.272 ;
     RECT  44.243 10.416 45.013 11.4 ;
     RECT  44.701 12.384 45.013 15.384 ;
     RECT  43.285 128.208 45.065 128.232 ;
     RECT  42.649 76.464 45.097 77.256 ;
     RECT  45.013 10.416 45.277 15.384 ;
     RECT  45.212 0.528 45.299 0.552 ;
     RECT  45.097 76.368 45.36 77.256 ;
     RECT  44.989 78.672 45.36 79.368 ;
     RECT  45.36 76.368 45.432 79.368 ;
     RECT  44.165 19.632 45.452 19.752 ;
     RECT  44.165 16.464 45.601 18.504 ;
     RECT  45.452 19.632 45.601 19.992 ;
     RECT  43.949 3.408 45.608 5.064 ;
     RECT  45.277 9.648 45.608 15.384 ;
     RECT  45.601 16.464 45.608 19.992 ;
     RECT  44.62 21.648 45.608 21.672 ;
     RECT  40.504 25.488 45.608 54.984 ;
     RECT  41.651 58.944 45.608 58.968 ;
     RECT  41.411 62.976 45.608 63 ;
     RECT  42.797 67.632 45.608 67.656 ;
     RECT  41.507 68.64 45.608 68.664 ;
     RECT  44.524 71.328 45.608 72.36 ;
     RECT  40.889 103.488 45.608 103.512 ;
     RECT  42.797 109.968 45.608 109.992 ;
     RECT  45.109 112.992 45.608 113.016 ;
     RECT  44.309 124.56 45.608 125.88 ;
     RECT  45.608 2.148 45.712 23.772 ;
     RECT  45.608 25.488 45.712 73.452 ;
     RECT  45.608 98.808 45.712 127.452 ;
     RECT  45.712 98.808 45.8 127.182 ;
     RECT  45.712 2.418 45.904 23.502 ;
     RECT  45.712 25.488 45.904 73.182 ;
     RECT  45.8 98.538 45.904 127.182 ;
     RECT  45.904 68.64 45.965 68.664 ;
     RECT  45.493 129.456 46.001 129.48 ;
     RECT  45.904 10.32 46.019 20.568 ;
     RECT  46.019 10.32 46.045 18.504 ;
     RECT  46.045 10.32 46.073 15.672 ;
     RECT  45.781 0.096 46.309 0.12 ;
     RECT  45.904 71.328 46.505 71.496 ;
     RECT  46.309 0.096 46.541 0.6 ;
     RECT  45.904 22.224 46.621 22.248 ;
     RECT  45.904 8.832 46.643 8.856 ;
     RECT  46.073 15.648 46.643 15.672 ;
     RECT  45.904 3.312 46.793 4.68 ;
     RECT  46.793 3.408 47.009 4.68 ;
     RECT  46.073 10.32 47.077 14.664 ;
     RECT  46.045 16.944 47.132 18.504 ;
     RECT  46.019 19.776 47.132 20.568 ;
     RECT  47.132 16.944 47.185 20.568 ;
     RECT  47.141 21.648 47.225 21.672 ;
     RECT  47.185 16.224 47.267 20.568 ;
     RECT  47.077 9.456 47.289 14.664 ;
     RECT  45.904 124.56 47.329 125.88 ;
     RECT  47.289 10.176 47.411 14.664 ;
     RECT  47.267 19.632 47.411 20.568 ;
     RECT  46.541 0.096 47.441 0.12 ;
     RECT  46.505 71.328 47.509 71.352 ;
     RECT  45.904 67.632 47.555 67.656 ;
     RECT  47.468 68.832 47.555 68.856 ;
     RECT  47.509 7.44 47.612 7.464 ;
     RECT  47.612 7.44 47.693 8.328 ;
     RECT  47.693 8.304 47.699 8.328 ;
     RECT  47.411 19.968 47.729 20.568 ;
     RECT  47.411 10.176 47.74 12.744 ;
     RECT  47.267 16.224 47.761 18.6 ;
     RECT  45.904 63.84 47.837 63.864 ;
     RECT  47.411 14.064 47.891 14.664 ;
     RECT  47.329 124.56 47.948 125.928 ;
     RECT  47.948 124.56 48.035 126.168 ;
     RECT  47.977 22.8 48.061 22.824 ;
     RECT  47.009 3.456 48.181 4.68 ;
     RECT  47.729 19.968 48.205 20.088 ;
     RECT  47.761 15.984 48.301 18.6 ;
     RECT  48.14 6.24 48.409 6.264 ;
     RECT  47.74 10.32 48.409 12.744 ;
     RECT  48.301 15.696 48.419 18.6 ;
     RECT  48.301 8.784 48.467 9.096 ;
     RECT  48.035 124.56 48.467 125.784 ;
     RECT  48.205 19.968 48.469 19.992 ;
     RECT  47.893 1.152 48.485 1.176 ;
     RECT  48.181 3.456 48.485 5.112 ;
     RECT  48.409 21.12 48.515 21.672 ;
     RECT  48.469 19.92 48.556 19.992 ;
     RECT  47.891 14.64 48.625 14.664 ;
     RECT  48.409 10.32 48.709 13.32 ;
     RECT  48.409 6.24 48.817 6.84 ;
     RECT  48.421 0.096 48.949 0.12 ;
     RECT  48.625 14.64 48.949 14.904 ;
     RECT  48.485 3.456 48.985 4.68 ;
     RECT  48.841 65.52 48.997 65.544 ;
     RECT  48.949 0.096 49.033 0.6 ;
     RECT  48.997 65.52 49.043 66.216 ;
     RECT  49.045 8.16 49.052 8.184 ;
     RECT  48.985 3.408 49.091 4.68 ;
     RECT  48.709 9.216 49.093 13.32 ;
     RECT  49.093 9.216 49.129 13.512 ;
     RECT  48.949 14.544 49.129 14.904 ;
     RECT  48.419 15.984 49.196 18.6 ;
     RECT  49.129 9.216 49.213 14.904 ;
     RECT  49.196 15.984 49.283 19.368 ;
     RECT  49.237 20.544 49.349 20.568 ;
     RECT  49.196 5.952 49.427 5.976 ;
     RECT  49.091 3.456 49.493 4.68 ;
     RECT  49.213 14.064 49.669 14.904 ;
     RECT  49.283 15.984 49.669 18.648 ;
     RECT  49.669 14.064 49.763 18.648 ;
     RECT  48.467 124.56 49.861 125.4 ;
     RECT  49.763 14.064 49.886 17.064 ;
     RECT  48.515 21.648 49.909 21.672 ;
     RECT  49.861 124.56 49.957 125.928 ;
     RECT  49.763 18.432 49.997 18.648 ;
     RECT  49.052 7.92 50.029 8.184 ;
     RECT  49.213 9.216 50.029 12.888 ;
     RECT  46.261 128.208 50.177 128.232 ;
     RECT  50.029 7.392 50.245 12.888 ;
     RECT  50.005 1.152 50.249 1.176 ;
     RECT  49.043 66.192 50.281 66.216 ;
     RECT  49.909 21.12 50.485 21.672 ;
     RECT  47.509 70.8 50.713 71.352 ;
     RECT  45.904 112.896 50.713 112.92 ;
     RECT  50.245 7.392 50.849 13.032 ;
     RECT  49.886 14.112 50.849 17.064 ;
     RECT  50.245 19.392 50.849 19.416 ;
     RECT  50.485 20.448 50.849 21.672 ;
     RECT  49.993 6.384 50.857 6.408 ;
     RECT  50.849 7.392 50.857 17.064 ;
     RECT  50.849 19.392 50.857 21.672 ;
     RECT  49.493 3.456 50.869 4.536 ;
     RECT  49.033 0.096 50.893 0.12 ;
     RECT  50.869 3.12 51.008 4.536 ;
     RECT  50.857 6.384 51.008 17.064 ;
     RECT  50.857 19.392 51.008 22.248 ;
     RECT  45.904 25.488 51.008 54.984 ;
     RECT  45.904 58.944 51.008 58.968 ;
     RECT  50.281 66.192 51.008 66.6 ;
     RECT  50.713 70.8 51.008 71.448 ;
     RECT  45.904 103.488 51.008 103.512 ;
     RECT  45.904 109.968 51.008 109.992 ;
     RECT  50.713 112.896 51.008 113.016 ;
     RECT  49.957 124.56 51.008 125.976 ;
     RECT  51.008 2.148 51.112 23.772 ;
     RECT  51.008 25.488 51.112 73.452 ;
     RECT  51.008 98.808 51.2 127.452 ;
     RECT  51.112 2.418 51.304 23.502 ;
     RECT  51.112 25.488 51.304 73.182 ;
     RECT  51.2 98.538 51.304 127.452 ;
     RECT  45.432 75.6 51.325 96.39 ;
     RECT  51.304 3.6 51.329 4.488 ;
     RECT  51.304 66.576 51.365 67.272 ;
     RECT  51.304 5.664 51.443 7.224 ;
     RECT  51.356 127.68 51.443 127.704 ;
     RECT  51.304 21.12 51.587 21.144 ;
     RECT  51.304 18.816 51.683 19.656 ;
     RECT  51.304 8.304 51.827 8.328 ;
     RECT  51.325 75.216 51.875 96.39 ;
     RECT  51.304 17.616 51.923 17.832 ;
     RECT  50.893 0.096 52.009 0.552 ;
     RECT  51.683 18.816 52.085 18.84 ;
     RECT  52.009 0.096 52.163 0.6 ;
     RECT  50.677 129.456 52.201 129.48 ;
     RECT  51.443 5.664 52.345 6.84 ;
     RECT  51.304 15.888 52.405 16.584 ;
     RECT  51.329 3.6 52.441 4.392 ;
     RECT  52.345 5.664 52.441 5.88 ;
     RECT  51.304 70.8 52.441 71.448 ;
     RECT  51.304 9.36 52.511 14.808 ;
     RECT  52.405 15.888 52.511 16.968 ;
     RECT  52.441 70.8 52.525 72.408 ;
     RECT  52.508 7.392 52.595 7.8 ;
     RECT  52.585 21.648 52.691 21.672 ;
     RECT  52.511 9.36 52.697 16.968 ;
     RECT  52.697 14.112 52.739 16.968 ;
     RECT  52.645 19.392 52.777 19.704 ;
     RECT  52.697 9.36 52.837 12.984 ;
     RECT  52.885 128.208 52.985 128.232 ;
     RECT  52.441 3.6 53.017 5.88 ;
     RECT  52.837 9.072 53.021 12.984 ;
     RECT  52.909 17.664 53.027 17.688 ;
     RECT  51.304 124.56 53.057 125.976 ;
     RECT  53.017 3.408 53.116 5.88 ;
     RECT  53.084 106.56 53.125 106.584 ;
     RECT  53.116 3.408 53.129 5.064 ;
     RECT  53.125 106.56 53.171 107.208 ;
     RECT  53.171 107.184 53.209 107.208 ;
     RECT  52.739 14.112 53.219 14.232 ;
     RECT  51.365 67.248 53.269 67.272 ;
     RECT  53.269 67.248 53.309 67.464 ;
     RECT  52.595 7.392 53.324 7.416 ;
     RECT  53.317 21.36 53.404 21.384 ;
     RECT  53.324 7.248 53.411 7.416 ;
     RECT  53.219 14.112 53.453 14.136 ;
     RECT  53.557 128.784 53.651 128.808 ;
     RECT  52.163 0.096 53.701 0.12 ;
     RECT  52.739 15.36 53.737 16.536 ;
     RECT  51.304 112.992 53.741 113.016 ;
     RECT  53.021 9.072 53.773 11.976 ;
     RECT  53.701 0.096 53.785 0.6 ;
     RECT  53.737 15.36 53.843 16.872 ;
     RECT  53.233 19.968 53.843 19.992 ;
     RECT  53.773 7.824 53.857 11.976 ;
     RECT  53.857 7.824 53.891 7.848 ;
     RECT  53.843 15.936 54.029 16.872 ;
     RECT  53.857 8.976 54.061 11.976 ;
     RECT  53.989 18.816 54.092 18.84 ;
     RECT  54.092 17.856 54.179 18.84 ;
     RECT  53.785 0.096 54.281 0.12 ;
     RECT  53.129 3.408 54.313 4.872 ;
     RECT  54.229 21.12 54.317 21.144 ;
     RECT  53.881 13.488 54.457 13.512 ;
     RECT  54.188 14.592 54.457 14.904 ;
     RECT  54.38 6.768 54.467 6.792 ;
     RECT  54.325 128.208 54.605 128.232 ;
     RECT  53.309 67.44 54.611 67.464 ;
     RECT  52.525 70.8 54.611 71.544 ;
     RECT  54.565 68.784 54.652 69.48 ;
     RECT  54.061 8.976 54.749 12.216 ;
     RECT  53.057 124.56 54.781 125.88 ;
     RECT  54.716 7.248 54.803 7.272 ;
     RECT  54.029 16.848 54.853 16.872 ;
     RECT  54.749 9.936 54.857 12.216 ;
     RECT  54.457 13.488 54.857 14.904 ;
     RECT  54.857 10.224 54.889 12.216 ;
     RECT  54.857 13.488 54.889 13.704 ;
     RECT  54.781 124.56 54.893 126.504 ;
     RECT  54.889 10.224 55.043 13.704 ;
     RECT  54.857 14.88 55.093 14.904 ;
     RECT  55.093 14.88 55.139 15.624 ;
     RECT  54.853 16.848 55.139 17.688 ;
     RECT  55.139 15.6 55.181 15.624 ;
     RECT  54.961 8.448 55.189 8.472 ;
     RECT  55.043 12.96 55.283 13.704 ;
     RECT  51.304 109.968 55.283 109.992 ;
     RECT  54.757 0.576 55.285 0.6 ;
     RECT  54.313 3.408 55.321 5.112 ;
     RECT  55.237 112.848 55.324 112.872 ;
     RECT  55.069 19.728 55.331 19.752 ;
     RECT  55.244 20.784 55.331 20.808 ;
     RECT  55.321 3.408 55.537 5.304 ;
     RECT  55.537 3.408 55.573 5.448 ;
     RECT  55.189 7.584 55.813 8.472 ;
     RECT  55.285 0.096 55.859 0.6 ;
     RECT  55.043 10.224 55.861 11.976 ;
     RECT  55.813 6.72 55.933 8.472 ;
     RECT  55.283 13.296 56.005 13.704 ;
     RECT  55.861 10.176 56.101 11.976 ;
     RECT  55.933 6.72 56.293 8.76 ;
     RECT  56.101 9.936 56.293 11.976 ;
     RECT  55.573 3.36 56.408 5.448 ;
     RECT  56.293 6.72 56.408 11.976 ;
     RECT  56.005 13.296 56.408 14.232 ;
     RECT  55.139 16.848 56.408 16.872 ;
     RECT  55.645 17.856 56.408 18.264 ;
     RECT  56.005 20.544 56.408 20.568 ;
     RECT  51.304 25.488 56.408 54.984 ;
     RECT  51.304 58.944 56.408 58.968 ;
     RECT  54.652 69.456 56.408 69.48 ;
     RECT  54.611 70.8 56.408 70.824 ;
     RECT  51.304 101.712 56.408 101.736 ;
     RECT  51.304 103.488 56.408 103.512 ;
     RECT  55.237 116.16 56.408 116.184 ;
     RECT  54.893 124.56 56.408 125.976 ;
     RECT  56.408 2.148 56.512 23.772 ;
     RECT  56.408 25.488 56.512 73.452 ;
     RECT  56.408 98.808 56.512 127.452 ;
     RECT  55.093 129.456 56.533 129.48 ;
     RECT  56.533 128.832 56.585 129.48 ;
     RECT  56.512 98.808 56.6 127.182 ;
     RECT  56.512 2.418 56.704 23.502 ;
     RECT  56.512 25.488 56.704 73.182 ;
     RECT  56.6 98.538 56.704 127.182 ;
     RECT  56.704 3.408 56.765 5.352 ;
     RECT  56.585 128.832 56.801 128.856 ;
     RECT  56.704 6.432 56.963 9.432 ;
     RECT  56.704 18.576 56.963 19.992 ;
     RECT  56.765 3.552 56.989 5.352 ;
     RECT  56.869 1.152 57.053 1.176 ;
     RECT  56.963 7.968 57.203 9.432 ;
     RECT  56.704 10.848 57.241 14.088 ;
     RECT  56.963 18.72 57.347 18.744 ;
     RECT  57.301 128.208 57.385 128.232 ;
     RECT  56.963 19.968 57.413 19.992 ;
     RECT  57.241 11.04 57.665 14.088 ;
     RECT  57.665 12.912 57.779 14.088 ;
     RECT  56.989 3.552 57.925 5.304 ;
     RECT  55.859 0.096 57.941 0.12 ;
     RECT  57.925 3.36 57.98 5.304 ;
     RECT  56.963 6.816 57.98 6.84 ;
     RECT  57.203 7.968 57.98 8.472 ;
     RECT  57.733 17.664 57.989 17.688 ;
     RECT  57.98 3.36 58.012 6.84 ;
     RECT  57.941 0.096 58.025 0.6 ;
     RECT  57.665 11.04 58.089 11.4 ;
     RECT  58.012 3.6 58.093 6.84 ;
     RECT  57.98 7.872 58.093 8.472 ;
     RECT  58.093 3.6 58.097 8.472 ;
     RECT  58.097 5.424 58.165 8.472 ;
     RECT  56.704 124.944 58.202 125.976 ;
     RECT  56.704 70.704 58.205 70.824 ;
     RECT  58.089 11.04 58.261 11.352 ;
     RECT  57.779 12.96 58.307 14.088 ;
     RECT  58.273 18.816 58.357 18.84 ;
     RECT  58.307 12.96 58.421 13.464 ;
     RECT  58.165 5.424 58.453 8.664 ;
     RECT  58.261 10.464 58.46 11.352 ;
     RECT  58.205 70.8 58.637 70.824 ;
     RECT  58.453 5.424 58.835 8.712 ;
     RECT  58.835 5.952 58.837 8.712 ;
     RECT  58.46 9.744 58.837 11.352 ;
     RECT  58.837 5.952 58.925 11.352 ;
     RECT  58.025 0.096 59.029 0.12 ;
     RECT  58.421 13.008 59.033 13.464 ;
     RECT  58.925 7.344 59.125 11.352 ;
     RECT  59.101 18.24 59.185 18.264 ;
     RECT  59.029 0.096 59.285 0.6 ;
     RECT  58.202 124.944 59.353 125.928 ;
     RECT  58.097 3.648 59.413 4.44 ;
     RECT  58.925 5.952 59.459 5.976 ;
     RECT  59.125 7.344 59.509 11.976 ;
     RECT  59.033 13.008 59.509 13.032 ;
     RECT  59.468 18.672 59.555 18.696 ;
     RECT  59.509 19.968 59.717 19.992 ;
     RECT  58.021 129.456 59.717 129.48 ;
     RECT  59.509 7.344 59.795 13.032 ;
     RECT  59.413 3.648 59.857 4.536 ;
     RECT  59.857 3.648 60.044 5.688 ;
     RECT  60.044 3.312 60.131 5.688 ;
     RECT  59.795 7.344 60.229 9.72 ;
     RECT  60.131 3.648 60.336 5.688 ;
     RECT  59.795 10.8 60.467 13.032 ;
     RECT  60.229 6.864 60.659 9.72 ;
     RECT  60.467 10.8 60.659 12.552 ;
     RECT  60.253 17.568 60.659 17.592 ;
     RECT  60.659 10.8 60.755 12.024 ;
     RECT  60.659 6.864 60.764 7.224 ;
     RECT  60.659 8.256 60.805 9.72 ;
     RECT  60.721 21.12 60.805 21.144 ;
     RECT  59.285 0.096 61.085 0.12 ;
     RECT  58.741 128.208 61.157 128.232 ;
     RECT  60.805 8.256 61.285 9.768 ;
     RECT  60.755 10.8 61.285 11.832 ;
     RECT  60.577 18.816 61.285 18.84 ;
     RECT  60.764 6.192 61.669 7.224 ;
     RECT  61.285 8.256 61.669 11.832 ;
     RECT  61.685 129.456 61.769 129.48 ;
     RECT  60.336 3.648 61.808 5.064 ;
     RECT  61.669 6.192 61.808 11.832 ;
     RECT  61.285 18.72 61.808 19.416 ;
     RECT  61.669 20.592 61.808 20.616 ;
     RECT  56.704 25.488 61.808 54.984 ;
     RECT  56.704 58.944 61.808 58.968 ;
     RECT  60.901 72.144 61.808 72.168 ;
     RECT  56.704 101.712 61.808 101.736 ;
     RECT  56.704 103.488 61.808 103.512 ;
     RECT  56.704 116.16 61.808 116.184 ;
     RECT  59.353 124.944 61.808 126.168 ;
     RECT  61.808 2.148 61.912 23.772 ;
     RECT  61.808 25.488 61.912 73.452 ;
     RECT  61.808 98.808 61.912 127.452 ;
     RECT  61.912 98.808 62 127.182 ;
     RECT  61.912 2.418 62.104 23.502 ;
     RECT  61.912 25.488 62.104 73.182 ;
     RECT  62 98.538 62.104 127.182 ;
     RECT  62.104 3.408 62.243 6.552 ;
     RECT  62.104 7.968 62.265 12.36 ;
     RECT  61.141 0.576 62.417 0.6 ;
     RECT  62.104 18.384 62.819 18.84 ;
     RECT  62.243 3.408 62.821 5.112 ;
     RECT  62.265 8.16 63.107 12.36 ;
     RECT  63.097 19.968 63.251 19.992 ;
     RECT  62.243 6.192 63.253 6.552 ;
     RECT  63.107 8.16 63.253 11.448 ;
     RECT  62.821 3.408 63.317 4.728 ;
     RECT  63.253 6.192 63.397 11.448 ;
     RECT  63.397 6.144 63.497 11.448 ;
     RECT  51.875 75.6 63.648 96.39 ;
     RECT  63.648 76.368 63.821 79.272 ;
     RECT  63.745 19.104 63.889 19.128 ;
     RECT  63.821 76.368 63.893 79.176 ;
     RECT  63.889 18.768 64.028 19.128 ;
     RECT  63.497 6.288 64.069 11.448 ;
     RECT  64.069 6.288 64.115 12.024 ;
     RECT  64.028 18.72 64.115 19.128 ;
     RECT  63.317 3.696 64.321 4.728 ;
     RECT  63.829 20.544 64.325 20.568 ;
     RECT  64.115 10.176 64.451 12.024 ;
     RECT  64.115 6.288 64.547 8.904 ;
     RECT  64.547 6.288 64.691 8.76 ;
     RECT  64.321 3.408 64.789 4.728 ;
     RECT  64.691 6.288 64.789 8.472 ;
     RECT  64.451 10.272 64.793 12.024 ;
     RECT  64.789 3.408 64.973 8.472 ;
     RECT  64.973 3.696 65.009 8.472 ;
     RECT  64.793 10.848 65.045 12.024 ;
     RECT  65.045 10.848 65.267 11.4 ;
     RECT  65.009 5.712 65.507 8.472 ;
     RECT  65.507 5.712 65.555 6.648 ;
     RECT  63.893 76.464 65.585 79.176 ;
     RECT  65.507 7.632 65.66 8.472 ;
     RECT  65.66 7.632 65.747 8.856 ;
     RECT  65.267 11.136 65.747 11.4 ;
     RECT  65.365 1.152 65.765 1.176 ;
     RECT  65.689 18.816 65.773 18.84 ;
     RECT  65.585 76.464 65.981 76.488 ;
     RECT  65.585 78.096 66.017 79.176 ;
     RECT  66.017 78.096 66.233 78.696 ;
     RECT  65.009 3.696 66.373 4.68 ;
     RECT  66.373 3.408 66.553 4.68 ;
     RECT  62.104 124.944 66.661 126.168 ;
     RECT  66.661 124.896 66.697 126.168 ;
     RECT  66.553 3.408 67.208 6.168 ;
     RECT  65.747 7.632 67.208 8.472 ;
     RECT  65.747 11.136 67.208 11.16 ;
     RECT  62.104 25.488 67.208 54.984 ;
     RECT  62.104 58.944 67.208 58.968 ;
     RECT  62.104 72.432 67.208 72.456 ;
     RECT  66.233 78.192 67.208 78.216 ;
     RECT  62.104 101.712 67.208 101.736 ;
     RECT  62.104 103.488 67.208 103.512 ;
     RECT  67.093 108.864 67.208 108.888 ;
     RECT  62.104 116.16 67.208 116.184 ;
     RECT  66.697 124.896 67.208 126.264 ;
     RECT  62.437 128.208 67.208 128.232 ;
     RECT  67.208 2.148 67.312 23.772 ;
     RECT  67.208 25.488 67.312 128.232 ;
     RECT  62.725 0.096 67.477 0.12 ;
     RECT  67.312 2.418 67.504 23.502 ;
     RECT  67.312 25.488 67.504 127.182 ;
     RECT  67.504 106.512 67.667 108.888 ;
     RECT  67.477 0.096 67.673 0.6 ;
     RECT  67.667 106.512 67.708 108.216 ;
     RECT  67.673 0.576 67.709 0.6 ;
     RECT  67.504 72.432 67.715 72.456 ;
     RECT  67.504 104.928 67.715 105.432 ;
     RECT  67.708 106.512 67.717 107.784 ;
     RECT  67.717 106.512 67.781 107.112 ;
     RECT  67.312 128.208 67.853 128.232 ;
     RECT  67.504 94.464 67.925 94.536 ;
     RECT  67.504 11.136 68.435 11.16 ;
     RECT  68.005 1.152 68.465 1.176 ;
     RECT  67.504 3.456 68.533 4.968 ;
     RECT  68.533 3.408 68.609 4.968 ;
     RECT  67.504 101.712 68.713 101.736 ;
     RECT  67.781 107.088 68.713 107.112 ;
     RECT  67.504 7.632 68.819 8.472 ;
     RECT  68.713 107.088 68.929 107.784 ;
     RECT  68.713 101.328 69.005 101.736 ;
     RECT  68.929 106.992 69.013 107.784 ;
     RECT  69.013 106.512 69.059 108.312 ;
     RECT  68.533 1.248 69.113 1.272 ;
     RECT  69.005 101.328 69.205 101.352 ;
     RECT  67.925 94.512 69.251 94.536 ;
     RECT  69.059 108.288 69.397 108.312 ;
     RECT  69.205 101.28 69.443 101.352 ;
     RECT  67.715 105.408 69.539 105.432 ;
     RECT  68.341 129.456 69.581 129.48 ;
     RECT  68.609 3.408 69.617 4.632 ;
     RECT  69.059 106.512 69.689 107.016 ;
     RECT  69.689 106.512 69.725 106.536 ;
     RECT  69.061 0.096 69.797 0.12 ;
     RECT  69.397 108.288 70.117 108.36 ;
     RECT  70.117 108.288 70.157 108.936 ;
     RECT  70.153 0.528 70.237 0.6 ;
     RECT  67.504 124.8 70.373 126.264 ;
     RECT  69.781 128.208 70.769 128.232 ;
     RECT  70.237 0.528 70.777 0.552 ;
     RECT  70.373 124.848 70.805 126.264 ;
     RECT  70.805 124.848 70.841 126.168 ;
     RECT  71.221 0.096 71.309 0.12 ;
     RECT  71.261 129.456 71.345 129.48 ;
     RECT  67.504 25.488 71.64 54.984 ;
     RECT  71.64 25.488 71.795 25.512 ;
     RECT  71.64 26.688 71.813 46.488 ;
     RECT  71.813 34.752 71.885 35.928 ;
     RECT  71.813 37.056 71.885 43.608 ;
     RECT  71.813 44.928 71.885 44.952 ;
     RECT  71.813 26.688 71.921 32.088 ;
     RECT  71.749 1.152 72.029 1.176 ;
     RECT  72.236 0.528 72.323 1.128 ;
     RECT  67.504 116.16 72.493 116.184 ;
     RECT  71.921 26.688 72.533 29.976 ;
     RECT  72.533 28.992 72.569 29.976 ;
     RECT  72.569 29.376 72.605 29.976 ;
     RECT  69.617 3.408 72.608 4.536 ;
     RECT  68.773 6 72.608 6.024 ;
     RECT  68.819 7.632 72.608 7.656 ;
     RECT  71.64 54.384 72.608 54.984 ;
     RECT  67.504 58.944 72.608 58.968 ;
     RECT  69.443 101.328 72.608 101.352 ;
     RECT  67.504 103.488 72.608 103.512 ;
     RECT  71.629 105.936 72.608 105.96 ;
     RECT  70.157 108.912 72.608 108.936 ;
     RECT  72.493 116.16 72.608 117 ;
     RECT  70.841 124.896 72.608 126.168 ;
     RECT  71.989 128.208 72.608 128.232 ;
     RECT  72.605 29.952 72.641 29.976 ;
     RECT  72.608 2.148 72.712 23.772 ;
     RECT  72.608 54.384 72.712 128.232 ;
     RECT  72.323 1.104 72.851 1.128 ;
     RECT  72.712 2.418 72.904 23.502 ;
     RECT  72.712 54.384 72.904 127.182 ;
     RECT  71.885 35.328 73.001 35.928 ;
     RECT  71.885 37.056 73.001 38.808 ;
     RECT  72.904 124.848 73.225 126.168 ;
     RECT  72.904 101.328 73.235 101.352 ;
     RECT  72.533 26.688 73.253 27.864 ;
     RECT  72.904 105.936 73.261 106.008 ;
     RECT  73.253 26.688 73.325 27.48 ;
     RECT  73.261 105.936 73.331 105.96 ;
     RECT  72.904 108.912 73.613 109.32 ;
     RECT  71.921 31.104 73.757 32.088 ;
     RECT  73.333 0.528 73.861 0.552 ;
     RECT  71.885 40.128 73.973 40.152 ;
     RECT  71.885 41.472 73.973 42.072 ;
     RECT  71.813 46.08 74.009 46.488 ;
     RECT  73.325 26.688 74.045 26.904 ;
     RECT  73.973 42.048 74.045 42.072 ;
     RECT  74.045 26.88 74.081 26.904 ;
     RECT  74.009 46.08 74.081 46.104 ;
     RECT  73.757 32.064 74.189 32.088 ;
     RECT  73.861 0.528 74.389 0.6 ;
     RECT  73.001 38.784 74.405 38.808 ;
     RECT  73.613 109.152 74.509 109.32 ;
     RECT  74.509 109.152 74.765 109.464 ;
     RECT  74.765 109.44 74.909 109.464 ;
     RECT  72.904 3.408 74.945 4.728 ;
     RECT  74.389 0.096 74.981 0.6 ;
     RECT  72.712 128.208 75.017 128.232 ;
     RECT  74.981 0.096 75.973 0.12 ;
     RECT  75.973 0.096 76.241 0.6 ;
     RECT  74.945 3.408 76.273 3.72 ;
     RECT  74.945 4.704 76.273 4.728 ;
     RECT  73.225 124.896 76.417 126.168 ;
     RECT  75.685 129.456 76.421 129.48 ;
     RECT  72.904 113.712 76.781 113.736 ;
     RECT  76.273 3.408 77.065 4.728 ;
     RECT  76.373 128.208 77.573 128.232 ;
     RECT  77.065 3.312 78.008 4.728 ;
     RECT  72.904 6 78.008 6.024 ;
     RECT  72.904 7.632 78.008 7.656 ;
     RECT  72.904 54.384 78.008 54.984 ;
     RECT  72.904 58.944 78.008 58.968 ;
     RECT  72.904 103.488 78.008 103.512 ;
     RECT  72.904 110.544 78.008 110.568 ;
     RECT  77.461 112.224 78.008 112.248 ;
     RECT  77.077 113.664 78.008 113.688 ;
     RECT  72.904 116.16 78.008 117 ;
     RECT  76.417 124.848 78.008 126.168 ;
     RECT  78.008 2.148 78.112 127.452 ;
     RECT  78.112 2.418 78.304 127.182 ;
     RECT  78.304 3.312 78.365 4.728 ;
     RECT  78.304 7.632 78.707 7.656 ;
     RECT  78.304 5.952 78.748 6.264 ;
     RECT  78.304 124.8 78.748 126.024 ;
     RECT  78.748 5.952 78.755 5.976 ;
     RECT  78.661 128.208 78.761 128.232 ;
     RECT  78.304 112.224 78.941 112.248 ;
     RECT  79.141 1.152 79.337 1.176 ;
     RECT  78.304 110.544 79.765 110.568 ;
     RECT  79.724 112.08 79.765 112.104 ;
     RECT  79.765 110.544 79.811 112.104 ;
     RECT  79.657 114.624 79.829 114.648 ;
     RECT  79.829 114.528 79.907 114.648 ;
     RECT  79.907 114.528 79.913 114.552 ;
     RECT  78.365 3.312 80.197 4.392 ;
     RECT  79.811 110.544 80.417 111.432 ;
     RECT  80.417 110.544 80.633 110.568 ;
     RECT  80.197 3.312 82.109 4.536 ;
     RECT  82.109 3.408 82.141 4.536 ;
     RECT  78.748 124.8 82.145 125.976 ;
     RECT  76.241 0.096 82.309 0.12 ;
     RECT  82.145 124.8 82.361 125.928 ;
     RECT  77.893 129.456 82.505 129.48 ;
     RECT  82.309 0.096 82.613 0.6 ;
     RECT  83.077 129.216 83.189 129.24 ;
     RECT  82.141 3.408 83.408 4.728 ;
     RECT  78.304 54.384 83.408 54.984 ;
     RECT  78.304 58.944 83.408 58.968 ;
     RECT  78.304 103.488 83.408 103.512 ;
     RECT  78.304 116.16 83.408 117 ;
     RECT  82.361 125.088 83.408 125.928 ;
     RECT  83.329 1.104 83.459 1.128 ;
     RECT  83.408 2.148 83.512 127.452 ;
     RECT  83.512 2.418 83.704 127.182 ;
     RECT  83.704 125.088 83.873 125.784 ;
     RECT  83.704 3.408 84.773 4.728 ;
     RECT  83.797 129.456 84.953 129.48 ;
     RECT  83.873 125.136 84.989 125.784 ;
     RECT  82.613 0.096 84.997 0.12 ;
     RECT  84.989 125.136 85.313 125.64 ;
     RECT  85.273 128.208 85.357 128.232 ;
     RECT  85.313 125.376 85.421 125.64 ;
     RECT  85.421 125.472 85.957 125.64 ;
     RECT  83.704 116.16 86.101 117 ;
     RECT  86.101 115.344 86.147 117 ;
     RECT  84.773 3.408 86.177 4.584 ;
     RECT  86.147 115.344 86.188 116.184 ;
     RECT  84.997 0.096 86.285 0.6 ;
     RECT  86.177 3.84 86.609 4.584 ;
     RECT  85.957 125.472 86.681 125.784 ;
     RECT  86.609 3.936 86.717 4.584 ;
     RECT  86.005 129.456 86.725 129.48 ;
     RECT  86.725 129.408 87.257 129.48 ;
     RECT  86.717 3.936 87.577 4.44 ;
     RECT  87.577 3.696 87.721 4.44 ;
     RECT  86.681 125.616 88.261 125.784 ;
     RECT  87.721 3.408 88.808 4.44 ;
     RECT  83.704 54.384 88.808 54.984 ;
     RECT  83.704 58.944 88.808 58.968 ;
     RECT  83.704 103.488 88.808 103.512 ;
     RECT  86.188 115.344 88.808 115.368 ;
     RECT  88.261 124.8 88.808 125.784 ;
     RECT  88.808 2.148 88.912 127.452 ;
     RECT  88.912 2.418 89.104 127.182 ;
     RECT  86.285 0.096 90.101 0.12 ;
     RECT  87.257 129.456 90.101 129.48 ;
     RECT  90.421 128.208 90.605 128.232 ;
     RECT  90.277 0.528 90.781 0.552 ;
     RECT  90.781 0.528 90.865 0.648 ;
     RECT  89.104 124.8 90.889 125.928 ;
     RECT  90.889 124.8 91.235 126.168 ;
     RECT  91.141 129.456 91.253 129.48 ;
     RECT  89.104 3.408 91.289 4.68 ;
     RECT  91.333 0.096 91.861 0.12 ;
     RECT  92.221 118.56 92.473 118.584 ;
     RECT  91.861 0.096 92.477 0.6 ;
     RECT  92.473 118.032 92.485 118.584 ;
     RECT  89.104 116.448 92.581 116.472 ;
     RECT  92.485 118.032 92.581 119.016 ;
     RECT  92.581 116.448 92.627 119.016 ;
     RECT  92.627 117.264 92.765 117.288 ;
     RECT  91.289 3.984 92.833 4.68 ;
     RECT  92.833 3.936 92.905 4.68 ;
     RECT  92.477 0.528 92.981 0.6 ;
     RECT  91.235 125.712 92.981 126.168 ;
     RECT  92.905 3.936 93.049 4.92 ;
     RECT  93.049 3.456 93.125 4.92 ;
     RECT  93.125 3.456 93.161 4.824 ;
     RECT  92.581 111.12 93.481 111.144 ;
     RECT  92.981 0.528 93.491 0.552 ;
     RECT  91.909 128.208 94.169 128.232 ;
     RECT  93.161 3.456 94.208 4.776 ;
     RECT  89.104 54.384 94.208 54.984 ;
     RECT  89.104 58.944 94.208 58.968 ;
     RECT  93.829 63.552 94.208 63.576 ;
     RECT  89.104 103.488 94.208 103.512 ;
     RECT  93.481 111.024 94.208 111.144 ;
     RECT  89.104 115.344 94.208 115.368 ;
     RECT  92.627 118.992 94.208 119.016 ;
     RECT  92.981 125.952 94.208 126.168 ;
     RECT  94.208 2.148 94.312 127.452 ;
     RECT  94.312 2.418 94.504 127.182 ;
     RECT  94.504 118.992 94.601 119.112 ;
     RECT  94.504 126 95.213 126.168 ;
     RECT  94.504 4.128 95.315 4.776 ;
     RECT  94.837 129.456 95.609 129.48 ;
     RECT  94.504 116.976 95.708 117 ;
     RECT  94.504 111.024 95.795 111.048 ;
     RECT  95.708 116.928 95.795 117 ;
     RECT  94.601 119.088 96.001 119.112 ;
     RECT  96.001 119.088 96.041 119.208 ;
     RECT  95.315 4.128 96.133 4.68 ;
     RECT  94.504 58.944 96.185 58.968 ;
     RECT  96.133 3.36 96.221 4.68 ;
     RECT  94.504 54.384 96.329 54.984 ;
     RECT  95.213 126.144 96.469 126.168 ;
     RECT  96.325 128.208 96.473 128.232 ;
     RECT  96.145 120.24 96.685 120.264 ;
     RECT  96.329 54.384 96.869 54.408 ;
     RECT  96.041 119.184 97.373 119.208 ;
     RECT  96.685 120.24 97.388 120.504 ;
     RECT  96.221 3.456 97.409 4.68 ;
     RECT  97.388 120.096 97.429 120.504 ;
     RECT  95.749 122.544 97.429 122.568 ;
     RECT  97.429 122.544 97.43 122.616 ;
     RECT  97.429 120.096 97.475 121.176 ;
     RECT  97.475 120.768 97.516 121.176 ;
     RECT  94.504 115.344 97.517 115.368 ;
     RECT  93.973 0.096 97.685 0.12 ;
     RECT  97.685 0.096 97.769 0.6 ;
     RECT  97.43 122.592 97.797 122.616 ;
     RECT  94.504 103.488 97.813 103.512 ;
     RECT  97.772 115.536 97.859 115.56 ;
     RECT  96.469 125.424 98.005 126.168 ;
     RECT  98.005 124.8 98.051 126.168 ;
     RECT  97.409 3.456 98.057 4.488 ;
     RECT  97.045 129.456 98.093 129.48 ;
     RECT  98.051 124.8 98.165 125.64 ;
     RECT  97.813 103.488 98.453 104.28 ;
     RECT  97.516 120.768 98.561 120.792 ;
     RECT  98.629 119.52 98.737 119.544 ;
     RECT  98.533 129.408 98.813 129.432 ;
     RECT  98.057 3.84 99.133 4.488 ;
     RECT  99.133 3.6 99.277 4.488 ;
     RECT  98.737 119.52 99.385 120.216 ;
     RECT  99.253 129.456 99.533 129.48 ;
     RECT  99.277 3.6 99.608 4.68 ;
     RECT  94.504 63.552 99.608 63.576 ;
     RECT  98.453 103.488 99.608 103.512 ;
     RECT  99.493 112.128 99.608 112.152 ;
     RECT  99.493 113.136 99.608 113.16 ;
     RECT  95.795 116.976 99.608 117 ;
     RECT  99.385 119.184 99.608 120.216 ;
     RECT  98.165 124.8 99.608 125.448 ;
     RECT  99.608 2.148 99.712 127.452 ;
     RECT  99.712 2.418 99.904 127.182 ;
     RECT  99.904 119.52 99.929 119.544 ;
     RECT  99.904 62.592 100.019 62.616 ;
     RECT  99.904 67.152 100.019 67.176 ;
     RECT  99.904 112.128 100.019 112.152 ;
     RECT  99.961 128.208 100.045 128.232 ;
     RECT  99.904 103.728 100.067 104.28 ;
     RECT  99.904 116.976 100.067 117 ;
     RECT  99.904 65.136 100.109 65.976 ;
     RECT  100.067 103.728 100.115 103.752 ;
     RECT  97.769 0.096 100.316 0.12 ;
     RECT  100.316 0.096 100.403 0.552 ;
     RECT  99.904 90.768 100.469 91.176 ;
     RECT  100.573 128.832 100.787 128.856 ;
     RECT  99.904 123.648 100.931 123.672 ;
     RECT  99.904 124.704 100.937 125.448 ;
     RECT  100.403 0.096 101.393 0.12 ;
     RECT  99.904 3.936 101.477 4.68 ;
     RECT  101.221 129.456 101.507 129.48 ;
     RECT  101.393 0.096 101.9 0.168 ;
     RECT  101.9 0.096 101.987 0.552 ;
     RECT  100.469 91.104 101.989 91.176 ;
     RECT  101.989 91.104 102.035 91.224 ;
     RECT  100.109 65.136 102.377 65.16 ;
     RECT  101.477 4.656 102.445 4.68 ;
     RECT  102.445 3.984 102.449 4.68 ;
     RECT  102.449 3.984 102.589 4.008 ;
     RECT  100.937 124.704 102.589 124.824 ;
     RECT  102.337 122.496 102.613 122.52 ;
     RECT  102.613 121.968 102.659 122.52 ;
     RECT  102.589 3.264 102.707 4.008 ;
     RECT  102.553 126.528 102.737 126.552 ;
     RECT  102.707 3.264 102.809 3.912 ;
     RECT  102.733 60.96 102.817 61.56 ;
     RECT  102.085 127.632 102.995 127.656 ;
     RECT  103.148 114.24 103.157 114.264 ;
     RECT  102.809 3.264 103.205 3.288 ;
     RECT  103.157 114.24 103.235 115.176 ;
     RECT  103.235 115.152 103.241 115.176 ;
     RECT  102.659 121.968 103.241 121.992 ;
     RECT  102.589 123.984 103.241 124.824 ;
     RECT  103.241 124.224 103.309 124.824 ;
     RECT  102.035 91.2 103.313 91.224 ;
     RECT  103.309 124.224 103.379 126.024 ;
     RECT  103.379 124.704 103.393 126.024 ;
     RECT  103.393 124.704 103.42 125.88 ;
     RECT  103.417 127.392 103.715 127.416 ;
     RECT  102.817 60.96 103.853 60.984 ;
     RECT  103.772 110.208 103.859 110.232 ;
     RECT  102.697 111.504 103.859 111.528 ;
     RECT  102.757 64.224 104.003 64.248 ;
     RECT  103.772 91.488 104.003 91.512 ;
     RECT  102.661 5.136 104.209 5.16 ;
     RECT  101.987 0.096 104.533 0.12 ;
     RECT  104.533 0.096 104.627 0.552 ;
     RECT  104.281 3.36 105.008 3.384 ;
     RECT  104.209 4.944 105.008 5.16 ;
     RECT  103.42 125.184 105.008 125.88 ;
     RECT  105.008 2.148 105.112 127.452 ;
     RECT  105.112 2.418 105.304 127.182 ;
     RECT  104.627 0.096 105.401 0.216 ;
     RECT  105.304 3.984 105.545 4.968 ;
     RECT  105.401 0.192 105.683 0.216 ;
     RECT  104.029 129.456 105.941 129.48 ;
     RECT  106.124 0.528 106.211 0.552 ;
     RECT  106.513 120.72 106.549 120.744 ;
     RECT  105.545 3.984 106.585 4.008 ;
     RECT  105.304 103.152 106.585 103.176 ;
     RECT  106.585 128.832 106.669 128.856 ;
     RECT  106.585 3.312 106.739 4.008 ;
     RECT  106.739 3.312 107.125 3.336 ;
     RECT  106.585 8.832 107.125 9.816 ;
     RECT  106.585 15.312 107.125 15.336 ;
     RECT  106.585 19.008 107.125 19.032 ;
     RECT  106.513 23.664 107.125 23.688 ;
     RECT  106.585 31.056 107.125 31.08 ;
     RECT  106.585 34.752 107.125 34.776 ;
     RECT  106.585 37.488 107.125 38.472 ;
     RECT  106.585 40.272 107.125 41.256 ;
     RECT  106.585 47.664 107.125 47.688 ;
     RECT  106.585 49.536 107.125 49.56 ;
     RECT  106.585 55.056 107.125 55.08 ;
     RECT  106.585 56.928 107.125 56.952 ;
     RECT  106.585 61.536 107.125 61.56 ;
     RECT  106.585 72.624 107.125 72.648 ;
     RECT  106.585 75.408 107.125 75.432 ;
     RECT  106.549 77.28 107.125 77.304 ;
     RECT  106.585 79.104 107.125 80.088 ;
     RECT  106.585 81.888 107.125 82.824 ;
     RECT  106.585 89.28 107.125 89.304 ;
     RECT  106.585 98.544 107.125 98.568 ;
     RECT  106.585 107.808 107.125 108.744 ;
     RECT  105.304 111.504 107.125 111.528 ;
     RECT  106.585 117.024 107.125 117.048 ;
     RECT  106.585 118.896 107.125 118.92 ;
     RECT  106.549 120.72 107.125 121.656 ;
     RECT  107.125 7.92 107.161 11.64 ;
     RECT  107.125 13.488 107.161 16.248 ;
     RECT  107.125 18.096 107.161 20.904 ;
     RECT  107.125 22.704 107.161 26.424 ;
     RECT  106.585 28.272 107.161 28.296 ;
     RECT  107.125 30.096 107.161 31.08 ;
     RECT  107.125 32.88 107.161 32.904 ;
     RECT  107.125 34.752 107.161 38.472 ;
     RECT  107.125 40.272 107.161 43.08 ;
     RECT  107.125 44.928 107.161 53.256 ;
     RECT  107.125 55.056 107.161 57.864 ;
     RECT  107.125 59.712 107.161 59.736 ;
     RECT  107.125 61.536 107.161 62.52 ;
     RECT  107.125 64.32 107.161 64.344 ;
     RECT  106.585 66.192 107.161 69.912 ;
     RECT  107.125 71.712 107.161 72.648 ;
     RECT  107.125 74.496 107.161 80.088 ;
     RECT  107.125 81.888 107.161 87.48 ;
     RECT  107.125 89.28 107.161 93.96 ;
     RECT  107.125 96.672 107.161 99.48 ;
     RECT  106.585 101.328 107.161 104.088 ;
     RECT  107.125 105.936 107.161 113.352 ;
     RECT  107.125 116.112 107.161 121.656 ;
     RECT  106.585 123.504 107.161 123.528 ;
     RECT  106.549 125.376 107.161 125.4 ;
     RECT  107.125 127.2 107.161 127.224 ;
     RECT  107.125 1.44 107.881 3.336 ;
     RECT  107.125 5.136 107.881 6.12 ;
     RECT  107.161 7.92 107.881 57.864 ;
     RECT  107.161 59.712 107.881 127.224 ;
     RECT  107.881 1.44 107.916 1.464 ;
     RECT  107.881 1.464 107.964 2.352 ;
     RECT  107.881 2.352 107.916 2.376 ;
     RECT  107.881 2.376 107.964 3.312 ;
     RECT  107.881 3.312 107.916 3.336 ;
     RECT  107.881 3.336 107.964 4.224 ;
     RECT  107.881 4.224 107.916 4.248 ;
     RECT  107.881 4.248 107.964 5.136 ;
     RECT  107.881 5.136 107.916 5.16 ;
     RECT  107.881 5.16 107.964 6.096 ;
     RECT  107.881 6.096 107.916 6.12 ;
     RECT  107.881 6.12 107.964 7.008 ;
     RECT  107.881 7.008 107.916 7.032 ;
     RECT  107.881 7.032 107.964 7.92 ;
     RECT  107.881 7.92 107.916 7.944 ;
     RECT  107.881 7.944 107.964 8.832 ;
     RECT  107.881 8.832 107.916 8.856 ;
     RECT  107.881 8.856 107.964 9.792 ;
     RECT  107.881 9.792 107.916 9.816 ;
     RECT  107.881 9.816 107.964 10.704 ;
     RECT  107.881 10.704 107.916 10.728 ;
     RECT  107.881 10.728 107.964 11.616 ;
     RECT  107.881 11.616 107.916 11.64 ;
     RECT  107.881 11.64 107.964 12.528 ;
     RECT  107.881 12.528 107.916 12.552 ;
     RECT  107.881 12.552 107.964 13.488 ;
     RECT  107.881 13.488 107.916 13.512 ;
     RECT  107.881 13.512 107.964 14.4 ;
     RECT  107.881 14.4 107.916 14.424 ;
     RECT  107.881 14.424 107.964 15.312 ;
     RECT  107.881 15.312 107.916 15.336 ;
     RECT  107.881 15.336 107.964 16.224 ;
     RECT  107.881 16.224 107.916 16.248 ;
     RECT  107.881 16.248 107.964 17.184 ;
     RECT  107.881 17.184 107.916 17.208 ;
     RECT  107.881 17.208 107.964 18.096 ;
     RECT  107.881 18.096 107.916 18.12 ;
     RECT  107.881 18.12 107.964 19.008 ;
     RECT  107.881 19.008 107.916 19.032 ;
     RECT  107.881 19.032 107.964 19.92 ;
     RECT  107.881 19.92 107.916 19.944 ;
     RECT  107.881 19.944 107.964 20.88 ;
     RECT  107.881 20.88 107.916 20.904 ;
     RECT  107.881 20.904 107.964 21.792 ;
     RECT  107.881 21.792 107.916 21.816 ;
     RECT  107.881 21.816 107.964 22.704 ;
     RECT  107.881 22.704 107.916 22.728 ;
     RECT  107.881 22.728 107.964 23.664 ;
     RECT  107.881 23.664 107.916 23.688 ;
     RECT  107.881 23.688 107.964 24.576 ;
     RECT  107.881 24.576 107.916 24.6 ;
     RECT  107.881 24.6 107.964 25.488 ;
     RECT  107.881 25.488 107.916 25.512 ;
     RECT  107.881 25.512 107.964 26.4 ;
     RECT  107.881 26.4 107.916 26.424 ;
     RECT  107.881 26.424 107.964 27.36 ;
     RECT  107.881 27.36 107.916 27.384 ;
     RECT  107.881 27.384 107.964 28.272 ;
     RECT  107.881 28.272 107.916 28.296 ;
     RECT  107.881 28.296 107.964 29.184 ;
     RECT  107.881 29.184 107.916 29.208 ;
     RECT  107.881 29.208 107.964 30.096 ;
     RECT  107.881 30.096 107.916 30.12 ;
     RECT  107.881 30.12 107.964 31.056 ;
     RECT  107.881 31.056 107.916 31.08 ;
     RECT  107.881 31.08 107.964 31.968 ;
     RECT  107.881 31.968 107.916 31.992 ;
     RECT  107.881 31.992 107.964 32.88 ;
     RECT  107.881 32.88 107.916 32.904 ;
     RECT  107.881 32.904 107.964 33.792 ;
     RECT  107.881 33.792 107.916 33.816 ;
     RECT  107.881 33.816 107.964 34.752 ;
     RECT  107.881 34.752 107.916 34.776 ;
     RECT  107.881 34.776 107.964 35.664 ;
     RECT  107.881 35.664 107.916 35.688 ;
     RECT  107.881 35.688 107.964 36.576 ;
     RECT  107.881 36.576 107.916 36.6 ;
     RECT  107.881 36.6 107.964 37.488 ;
     RECT  107.881 37.488 107.916 37.512 ;
     RECT  107.881 37.512 107.964 38.448 ;
     RECT  107.881 38.448 107.916 38.472 ;
     RECT  107.881 38.472 107.964 39.36 ;
     RECT  107.881 39.36 107.916 39.384 ;
     RECT  107.881 39.384 107.964 40.272 ;
     RECT  107.881 40.272 107.916 40.296 ;
     RECT  107.881 40.296 107.964 41.232 ;
     RECT  107.881 41.232 107.916 41.256 ;
     RECT  107.881 41.256 107.964 42.144 ;
     RECT  107.881 42.144 107.916 42.168 ;
     RECT  107.881 42.168 107.964 43.056 ;
     RECT  107.881 43.056 107.916 43.08 ;
     RECT  107.881 43.08 107.964 43.968 ;
     RECT  107.881 43.968 107.916 43.992 ;
     RECT  107.881 43.992 107.964 44.928 ;
     RECT  107.881 44.928 107.916 44.952 ;
     RECT  107.881 44.952 107.964 45.84 ;
     RECT  107.881 45.84 107.916 45.864 ;
     RECT  107.881 45.864 107.964 46.752 ;
     RECT  107.881 46.752 107.916 46.776 ;
     RECT  107.881 46.776 107.964 47.664 ;
     RECT  107.881 47.664 107.916 47.688 ;
     RECT  107.881 47.688 107.964 48.624 ;
     RECT  107.881 48.624 107.916 48.648 ;
     RECT  107.881 48.648 107.964 49.536 ;
     RECT  107.881 49.536 107.916 49.56 ;
     RECT  107.881 49.56 107.964 50.448 ;
     RECT  107.881 50.448 107.916 50.472 ;
     RECT  107.881 50.472 107.964 51.36 ;
     RECT  107.881 51.36 107.916 51.384 ;
     RECT  107.881 51.384 107.964 52.32 ;
     RECT  107.881 52.32 107.916 52.344 ;
     RECT  107.881 52.344 107.964 53.232 ;
     RECT  107.881 53.232 107.916 53.256 ;
     RECT  107.881 53.256 107.964 54.144 ;
     RECT  107.881 54.144 107.916 54.168 ;
     RECT  107.881 54.168 107.964 55.056 ;
     RECT  107.881 55.056 107.916 55.08 ;
     RECT  107.881 55.08 107.964 56.016 ;
     RECT  107.881 56.016 107.916 56.04 ;
     RECT  107.881 56.04 107.964 56.928 ;
     RECT  107.881 56.928 107.916 56.952 ;
     RECT  107.881 56.952 107.964 57.84 ;
     RECT  107.881 57.84 107.916 57.864 ;
     RECT  107.881 57.864 107.964 58.8 ;
     RECT  107.881 58.8 107.916 58.824 ;
     RECT  107.881 58.824 107.964 59.712 ;
     RECT  107.881 59.712 107.916 59.736 ;
     RECT  107.881 59.736 107.964 60.624 ;
     RECT  107.881 60.624 107.916 60.648 ;
     RECT  107.881 60.648 107.964 61.536 ;
     RECT  107.881 61.536 107.916 61.56 ;
     RECT  107.881 61.56 107.964 62.496 ;
     RECT  107.881 62.496 107.916 62.52 ;
     RECT  107.881 62.52 107.964 63.408 ;
     RECT  107.881 63.408 107.916 63.432 ;
     RECT  107.881 63.432 107.964 64.32 ;
     RECT  107.881 64.32 107.916 64.344 ;
     RECT  107.881 64.344 107.964 65.232 ;
     RECT  107.881 65.232 107.916 65.256 ;
     RECT  107.881 65.256 107.964 66.192 ;
     RECT  107.881 66.192 107.916 66.216 ;
     RECT  107.881 66.216 107.964 67.104 ;
     RECT  107.881 67.104 107.916 67.128 ;
     RECT  107.881 67.128 107.964 68.016 ;
     RECT  107.881 68.016 107.916 68.04 ;
     RECT  107.881 68.04 107.964 68.928 ;
     RECT  107.881 68.928 107.916 68.952 ;
     RECT  107.881 68.952 107.964 69.888 ;
     RECT  107.881 69.888 107.916 69.912 ;
     RECT  107.881 69.912 107.964 70.8 ;
     RECT  107.881 70.8 107.916 70.824 ;
     RECT  107.881 70.824 107.964 71.712 ;
     RECT  107.881 71.712 107.916 71.736 ;
     RECT  107.881 71.736 107.964 72.624 ;
     RECT  107.881 72.624 107.916 72.648 ;
     RECT  107.881 72.648 107.964 73.584 ;
     RECT  107.881 73.584 107.916 73.608 ;
     RECT  107.881 73.608 107.964 74.496 ;
     RECT  107.881 74.496 107.916 74.52 ;
     RECT  107.881 74.52 107.964 75.408 ;
     RECT  107.881 75.408 107.916 75.432 ;
     RECT  107.881 75.432 107.964 76.368 ;
     RECT  107.881 76.368 107.916 76.392 ;
     RECT  107.881 76.392 107.964 77.28 ;
     RECT  107.881 77.28 107.916 77.304 ;
     RECT  107.881 77.304 107.964 78.192 ;
     RECT  107.881 78.192 107.916 78.216 ;
     RECT  107.881 78.216 107.964 79.104 ;
     RECT  107.881 79.104 107.916 79.128 ;
     RECT  107.881 79.128 107.964 80.064 ;
     RECT  107.881 80.064 107.916 80.088 ;
     RECT  107.881 80.088 107.964 80.976 ;
     RECT  107.881 80.976 107.916 81 ;
     RECT  107.881 81 107.964 81.888 ;
     RECT  107.881 81.888 107.916 81.912 ;
     RECT  107.881 81.912 107.964 82.8 ;
     RECT  107.881 82.8 107.916 82.824 ;
     RECT  107.881 82.824 107.964 83.76 ;
     RECT  107.881 83.76 107.916 83.784 ;
     RECT  107.881 83.784 107.964 84.672 ;
     RECT  107.881 84.672 107.916 84.696 ;
     RECT  107.881 84.696 107.964 85.584 ;
     RECT  107.881 85.584 107.916 85.608 ;
     RECT  107.881 85.608 107.964 86.496 ;
     RECT  107.881 86.496 107.916 86.52 ;
     RECT  107.881 86.52 107.964 87.456 ;
     RECT  107.881 87.456 107.916 87.48 ;
     RECT  107.881 87.48 107.964 88.368 ;
     RECT  107.881 88.368 107.916 88.392 ;
     RECT  107.881 88.392 107.964 89.28 ;
     RECT  107.881 89.28 107.916 89.304 ;
     RECT  107.881 89.304 107.964 90.24 ;
     RECT  107.881 90.24 107.916 90.264 ;
     RECT  107.881 90.264 107.964 91.152 ;
     RECT  107.881 91.152 107.916 91.176 ;
     RECT  107.881 91.176 107.964 92.064 ;
     RECT  107.881 92.064 107.916 92.088 ;
     RECT  107.881 92.088 107.964 92.976 ;
     RECT  107.881 92.976 107.916 93 ;
     RECT  107.881 93 107.964 93.936 ;
     RECT  107.881 93.936 107.916 93.96 ;
     RECT  107.881 93.96 107.964 94.848 ;
     RECT  107.881 94.848 107.916 94.872 ;
     RECT  107.881 94.872 107.964 95.76 ;
     RECT  107.881 95.76 107.916 95.784 ;
     RECT  107.881 95.784 107.964 96.672 ;
     RECT  107.881 96.672 107.916 96.696 ;
     RECT  107.881 96.696 107.964 97.632 ;
     RECT  107.881 97.632 107.916 97.656 ;
     RECT  107.881 97.656 107.964 98.544 ;
     RECT  107.881 98.544 107.916 98.568 ;
     RECT  107.881 98.568 107.964 99.456 ;
     RECT  107.881 99.456 107.916 99.48 ;
     RECT  107.881 99.48 107.964 100.368 ;
     RECT  107.881 100.368 107.916 100.392 ;
     RECT  107.881 100.392 107.964 101.328 ;
     RECT  107.881 101.328 107.916 101.352 ;
     RECT  107.881 101.352 107.964 102.24 ;
     RECT  107.881 102.24 107.916 102.264 ;
     RECT  107.881 102.264 107.964 103.152 ;
     RECT  107.881 103.152 107.916 103.176 ;
     RECT  107.881 103.176 107.964 104.064 ;
     RECT  107.881 104.064 107.916 104.088 ;
     RECT  107.881 104.088 107.964 105.024 ;
     RECT  107.881 105.024 107.916 105.048 ;
     RECT  107.881 105.048 107.964 105.936 ;
     RECT  107.881 105.936 107.916 105.96 ;
     RECT  107.881 105.96 107.964 106.848 ;
     RECT  107.881 106.848 107.916 106.872 ;
     RECT  107.881 106.872 107.964 107.808 ;
     RECT  107.881 107.808 107.916 107.832 ;
     RECT  107.881 107.832 107.964 108.72 ;
     RECT  107.881 108.72 107.916 108.744 ;
     RECT  107.881 108.744 107.964 109.632 ;
     RECT  107.881 109.632 107.916 109.656 ;
     RECT  107.881 109.656 107.964 110.544 ;
     RECT  107.881 110.544 107.916 110.568 ;
     RECT  107.881 110.568 107.964 111.504 ;
     RECT  107.881 111.504 107.916 111.528 ;
     RECT  107.881 111.528 107.964 112.416 ;
     RECT  107.881 112.416 107.916 112.44 ;
     RECT  107.881 112.44 107.964 113.328 ;
     RECT  107.881 113.328 107.916 113.352 ;
     RECT  107.881 113.352 107.964 114.24 ;
     RECT  107.881 114.24 107.916 114.264 ;
     RECT  107.881 114.264 107.964 115.2 ;
     RECT  107.881 115.2 107.916 115.224 ;
     RECT  107.881 115.224 107.964 116.112 ;
     RECT  107.881 116.112 107.916 116.136 ;
     RECT  107.881 116.136 107.964 117.024 ;
     RECT  107.881 117.024 107.916 117.048 ;
     RECT  107.881 117.048 107.964 117.936 ;
     RECT  107.881 117.936 107.916 117.96 ;
     RECT  107.881 117.96 107.964 118.896 ;
     RECT  107.881 118.896 107.916 118.92 ;
     RECT  107.881 118.92 107.964 119.808 ;
     RECT  107.881 119.808 107.916 119.832 ;
     RECT  107.881 119.832 107.964 120.72 ;
     RECT  107.881 120.72 107.916 120.744 ;
     RECT  107.881 120.744 107.964 121.632 ;
     RECT  107.881 121.632 107.916 121.656 ;
     RECT  107.881 121.656 107.964 122.592 ;
     RECT  107.881 122.592 107.916 122.616 ;
     RECT  107.881 122.616 107.964 123.504 ;
     RECT  107.881 123.504 107.916 123.528 ;
     RECT  107.881 123.528 107.964 124.416 ;
     RECT  107.881 124.416 107.916 124.44 ;
     RECT  107.881 124.44 107.964 125.376 ;
     RECT  107.881 125.376 107.916 125.4 ;
     RECT  107.881 125.4 107.964 126.288 ;
     RECT  107.881 126.288 107.916 126.312 ;
     RECT  107.881 126.312 107.964 127.2 ;
     RECT  107.881 127.2 107.916 127.224 ;
     RECT  107.881 127.224 107.964 128.112 ;
     RECT  107.881 128.112 107.916 128.136 ;
     RECT  107.964 128.016 107.993 128.04 ;
    LAYER M5 ;
     RECT  1.272 0.016 1.776 0.084 ;
     RECT  1.8 0.016 2.304 0.084 ;
     RECT  2.328 0.016 2.832 0.084 ;
     RECT  2.856 0.016 3.36 0.084 ;
     RECT  3.384 0.016 3.888 0.084 ;
     RECT  3.912 0.016 4.416 0.084 ;
     RECT  4.44 0.016 4.944 0.084 ;
     RECT  4.968 0.016 5.472 0.084 ;
     RECT  5.496 0.016 6 0.084 ;
     RECT  6.024 0.016 6.576 0.084 ;
     RECT  6.6 0.016 7.104 0.084 ;
     RECT  7.128 0.016 7.632 0.084 ;
     RECT  7.656 0.016 8.16 0.084 ;
     RECT  8.184 0.016 8.688 0.084 ;
     RECT  8.712 0.016 9.216 0.084 ;
     RECT  9.24 0.016 9.744 0.084 ;
     RECT  9.768 0.016 10.272 0.084 ;
     RECT  10.296 0.016 10.8 0.084 ;
     RECT  10.824 0.016 11.328 0.084 ;
     RECT  11.352 0.016 11.856 0.084 ;
     RECT  11.88 0.016 12.384 0.084 ;
     RECT  12.408 0.016 12.912 0.084 ;
     RECT  12.936 0.016 13.44 0.084 ;
     RECT  13.464 0.016 13.968 0.084 ;
     RECT  13.992 0.016 14.496 0.084 ;
     RECT  14.52 0.016 15.024 0.084 ;
     RECT  15.048 0.016 15.552 0.084 ;
     RECT  15.576 0.016 16.08 0.084 ;
     RECT  16.104 0.016 16.608 0.084 ;
     RECT  16.632 0.016 17.136 0.084 ;
     RECT  17.16 0.016 17.664 0.084 ;
     RECT  17.688 0.016 18.192 0.084 ;
     RECT  18.216 0.016 18.72 0.084 ;
     RECT  18.744 0.016 19.296 0.084 ;
     RECT  19.32 0.016 19.824 0.084 ;
     RECT  19.848 0.016 20.352 0.084 ;
     RECT  20.376 0.016 20.88 0.084 ;
     RECT  20.904 0.016 21.408 0.084 ;
     RECT  21.432 0.016 21.936 0.084 ;
     RECT  21.96 0.016 22.464 0.084 ;
     RECT  22.488 0.016 22.992 0.084 ;
     RECT  23.016 0.016 23.52 0.084 ;
     RECT  23.544 0.016 24.048 0.084 ;
     RECT  24.072 0.016 24.576 0.084 ;
     RECT  24.6 0.016 25.104 0.084 ;
     RECT  25.128 0.016 25.632 0.084 ;
     RECT  25.656 0.016 26.16 0.084 ;
     RECT  26.184 0.016 26.688 0.084 ;
     RECT  26.712 0.016 27.216 0.084 ;
     RECT  27.24 0.016 27.744 0.084 ;
     RECT  27.768 0.016 28.272 0.084 ;
     RECT  28.296 0.016 28.8 0.084 ;
     RECT  28.824 0.016 29.328 0.084 ;
     RECT  29.352 0.016 29.856 0.084 ;
     RECT  29.88 0.016 30.384 0.084 ;
     RECT  30.408 0.016 30.912 0.084 ;
     RECT  30.936 0.016 31.44 0.084 ;
     RECT  31.464 0.016 32.016 0.084 ;
     RECT  32.04 0.016 32.544 0.084 ;
     RECT  32.568 0.016 33.072 0.084 ;
     RECT  33.096 0.016 33.6 0.084 ;
     RECT  33.624 0.016 34.128 0.084 ;
     RECT  34.152 0.016 34.656 0.084 ;
     RECT  34.68 0.016 35.184 0.084 ;
     RECT  35.208 0.016 35.712 0.084 ;
     RECT  35.736 0.016 36.24 0.084 ;
     RECT  36.264 0.016 36.768 0.084 ;
     RECT  36.792 0.016 37.296 0.084 ;
     RECT  37.32 0.016 37.824 0.084 ;
     RECT  37.848 0.016 38.352 0.084 ;
     RECT  38.376 0.016 38.88 0.084 ;
     RECT  38.904 0.016 39.408 0.084 ;
     RECT  39.432 0.016 39.936 0.084 ;
     RECT  39.96 0.016 40.464 0.084 ;
     RECT  40.488 0.016 40.992 0.084 ;
     RECT  41.016 0.016 41.52 0.084 ;
     RECT  41.544 0.016 42.048 0.084 ;
     RECT  42.072 0.016 42.576 0.084 ;
     RECT  42.6 0.016 43.104 0.084 ;
     RECT  43.128 0.016 43.632 0.084 ;
     RECT  43.656 0.016 44.16 0.084 ;
     RECT  44.184 0.016 44.736 0.084 ;
     RECT  44.76 0.016 45.264 0.084 ;
     RECT  45.288 0.016 45.792 0.084 ;
     RECT  45.816 0.016 46.32 0.084 ;
     RECT  46.344 0.016 46.848 0.084 ;
     RECT  46.872 0.016 47.376 0.084 ;
     RECT  47.4 0.016 47.904 0.084 ;
     RECT  47.928 0.016 48.432 0.084 ;
     RECT  48.456 0.016 48.96 0.084 ;
     RECT  48.984 0.016 49.488 0.084 ;
     RECT  49.512 0.016 50.016 0.084 ;
     RECT  50.04 0.016 50.544 0.084 ;
     RECT  50.568 0.016 51.072 0.084 ;
     RECT  51.096 0.016 51.6 0.084 ;
     RECT  51.624 0.016 52.128 0.084 ;
     RECT  52.152 0.016 52.656 0.084 ;
     RECT  52.68 0.016 53.184 0.084 ;
     RECT  53.208 0.016 53.712 0.084 ;
     RECT  53.736 0.016 54.24 0.084 ;
     RECT  54.264 0.016 54.768 0.084 ;
     RECT  54.792 0.016 55.296 0.084 ;
     RECT  55.32 0.016 55.824 0.084 ;
     RECT  55.848 0.016 56.352 0.084 ;
     RECT  56.376 0.016 56.88 0.084 ;
     RECT  56.904 0.016 57.456 0.084 ;
     RECT  57.48 0.016 57.984 0.084 ;
     RECT  58.008 0.016 58.512 0.084 ;
     RECT  58.536 0.016 59.04 0.084 ;
     RECT  59.064 0.016 59.568 0.084 ;
     RECT  59.592 0.016 60.096 0.084 ;
     RECT  60.12 0.016 60.624 0.084 ;
     RECT  60.648 0.016 61.152 0.084 ;
     RECT  61.176 0.016 61.68 0.084 ;
     RECT  61.704 0.016 62.208 0.084 ;
     RECT  62.232 0.016 62.736 0.084 ;
     RECT  62.76 0.016 63.264 0.084 ;
     RECT  63.288 0.016 63.792 0.084 ;
     RECT  63.816 0.016 64.32 0.084 ;
     RECT  64.344 0.016 64.848 0.084 ;
     RECT  64.872 0.016 65.376 0.084 ;
     RECT  65.4 0.016 65.904 0.084 ;
     RECT  65.928 0.016 66.432 0.084 ;
     RECT  66.456 0.016 66.96 0.084 ;
     RECT  66.984 0.016 67.488 0.084 ;
     RECT  67.512 0.016 68.016 0.084 ;
     RECT  68.04 0.016 68.544 0.084 ;
     RECT  68.568 0.016 69.072 0.084 ;
     RECT  69.096 0.016 69.6 0.084 ;
     RECT  69.624 0.016 70.176 0.084 ;
     RECT  70.2 0.016 70.704 0.084 ;
     RECT  70.728 0.016 71.232 0.084 ;
     RECT  71.256 0.016 71.76 0.084 ;
     RECT  71.784 0.016 72.288 0.084 ;
     RECT  72.312 0.016 72.816 0.084 ;
     RECT  72.84 0.016 73.344 0.084 ;
     RECT  73.368 0.016 73.872 0.084 ;
     RECT  73.896 0.016 74.4 0.084 ;
     RECT  74.424 0.016 74.928 0.084 ;
     RECT  74.952 0.016 75.456 0.084 ;
     RECT  75.48 0.016 75.984 0.084 ;
     RECT  76.008 0.016 76.512 0.084 ;
     RECT  76.536 0.016 77.04 0.084 ;
     RECT  77.064 0.016 77.568 0.084 ;
     RECT  77.592 0.016 78.096 0.084 ;
     RECT  78.12 0.016 78.624 0.084 ;
     RECT  78.648 0.016 79.152 0.084 ;
     RECT  79.176 0.016 79.68 0.084 ;
     RECT  79.704 0.016 80.208 0.084 ;
     RECT  80.232 0.016 80.736 0.084 ;
     RECT  80.76 0.016 81.264 0.084 ;
     RECT  81.288 0.016 81.792 0.084 ;
     RECT  81.816 0.016 82.32 0.084 ;
     RECT  82.344 0.016 82.896 0.084 ;
     RECT  82.92 0.016 83.424 0.084 ;
     RECT  83.448 0.016 83.952 0.084 ;
     RECT  83.976 0.016 84.48 0.084 ;
     RECT  84.504 0.016 85.008 0.084 ;
     RECT  85.032 0.016 85.536 0.084 ;
     RECT  85.56 0.016 86.064 0.084 ;
     RECT  86.088 0.016 86.592 0.084 ;
     RECT  86.616 0.016 87.12 0.084 ;
     RECT  87.144 0.016 87.648 0.084 ;
     RECT  87.672 0.016 88.176 0.084 ;
     RECT  88.2 0.016 88.704 0.084 ;
     RECT  88.728 0.016 89.232 0.084 ;
     RECT  89.256 0.016 89.76 0.084 ;
     RECT  89.784 0.016 90.288 0.084 ;
     RECT  90.312 0.016 90.816 0.084 ;
     RECT  90.84 0.016 91.344 0.084 ;
     RECT  91.368 0.016 91.872 0.084 ;
     RECT  91.896 0.016 92.4 0.084 ;
     RECT  92.424 0.016 92.928 0.084 ;
     RECT  92.952 0.016 93.456 0.084 ;
     RECT  93.48 0.016 93.984 0.084 ;
     RECT  94.008 0.016 94.512 0.084 ;
     RECT  94.536 0.016 95.04 0.084 ;
     RECT  95.064 0.016 95.616 0.084 ;
     RECT  95.64 0.016 96.144 0.084 ;
     RECT  96.168 0.016 96.672 0.084 ;
     RECT  96.696 0.016 97.2 0.084 ;
     RECT  97.224 0.016 97.728 0.084 ;
     RECT  97.752 0.016 98.256 0.084 ;
     RECT  98.28 0.016 98.784 0.084 ;
     RECT  98.808 0.016 99.312 0.084 ;
     RECT  99.336 0.016 99.84 0.084 ;
     RECT  99.864 0.016 100.368 0.084 ;
     RECT  100.392 0.016 100.896 0.084 ;
     RECT  100.92 0.016 101.424 0.084 ;
     RECT  101.448 0.016 101.952 0.084 ;
     RECT  101.976 0.016 102.48 0.084 ;
     RECT  102.504 0.016 103.008 0.084 ;
     RECT  103.032 0.016 103.536 0.084 ;
     RECT  103.56 0.016 104.064 0.084 ;
     RECT  104.088 0.016 104.592 0.084 ;
     RECT  104.616 0.016 105.12 0.084 ;
     RECT  105.144 0.016 105.648 0.084 ;
     RECT  105.672 0.016 106.176 0.084 ;
     RECT  106.2 0.016 106.704 0.084 ;
     RECT  1.248 0.084 106.728 0.131 ;
     RECT  1.776 0.131 2.856 0.179 ;
     RECT  4.416 0.131 4.44 0.179 ;
     RECT  8.688 0.131 9.24 0.179 ;
     RECT  101.424 0.131 101.976 0.179 ;
     RECT  2.304 0.179 2.856 0.227 ;
     RECT  105.648 0.131 106.728 0.227 ;
     RECT  2.832 0.227 2.856 0.563 ;
     RECT  11.856 0.131 12.408 0.563 ;
     RECT  17.664 0.131 19.32 0.563 ;
     RECT  27.216 0.131 28.824 0.563 ;
     RECT  35.184 0.131 36.264 0.563 ;
     RECT  38.88 0.131 38.904 0.563 ;
     RECT  43.632 0.131 45.288 0.563 ;
     RECT  51.072 0.131 51.096 0.563 ;
     RECT  70.176 0.131 70.728 0.563 ;
     RECT  71.76 0.131 73.896 0.563 ;
     RECT  90.288 0.131 90.84 0.563 ;
     RECT  92.928 0.131 93.48 0.563 ;
     RECT  100.368 0.131 100.392 0.563 ;
     RECT  101.952 0.179 101.976 0.563 ;
     RECT  104.592 0.131 104.616 0.563 ;
     RECT  106.176 0.227 106.728 0.563 ;
     RECT  10.272 0.131 10.824 0.611 ;
     RECT  12.384 0.563 12.408 0.611 ;
     RECT  16.08 0.131 16.632 0.611 ;
     RECT  17.664 0.563 18.744 0.611 ;
     RECT  25.104 0.131 25.656 0.611 ;
     RECT  27.216 0.563 28.296 0.611 ;
     RECT  29.856 0.131 30.408 0.611 ;
     RECT  32.016 0.131 32.04 0.611 ;
     RECT  33.072 0.131 33.096 0.611 ;
     RECT  35.184 0.563 35.736 0.611 ;
     RECT  37.296 0.131 37.32 0.611 ;
     RECT  39.936 0.131 39.96 0.611 ;
     RECT  43.632 0.563 44.76 0.611 ;
     RECT  46.32 0.131 46.344 0.611 ;
     RECT  48.96 0.131 48.984 0.611 ;
     RECT  52.128 0.131 52.152 0.611 ;
     RECT  53.712 0.131 53.736 0.611 ;
     RECT  54.768 0.131 54.792 0.611 ;
     RECT  55.824 0.131 55.848 0.611 ;
     RECT  57.984 0.131 58.008 0.611 ;
     RECT  59.04 0.131 59.064 0.611 ;
     RECT  61.152 0.131 62.232 0.611 ;
     RECT  67.488 0.131 68.568 0.611 ;
     RECT  70.176 0.563 70.2 0.611 ;
     RECT  73.872 0.563 73.896 0.611 ;
     RECT  74.928 0.131 74.952 0.611 ;
     RECT  75.984 0.131 76.008 0.611 ;
     RECT  82.32 0.131 82.344 0.611 ;
     RECT  85.008 0.131 85.032 0.611 ;
     RECT  86.064 0.131 86.088 0.611 ;
     RECT  91.872 0.131 91.896 0.611 ;
     RECT  92.928 0.563 92.952 0.611 ;
     RECT  97.728 0.131 97.752 0.611 ;
     RECT  90.816 0.563 90.84 0.659 ;
     RECT  72.816 0.563 72.84 1.139 ;
     RECT  83.424 0.131 83.448 1.139 ;
     RECT  9.216 0.179 9.24 1.187 ;
     RECT  10.8 0.611 10.824 1.187 ;
     RECT  16.608 0.611 16.632 1.187 ;
     RECT  18.72 0.611 18.744 1.187 ;
     RECT  20.88 0.131 20.904 1.187 ;
     RECT  22.992 0.131 23.544 1.187 ;
     RECT  25.632 0.611 25.656 1.187 ;
     RECT  27.216 0.611 27.24 1.187 ;
     RECT  40.992 0.131 41.544 1.187 ;
     RECT  43.632 0.611 43.656 1.187 ;
     RECT  47.904 0.131 47.928 1.187 ;
     RECT  50.016 0.131 50.04 1.187 ;
     RECT  56.88 0.131 56.904 1.187 ;
     RECT  65.376 0.131 65.4 1.187 ;
     RECT  68.016 0.611 68.568 1.187 ;
     RECT  71.76 0.563 71.784 1.187 ;
     RECT  79.152 0.131 79.176 1.187 ;
     RECT  68.544 1.187 68.568 1.283 ;
     RECT  7.632 0.131 7.656 1.379 ;
     RECT  13.44 0.131 13.464 2.137 ;
     RECT  2.4 2.137 2.52 2.151 ;
     RECT  7.8 2.137 7.92 2.151 ;
     RECT  13.2 2.137 13.464 2.151 ;
     RECT  18.6 2.137 18.72 2.151 ;
     RECT  24 2.137 24.12 2.151 ;
     RECT  29.4 2.137 29.52 2.151 ;
     RECT  34.8 2.137 34.92 2.151 ;
     RECT  40.2 2.137 40.32 2.151 ;
     RECT  45.6 2.137 45.72 2.151 ;
     RECT  51 2.137 51.12 2.151 ;
     RECT  56.4 2.137 56.52 2.151 ;
     RECT  61.8 2.137 61.92 2.151 ;
     RECT  67.2 2.137 67.32 2.151 ;
     RECT  72.6 2.137 72.72 2.151 ;
     RECT  78 2.137 78.12 2.151 ;
     RECT  83.4 2.137 83.52 2.151 ;
     RECT  88.8 2.137 88.92 2.151 ;
     RECT  94.2 2.137 94.32 2.151 ;
     RECT  99.6 2.137 99.72 2.151 ;
     RECT  105 2.137 105.12 2.151 ;
     RECT  34.8 2.151 35.112 3.109 ;
     RECT  51 2.151 51.312 3.109 ;
     RECT  45.6 2.151 45.912 3.301 ;
     RECT  24 2.151 24.312 3.349 ;
     RECT  40.2 2.151 40.512 3.349 ;
     RECT  56.4 2.151 56.712 3.349 ;
     RECT  37.92 3.349 37.944 3.589 ;
     RECT  45.6 3.301 46.632 3.589 ;
     RECT  18.6 2.151 18.912 3.685 ;
     RECT  36.96 3.589 37.944 3.685 ;
     RECT  83.4 2.151 83.712 3.685 ;
     RECT  44.88 3.589 46.632 3.731 ;
     RECT  23.808 3.349 24.312 3.733 ;
     RECT  36.864 3.685 37.944 3.733 ;
     RECT  45.312 3.731 46.632 3.733 ;
     RECT  57.936 3.349 57.96 3.733 ;
     RECT  42.144 3.397 42.168 3.829 ;
     RECT  29.4 2.151 29.712 3.877 ;
     RECT  34.8 3.109 35.304 3.877 ;
     RECT  72.6 2.151 72.912 3.877 ;
     RECT  36.864 3.733 38.472 3.925 ;
     RECT  39.984 3.349 40.512 3.925 ;
     RECT  43.872 3.349 43.896 3.925 ;
     RECT  49.056 3.397 49.08 3.925 ;
     RECT  50.88 3.109 51.312 3.925 ;
     RECT  57.936 3.733 58.68 3.925 ;
     RECT  23.808 3.733 24.648 3.971 ;
     RECT  82.608 3.685 83.712 3.971 ;
     RECT  57.936 3.925 58.824 4.019 ;
     RECT  72.48 3.877 72.912 4.019 ;
     RECT  80.592 3.349 80.616 4.019 ;
     RECT  106.704 0.563 106.728 4.019 ;
     RECT  13.2 2.151 13.512 4.117 ;
     RECT  15.072 3.925 15.096 4.117 ;
     RECT  18.192 3.685 18.912 4.117 ;
     RECT  96.144 3.349 96.168 4.163 ;
     RECT  13.2 4.117 15.096 4.213 ;
     RECT  45.312 3.733 47.544 4.213 ;
     RECT  10.656 3.973 10.68 4.259 ;
     RECT  12.816 4.213 15.096 4.259 ;
     RECT  39.984 3.925 41.016 4.261 ;
     RECT  42.144 3.829 42.744 4.261 ;
     RECT  55.584 3.349 56.712 4.261 ;
     RECT  61.8 2.151 62.112 4.261 ;
     RECT  78 2.151 78.312 4.357 ;
     RECT  4.176 3.685 4.2 4.501 ;
     RECT  7.8 2.151 8.112 4.501 ;
     RECT  49.056 3.925 49.56 4.501 ;
     RECT  50.88 3.925 51.432 4.501 ;
     RECT  58.656 4.019 58.824 4.501 ;
     RECT  60.096 3.301 60.12 4.501 ;
     RECT  61.536 4.261 62.232 4.501 ;
     RECT  29.4 3.877 29.832 4.595 ;
     RECT  64.176 4.501 65.496 4.645 ;
     RECT  94.2 2.151 94.512 4.645 ;
     RECT  2.4 2.151 2.712 4.693 ;
     RECT  4.176 4.501 4.488 4.693 ;
     RECT  39.984 4.261 42.744 4.741 ;
     RECT  43.872 3.925 44.232 4.741 ;
     RECT  94.2 4.645 95.304 4.787 ;
     RECT  53.856 4.501 53.88 5.029 ;
     RECT  58.656 4.501 60.12 5.029 ;
     RECT  61.2 4.501 62.232 5.029 ;
     RECT  45.312 4.213 47.88 5.077 ;
     RECT  49.056 4.501 51.432 5.077 ;
     RECT  53.04 5.029 53.88 5.077 ;
     RECT  55.2 4.261 56.712 5.077 ;
     RECT  58.032 5.029 62.232 5.077 ;
     RECT  22.704 4.981 22.728 5.171 ;
     RECT  102.672 3.973 102.696 5.171 ;
     RECT  52.464 5.077 56.712 5.317 ;
     RECT  52.464 5.317 56.952 5.459 ;
     RECT  45.312 5.077 51.432 5.653 ;
     RECT  52.464 5.459 55.224 5.653 ;
     RECT  12.816 4.259 14.232 5.747 ;
     RECT  78 4.357 78.744 5.987 ;
     RECT  58.032 5.077 62.808 6.133 ;
     RECT  64.176 4.645 65.544 6.133 ;
     RECT  67.2 2.151 67.512 6.133 ;
     RECT  2.4 4.693 4.488 6.229 ;
     RECT  17.616 4.117 18.912 6.323 ;
     RECT  58.032 6.133 65.544 6.323 ;
     RECT  64.512 6.323 65.544 6.659 ;
     RECT  45.312 5.653 55.224 6.709 ;
     RECT  56.4 5.459 56.952 6.709 ;
     RECT  21.12 4.501 21.144 7.235 ;
     RECT  12.816 5.747 13.512 7.333 ;
     RECT  19.968 4.693 19.992 7.379 ;
     RECT  24 3.971 24.648 7.379 ;
     RECT  58.032 6.323 63.432 7.381 ;
     RECT  64.512 6.659 65.496 7.381 ;
     RECT  78 5.987 78.696 7.667 ;
     RECT  66.672 6.133 67.512 8.003 ;
     RECT  45.312 6.709 56.952 8.293 ;
     RECT  58.032 7.381 65.496 8.293 ;
     RECT  2.4 6.229 4.776 8.339 ;
     RECT  45.312 8.293 65.496 8.341 ;
     RECT  67.2 8.003 67.512 8.437 ;
     RECT  68.784 5.989 68.808 8.437 ;
     RECT  67.2 8.437 68.808 8.483 ;
     RECT  7.8 4.501 8.52 9.731 ;
     RECT  12.528 7.333 13.512 10.643 ;
     RECT  45.312 8.341 65.736 10.883 ;
     RECT  39.984 4.741 44.232 10.979 ;
     RECT  45.312 10.883 64.44 11.027 ;
     RECT  67.2 8.483 68.424 11.171 ;
     RECT  42.624 10.979 44.232 11.365 ;
     RECT  45.312 11.027 64.104 11.365 ;
     RECT  39.984 10.979 41.496 11.941 ;
     RECT  42.624 11.365 64.104 11.941 ;
     RECT  36.864 3.925 38.904 12.517 ;
     RECT  39.984 11.941 64.104 12.517 ;
     RECT  36.864 12.517 64.104 13.043 ;
     RECT  36.864 13.043 59.544 13.139 ;
     RECT  2.4 8.339 4.632 13.811 ;
     RECT  31.968 6.517 31.992 14.147 ;
     RECT  36.864 13.139 41.496 14.197 ;
     RECT  42.672 13.139 59.544 14.197 ;
     RECT  36.864 14.197 59.544 15.683 ;
     RECT  3.696 13.811 4.632 15.829 ;
     RECT  6.288 4.501 6.408 15.829 ;
     RECT  3.696 15.829 6.408 15.875 ;
     RECT  2.4 13.811 2.712 16.405 ;
     RECT  3.696 15.875 4.488 16.405 ;
     RECT  7.8 9.731 8.232 16.595 ;
     RECT  36.864 15.683 46.296 16.595 ;
     RECT  38.448 16.595 46.296 17.029 ;
     RECT  47.328 15.683 59.544 17.029 ;
     RECT  38.448 17.029 59.544 17.315 ;
     RECT  36.864 16.595 37.464 17.605 ;
     RECT  38.448 17.315 48.744 17.605 ;
     RECT  36.864 17.605 48.744 17.651 ;
     RECT  49.728 17.315 59.544 17.699 ;
     RECT  43.488 17.651 48.744 17.891 ;
     RECT  58.32 17.699 59.544 18.275 ;
     RECT  60.624 13.043 64.104 18.419 ;
     RECT  34.272 3.877 35.304 18.709 ;
     RECT  58.32 18.275 58.344 18.851 ;
     RECT  60.624 18.419 62.112 18.851 ;
     RECT  65.712 10.883 65.736 18.851 ;
     RECT  29.4 4.595 29.712 18.949 ;
     RECT  63.216 18.419 64.104 19.139 ;
     RECT  36.864 17.651 42.408 19.333 ;
     RECT  43.488 17.891 48.36 19.333 ;
     RECT  49.728 17.699 52.728 19.333 ;
     RECT  34.272 18.709 35.88 19.909 ;
     RECT  36.864 19.333 52.728 19.909 ;
     RECT  34.272 19.909 52.728 19.957 ;
     RECT  53.808 17.699 54.264 19.957 ;
     RECT  34.272 19.957 54.264 20.003 ;
     RECT  55.296 17.699 57.336 20.003 ;
     RECT  59.52 18.275 59.544 20.003 ;
     RECT  63.216 19.139 63.864 20.003 ;
     RECT  34.272 20.003 44.568 20.579 ;
     RECT  45.6 20.003 54.264 20.579 ;
     RECT  55.296 20.003 56.712 20.579 ;
     RECT  63.84 20.003 63.864 20.579 ;
     RECT  42.912 20.579 44.568 20.627 ;
     RECT  60.768 18.851 62.112 20.627 ;
     RECT  28.464 18.949 29.712 20.773 ;
     RECT  27.936 20.773 29.712 20.819 ;
     RECT  55.296 20.579 55.32 20.819 ;
     RECT  34.272 20.579 41.592 21.155 ;
     RECT  45.6 20.579 48.504 21.155 ;
     RECT  49.728 20.579 54.264 21.155 ;
     RECT  60.768 20.627 60.792 21.155 ;
     RECT  52.464 21.155 53.352 21.395 ;
     RECT  2.4 16.405 4.488 21.683 ;
     RECT  42.912 20.627 42.936 21.683 ;
     RECT  44.496 20.627 44.568 21.683 ;
     RECT  45.6 21.155 48.024 21.683 ;
     RECT  49.728 21.155 51.312 21.683 ;
     RECT  52.464 21.395 52.68 21.683 ;
     RECT  36.72 21.155 41.592 21.923 ;
     RECT  34.272 21.155 35.352 22.165 ;
     RECT  36.72 21.923 38.424 22.211 ;
     RECT  45.6 21.683 46.584 22.259 ;
     RECT  50.88 21.683 51.312 22.259 ;
     RECT  44.544 21.683 44.568 22.835 ;
     RECT  48 21.683 48.024 22.835 ;
     RECT  7.8 16.595 8.112 23.173 ;
     RECT  27.936 20.819 27.96 23.315 ;
     RECT  39.456 21.923 41.496 23.317 ;
     RECT  5.472 15.875 6.408 23.363 ;
     RECT  39.36 23.317 41.496 23.701 ;
     RECT  72.6 4.019 72.912 25.477 ;
     RECT  24 7.379 24.312 25.573 ;
     RECT  10.8 23.317 10.824 26.675 ;
     RECT  3.744 21.683 4.488 27.205 ;
     RECT  5.472 23.363 6.312 27.205 ;
     RECT  18.6 6.323 18.912 27.301 ;
     RECT  12 27.877 12.024 28.451 ;
     RECT  18.6 27.301 19.416 28.547 ;
     RECT  34.272 22.165 35.592 28.597 ;
     RECT  3.744 27.205 6.312 28.883 ;
     RECT  33.648 28.597 35.592 29.029 ;
     RECT  71.76 25.477 72.912 30.083 ;
     RECT  71.808 30.083 72.912 30.371 ;
     RECT  18.6 28.547 18.912 31.861 ;
     RECT  33.024 29.029 35.592 32.387 ;
     RECT  33.024 32.387 33.048 34.741 ;
     RECT  2.4 21.683 2.712 35.269 ;
     RECT  3.744 28.883 5.784 35.269 ;
     RECT  2.4 35.269 5.784 35.315 ;
     RECT  7.8 23.173 8.376 40.883 ;
     RECT  0.144 3.877 0.168 41.411 ;
     RECT  34.272 32.387 35.592 41.939 ;
     RECT  2.4 35.315 3.48 42.227 ;
     RECT  33.024 34.741 33.24 45.109 ;
     RECT  34.32 41.939 35.592 45.157 ;
     RECT  36.72 22.211 37.944 45.157 ;
     RECT  34.32 45.157 37.944 45.299 ;
     RECT  32.592 45.109 33.24 45.301 ;
     RECT  4.608 35.315 5.784 46.693 ;
     RECT  4.608 46.693 5.88 48.229 ;
     RECT  24 25.573 24.84 51.205 ;
     RECT  15.216 28.453 15.24 52.499 ;
     RECT  4.608 48.229 6.12 54.035 ;
     RECT  36.72 45.299 37.944 55.907 ;
     RECT  7.8 40.883 8.232 56.003 ;
     RECT  39.36 23.701 42.168 56.147 ;
     RECT  39.456 56.147 42.168 56.771 ;
     RECT  34.32 45.299 35.592 57.059 ;
     RECT  4.608 54.035 4.632 57.635 ;
     RECT  24 51.205 25.08 57.875 ;
     RECT  39.456 56.771 41.64 58.691 ;
     RECT  36.864 55.907 37.944 58.739 ;
     RECT  39.456 58.691 41.496 58.739 ;
     RECT  6.096 54.035 6.12 59.315 ;
     RECT  40.2 58.739 41.496 59.315 ;
     RECT  40.2 59.315 40.512 60.373 ;
     RECT  36.864 58.739 37.56 60.467 ;
     RECT  39.36 60.373 40.512 60.661 ;
     RECT  39.36 60.661 41.208 60.949 ;
     RECT  39.168 60.949 41.4 61.093 ;
     RECT  32.256 45.301 33.24 61.139 ;
     RECT  27.744 40.549 27.768 61.187 ;
     RECT  36.912 60.467 37.56 61.237 ;
     RECT  39.168 61.093 42.36 61.237 ;
     RECT  36.912 61.237 42.36 61.573 ;
     RECT  36.912 61.573 43.32 62.195 ;
     RECT  99.6 2.151 99.912 62.581 ;
     RECT  36.96 62.195 43.32 63.011 ;
     RECT  94.2 4.787 94.512 63.541 ;
     RECT  7.8 56.003 8.112 63.781 ;
     RECT  102.768 61.525 102.792 64.259 ;
     RECT  36.96 63.011 42.36 65.027 ;
     RECT  2.4 42.227 2.712 66.085 ;
     RECT  49.008 65.509 49.032 66.227 ;
     RECT  2.304 66.085 2.712 67.283 ;
     RECT  2.4 67.283 2.712 67.669 ;
     RECT  32.592 61.139 33.24 68.675 ;
     RECT  3.84 67.765 3.864 69.011 ;
     RECT  2.4 67.669 2.856 69.829 ;
     RECT  47.52 67.621 47.544 70.835 ;
     RECT  2.4 69.829 3.624 70.933 ;
     RECT  21.888 42.805 21.912 71.221 ;
     RECT  37.008 65.027 42.36 71.315 ;
     RECT  44.448 71.221 44.472 71.509 ;
     RECT  52.464 21.683 52.488 71.509 ;
     RECT  54.576 67.429 54.6 71.555 ;
     RECT  2.4 70.933 3.768 71.797 ;
     RECT  34.32 57.059 35.112 72.035 ;
     RECT  33.216 68.675 33.24 72.179 ;
     RECT  43.92 71.509 44.472 72.325 ;
     RECT  45.6 22.259 45.912 72.325 ;
     RECT  52.464 71.509 53.16 72.419 ;
     RECT  21.888 71.221 22.488 72.421 ;
     RECT  67.2 11.171 67.512 72.421 ;
     RECT  43.92 72.325 45.912 73.043 ;
     RECT  43.92 73.043 43.944 73.523 ;
     RECT  18.6 31.861 19.32 73.907 ;
     RECT  2.4 71.797 4.488 74.053 ;
     RECT  51 22.259 51.312 75.205 ;
     RECT  6.048 61.765 6.072 75.299 ;
     RECT  37.008 71.315 41.88 75.541 ;
     RECT  6.096 75.541 6.12 77.701 ;
     RECT  7.248 63.781 8.112 77.701 ;
     RECT  6.096 77.701 8.112 77.747 ;
     RECT  21.696 72.421 22.488 77.797 ;
     RECT  37.008 75.541 41.976 78.469 ;
     RECT  37.008 78.469 42.312 79.573 ;
     RECT  2.4 74.053 4.536 80.197 ;
     RECT  21.6 77.797 22.488 80.435 ;
     RECT  36.96 79.573 42.312 80.531 ;
     RECT  21.696 80.435 22.488 80.917 ;
     RECT  21.696 80.917 22.584 81.059 ;
     RECT  6.48 77.747 8.112 81.587 ;
     RECT  36.96 80.531 39.192 82.021 ;
     RECT  40.2 80.531 42.312 82.021 ;
     RECT  2.4 80.197 4.824 83.125 ;
     RECT  6.528 81.587 8.112 83.125 ;
     RECT  2.4 83.125 8.112 86.675 ;
     RECT  7.152 86.675 8.112 89.413 ;
     RECT  99.6 62.581 100.008 91.141 ;
     RECT  102 91.093 102.024 91.235 ;
     RECT  5.616 86.675 6.168 91.477 ;
     RECT  103.968 64.213 103.992 91.477 ;
     RECT  5.52 91.477 6.168 91.523 ;
     RECT  103.824 91.477 103.992 91.523 ;
     RECT  36.96 82.021 42.312 92.293 ;
     RECT  7.152 89.413 8.76 93.251 ;
     RECT  2.4 86.675 4.536 94.691 ;
     RECT  5.52 91.523 5.64 95.557 ;
     RECT  10.176 74.629 10.2 95.651 ;
     RECT  18.6 73.907 18.912 95.701 ;
     RECT  5.52 95.557 6.312 95.795 ;
     RECT  2.4 94.691 3.576 96.853 ;
     RECT  36.672 92.293 42.312 97.571 ;
     RECT  37.488 97.571 42.312 98.099 ;
     RECT  7.68 93.251 8.76 99.013 ;
     RECT  37.488 98.099 40.632 99.779 ;
     RECT  7.44 99.013 8.76 100.741 ;
     RECT  7.44 100.741 9.24 100.789 ;
     RECT  69.216 94.501 69.24 101.269 ;
     RECT  69.216 101.269 69.432 101.315 ;
     RECT  72.6 30.371 72.912 101.317 ;
     RECT  51 75.205 51.864 101.747 ;
     RECT  2.4 96.853 4.536 102.419 ;
     RECT  7.296 100.789 9.24 103.523 ;
     RECT  99.6 91.141 100.104 103.763 ;
     RECT  69.408 101.315 69.432 105.397 ;
     RECT  72.6 101.317 73.224 105.925 ;
     RECT  5.52 95.795 5.544 106.021 ;
     RECT  5.328 106.021 5.544 106.067 ;
     RECT  69.408 105.397 69.528 106.501 ;
     RECT  69.024 106.501 69.528 106.547 ;
     RECT  53.136 72.419 53.16 107.219 ;
     RECT  67.2 72.421 67.704 107.795 ;
     RECT  39.168 99.779 40.632 108.323 ;
     RECT  69.024 106.547 69.432 108.323 ;
     RECT  69.408 108.323 69.432 108.371 ;
     RECT  67.2 107.795 67.656 108.899 ;
     RECT  72.6 105.925 73.32 109.285 ;
     RECT  26.208 107.509 26.232 109.909 ;
     RECT  26.208 109.909 26.472 109.955 ;
     RECT  42.288 98.099 42.312 110.051 ;
     RECT  2.4 102.419 4.296 110.579 ;
     RECT  72.6 109.285 73.704 110.579 ;
     RECT  93.84 63.541 94.512 111.155 ;
     RECT  103.824 91.523 103.848 111.493 ;
     RECT  103.2 111.493 103.848 111.539 ;
     RECT  2.4 110.579 4.2 111.779 ;
     RECT  79.776 110.533 79.8 112.115 ;
     RECT  99.6 103.763 100.056 112.117 ;
     RECT  26.448 109.955 26.472 112.163 ;
     RECT  78 7.667 78.312 112.213 ;
     RECT  45.12 73.043 45.912 113.027 ;
     RECT  5.328 106.067 5.352 113.459 ;
     RECT  77.472 112.213 78.312 113.653 ;
     RECT  2.4 111.779 3.48 114.611 ;
     RECT  79.872 114.517 79.896 114.659 ;
     RECT  103.2 111.539 103.224 115.187 ;
     RECT  55.248 109.957 55.272 116.195 ;
     RECT  72.6 110.579 73.32 116.963 ;
     RECT  86.112 115.333 86.136 117.011 ;
     RECT  99.504 112.117 100.056 117.011 ;
     RECT  7.296 103.523 8.76 117.443 ;
     RECT  92.592 111.109 92.616 118.067 ;
     RECT  92.496 118.549 92.52 119.027 ;
     RECT  99.504 117.011 99.912 119.507 ;
     RECT  97.824 104.245 97.848 120.085 ;
     RECT  37.488 99.779 37.56 121.475 ;
     RECT  5.136 120.229 5.16 121.571 ;
     RECT  37.536 121.475 37.56 122.003 ;
     RECT  95.76 111.013 95.784 122.579 ;
     RECT  97.44 120.085 97.848 122.627 ;
     RECT  7.8 117.443 8.76 123.637 ;
     RECT  102.624 121.957 102.648 124.019 ;
     RECT  24 57.875 24.312 124.021 ;
     RECT  26.208 124.021 26.232 124.117 ;
     RECT  22.416 81.059 22.584 124.163 ;
     RECT  23.904 124.021 24.312 124.163 ;
     RECT  24 124.163 24.312 124.645 ;
     RECT  67.2 108.899 67.512 124.789 ;
     RECT  77.088 113.653 78.312 124.789 ;
     RECT  97.728 122.627 97.848 124.789 ;
     RECT  7.392 123.637 8.76 124.883 ;
     RECT  72.6 116.963 73.176 124.883 ;
     RECT  18.6 95.701 19.032 125.027 ;
     RECT  28.272 124.645 28.296 125.029 ;
     RECT  29.4 20.819 29.712 125.029 ;
     RECT  26.112 124.117 26.232 125.123 ;
     RECT  22.416 124.163 22.488 125.125 ;
     RECT  22.416 125.125 22.776 125.171 ;
     RECT  26.112 125.123 26.136 125.171 ;
     RECT  24 124.645 24.408 125.221 ;
     RECT  83.4 3.971 83.712 125.221 ;
     RECT  22.752 125.171 22.776 125.315 ;
     RECT  5.184 121.957 5.208 125.363 ;
     RECT  48.432 124.789 48.456 125.365 ;
     RECT  24 125.221 24.984 125.411 ;
     RECT  77.088 124.789 79.272 125.411 ;
     RECT  40.08 108.323 40.632 125.459 ;
     RECT  100.896 123.637 100.92 125.459 ;
     RECT  11.424 125.077 11.448 125.651 ;
     RECT  7.392 124.883 8.112 125.747 ;
     RECT  28.272 125.029 29.712 125.747 ;
     RECT  48 125.365 48.456 125.795 ;
     RECT  24 125.411 24.312 125.797 ;
     RECT  67.2 124.789 68.376 125.843 ;
     RECT  37.296 124.405 37.32 125.893 ;
     RECT  23.904 125.797 24.312 125.939 ;
     RECT  49.872 125.365 49.896 125.939 ;
     RECT  82.416 125.221 83.712 125.939 ;
     RECT  91.2 124.789 91.224 125.987 ;
     RECT  37.296 125.893 38.232 126.035 ;
     RECT  77.088 125.411 78.696 126.035 ;
     RECT  103.344 124.213 103.368 126.035 ;
     RECT  63.216 125.413 63.24 126.131 ;
     RECT  97.728 124.789 98.04 126.131 ;
     RECT  48 125.795 48.024 126.179 ;
     RECT  70.08 125.413 70.104 126.179 ;
     RECT  77.088 126.035 78.312 126.179 ;
     RECT  98.016 126.131 98.04 126.179 ;
     RECT  28.704 125.747 29.712 127.043 ;
     RECT  2.4 114.611 2.712 127.449 ;
     RECT  7.8 125.747 8.112 127.449 ;
     RECT  13.2 10.643 13.512 127.449 ;
     RECT  18.6 125.027 18.912 127.449 ;
     RECT  24 125.939 24.312 127.449 ;
     RECT  29.4 127.043 29.712 127.449 ;
     RECT  34.8 72.035 35.112 127.449 ;
     RECT  83.4 125.939 83.712 127.449 ;
     RECT  88.8 2.151 89.112 127.449 ;
     RECT  94.2 111.155 94.512 127.449 ;
     RECT  105 2.151 105.312 127.449 ;
     RECT  2.4 127.449 2.52 127.463 ;
     RECT  13.2 127.449 13.32 127.463 ;
     RECT  18.6 127.449 18.72 127.463 ;
     RECT  24 127.449 24.12 127.463 ;
     RECT  29.4 127.449 29.52 127.463 ;
     RECT  34.8 127.449 34.92 127.463 ;
     RECT  45.6 113.027 45.912 127.463 ;
     RECT  51 101.747 51.312 127.463 ;
     RECT  56.4 20.579 56.712 127.463 ;
     RECT  61.8 20.627 62.112 127.463 ;
     RECT  78 126.179 78.312 127.463 ;
     RECT  83.4 127.449 83.52 127.463 ;
     RECT  88.8 127.449 88.92 127.463 ;
     RECT  94.2 127.449 94.32 127.463 ;
     RECT  99.6 119.507 99.912 127.463 ;
     RECT  105 127.449 105.12 127.463 ;
     RECT  103.68 127.381 103.704 127.621 ;
     RECT  7.8 127.449 7.992 128.197 ;
     RECT  13.152 127.669 13.176 128.197 ;
     RECT  40.2 125.459 40.512 128.197 ;
     RECT  67.2 125.843 67.512 128.197 ;
     RECT  72.6 124.883 72.912 128.197 ;
     RECT  3.552 128.197 5.064 128.773 ;
     RECT  6.528 128.197 7.992 128.773 ;
     RECT  52.896 128.197 52.92 128.773 ;
     RECT  54.336 128.197 54.36 128.773 ;
     RECT  32.256 128.197 32.28 128.821 ;
     RECT  57.312 128.197 57.336 128.821 ;
     RECT  99.984 128.197 100.008 128.821 ;
     RECT  29.328 128.197 29.352 129.397 ;
     RECT  2.112 129.397 2.136 129.445 ;
     RECT  3.552 128.773 7.992 129.445 ;
     RECT  9.456 128.197 13.176 129.445 ;
     RECT  14.592 127.669 15.384 129.445 ;
     RECT  16.8 128.197 18.312 129.445 ;
     RECT  19.776 128.197 20.52 129.445 ;
     RECT  21.984 128.197 23.448 129.445 ;
     RECT  25.632 128.197 27.144 129.445 ;
     RECT  28.608 129.397 29.352 129.445 ;
     RECT  30.816 128.245 30.84 129.445 ;
     RECT  32.256 128.821 33.048 129.445 ;
     RECT  34.464 128.197 34.488 129.445 ;
     RECT  35.952 128.197 35.976 129.445 ;
     RECT  37.44 128.197 41.88 129.445 ;
     RECT  43.296 128.197 44.808 129.445 ;
     RECT  46.272 128.197 49.944 129.445 ;
     RECT  51.408 127.669 51.432 129.445 ;
     RECT  52.896 128.773 54.36 129.445 ;
     RECT  56.544 128.821 57.336 129.445 ;
     RECT  58.752 128.197 58.776 129.445 ;
     RECT  60.24 128.197 60.984 129.445 ;
     RECT  62.448 128.197 67.608 129.445 ;
     RECT  69.792 128.197 70.584 129.445 ;
     RECT  72 128.197 75 129.445 ;
     RECT  76.416 128.197 77.208 129.445 ;
     RECT  78.672 128.197 78.696 129.445 ;
     RECT  83.088 129.205 83.112 129.445 ;
     RECT  85.296 128.197 85.32 129.445 ;
     RECT  86.736 129.397 86.76 129.445 ;
     RECT  90.432 128.197 90.456 129.445 ;
     RECT  91.92 128.197 94.152 129.445 ;
     RECT  96.336 128.197 96.36 129.445 ;
     RECT  98.544 129.397 98.568 129.445 ;
     RECT  99.984 128.821 100.776 129.445 ;
     RECT  102.192 127.621 103.704 129.445 ;
     RECT  106.608 128.821 106.632 129.445 ;
     RECT  1.344 129.445 106.632 129.516 ;
     RECT  1.368 129.516 2.112 129.552 ;
     RECT  2.136 129.516 2.832 129.552 ;
     RECT  2.856 129.516 3.552 129.552 ;
     RECT  3.576 129.516 4.32 129.552 ;
     RECT  4.344 129.516 5.04 129.552 ;
     RECT  5.064 129.516 5.76 129.552 ;
     RECT  5.784 129.516 6.528 129.552 ;
     RECT  6.552 129.516 7.248 129.552 ;
     RECT  7.272 129.516 7.968 129.552 ;
     RECT  7.992 129.516 8.736 129.552 ;
     RECT  8.76 129.516 9.456 129.552 ;
     RECT  9.48 129.516 10.176 129.552 ;
     RECT  10.2 129.516 10.944 129.552 ;
     RECT  10.968 129.516 11.664 129.552 ;
     RECT  11.688 129.516 12.384 129.552 ;
     RECT  12.408 129.516 13.152 129.552 ;
     RECT  13.176 129.516 13.872 129.552 ;
     RECT  13.896 129.516 14.592 129.552 ;
     RECT  14.616 129.516 15.36 129.552 ;
     RECT  15.384 129.516 16.08 129.552 ;
     RECT  16.104 129.516 16.8 129.552 ;
     RECT  16.824 129.516 17.568 129.552 ;
     RECT  17.592 129.516 18.288 129.552 ;
     RECT  18.312 129.516 19.008 129.552 ;
     RECT  19.032 129.516 19.776 129.552 ;
     RECT  19.8 129.516 20.496 129.552 ;
     RECT  20.52 129.516 21.216 129.552 ;
     RECT  21.24 129.516 21.984 129.552 ;
     RECT  22.008 129.516 22.704 129.552 ;
     RECT  22.728 129.516 23.424 129.552 ;
     RECT  23.448 129.516 24.192 129.552 ;
     RECT  24.216 129.516 24.912 129.552 ;
     RECT  24.936 129.516 25.632 129.552 ;
     RECT  25.656 129.516 26.4 129.552 ;
     RECT  26.424 129.516 27.12 129.552 ;
     RECT  27.144 129.516 27.84 129.552 ;
     RECT  27.864 129.516 28.608 129.552 ;
     RECT  28.632 129.516 29.328 129.552 ;
     RECT  29.352 129.516 30.048 129.552 ;
     RECT  30.072 129.516 30.816 129.552 ;
     RECT  30.84 129.516 31.536 129.552 ;
     RECT  31.56 129.516 32.256 129.552 ;
     RECT  32.28 129.516 33.024 129.552 ;
     RECT  33.048 129.516 33.744 129.552 ;
     RECT  33.768 129.516 34.464 129.552 ;
     RECT  34.488 129.516 35.232 129.552 ;
     RECT  35.256 129.516 35.952 129.552 ;
     RECT  35.976 129.516 36.672 129.552 ;
     RECT  36.696 129.516 37.44 129.552 ;
     RECT  37.464 129.516 38.16 129.552 ;
     RECT  38.184 129.516 38.88 129.552 ;
     RECT  38.904 129.516 39.648 129.552 ;
     RECT  39.672 129.516 40.368 129.552 ;
     RECT  40.392 129.516 41.088 129.552 ;
     RECT  41.112 129.516 41.856 129.552 ;
     RECT  41.88 129.516 42.576 129.552 ;
     RECT  42.6 129.516 43.296 129.552 ;
     RECT  43.32 129.516 44.064 129.552 ;
     RECT  44.088 129.516 44.784 129.552 ;
     RECT  44.808 129.516 45.504 129.552 ;
     RECT  45.528 129.516 46.272 129.552 ;
     RECT  46.296 129.516 46.992 129.552 ;
     RECT  47.016 129.516 47.712 129.552 ;
     RECT  47.736 129.516 48.48 129.552 ;
     RECT  48.504 129.516 49.2 129.552 ;
     RECT  49.224 129.516 49.92 129.552 ;
     RECT  49.944 129.516 50.688 129.552 ;
     RECT  50.712 129.516 51.408 129.552 ;
     RECT  51.432 129.516 52.128 129.552 ;
     RECT  52.152 129.516 52.896 129.552 ;
     RECT  52.92 129.516 53.616 129.552 ;
     RECT  53.64 129.516 54.336 129.552 ;
     RECT  54.36 129.516 55.104 129.552 ;
     RECT  55.128 129.516 55.824 129.552 ;
     RECT  55.848 129.516 56.544 129.552 ;
     RECT  56.568 129.516 57.312 129.552 ;
     RECT  57.336 129.516 58.032 129.552 ;
     RECT  58.056 129.516 58.752 129.552 ;
     RECT  58.776 129.516 59.52 129.552 ;
     RECT  59.544 129.516 60.24 129.552 ;
     RECT  60.264 129.516 60.96 129.552 ;
     RECT  60.984 129.516 61.728 129.552 ;
     RECT  61.752 129.516 62.448 129.552 ;
     RECT  62.472 129.516 63.168 129.552 ;
     RECT  63.192 129.516 63.936 129.552 ;
     RECT  63.96 129.516 64.656 129.552 ;
     RECT  64.68 129.516 65.376 129.552 ;
     RECT  65.4 129.516 66.144 129.552 ;
     RECT  66.168 129.516 66.864 129.552 ;
     RECT  66.888 129.516 67.584 129.552 ;
     RECT  67.608 129.516 68.352 129.552 ;
     RECT  68.376 129.516 69.072 129.552 ;
     RECT  69.096 129.516 69.792 129.552 ;
     RECT  69.816 129.516 70.56 129.552 ;
     RECT  70.584 129.516 71.28 129.552 ;
     RECT  71.304 129.516 72 129.552 ;
     RECT  72.024 129.516 72.768 129.552 ;
     RECT  72.792 129.516 73.488 129.552 ;
     RECT  73.512 129.516 74.208 129.552 ;
     RECT  74.232 129.516 74.976 129.552 ;
     RECT  75 129.516 75.696 129.552 ;
     RECT  75.72 129.516 76.416 129.552 ;
     RECT  76.44 129.516 77.184 129.552 ;
     RECT  77.208 129.516 77.904 129.552 ;
     RECT  77.928 129.516 78.672 129.552 ;
     RECT  78.696 129.516 79.392 129.552 ;
     RECT  79.416 129.516 80.112 129.552 ;
     RECT  80.136 129.516 80.88 129.552 ;
     RECT  80.904 129.516 81.6 129.552 ;
     RECT  81.624 129.516 82.32 129.552 ;
     RECT  82.344 129.516 83.088 129.552 ;
     RECT  83.112 129.516 83.808 129.552 ;
     RECT  83.832 129.516 84.528 129.552 ;
     RECT  84.552 129.516 85.296 129.552 ;
     RECT  85.32 129.516 86.016 129.552 ;
     RECT  86.04 129.516 86.736 129.552 ;
     RECT  86.76 129.516 87.504 129.552 ;
     RECT  87.528 129.516 88.224 129.552 ;
     RECT  88.248 129.516 88.944 129.552 ;
     RECT  88.968 129.516 89.712 129.552 ;
     RECT  89.736 129.516 90.432 129.552 ;
     RECT  90.456 129.516 91.152 129.552 ;
     RECT  91.176 129.516 91.92 129.552 ;
     RECT  91.944 129.516 92.64 129.552 ;
     RECT  92.664 129.516 93.36 129.552 ;
     RECT  93.384 129.516 94.128 129.552 ;
     RECT  94.152 129.516 94.848 129.552 ;
     RECT  94.872 129.516 95.568 129.552 ;
     RECT  95.592 129.516 96.336 129.552 ;
     RECT  96.36 129.516 97.056 129.552 ;
     RECT  97.08 129.516 97.776 129.552 ;
     RECT  97.8 129.516 98.544 129.552 ;
     RECT  98.568 129.516 99.264 129.552 ;
     RECT  99.288 129.516 99.984 129.552 ;
     RECT  100.008 129.516 100.752 129.552 ;
     RECT  100.776 129.516 101.472 129.552 ;
     RECT  101.496 129.516 102.192 129.552 ;
     RECT  102.216 129.516 102.96 129.552 ;
     RECT  102.984 129.516 103.68 129.552 ;
     RECT  103.704 129.516 104.4 129.552 ;
     RECT  104.424 129.516 105.168 129.552 ;
     RECT  105.192 129.516 105.888 129.552 ;
     RECT  105.912 129.516 106.608 129.552 ;
     RECT  7.752 0.131 8.064 0.179 ;
     RECT  8.28 0.131 8.592 0.179 ;
     RECT  9.336 0.131 9.648 0.18 ;
     RECT  9.864 0.131 10.176 0.18 ;
     RECT  10.92 0.131 11.232 0.18 ;
     RECT  11.448 0.131 11.76 0.18 ;
     RECT  12.504 0.131 12.816 0.18 ;
     RECT  13.032 0.131 13.344 0.18 ;
     RECT  16.728 0.131 17.04 0.18 ;
     RECT  17.256 0.131 17.568 0.18 ;
     RECT  28.92 0.131 29.232 0.18 ;
     RECT  29.448 0.131 29.76 0.18 ;
     RECT  32.136 0.131 32.448 0.18 ;
     RECT  32.664 0.131 32.976 0.18 ;
     RECT  36.36 0.131 36.672 0.18 ;
     RECT  36.888 0.131 37.2 0.18 ;
     RECT  39 0.131 39.312 0.18 ;
     RECT  39.528 0.131 39.84 0.18 ;
     RECT  40.056 0.131 40.368 0.18 ;
     RECT  40.584 0.131 40.896 0.18 ;
     RECT  45.384 0.131 45.696 0.18 ;
     RECT  45.912 0.131 46.224 0.18 ;
     RECT  48.024 0.131 48.336 0.18 ;
     RECT  48.552 0.131 48.864 0.18 ;
     RECT  49.08 0.131 49.392 0.18 ;
     RECT  49.608 0.131 49.92 0.18 ;
     RECT  50.136 0.131 50.448 0.18 ;
     RECT  50.664 0.131 50.976 0.18 ;
     RECT  51.192 0.131 51.504 0.18 ;
     RECT  51.72 0.131 52.032 0.18 ;
     RECT  53.832 0.131 54.144 0.18 ;
     RECT  54.36 0.131 54.672 0.18 ;
     RECT  54.888 0.131 55.2 0.18 ;
     RECT  55.416 0.131 55.728 0.18 ;
     RECT  55.944 0.131 56.256 0.18 ;
     RECT  56.472 0.131 56.784 0.18 ;
     RECT  57 0.131 57.36 0.18 ;
     RECT  57.576 0.131 57.888 0.18 ;
     RECT  58.104 0.131 58.416 0.18 ;
     RECT  58.632 0.131 58.944 0.18 ;
     RECT  70.824 0.131 71.136 0.18 ;
     RECT  71.352 0.131 71.664 0.18 ;
     RECT  73.992 0.131 74.304 0.18 ;
     RECT  74.52 0.131 74.832 0.18 ;
     RECT  75.048 0.131 75.36 0.18 ;
     RECT  75.576 0.131 75.888 0.18 ;
     RECT  82.44 0.131 82.8 0.18 ;
     RECT  83.016 0.131 83.328 0.18 ;
     RECT  85.128 0.131 85.44 0.18 ;
     RECT  85.656 0.131 85.968 0.18 ;
     RECT  90.936 0.131 91.248 0.18 ;
     RECT  91.464 0.131 91.776 0.18 ;
     RECT  91.992 0.131 92.304 0.18 ;
     RECT  92.52 0.131 92.832 0.18 ;
     RECT  100.488 0.131 100.8 0.179 ;
     RECT  101.016 0.131 101.328 0.179 ;
     RECT  104.712 0.131 105.024 0.18 ;
     RECT  105.24 0.131 105.552 0.18 ;
     RECT  9.24 0.18 10.272 0.611 ;
     RECT  10.824 0.18 11.856 0.563 ;
     RECT  12.408 0.18 13.44 0.611 ;
     RECT  16.632 0.18 17.664 0.611 ;
     RECT  28.824 0.18 29.856 0.563 ;
     RECT  32.04 0.18 33.072 0.611 ;
     RECT  36.264 0.18 37.296 0.563 ;
     RECT  38.904 0.18 39.936 0.563 ;
     RECT  39.96 0.18 40.992 0.611 ;
     RECT  45.288 0.18 46.32 0.563 ;
     RECT  47.928 0.18 48.96 0.611 ;
     RECT  48.984 0.18 50.016 0.611 ;
     RECT  50.04 0.18 51.072 0.563 ;
     RECT  51.096 0.18 52.128 0.563 ;
     RECT  53.736 0.18 54.768 0.611 ;
     RECT  54.792 0.18 55.824 0.611 ;
     RECT  55.848 0.18 56.88 0.611 ;
     RECT  56.904 0.18 57.984 0.611 ;
     RECT  58.008 0.18 59.04 0.611 ;
     RECT  70.728 0.18 71.76 0.563 ;
     RECT  73.896 0.18 74.928 0.611 ;
     RECT  74.952 0.18 75.984 0.611 ;
     RECT  82.344 0.18 83.424 0.611 ;
     RECT  85.032 0.18 86.064 0.611 ;
     RECT  90.84 0.18 91.872 0.611 ;
     RECT  91.896 0.18 92.928 0.611 ;
     RECT  104.616 0.18 105.648 0.227 ;
     RECT  71.784 0.563 72.816 1.139 ;
     RECT  72.84 0.563 73.872 0.611 ;
     RECT  13.2 0.611 13.44 2.137 ;
     RECT  18.6 0.611 18.72 1.187 ;
     RECT  40.2 0.611 40.992 1.187 ;
     RECT  56.4 0.611 56.88 1.187 ;
     RECT  61.8 0.611 61.92 2.137 ;
     RECT  83.4 0.611 83.424 1.139 ;
     RECT  71.784 1.139 72.84 1.187 ;
     RECT  83.4 1.139 83.448 2.137 ;
     RECT  18.6 1.187 18.744 2.137 ;
     RECT  40.2 1.187 40.512 2.137 ;
     RECT  56.4 1.187 56.712 2.137 ;
     RECT  72.6 1.187 72.84 2.137 ;
     RECT  18.72 2.137 18.744 2.151 ;
     RECT  40.32 2.137 40.512 2.151 ;
     RECT  56.52 2.137 56.712 2.151 ;
     RECT  72.72 2.137 72.84 2.151 ;
     RECT  105.312 2.151 106.704 4.019 ;
     RECT  56.712 3.349 57.936 4.019 ;
     RECT  43.896 3.589 44.88 3.731 ;
     RECT  2.712 3.685 4.176 4.693 ;
     RECT  43.896 3.731 45.312 3.925 ;
     RECT  38.472 3.733 39.984 3.925 ;
     RECT  47.544 3.733 49.056 4.213 ;
     RECT  58.68 3.733 60.096 3.925 ;
     RECT  42.744 3.829 43.872 4.741 ;
     RECT  38.904 3.925 39.984 12.517 ;
     RECT  41.016 3.925 42.144 4.261 ;
     RECT  44.232 3.925 45.312 11.365 ;
     RECT  49.56 3.925 50.88 4.501 ;
     RECT  58.824 3.925 60.096 4.501 ;
     RECT  23.808 3.971 24 4.981 ;
     RECT  56.712 4.019 58.656 5.029 ;
     RECT  47.88 4.213 49.056 5.077 ;
     RECT  60.12 4.261 61.536 4.501 ;
     RECT  6.408 4.501 7.8 23.363 ;
     RECT  53.88 4.501 55.2 5.077 ;
     RECT  60.12 4.501 61.2 5.029 ;
     RECT  18.912 4.693 19.968 7.379 ;
     RECT  19.992 4.693 21.12 7.235 ;
     RECT  22.728 4.981 24 5.171 ;
     RECT  56.712 5.029 58.032 5.317 ;
     RECT  51.432 5.077 52.464 5.653 ;
     RECT  62.808 5.077 64.176 6.133 ;
     RECT  56.952 5.317 58.032 8.293 ;
     RECT  55.224 5.459 56.4 6.709 ;
     RECT  67.512 5.989 68.784 8.437 ;
     RECT  65.544 6.133 66.672 6.659 ;
     RECT  4.776 6.229 6.288 8.339 ;
     RECT  63.432 6.323 64.512 7.381 ;
     RECT  65.496 6.659 66.672 8.003 ;
     RECT  65.496 8.003 67.2 8.341 ;
     RECT  65.736 8.341 67.2 18.851 ;
     RECT  64.44 10.883 65.712 11.027 ;
     RECT  41.496 10.979 42.624 11.941 ;
     RECT  59.544 13.043 60.624 18.851 ;
     RECT  41.496 13.139 42.672 14.197 ;
     RECT  2.712 13.811 3.696 16.405 ;
     RECT  46.296 15.683 47.328 17.029 ;
     RECT  4.488 15.875 5.472 27.205 ;
     RECT  37.464 16.595 38.448 17.605 ;
     RECT  48.744 17.315 49.728 17.891 ;
     RECT  42.408 17.651 43.488 19.333 ;
     RECT  52.728 17.699 53.808 19.957 ;
     RECT  54.264 17.699 55.296 20.819 ;
     RECT  57.336 17.699 58.32 18.851 ;
     RECT  48.36 17.891 49.728 19.333 ;
     RECT  58.344 18.275 59.52 18.851 ;
     RECT  62.112 18.419 63.216 20.003 ;
     RECT  35.88 18.709 36.864 19.909 ;
     RECT  59.544 18.851 60.768 20.003 ;
     RECT  44.568 20.003 45.6 22.835 ;
     RECT  41.592 20.579 42.912 21.683 ;
     RECT  48.504 20.579 49.728 21.155 ;
     RECT  55.32 20.579 56.4 20.819 ;
     RECT  60.792 20.627 61.8 21.155 ;
     RECT  27.96 20.819 29.4 23.315 ;
     RECT  35.352 21.155 36.72 22.165 ;
     RECT  51.312 21.155 52.464 72.419 ;
     RECT  2.712 21.683 3.744 35.269 ;
     RECT  46.584 21.683 48 22.259 ;
     RECT  38.424 21.923 39.456 22.211 ;
     RECT  35.592 22.165 36.72 45.157 ;
     RECT  37.944 22.211 39.456 23.317 ;
     RECT  37.944 23.317 39.36 56.147 ;
     RECT  6.312 23.363 7.8 28.883 ;
     RECT  12.024 27.877 13.2 28.451 ;
     RECT  33.048 32.387 34.272 34.741 ;
     RECT  33.24 34.741 34.272 41.939 ;
     RECT  3.48 35.315 4.608 42.227 ;
     RECT  33.24 41.939 34.32 72.035 ;
     RECT  35.592 45.299 36.72 55.907 ;
     RECT  4.632 54.035 6.096 57.635 ;
     RECT  35.592 55.907 36.864 57.059 ;
     RECT  37.944 56.147 39.456 58.739 ;
     RECT  40.512 59.315 41.208 60.661 ;
     RECT  6.072 63.781 7.248 75.299 ;
     RECT  102.792 64.213 103.968 64.259 ;
     RECT  103.992 64.213 105 91.523 ;
     RECT  2.856 67.765 3.84 69.011 ;
     RECT  2.856 69.011 3.624 69.829 ;
     RECT  22.488 71.221 24 80.917 ;
     RECT  44.472 71.221 45.6 72.325 ;
     RECT  53.16 71.509 54.576 71.555 ;
     RECT  43.944 73.043 45.12 73.523 ;
     RECT  4.536 74.053 6.048 75.299 ;
     RECT  51.864 75.205 53.136 101.747 ;
     RECT  6.096 75.299 7.248 75.541 ;
     RECT  6.12 75.541 7.248 77.701 ;
     RECT  39.192 80.531 40.2 82.021 ;
     RECT  22.584 80.917 24 124.021 ;
     RECT  4.536 86.675 5.616 91.477 ;
     RECT  6.168 86.675 7.152 91.523 ;
     RECT  8.76 89.413 10.176 95.651 ;
     RECT  4.536 91.477 5.52 94.691 ;
     RECT  5.64 91.523 7.152 93.251 ;
     RECT  103.848 91.523 105 111.539 ;
     RECT  67.704 94.501 69.216 101.315 ;
     RECT  6.312 95.557 7.68 95.795 ;
     RECT  4.536 96.853 5.52 102.419 ;
     RECT  4.296 102.419 5.52 106.021 ;
     RECT  4.296 106.021 5.328 110.579 ;
     RECT  67.704 106.501 69.024 107.795 ;
     RECT  67.656 107.795 69.024 108.323 ;
     RECT  55.272 109.957 56.4 116.195 ;
     RECT  78.312 110.533 79.776 112.115 ;
     RECT  4.2 110.579 5.328 111.779 ;
     RECT  94.512 111.013 95.76 122.579 ;
     RECT  92.616 111.109 93.84 111.155 ;
     RECT  99.912 123.637 100.896 125.459 ;
     RECT  22.584 124.021 23.904 124.163 ;
     RECT  22.488 124.163 24 125.125 ;
     RECT  28.296 124.645 29.4 125.029 ;
     RECT  22.776 125.125 24 125.315 ;
     RECT  23.904 125.315 24 125.797 ;
     RECT  48.456 125.365 49.872 125.795 ;
     RECT  49.896 125.365 51 125.939 ;
     RECT  62.112 125.413 63.216 126.131 ;
     RECT  29.328 127.043 29.4 127.463 ;
     RECT  103.704 127.381 105 127.463 ;
     RECT  7.992 127.449 8.112 128.197 ;
     RECT  13.32 127.449 13.512 127.463 ;
     RECT  18.72 127.449 18.912 127.463 ;
     RECT  29.52 127.449 29.712 127.463 ;
     RECT  34.92 127.449 35.112 127.463 ;
     RECT  13.2 127.463 13.512 127.669 ;
     RECT  18.6 127.463 18.912 128.197 ;
     RECT  29.328 127.463 29.712 128.197 ;
     RECT  34.8 127.463 35.112 128.197 ;
     RECT  45.6 127.463 45.912 128.197 ;
     RECT  51 127.463 51.312 127.669 ;
     RECT  56.544 127.463 56.712 128.197 ;
     RECT  61.8 127.463 62.112 128.197 ;
     RECT  78 127.463 78.312 128.197 ;
     RECT  13.176 127.669 14.592 129.42 ;
     RECT  51 127.669 51.408 128.197 ;
     RECT  5.064 128.197 6.528 128.773 ;
     RECT  7.992 128.197 9.456 129.42 ;
     RECT  15.384 128.197 16.8 129.42 ;
     RECT  18.312 128.197 19.776 129.42 ;
     RECT  20.52 128.197 21.984 129.42 ;
     RECT  29.352 128.197 29.712 128.245 ;
     RECT  34.488 128.197 35.952 129.42 ;
     RECT  35.976 128.197 37.44 129.42 ;
     RECT  41.88 128.197 43.296 129.42 ;
     RECT  44.808 128.197 46.272 129.42 ;
     RECT  49.944 128.197 51.408 129.42 ;
     RECT  51.432 128.197 52.896 129.42 ;
     RECT  52.92 128.197 54.336 128.773 ;
     RECT  56.544 128.197 57.312 128.821 ;
     RECT  57.336 128.197 58.752 129.42 ;
     RECT  58.776 128.197 60.24 129.42 ;
     RECT  60.984 128.197 62.448 129.42 ;
     RECT  70.584 128.197 72 129.42 ;
     RECT  75 128.197 76.416 129.42 ;
     RECT  77.208 128.197 78.672 129.42 ;
     RECT  90.456 128.197 91.92 129.42 ;
     RECT  29.352 128.245 30.816 129.42 ;
     RECT  30.84 128.245 32.256 129.42 ;
     RECT  33.048 128.821 34.464 129.42 ;
     RECT  100.776 128.821 102.192 129.42 ;
     RECT  2.136 129.397 3.552 129.42 ;
     RECT  27.144 129.397 28.608 129.42 ;
     RECT  85.32 129.397 86.736 129.42 ;
     RECT  98.568 129.397 99.984 129.42 ;
     RECT  2.232 129.42 2.736 129.445 ;
     RECT  2.952 129.42 3.456 129.445 ;
     RECT  8.088 129.42 8.64 129.445 ;
     RECT  8.856 129.42 9.36 129.445 ;
     RECT  13.272 129.42 13.776 129.445 ;
     RECT  13.992 129.42 14.496 129.445 ;
     RECT  15.48 129.42 15.984 129.445 ;
     RECT  16.2 129.42 16.704 129.445 ;
     RECT  18.408 129.42 18.912 129.445 ;
     RECT  19.128 129.42 19.68 129.445 ;
     RECT  20.616 129.42 21.12 129.445 ;
     RECT  21.336 129.42 21.888 129.445 ;
     RECT  27.24 129.42 27.744 129.445 ;
     RECT  27.96 129.42 28.512 129.445 ;
     RECT  29.448 129.42 29.952 129.445 ;
     RECT  30.168 129.42 30.72 129.445 ;
     RECT  30.936 129.42 31.44 129.445 ;
     RECT  31.656 129.42 32.16 129.445 ;
     RECT  33.144 129.42 33.648 129.445 ;
     RECT  33.864 129.42 34.368 129.445 ;
     RECT  34.584 129.42 35.136 129.445 ;
     RECT  35.352 129.42 35.856 129.445 ;
     RECT  36.072 129.42 36.576 129.445 ;
     RECT  36.792 129.42 37.344 129.445 ;
     RECT  41.976 129.42 42.48 129.445 ;
     RECT  42.696 129.42 43.2 129.445 ;
     RECT  44.904 129.42 45.408 129.445 ;
     RECT  45.624 129.42 46.176 129.445 ;
     RECT  50.04 129.42 50.592 129.445 ;
     RECT  50.808 129.42 51.312 129.445 ;
     RECT  51.528 129.42 52.032 129.445 ;
     RECT  52.248 129.42 52.8 129.445 ;
     RECT  57.432 129.42 57.936 129.445 ;
     RECT  58.152 129.42 58.656 129.445 ;
     RECT  58.872 129.42 59.424 129.445 ;
     RECT  59.64 129.42 60.144 129.445 ;
     RECT  61.08 129.42 61.632 129.445 ;
     RECT  61.848 129.42 62.352 129.445 ;
     RECT  70.68 129.42 71.184 129.445 ;
     RECT  71.4 129.42 71.904 129.445 ;
     RECT  75.096 129.42 75.6 129.445 ;
     RECT  75.816 129.42 76.32 129.445 ;
     RECT  77.304 129.42 77.808 129.445 ;
     RECT  78.024 129.42 78.576 129.445 ;
     RECT  85.416 129.42 85.92 129.445 ;
     RECT  86.136 129.42 86.64 129.445 ;
     RECT  90.552 129.42 91.056 129.445 ;
     RECT  91.272 129.42 91.824 129.445 ;
     RECT  98.664 129.42 99.168 129.445 ;
     RECT  99.384 129.42 99.888 129.445 ;
     RECT  100.872 129.42 101.376 129.445 ;
     RECT  101.592 129.42 102.096 129.445 ;
  END
END ot_hgi_qdq_transport_ctl_r4
END LIBRARY
